VERSION 5.8 ;
BUSBITCHARS "[]" ;
DIVIDERCHAR "/" ;
UNITS
    DATABASE MICRONS 1000 ;
END UNITS

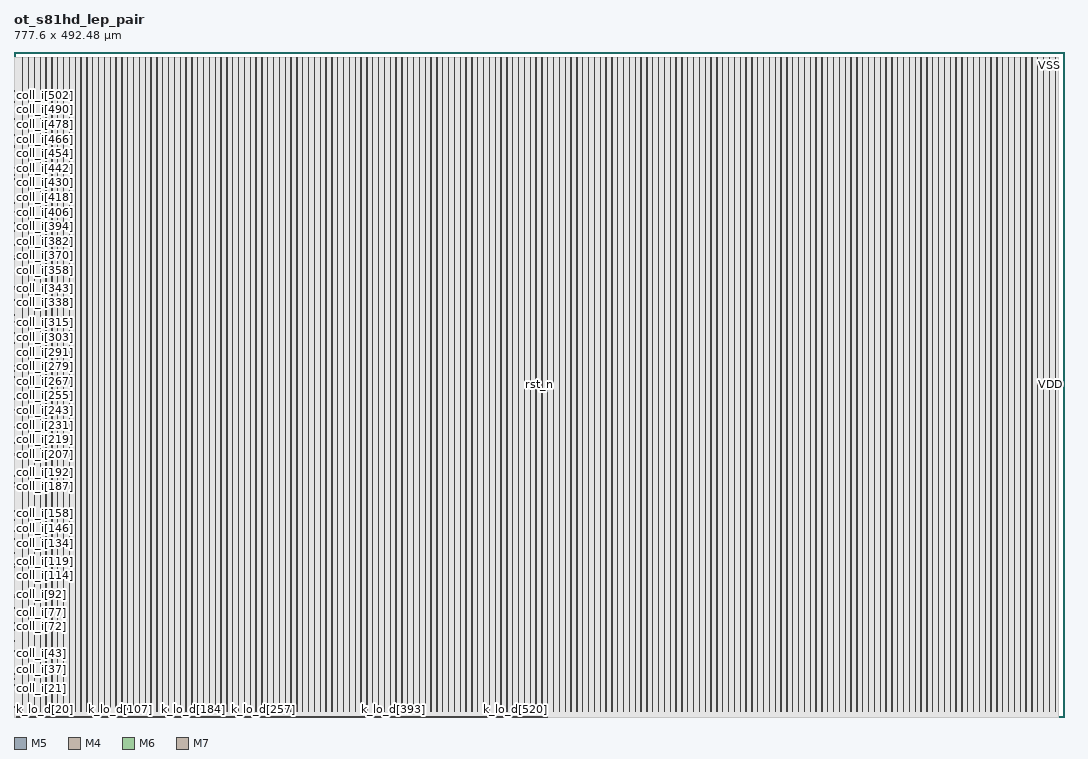
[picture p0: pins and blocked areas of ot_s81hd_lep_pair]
MACRO ot_s81hd_lep_pair
  FOREIGN ot_s81hd_lep_pair 0 0 ;
  CLASS BLOCK ;
  SIZE 777.6 BY 492.48 ;
  PIN clk
    DIRECTION INPUT ;
    USE SIGNAL ;
    PORT
      LAYER M5 ;
        RECT  388.896 246 388.944 246.48 ;
    END
  END clk
  PIN coll_i[0]
    DIRECTION INPUT ;
    USE SIGNAL ;
    PORT
      LAYER M4 ;
        RECT  0 2.028 0.192 2.052 ;
    END
  END coll_i[0]
  PIN coll_i[100]
    DIRECTION INPUT ;
    USE SIGNAL ;
    PORT
      LAYER M4 ;
        RECT  0 92.172 0.192 92.196 ;
    END
  END coll_i[100]
  PIN coll_i[101]
    DIRECTION INPUT ;
    USE SIGNAL ;
    PORT
      LAYER M4 ;
        RECT  0 93.036 0.192 93.06 ;
    END
  END coll_i[101]
  PIN coll_i[102]
    DIRECTION INPUT ;
    USE SIGNAL ;
    PORT
      LAYER M4 ;
        RECT  0 93.948 0.192 93.972 ;
    END
  END coll_i[102]
  PIN coll_i[103]
    DIRECTION INPUT ;
    USE SIGNAL ;
    PORT
      LAYER M4 ;
        RECT  0 94.86 0.192 94.884 ;
    END
  END coll_i[103]
  PIN coll_i[104]
    DIRECTION INPUT ;
    USE SIGNAL ;
    PORT
      LAYER M4 ;
        RECT  0 95.772 0.192 95.796 ;
    END
  END coll_i[104]
  PIN coll_i[105]
    DIRECTION INPUT ;
    USE SIGNAL ;
    PORT
      LAYER M4 ;
        RECT  0 96.684 0.192 96.708 ;
    END
  END coll_i[105]
  PIN coll_i[106]
    DIRECTION INPUT ;
    USE SIGNAL ;
    PORT
      LAYER M4 ;
        RECT  0 97.548 0.192 97.572 ;
    END
  END coll_i[106]
  PIN coll_i[107]
    DIRECTION INPUT ;
    USE SIGNAL ;
    PORT
      LAYER M4 ;
        RECT  0 98.46 0.192 98.484 ;
    END
  END coll_i[107]
  PIN coll_i[108]
    DIRECTION INPUT ;
    USE SIGNAL ;
    PORT
      LAYER M4 ;
        RECT  0 99.372 0.192 99.396 ;
    END
  END coll_i[108]
  PIN coll_i[109]
    DIRECTION INPUT ;
    USE SIGNAL ;
    PORT
      LAYER M4 ;
        RECT  0 100.284 0.192 100.308 ;
    END
  END coll_i[109]
  PIN coll_i[10]
    DIRECTION INPUT ;
    USE SIGNAL ;
    PORT
      LAYER M4 ;
        RECT  0 11.004 0.192 11.028 ;
    END
  END coll_i[10]
  PIN coll_i[110]
    DIRECTION INPUT ;
    USE SIGNAL ;
    PORT
      LAYER M4 ;
        RECT  0 101.148 0.192 101.172 ;
    END
  END coll_i[110]
  PIN coll_i[111]
    DIRECTION INPUT ;
    USE SIGNAL ;
    PORT
      LAYER M4 ;
        RECT  0 102.06 0.192 102.084 ;
    END
  END coll_i[111]
  PIN coll_i[112]
    DIRECTION INPUT ;
    USE SIGNAL ;
    PORT
      LAYER M4 ;
        RECT  0 102.972 0.192 102.996 ;
    END
  END coll_i[112]
  PIN coll_i[113]
    DIRECTION INPUT ;
    USE SIGNAL ;
    PORT
      LAYER M4 ;
        RECT  0 103.884 0.192 103.908 ;
    END
  END coll_i[113]
  PIN coll_i[114]
    DIRECTION INPUT ;
    USE SIGNAL ;
    PORT
      LAYER M4 ;
        RECT  0 104.796 0.192 104.82 ;
    END
  END coll_i[114]
  PIN coll_i[115]
    DIRECTION INPUT ;
    USE SIGNAL ;
    PORT
      LAYER M4 ;
        RECT  0 105.66 0.192 105.684 ;
    END
  END coll_i[115]
  PIN coll_i[116]
    DIRECTION INPUT ;
    USE SIGNAL ;
    PORT
      LAYER M4 ;
        RECT  0 106.572 0.192 106.596 ;
    END
  END coll_i[116]
  PIN coll_i[117]
    DIRECTION INPUT ;
    USE SIGNAL ;
    PORT
      LAYER M4 ;
        RECT  0 107.484 0.192 107.508 ;
    END
  END coll_i[117]
  PIN coll_i[118]
    DIRECTION INPUT ;
    USE SIGNAL ;
    PORT
      LAYER M4 ;
        RECT  0 108.396 0.192 108.42 ;
    END
  END coll_i[118]
  PIN coll_i[119]
    DIRECTION INPUT ;
    USE SIGNAL ;
    PORT
      LAYER M4 ;
        RECT  0 109.308 0.192 109.332 ;
    END
  END coll_i[119]
  PIN coll_i[11]
    DIRECTION INPUT ;
    USE SIGNAL ;
    PORT
      LAYER M4 ;
        RECT  0 11.916 0.192 11.94 ;
    END
  END coll_i[11]
  PIN coll_i[120]
    DIRECTION INPUT ;
    USE SIGNAL ;
    PORT
      LAYER M4 ;
        RECT  0 110.172 0.192 110.196 ;
    END
  END coll_i[120]
  PIN coll_i[121]
    DIRECTION INPUT ;
    USE SIGNAL ;
    PORT
      LAYER M4 ;
        RECT  0 111.084 0.192 111.108 ;
    END
  END coll_i[121]
  PIN coll_i[122]
    DIRECTION INPUT ;
    USE SIGNAL ;
    PORT
      LAYER M4 ;
        RECT  0 111.996 0.192 112.02 ;
    END
  END coll_i[122]
  PIN coll_i[123]
    DIRECTION INPUT ;
    USE SIGNAL ;
    PORT
      LAYER M4 ;
        RECT  0 112.908 0.192 112.932 ;
    END
  END coll_i[123]
  PIN coll_i[124]
    DIRECTION INPUT ;
    USE SIGNAL ;
    PORT
      LAYER M4 ;
        RECT  0 113.772 0.192 113.796 ;
    END
  END coll_i[124]
  PIN coll_i[125]
    DIRECTION INPUT ;
    USE SIGNAL ;
    PORT
      LAYER M4 ;
        RECT  0 114.684 0.192 114.708 ;
    END
  END coll_i[125]
  PIN coll_i[126]
    DIRECTION INPUT ;
    USE SIGNAL ;
    PORT
      LAYER M4 ;
        RECT  0 115.596 0.192 115.62 ;
    END
  END coll_i[126]
  PIN coll_i[127]
    DIRECTION INPUT ;
    USE SIGNAL ;
    PORT
      LAYER M4 ;
        RECT  0 116.508 0.192 116.532 ;
    END
  END coll_i[127]
  PIN coll_i[128]
    DIRECTION INPUT ;
    USE SIGNAL ;
    PORT
      LAYER M4 ;
        RECT  0 117.42 0.192 117.444 ;
    END
  END coll_i[128]
  PIN coll_i[129]
    DIRECTION INPUT ;
    USE SIGNAL ;
    PORT
      LAYER M4 ;
        RECT  0 118.284 0.192 118.308 ;
    END
  END coll_i[129]
  PIN coll_i[12]
    DIRECTION INPUT ;
    USE SIGNAL ;
    PORT
      LAYER M4 ;
        RECT  0 12.828 0.192 12.852 ;
    END
  END coll_i[12]
  PIN coll_i[130]
    DIRECTION INPUT ;
    USE SIGNAL ;
    PORT
      LAYER M4 ;
        RECT  0 119.196 0.192 119.22 ;
    END
  END coll_i[130]
  PIN coll_i[131]
    DIRECTION INPUT ;
    USE SIGNAL ;
    PORT
      LAYER M4 ;
        RECT  0 120.108 0.192 120.132 ;
    END
  END coll_i[131]
  PIN coll_i[132]
    DIRECTION INPUT ;
    USE SIGNAL ;
    PORT
      LAYER M4 ;
        RECT  0 121.02 0.192 121.044 ;
    END
  END coll_i[132]
  PIN coll_i[133]
    DIRECTION INPUT ;
    USE SIGNAL ;
    PORT
      LAYER M4 ;
        RECT  0 121.884 0.192 121.908 ;
    END
  END coll_i[133]
  PIN coll_i[134]
    DIRECTION INPUT ;
    USE SIGNAL ;
    PORT
      LAYER M4 ;
        RECT  0 122.796 0.192 122.82 ;
    END
  END coll_i[134]
  PIN coll_i[135]
    DIRECTION INPUT ;
    USE SIGNAL ;
    PORT
      LAYER M4 ;
        RECT  0 123.708 0.192 123.732 ;
    END
  END coll_i[135]
  PIN coll_i[136]
    DIRECTION INPUT ;
    USE SIGNAL ;
    PORT
      LAYER M4 ;
        RECT  0 124.62 0.192 124.644 ;
    END
  END coll_i[136]
  PIN coll_i[137]
    DIRECTION INPUT ;
    USE SIGNAL ;
    PORT
      LAYER M4 ;
        RECT  0 125.532 0.192 125.556 ;
    END
  END coll_i[137]
  PIN coll_i[138]
    DIRECTION INPUT ;
    USE SIGNAL ;
    PORT
      LAYER M4 ;
        RECT  0 126.396 0.192 126.42 ;
    END
  END coll_i[138]
  PIN coll_i[139]
    DIRECTION INPUT ;
    USE SIGNAL ;
    PORT
      LAYER M4 ;
        RECT  0 127.308 0.192 127.332 ;
    END
  END coll_i[139]
  PIN coll_i[13]
    DIRECTION INPUT ;
    USE SIGNAL ;
    PORT
      LAYER M4 ;
        RECT  0 13.74 0.192 13.764 ;
    END
  END coll_i[13]
  PIN coll_i[140]
    DIRECTION INPUT ;
    USE SIGNAL ;
    PORT
      LAYER M4 ;
        RECT  0 128.22 0.192 128.244 ;
    END
  END coll_i[140]
  PIN coll_i[141]
    DIRECTION INPUT ;
    USE SIGNAL ;
    PORT
      LAYER M4 ;
        RECT  0 129.132 0.192 129.156 ;
    END
  END coll_i[141]
  PIN coll_i[142]
    DIRECTION INPUT ;
    USE SIGNAL ;
    PORT
      LAYER M4 ;
        RECT  0 129.996 0.192 130.02 ;
    END
  END coll_i[142]
  PIN coll_i[143]
    DIRECTION INPUT ;
    USE SIGNAL ;
    PORT
      LAYER M4 ;
        RECT  0 130.908 0.192 130.932 ;
    END
  END coll_i[143]
  PIN coll_i[144]
    DIRECTION INPUT ;
    USE SIGNAL ;
    PORT
      LAYER M4 ;
        RECT  0 131.82 0.192 131.844 ;
    END
  END coll_i[144]
  PIN coll_i[145]
    DIRECTION INPUT ;
    USE SIGNAL ;
    PORT
      LAYER M4 ;
        RECT  0 132.732 0.192 132.756 ;
    END
  END coll_i[145]
  PIN coll_i[146]
    DIRECTION INPUT ;
    USE SIGNAL ;
    PORT
      LAYER M4 ;
        RECT  0 133.644 0.192 133.668 ;
    END
  END coll_i[146]
  PIN coll_i[147]
    DIRECTION INPUT ;
    USE SIGNAL ;
    PORT
      LAYER M4 ;
        RECT  0 134.508 0.192 134.532 ;
    END
  END coll_i[147]
  PIN coll_i[148]
    DIRECTION INPUT ;
    USE SIGNAL ;
    PORT
      LAYER M4 ;
        RECT  0 135.42 0.192 135.444 ;
    END
  END coll_i[148]
  PIN coll_i[149]
    DIRECTION INPUT ;
    USE SIGNAL ;
    PORT
      LAYER M4 ;
        RECT  0 136.332 0.192 136.356 ;
    END
  END coll_i[149]
  PIN coll_i[14]
    DIRECTION INPUT ;
    USE SIGNAL ;
    PORT
      LAYER M4 ;
        RECT  0 14.604 0.192 14.628 ;
    END
  END coll_i[14]
  PIN coll_i[150]
    DIRECTION INPUT ;
    USE SIGNAL ;
    PORT
      LAYER M4 ;
        RECT  0 137.244 0.192 137.268 ;
    END
  END coll_i[150]
  PIN coll_i[151]
    DIRECTION INPUT ;
    USE SIGNAL ;
    PORT
      LAYER M4 ;
        RECT  0 138.156 0.192 138.18 ;
    END
  END coll_i[151]
  PIN coll_i[152]
    DIRECTION INPUT ;
    USE SIGNAL ;
    PORT
      LAYER M4 ;
        RECT  0 139.02 0.192 139.044 ;
    END
  END coll_i[152]
  PIN coll_i[153]
    DIRECTION INPUT ;
    USE SIGNAL ;
    PORT
      LAYER M4 ;
        RECT  0 139.932 0.192 139.956 ;
    END
  END coll_i[153]
  PIN coll_i[154]
    DIRECTION INPUT ;
    USE SIGNAL ;
    PORT
      LAYER M4 ;
        RECT  0 140.844 0.192 140.868 ;
    END
  END coll_i[154]
  PIN coll_i[155]
    DIRECTION INPUT ;
    USE SIGNAL ;
    PORT
      LAYER M4 ;
        RECT  0 141.756 0.192 141.78 ;
    END
  END coll_i[155]
  PIN coll_i[156]
    DIRECTION INPUT ;
    USE SIGNAL ;
    PORT
      LAYER M4 ;
        RECT  0 142.62 0.192 142.644 ;
    END
  END coll_i[156]
  PIN coll_i[157]
    DIRECTION INPUT ;
    USE SIGNAL ;
    PORT
      LAYER M4 ;
        RECT  0 143.532 0.192 143.556 ;
    END
  END coll_i[157]
  PIN coll_i[158]
    DIRECTION INPUT ;
    USE SIGNAL ;
    PORT
      LAYER M4 ;
        RECT  0 144.444 0.192 144.468 ;
    END
  END coll_i[158]
  PIN coll_i[159]
    DIRECTION INPUT ;
    USE SIGNAL ;
    PORT
      LAYER M4 ;
        RECT  0 145.356 0.192 145.38 ;
    END
  END coll_i[159]
  PIN coll_i[15]
    DIRECTION INPUT ;
    USE SIGNAL ;
    PORT
      LAYER M4 ;
        RECT  0 15.516 0.192 15.54 ;
    END
  END coll_i[15]
  PIN coll_i[160]
    DIRECTION INPUT ;
    USE SIGNAL ;
    PORT
      LAYER M4 ;
        RECT  0 146.268 0.192 146.292 ;
    END
  END coll_i[160]
  PIN coll_i[161]
    DIRECTION INPUT ;
    USE SIGNAL ;
    PORT
      LAYER M4 ;
        RECT  0 147.132 0.192 147.156 ;
    END
  END coll_i[161]
  PIN coll_i[162]
    DIRECTION INPUT ;
    USE SIGNAL ;
    PORT
      LAYER M4 ;
        RECT  0 148.044 0.192 148.068 ;
    END
  END coll_i[162]
  PIN coll_i[163]
    DIRECTION INPUT ;
    USE SIGNAL ;
    PORT
      LAYER M4 ;
        RECT  0 148.956 0.192 148.98 ;
    END
  END coll_i[163]
  PIN coll_i[164]
    DIRECTION INPUT ;
    USE SIGNAL ;
    PORT
      LAYER M4 ;
        RECT  0 149.868 0.192 149.892 ;
    END
  END coll_i[164]
  PIN coll_i[165]
    DIRECTION INPUT ;
    USE SIGNAL ;
    PORT
      LAYER M4 ;
        RECT  0 150.732 0.192 150.756 ;
    END
  END coll_i[165]
  PIN coll_i[166]
    DIRECTION INPUT ;
    USE SIGNAL ;
    PORT
      LAYER M4 ;
        RECT  0 151.644 0.192 151.668 ;
    END
  END coll_i[166]
  PIN coll_i[167]
    DIRECTION INPUT ;
    USE SIGNAL ;
    PORT
      LAYER M4 ;
        RECT  0 152.556 0.192 152.58 ;
    END
  END coll_i[167]
  PIN coll_i[168]
    DIRECTION INPUT ;
    USE SIGNAL ;
    PORT
      LAYER M4 ;
        RECT  0 153.468 0.192 153.492 ;
    END
  END coll_i[168]
  PIN coll_i[169]
    DIRECTION INPUT ;
    USE SIGNAL ;
    PORT
      LAYER M4 ;
        RECT  0 154.38 0.192 154.404 ;
    END
  END coll_i[169]
  PIN coll_i[16]
    DIRECTION INPUT ;
    USE SIGNAL ;
    PORT
      LAYER M4 ;
        RECT  0 16.428 0.192 16.452 ;
    END
  END coll_i[16]
  PIN coll_i[170]
    DIRECTION INPUT ;
    USE SIGNAL ;
    PORT
      LAYER M4 ;
        RECT  0 155.244 0.192 155.268 ;
    END
  END coll_i[170]
  PIN coll_i[171]
    DIRECTION INPUT ;
    USE SIGNAL ;
    PORT
      LAYER M4 ;
        RECT  0 156.156 0.192 156.18 ;
    END
  END coll_i[171]
  PIN coll_i[172]
    DIRECTION INPUT ;
    USE SIGNAL ;
    PORT
      LAYER M4 ;
        RECT  0 157.068 0.192 157.092 ;
    END
  END coll_i[172]
  PIN coll_i[173]
    DIRECTION INPUT ;
    USE SIGNAL ;
    PORT
      LAYER M4 ;
        RECT  0 157.98 0.192 158.004 ;
    END
  END coll_i[173]
  PIN coll_i[174]
    DIRECTION INPUT ;
    USE SIGNAL ;
    PORT
      LAYER M4 ;
        RECT  0 158.892 0.192 158.916 ;
    END
  END coll_i[174]
  PIN coll_i[175]
    DIRECTION INPUT ;
    USE SIGNAL ;
    PORT
      LAYER M4 ;
        RECT  0 159.756 0.192 159.78 ;
    END
  END coll_i[175]
  PIN coll_i[176]
    DIRECTION INPUT ;
    USE SIGNAL ;
    PORT
      LAYER M4 ;
        RECT  0 160.668 0.192 160.692 ;
    END
  END coll_i[176]
  PIN coll_i[177]
    DIRECTION INPUT ;
    USE SIGNAL ;
    PORT
      LAYER M4 ;
        RECT  0 161.58 0.192 161.604 ;
    END
  END coll_i[177]
  PIN coll_i[178]
    DIRECTION INPUT ;
    USE SIGNAL ;
    PORT
      LAYER M4 ;
        RECT  0 162.492 0.192 162.516 ;
    END
  END coll_i[178]
  PIN coll_i[179]
    DIRECTION INPUT ;
    USE SIGNAL ;
    PORT
      LAYER M4 ;
        RECT  0 163.356 0.192 163.38 ;
    END
  END coll_i[179]
  PIN coll_i[17]
    DIRECTION INPUT ;
    USE SIGNAL ;
    PORT
      LAYER M4 ;
        RECT  0 17.34 0.192 17.364 ;
    END
  END coll_i[17]
  PIN coll_i[180]
    DIRECTION INPUT ;
    USE SIGNAL ;
    PORT
      LAYER M4 ;
        RECT  0 164.268 0.192 164.292 ;
    END
  END coll_i[180]
  PIN coll_i[181]
    DIRECTION INPUT ;
    USE SIGNAL ;
    PORT
      LAYER M4 ;
        RECT  0 165.18 0.192 165.204 ;
    END
  END coll_i[181]
  PIN coll_i[182]
    DIRECTION INPUT ;
    USE SIGNAL ;
    PORT
      LAYER M4 ;
        RECT  0 166.092 0.192 166.116 ;
    END
  END coll_i[182]
  PIN coll_i[183]
    DIRECTION INPUT ;
    USE SIGNAL ;
    PORT
      LAYER M4 ;
        RECT  0 167.004 0.192 167.028 ;
    END
  END coll_i[183]
  PIN coll_i[184]
    DIRECTION INPUT ;
    USE SIGNAL ;
    PORT
      LAYER M4 ;
        RECT  0 167.868 0.192 167.892 ;
    END
  END coll_i[184]
  PIN coll_i[185]
    DIRECTION INPUT ;
    USE SIGNAL ;
    PORT
      LAYER M4 ;
        RECT  0 168.78 0.192 168.804 ;
    END
  END coll_i[185]
  PIN coll_i[186]
    DIRECTION INPUT ;
    USE SIGNAL ;
    PORT
      LAYER M4 ;
        RECT  0 169.692 0.192 169.716 ;
    END
  END coll_i[186]
  PIN coll_i[187]
    DIRECTION INPUT ;
    USE SIGNAL ;
    PORT
      LAYER M4 ;
        RECT  0 170.604 0.192 170.628 ;
    END
  END coll_i[187]
  PIN coll_i[188]
    DIRECTION INPUT ;
    USE SIGNAL ;
    PORT
      LAYER M4 ;
        RECT  0 171.468 0.192 171.492 ;
    END
  END coll_i[188]
  PIN coll_i[189]
    DIRECTION INPUT ;
    USE SIGNAL ;
    PORT
      LAYER M4 ;
        RECT  0 172.38 0.192 172.404 ;
    END
  END coll_i[189]
  PIN coll_i[18]
    DIRECTION INPUT ;
    USE SIGNAL ;
    PORT
      LAYER M4 ;
        RECT  0 18.252 0.192 18.276 ;
    END
  END coll_i[18]
  PIN coll_i[190]
    DIRECTION INPUT ;
    USE SIGNAL ;
    PORT
      LAYER M4 ;
        RECT  0 173.292 0.192 173.316 ;
    END
  END coll_i[190]
  PIN coll_i[191]
    DIRECTION INPUT ;
    USE SIGNAL ;
    PORT
      LAYER M4 ;
        RECT  0 174.204 0.192 174.228 ;
    END
  END coll_i[191]
  PIN coll_i[192]
    DIRECTION INPUT ;
    USE SIGNAL ;
    PORT
      LAYER M4 ;
        RECT  0 175.116 0.192 175.14 ;
    END
  END coll_i[192]
  PIN coll_i[193]
    DIRECTION INPUT ;
    USE SIGNAL ;
    PORT
      LAYER M4 ;
        RECT  0 175.98 0.192 176.004 ;
    END
  END coll_i[193]
  PIN coll_i[194]
    DIRECTION INPUT ;
    USE SIGNAL ;
    PORT
      LAYER M4 ;
        RECT  0 176.892 0.192 176.916 ;
    END
  END coll_i[194]
  PIN coll_i[195]
    DIRECTION INPUT ;
    USE SIGNAL ;
    PORT
      LAYER M4 ;
        RECT  0 177.804 0.192 177.828 ;
    END
  END coll_i[195]
  PIN coll_i[196]
    DIRECTION INPUT ;
    USE SIGNAL ;
    PORT
      LAYER M4 ;
        RECT  0 178.716 0.192 178.74 ;
    END
  END coll_i[196]
  PIN coll_i[197]
    DIRECTION INPUT ;
    USE SIGNAL ;
    PORT
      LAYER M4 ;
        RECT  0 179.58 0.192 179.604 ;
    END
  END coll_i[197]
  PIN coll_i[198]
    DIRECTION INPUT ;
    USE SIGNAL ;
    PORT
      LAYER M4 ;
        RECT  0 180.492 0.192 180.516 ;
    END
  END coll_i[198]
  PIN coll_i[199]
    DIRECTION INPUT ;
    USE SIGNAL ;
    PORT
      LAYER M4 ;
        RECT  0 181.404 0.192 181.428 ;
    END
  END coll_i[199]
  PIN coll_i[19]
    DIRECTION INPUT ;
    USE SIGNAL ;
    PORT
      LAYER M4 ;
        RECT  0 19.116 0.192 19.14 ;
    END
  END coll_i[19]
  PIN coll_i[1]
    DIRECTION INPUT ;
    USE SIGNAL ;
    PORT
      LAYER M4 ;
        RECT  0 2.892 0.192 2.916 ;
    END
  END coll_i[1]
  PIN coll_i[200]
    DIRECTION INPUT ;
    USE SIGNAL ;
    PORT
      LAYER M4 ;
        RECT  0 182.316 0.192 182.34 ;
    END
  END coll_i[200]
  PIN coll_i[201]
    DIRECTION INPUT ;
    USE SIGNAL ;
    PORT
      LAYER M4 ;
        RECT  0 183.228 0.192 183.252 ;
    END
  END coll_i[201]
  PIN coll_i[202]
    DIRECTION INPUT ;
    USE SIGNAL ;
    PORT
      LAYER M4 ;
        RECT  0 184.092 0.192 184.116 ;
    END
  END coll_i[202]
  PIN coll_i[203]
    DIRECTION INPUT ;
    USE SIGNAL ;
    PORT
      LAYER M4 ;
        RECT  0 185.004 0.192 185.028 ;
    END
  END coll_i[203]
  PIN coll_i[204]
    DIRECTION INPUT ;
    USE SIGNAL ;
    PORT
      LAYER M4 ;
        RECT  0 185.916 0.192 185.94 ;
    END
  END coll_i[204]
  PIN coll_i[205]
    DIRECTION INPUT ;
    USE SIGNAL ;
    PORT
      LAYER M4 ;
        RECT  0 186.828 0.192 186.852 ;
    END
  END coll_i[205]
  PIN coll_i[206]
    DIRECTION INPUT ;
    USE SIGNAL ;
    PORT
      LAYER M4 ;
        RECT  0 187.74 0.192 187.764 ;
    END
  END coll_i[206]
  PIN coll_i[207]
    DIRECTION INPUT ;
    USE SIGNAL ;
    PORT
      LAYER M4 ;
        RECT  0 188.604 0.192 188.628 ;
    END
  END coll_i[207]
  PIN coll_i[208]
    DIRECTION INPUT ;
    USE SIGNAL ;
    PORT
      LAYER M4 ;
        RECT  0 189.516 0.192 189.54 ;
    END
  END coll_i[208]
  PIN coll_i[209]
    DIRECTION INPUT ;
    USE SIGNAL ;
    PORT
      LAYER M4 ;
        RECT  0 190.428 0.192 190.452 ;
    END
  END coll_i[209]
  PIN coll_i[20]
    DIRECTION INPUT ;
    USE SIGNAL ;
    PORT
      LAYER M4 ;
        RECT  0 20.028 0.192 20.052 ;
    END
  END coll_i[20]
  PIN coll_i[210]
    DIRECTION INPUT ;
    USE SIGNAL ;
    PORT
      LAYER M4 ;
        RECT  0 191.34 0.192 191.364 ;
    END
  END coll_i[210]
  PIN coll_i[211]
    DIRECTION INPUT ;
    USE SIGNAL ;
    PORT
      LAYER M4 ;
        RECT  0 192.204 0.192 192.228 ;
    END
  END coll_i[211]
  PIN coll_i[212]
    DIRECTION INPUT ;
    USE SIGNAL ;
    PORT
      LAYER M4 ;
        RECT  0 193.116 0.192 193.14 ;
    END
  END coll_i[212]
  PIN coll_i[213]
    DIRECTION INPUT ;
    USE SIGNAL ;
    PORT
      LAYER M4 ;
        RECT  0 194.028 0.192 194.052 ;
    END
  END coll_i[213]
  PIN coll_i[214]
    DIRECTION INPUT ;
    USE SIGNAL ;
    PORT
      LAYER M4 ;
        RECT  0 194.94 0.192 194.964 ;
    END
  END coll_i[214]
  PIN coll_i[215]
    DIRECTION INPUT ;
    USE SIGNAL ;
    PORT
      LAYER M4 ;
        RECT  0 195.852 0.192 195.876 ;
    END
  END coll_i[215]
  PIN coll_i[216]
    DIRECTION INPUT ;
    USE SIGNAL ;
    PORT
      LAYER M4 ;
        RECT  0 196.716 0.192 196.74 ;
    END
  END coll_i[216]
  PIN coll_i[217]
    DIRECTION INPUT ;
    USE SIGNAL ;
    PORT
      LAYER M4 ;
        RECT  0 197.628 0.192 197.652 ;
    END
  END coll_i[217]
  PIN coll_i[218]
    DIRECTION INPUT ;
    USE SIGNAL ;
    PORT
      LAYER M4 ;
        RECT  0 198.54 0.192 198.564 ;
    END
  END coll_i[218]
  PIN coll_i[219]
    DIRECTION INPUT ;
    USE SIGNAL ;
    PORT
      LAYER M4 ;
        RECT  0 199.452 0.192 199.476 ;
    END
  END coll_i[219]
  PIN coll_i[21]
    DIRECTION INPUT ;
    USE SIGNAL ;
    PORT
      LAYER M4 ;
        RECT  0 20.94 0.192 20.964 ;
    END
  END coll_i[21]
  PIN coll_i[220]
    DIRECTION INPUT ;
    USE SIGNAL ;
    PORT
      LAYER M4 ;
        RECT  0 200.316 0.192 200.34 ;
    END
  END coll_i[220]
  PIN coll_i[221]
    DIRECTION INPUT ;
    USE SIGNAL ;
    PORT
      LAYER M4 ;
        RECT  0 201.228 0.192 201.252 ;
    END
  END coll_i[221]
  PIN coll_i[222]
    DIRECTION INPUT ;
    USE SIGNAL ;
    PORT
      LAYER M4 ;
        RECT  0 202.14 0.192 202.164 ;
    END
  END coll_i[222]
  PIN coll_i[223]
    DIRECTION INPUT ;
    USE SIGNAL ;
    PORT
      LAYER M4 ;
        RECT  0 203.052 0.192 203.076 ;
    END
  END coll_i[223]
  PIN coll_i[224]
    DIRECTION INPUT ;
    USE SIGNAL ;
    PORT
      LAYER M4 ;
        RECT  0 203.964 0.192 203.988 ;
    END
  END coll_i[224]
  PIN coll_i[225]
    DIRECTION INPUT ;
    USE SIGNAL ;
    PORT
      LAYER M4 ;
        RECT  0 204.828 0.192 204.852 ;
    END
  END coll_i[225]
  PIN coll_i[226]
    DIRECTION INPUT ;
    USE SIGNAL ;
    PORT
      LAYER M4 ;
        RECT  0 205.74 0.192 205.764 ;
    END
  END coll_i[226]
  PIN coll_i[227]
    DIRECTION INPUT ;
    USE SIGNAL ;
    PORT
      LAYER M4 ;
        RECT  0 206.652 0.192 206.676 ;
    END
  END coll_i[227]
  PIN coll_i[228]
    DIRECTION INPUT ;
    USE SIGNAL ;
    PORT
      LAYER M4 ;
        RECT  0 207.564 0.192 207.588 ;
    END
  END coll_i[228]
  PIN coll_i[229]
    DIRECTION INPUT ;
    USE SIGNAL ;
    PORT
      LAYER M4 ;
        RECT  0 208.476 0.192 208.5 ;
    END
  END coll_i[229]
  PIN coll_i[22]
    DIRECTION INPUT ;
    USE SIGNAL ;
    PORT
      LAYER M4 ;
        RECT  0 21.852 0.192 21.876 ;
    END
  END coll_i[22]
  PIN coll_i[230]
    DIRECTION INPUT ;
    USE SIGNAL ;
    PORT
      LAYER M4 ;
        RECT  0 209.34 0.192 209.364 ;
    END
  END coll_i[230]
  PIN coll_i[231]
    DIRECTION INPUT ;
    USE SIGNAL ;
    PORT
      LAYER M4 ;
        RECT  0 210.252 0.192 210.276 ;
    END
  END coll_i[231]
  PIN coll_i[232]
    DIRECTION INPUT ;
    USE SIGNAL ;
    PORT
      LAYER M4 ;
        RECT  0 211.164 0.192 211.188 ;
    END
  END coll_i[232]
  PIN coll_i[233]
    DIRECTION INPUT ;
    USE SIGNAL ;
    PORT
      LAYER M4 ;
        RECT  0 212.076 0.192 212.1 ;
    END
  END coll_i[233]
  PIN coll_i[234]
    DIRECTION INPUT ;
    USE SIGNAL ;
    PORT
      LAYER M4 ;
        RECT  0 212.94 0.192 212.964 ;
    END
  END coll_i[234]
  PIN coll_i[235]
    DIRECTION INPUT ;
    USE SIGNAL ;
    PORT
      LAYER M4 ;
        RECT  0 213.852 0.192 213.876 ;
    END
  END coll_i[235]
  PIN coll_i[236]
    DIRECTION INPUT ;
    USE SIGNAL ;
    PORT
      LAYER M4 ;
        RECT  0 214.764 0.192 214.788 ;
    END
  END coll_i[236]
  PIN coll_i[237]
    DIRECTION INPUT ;
    USE SIGNAL ;
    PORT
      LAYER M4 ;
        RECT  0 215.676 0.192 215.7 ;
    END
  END coll_i[237]
  PIN coll_i[238]
    DIRECTION INPUT ;
    USE SIGNAL ;
    PORT
      LAYER M4 ;
        RECT  0 216.588 0.192 216.612 ;
    END
  END coll_i[238]
  PIN coll_i[239]
    DIRECTION INPUT ;
    USE SIGNAL ;
    PORT
      LAYER M4 ;
        RECT  0 217.452 0.192 217.476 ;
    END
  END coll_i[239]
  PIN coll_i[23]
    DIRECTION INPUT ;
    USE SIGNAL ;
    PORT
      LAYER M4 ;
        RECT  0 22.716 0.192 22.74 ;
    END
  END coll_i[23]
  PIN coll_i[240]
    DIRECTION INPUT ;
    USE SIGNAL ;
    PORT
      LAYER M4 ;
        RECT  0 218.364 0.192 218.388 ;
    END
  END coll_i[240]
  PIN coll_i[241]
    DIRECTION INPUT ;
    USE SIGNAL ;
    PORT
      LAYER M4 ;
        RECT  0 219.276 0.192 219.3 ;
    END
  END coll_i[241]
  PIN coll_i[242]
    DIRECTION INPUT ;
    USE SIGNAL ;
    PORT
      LAYER M4 ;
        RECT  0 220.188 0.192 220.212 ;
    END
  END coll_i[242]
  PIN coll_i[243]
    DIRECTION INPUT ;
    USE SIGNAL ;
    PORT
      LAYER M4 ;
        RECT  0 221.052 0.192 221.076 ;
    END
  END coll_i[243]
  PIN coll_i[244]
    DIRECTION INPUT ;
    USE SIGNAL ;
    PORT
      LAYER M4 ;
        RECT  0 221.964 0.192 221.988 ;
    END
  END coll_i[244]
  PIN coll_i[245]
    DIRECTION INPUT ;
    USE SIGNAL ;
    PORT
      LAYER M4 ;
        RECT  0 222.876 0.192 222.9 ;
    END
  END coll_i[245]
  PIN coll_i[246]
    DIRECTION INPUT ;
    USE SIGNAL ;
    PORT
      LAYER M4 ;
        RECT  0 223.788 0.192 223.812 ;
    END
  END coll_i[246]
  PIN coll_i[247]
    DIRECTION INPUT ;
    USE SIGNAL ;
    PORT
      LAYER M4 ;
        RECT  0 224.7 0.192 224.724 ;
    END
  END coll_i[247]
  PIN coll_i[248]
    DIRECTION INPUT ;
    USE SIGNAL ;
    PORT
      LAYER M4 ;
        RECT  0 225.564 0.192 225.588 ;
    END
  END coll_i[248]
  PIN coll_i[249]
    DIRECTION INPUT ;
    USE SIGNAL ;
    PORT
      LAYER M4 ;
        RECT  0 226.476 0.192 226.5 ;
    END
  END coll_i[249]
  PIN coll_i[24]
    DIRECTION INPUT ;
    USE SIGNAL ;
    PORT
      LAYER M4 ;
        RECT  0 23.628 0.192 23.652 ;
    END
  END coll_i[24]
  PIN coll_i[250]
    DIRECTION INPUT ;
    USE SIGNAL ;
    PORT
      LAYER M4 ;
        RECT  0 227.388 0.192 227.412 ;
    END
  END coll_i[250]
  PIN coll_i[251]
    DIRECTION INPUT ;
    USE SIGNAL ;
    PORT
      LAYER M4 ;
        RECT  0 228.3 0.192 228.324 ;
    END
  END coll_i[251]
  PIN coll_i[252]
    DIRECTION INPUT ;
    USE SIGNAL ;
    PORT
      LAYER M4 ;
        RECT  0 229.164 0.192 229.188 ;
    END
  END coll_i[252]
  PIN coll_i[253]
    DIRECTION INPUT ;
    USE SIGNAL ;
    PORT
      LAYER M4 ;
        RECT  0 230.076 0.192 230.1 ;
    END
  END coll_i[253]
  PIN coll_i[254]
    DIRECTION INPUT ;
    USE SIGNAL ;
    PORT
      LAYER M4 ;
        RECT  0 230.988 0.192 231.012 ;
    END
  END coll_i[254]
  PIN coll_i[255]
    DIRECTION INPUT ;
    USE SIGNAL ;
    PORT
      LAYER M4 ;
        RECT  0 231.9 0.192 231.924 ;
    END
  END coll_i[255]
  PIN coll_i[256]
    DIRECTION INPUT ;
    USE SIGNAL ;
    PORT
      LAYER M4 ;
        RECT  0 232.812 0.192 232.836 ;
    END
  END coll_i[256]
  PIN coll_i[257]
    DIRECTION INPUT ;
    USE SIGNAL ;
    PORT
      LAYER M4 ;
        RECT  0 233.676 0.192 233.7 ;
    END
  END coll_i[257]
  PIN coll_i[258]
    DIRECTION INPUT ;
    USE SIGNAL ;
    PORT
      LAYER M4 ;
        RECT  0 234.588 0.192 234.612 ;
    END
  END coll_i[258]
  PIN coll_i[259]
    DIRECTION INPUT ;
    USE SIGNAL ;
    PORT
      LAYER M4 ;
        RECT  0 235.5 0.192 235.524 ;
    END
  END coll_i[259]
  PIN coll_i[25]
    DIRECTION INPUT ;
    USE SIGNAL ;
    PORT
      LAYER M4 ;
        RECT  0 24.54 0.192 24.564 ;
    END
  END coll_i[25]
  PIN coll_i[260]
    DIRECTION INPUT ;
    USE SIGNAL ;
    PORT
      LAYER M4 ;
        RECT  0 236.412 0.192 236.436 ;
    END
  END coll_i[260]
  PIN coll_i[261]
    DIRECTION INPUT ;
    USE SIGNAL ;
    PORT
      LAYER M4 ;
        RECT  0 237.324 0.192 237.348 ;
    END
  END coll_i[261]
  PIN coll_i[262]
    DIRECTION INPUT ;
    USE SIGNAL ;
    PORT
      LAYER M4 ;
        RECT  0 238.188 0.192 238.212 ;
    END
  END coll_i[262]
  PIN coll_i[263]
    DIRECTION INPUT ;
    USE SIGNAL ;
    PORT
      LAYER M4 ;
        RECT  0 239.1 0.192 239.124 ;
    END
  END coll_i[263]
  PIN coll_i[264]
    DIRECTION INPUT ;
    USE SIGNAL ;
    PORT
      LAYER M4 ;
        RECT  0 240.012 0.192 240.036 ;
    END
  END coll_i[264]
  PIN coll_i[265]
    DIRECTION INPUT ;
    USE SIGNAL ;
    PORT
      LAYER M4 ;
        RECT  0 240.924 0.192 240.948 ;
    END
  END coll_i[265]
  PIN coll_i[266]
    DIRECTION INPUT ;
    USE SIGNAL ;
    PORT
      LAYER M4 ;
        RECT  0 241.788 0.192 241.812 ;
    END
  END coll_i[266]
  PIN coll_i[267]
    DIRECTION INPUT ;
    USE SIGNAL ;
    PORT
      LAYER M4 ;
        RECT  0 242.7 0.192 242.724 ;
    END
  END coll_i[267]
  PIN coll_i[268]
    DIRECTION INPUT ;
    USE SIGNAL ;
    PORT
      LAYER M4 ;
        RECT  0 243.612 0.192 243.636 ;
    END
  END coll_i[268]
  PIN coll_i[269]
    DIRECTION INPUT ;
    USE SIGNAL ;
    PORT
      LAYER M4 ;
        RECT  0 244.524 0.192 244.548 ;
    END
  END coll_i[269]
  PIN coll_i[26]
    DIRECTION INPUT ;
    USE SIGNAL ;
    PORT
      LAYER M4 ;
        RECT  0 25.452 0.192 25.476 ;
    END
  END coll_i[26]
  PIN coll_i[270]
    DIRECTION INPUT ;
    USE SIGNAL ;
    PORT
      LAYER M4 ;
        RECT  0 245.436 0.192 245.46 ;
    END
  END coll_i[270]
  PIN coll_i[271]
    DIRECTION INPUT ;
    USE SIGNAL ;
    PORT
      LAYER M4 ;
        RECT  0 246.3 0.192 246.324 ;
    END
  END coll_i[271]
  PIN coll_i[272]
    DIRECTION INPUT ;
    USE SIGNAL ;
    PORT
      LAYER M4 ;
        RECT  0 247.212 0.192 247.236 ;
    END
  END coll_i[272]
  PIN coll_i[273]
    DIRECTION INPUT ;
    USE SIGNAL ;
    PORT
      LAYER M4 ;
        RECT  0 248.124 0.192 248.148 ;
    END
  END coll_i[273]
  PIN coll_i[274]
    DIRECTION INPUT ;
    USE SIGNAL ;
    PORT
      LAYER M4 ;
        RECT  0 249.036 0.192 249.06 ;
    END
  END coll_i[274]
  PIN coll_i[275]
    DIRECTION INPUT ;
    USE SIGNAL ;
    PORT
      LAYER M4 ;
        RECT  0 249.9 0.192 249.924 ;
    END
  END coll_i[275]
  PIN coll_i[276]
    DIRECTION INPUT ;
    USE SIGNAL ;
    PORT
      LAYER M4 ;
        RECT  0 250.812 0.192 250.836 ;
    END
  END coll_i[276]
  PIN coll_i[277]
    DIRECTION INPUT ;
    USE SIGNAL ;
    PORT
      LAYER M4 ;
        RECT  0 251.724 0.192 251.748 ;
    END
  END coll_i[277]
  PIN coll_i[278]
    DIRECTION INPUT ;
    USE SIGNAL ;
    PORT
      LAYER M4 ;
        RECT  0 252.636 0.192 252.66 ;
    END
  END coll_i[278]
  PIN coll_i[279]
    DIRECTION INPUT ;
    USE SIGNAL ;
    PORT
      LAYER M4 ;
        RECT  0 253.548 0.192 253.572 ;
    END
  END coll_i[279]
  PIN coll_i[27]
    DIRECTION INPUT ;
    USE SIGNAL ;
    PORT
      LAYER M4 ;
        RECT  0 26.364 0.192 26.388 ;
    END
  END coll_i[27]
  PIN coll_i[280]
    DIRECTION INPUT ;
    USE SIGNAL ;
    PORT
      LAYER M4 ;
        RECT  0 254.412 0.192 254.436 ;
    END
  END coll_i[280]
  PIN coll_i[281]
    DIRECTION INPUT ;
    USE SIGNAL ;
    PORT
      LAYER M4 ;
        RECT  0 255.324 0.192 255.348 ;
    END
  END coll_i[281]
  PIN coll_i[282]
    DIRECTION INPUT ;
    USE SIGNAL ;
    PORT
      LAYER M4 ;
        RECT  0 256.236 0.192 256.26 ;
    END
  END coll_i[282]
  PIN coll_i[283]
    DIRECTION INPUT ;
    USE SIGNAL ;
    PORT
      LAYER M4 ;
        RECT  0 257.148 0.192 257.172 ;
    END
  END coll_i[283]
  PIN coll_i[284]
    DIRECTION INPUT ;
    USE SIGNAL ;
    PORT
      LAYER M4 ;
        RECT  0 258.012 0.192 258.036 ;
    END
  END coll_i[284]
  PIN coll_i[285]
    DIRECTION INPUT ;
    USE SIGNAL ;
    PORT
      LAYER M4 ;
        RECT  0 258.924 0.192 258.948 ;
    END
  END coll_i[285]
  PIN coll_i[286]
    DIRECTION INPUT ;
    USE SIGNAL ;
    PORT
      LAYER M4 ;
        RECT  0 259.836 0.192 259.86 ;
    END
  END coll_i[286]
  PIN coll_i[287]
    DIRECTION INPUT ;
    USE SIGNAL ;
    PORT
      LAYER M4 ;
        RECT  0 260.748 0.192 260.772 ;
    END
  END coll_i[287]
  PIN coll_i[288]
    DIRECTION INPUT ;
    USE SIGNAL ;
    PORT
      LAYER M4 ;
        RECT  0 261.66 0.192 261.684 ;
    END
  END coll_i[288]
  PIN coll_i[289]
    DIRECTION INPUT ;
    USE SIGNAL ;
    PORT
      LAYER M4 ;
        RECT  0 262.524 0.192 262.548 ;
    END
  END coll_i[289]
  PIN coll_i[28]
    DIRECTION INPUT ;
    USE SIGNAL ;
    PORT
      LAYER M4 ;
        RECT  0 27.228 0.192 27.252 ;
    END
  END coll_i[28]
  PIN coll_i[290]
    DIRECTION INPUT ;
    USE SIGNAL ;
    PORT
      LAYER M4 ;
        RECT  0 263.436 0.192 263.46 ;
    END
  END coll_i[290]
  PIN coll_i[291]
    DIRECTION INPUT ;
    USE SIGNAL ;
    PORT
      LAYER M4 ;
        RECT  0 264.348 0.192 264.372 ;
    END
  END coll_i[291]
  PIN coll_i[292]
    DIRECTION INPUT ;
    USE SIGNAL ;
    PORT
      LAYER M4 ;
        RECT  0 265.26 0.192 265.284 ;
    END
  END coll_i[292]
  PIN coll_i[293]
    DIRECTION INPUT ;
    USE SIGNAL ;
    PORT
      LAYER M4 ;
        RECT  0 266.172 0.192 266.196 ;
    END
  END coll_i[293]
  PIN coll_i[294]
    DIRECTION INPUT ;
    USE SIGNAL ;
    PORT
      LAYER M4 ;
        RECT  0 267.036 0.192 267.06 ;
    END
  END coll_i[294]
  PIN coll_i[295]
    DIRECTION INPUT ;
    USE SIGNAL ;
    PORT
      LAYER M4 ;
        RECT  0 267.948 0.192 267.972 ;
    END
  END coll_i[295]
  PIN coll_i[296]
    DIRECTION INPUT ;
    USE SIGNAL ;
    PORT
      LAYER M4 ;
        RECT  0 268.86 0.192 268.884 ;
    END
  END coll_i[296]
  PIN coll_i[297]
    DIRECTION INPUT ;
    USE SIGNAL ;
    PORT
      LAYER M4 ;
        RECT  0 269.772 0.192 269.796 ;
    END
  END coll_i[297]
  PIN coll_i[298]
    DIRECTION INPUT ;
    USE SIGNAL ;
    PORT
      LAYER M4 ;
        RECT  0 270.636 0.192 270.66 ;
    END
  END coll_i[298]
  PIN coll_i[299]
    DIRECTION INPUT ;
    USE SIGNAL ;
    PORT
      LAYER M4 ;
        RECT  0 271.548 0.192 271.572 ;
    END
  END coll_i[299]
  PIN coll_i[29]
    DIRECTION INPUT ;
    USE SIGNAL ;
    PORT
      LAYER M4 ;
        RECT  0 28.14 0.192 28.164 ;
    END
  END coll_i[29]
  PIN coll_i[2]
    DIRECTION INPUT ;
    USE SIGNAL ;
    PORT
      LAYER M4 ;
        RECT  0 3.804 0.192 3.828 ;
    END
  END coll_i[2]
  PIN coll_i[300]
    DIRECTION INPUT ;
    USE SIGNAL ;
    PORT
      LAYER M4 ;
        RECT  0 272.46 0.192 272.484 ;
    END
  END coll_i[300]
  PIN coll_i[301]
    DIRECTION INPUT ;
    USE SIGNAL ;
    PORT
      LAYER M4 ;
        RECT  0 273.372 0.192 273.396 ;
    END
  END coll_i[301]
  PIN coll_i[302]
    DIRECTION INPUT ;
    USE SIGNAL ;
    PORT
      LAYER M4 ;
        RECT  0 274.284 0.192 274.308 ;
    END
  END coll_i[302]
  PIN coll_i[303]
    DIRECTION INPUT ;
    USE SIGNAL ;
    PORT
      LAYER M4 ;
        RECT  0 275.148 0.192 275.172 ;
    END
  END coll_i[303]
  PIN coll_i[304]
    DIRECTION INPUT ;
    USE SIGNAL ;
    PORT
      LAYER M4 ;
        RECT  0 276.06 0.192 276.084 ;
    END
  END coll_i[304]
  PIN coll_i[305]
    DIRECTION INPUT ;
    USE SIGNAL ;
    PORT
      LAYER M4 ;
        RECT  0 276.972 0.192 276.996 ;
    END
  END coll_i[305]
  PIN coll_i[306]
    DIRECTION INPUT ;
    USE SIGNAL ;
    PORT
      LAYER M4 ;
        RECT  0 277.884 0.192 277.908 ;
    END
  END coll_i[306]
  PIN coll_i[307]
    DIRECTION INPUT ;
    USE SIGNAL ;
    PORT
      LAYER M4 ;
        RECT  0 278.748 0.192 278.772 ;
    END
  END coll_i[307]
  PIN coll_i[308]
    DIRECTION INPUT ;
    USE SIGNAL ;
    PORT
      LAYER M4 ;
        RECT  0 279.66 0.192 279.684 ;
    END
  END coll_i[308]
  PIN coll_i[309]
    DIRECTION INPUT ;
    USE SIGNAL ;
    PORT
      LAYER M4 ;
        RECT  0 280.572 0.192 280.596 ;
    END
  END coll_i[309]
  PIN coll_i[30]
    DIRECTION INPUT ;
    USE SIGNAL ;
    PORT
      LAYER M4 ;
        RECT  0 29.052 0.192 29.076 ;
    END
  END coll_i[30]
  PIN coll_i[310]
    DIRECTION INPUT ;
    USE SIGNAL ;
    PORT
      LAYER M4 ;
        RECT  0 281.484 0.192 281.508 ;
    END
  END coll_i[310]
  PIN coll_i[311]
    DIRECTION INPUT ;
    USE SIGNAL ;
    PORT
      LAYER M4 ;
        RECT  0 282.396 0.192 282.42 ;
    END
  END coll_i[311]
  PIN coll_i[312]
    DIRECTION INPUT ;
    USE SIGNAL ;
    PORT
      LAYER M4 ;
        RECT  0 283.26 0.192 283.284 ;
    END
  END coll_i[312]
  PIN coll_i[313]
    DIRECTION INPUT ;
    USE SIGNAL ;
    PORT
      LAYER M4 ;
        RECT  0 284.172 0.192 284.196 ;
    END
  END coll_i[313]
  PIN coll_i[314]
    DIRECTION INPUT ;
    USE SIGNAL ;
    PORT
      LAYER M4 ;
        RECT  0 285.084 0.192 285.108 ;
    END
  END coll_i[314]
  PIN coll_i[315]
    DIRECTION INPUT ;
    USE SIGNAL ;
    PORT
      LAYER M4 ;
        RECT  0 285.996 0.192 286.02 ;
    END
  END coll_i[315]
  PIN coll_i[316]
    DIRECTION INPUT ;
    USE SIGNAL ;
    PORT
      LAYER M4 ;
        RECT  0 286.908 0.192 286.932 ;
    END
  END coll_i[316]
  PIN coll_i[317]
    DIRECTION INPUT ;
    USE SIGNAL ;
    PORT
      LAYER M4 ;
        RECT  0 287.772 0.192 287.796 ;
    END
  END coll_i[317]
  PIN coll_i[318]
    DIRECTION INPUT ;
    USE SIGNAL ;
    PORT
      LAYER M4 ;
        RECT  0 288.684 0.192 288.708 ;
    END
  END coll_i[318]
  PIN coll_i[319]
    DIRECTION INPUT ;
    USE SIGNAL ;
    PORT
      LAYER M4 ;
        RECT  0 289.596 0.192 289.62 ;
    END
  END coll_i[319]
  PIN coll_i[31]
    DIRECTION INPUT ;
    USE SIGNAL ;
    PORT
      LAYER M4 ;
        RECT  0 29.964 0.192 29.988 ;
    END
  END coll_i[31]
  PIN coll_i[320]
    DIRECTION INPUT ;
    USE SIGNAL ;
    PORT
      LAYER M4 ;
        RECT  0 290.508 0.192 290.532 ;
    END
  END coll_i[320]
  PIN coll_i[321]
    DIRECTION INPUT ;
    USE SIGNAL ;
    PORT
      LAYER M4 ;
        RECT  0 291.372 0.192 291.396 ;
    END
  END coll_i[321]
  PIN coll_i[322]
    DIRECTION INPUT ;
    USE SIGNAL ;
    PORT
      LAYER M4 ;
        RECT  0 292.284 0.192 292.308 ;
    END
  END coll_i[322]
  PIN coll_i[323]
    DIRECTION INPUT ;
    USE SIGNAL ;
    PORT
      LAYER M4 ;
        RECT  0 293.196 0.192 293.22 ;
    END
  END coll_i[323]
  PIN coll_i[324]
    DIRECTION INPUT ;
    USE SIGNAL ;
    PORT
      LAYER M4 ;
        RECT  0 294.108 0.192 294.132 ;
    END
  END coll_i[324]
  PIN coll_i[325]
    DIRECTION INPUT ;
    USE SIGNAL ;
    PORT
      LAYER M4 ;
        RECT  0 295.02 0.192 295.044 ;
    END
  END coll_i[325]
  PIN coll_i[326]
    DIRECTION INPUT ;
    USE SIGNAL ;
    PORT
      LAYER M4 ;
        RECT  0 295.884 0.192 295.908 ;
    END
  END coll_i[326]
  PIN coll_i[327]
    DIRECTION INPUT ;
    USE SIGNAL ;
    PORT
      LAYER M4 ;
        RECT  0 296.796 0.192 296.82 ;
    END
  END coll_i[327]
  PIN coll_i[328]
    DIRECTION INPUT ;
    USE SIGNAL ;
    PORT
      LAYER M4 ;
        RECT  0 297.708 0.192 297.732 ;
    END
  END coll_i[328]
  PIN coll_i[329]
    DIRECTION INPUT ;
    USE SIGNAL ;
    PORT
      LAYER M4 ;
        RECT  0 298.62 0.192 298.644 ;
    END
  END coll_i[329]
  PIN coll_i[32]
    DIRECTION INPUT ;
    USE SIGNAL ;
    PORT
      LAYER M4 ;
        RECT  0 30.876 0.192 30.9 ;
    END
  END coll_i[32]
  PIN coll_i[330]
    DIRECTION INPUT ;
    USE SIGNAL ;
    PORT
      LAYER M4 ;
        RECT  0 299.484 0.192 299.508 ;
    END
  END coll_i[330]
  PIN coll_i[331]
    DIRECTION INPUT ;
    USE SIGNAL ;
    PORT
      LAYER M4 ;
        RECT  0 300.396 0.192 300.42 ;
    END
  END coll_i[331]
  PIN coll_i[332]
    DIRECTION INPUT ;
    USE SIGNAL ;
    PORT
      LAYER M4 ;
        RECT  0 301.308 0.192 301.332 ;
    END
  END coll_i[332]
  PIN coll_i[333]
    DIRECTION INPUT ;
    USE SIGNAL ;
    PORT
      LAYER M4 ;
        RECT  0 302.22 0.192 302.244 ;
    END
  END coll_i[333]
  PIN coll_i[334]
    DIRECTION INPUT ;
    USE SIGNAL ;
    PORT
      LAYER M4 ;
        RECT  0 303.132 0.192 303.156 ;
    END
  END coll_i[334]
  PIN coll_i[335]
    DIRECTION INPUT ;
    USE SIGNAL ;
    PORT
      LAYER M4 ;
        RECT  0 303.996 0.192 304.02 ;
    END
  END coll_i[335]
  PIN coll_i[336]
    DIRECTION INPUT ;
    USE SIGNAL ;
    PORT
      LAYER M4 ;
        RECT  0 304.908 0.192 304.932 ;
    END
  END coll_i[336]
  PIN coll_i[337]
    DIRECTION INPUT ;
    USE SIGNAL ;
    PORT
      LAYER M4 ;
        RECT  0 305.82 0.192 305.844 ;
    END
  END coll_i[337]
  PIN coll_i[338]
    DIRECTION INPUT ;
    USE SIGNAL ;
    PORT
      LAYER M4 ;
        RECT  0 306.732 0.192 306.756 ;
    END
  END coll_i[338]
  PIN coll_i[339]
    DIRECTION INPUT ;
    USE SIGNAL ;
    PORT
      LAYER M4 ;
        RECT  0 307.596 0.192 307.62 ;
    END
  END coll_i[339]
  PIN coll_i[33]
    DIRECTION INPUT ;
    USE SIGNAL ;
    PORT
      LAYER M4 ;
        RECT  0 31.74 0.192 31.764 ;
    END
  END coll_i[33]
  PIN coll_i[340]
    DIRECTION INPUT ;
    USE SIGNAL ;
    PORT
      LAYER M4 ;
        RECT  0 308.508 0.192 308.532 ;
    END
  END coll_i[340]
  PIN coll_i[341]
    DIRECTION INPUT ;
    USE SIGNAL ;
    PORT
      LAYER M4 ;
        RECT  0 309.42 0.192 309.444 ;
    END
  END coll_i[341]
  PIN coll_i[342]
    DIRECTION INPUT ;
    USE SIGNAL ;
    PORT
      LAYER M4 ;
        RECT  0 310.332 0.192 310.356 ;
    END
  END coll_i[342]
  PIN coll_i[343]
    DIRECTION INPUT ;
    USE SIGNAL ;
    PORT
      LAYER M4 ;
        RECT  0 311.244 0.192 311.268 ;
    END
  END coll_i[343]
  PIN coll_i[344]
    DIRECTION INPUT ;
    USE SIGNAL ;
    PORT
      LAYER M4 ;
        RECT  0 312.108 0.192 312.132 ;
    END
  END coll_i[344]
  PIN coll_i[345]
    DIRECTION INPUT ;
    USE SIGNAL ;
    PORT
      LAYER M4 ;
        RECT  0 313.02 0.192 313.044 ;
    END
  END coll_i[345]
  PIN coll_i[346]
    DIRECTION INPUT ;
    USE SIGNAL ;
    PORT
      LAYER M4 ;
        RECT  0 313.932 0.192 313.956 ;
    END
  END coll_i[346]
  PIN coll_i[347]
    DIRECTION INPUT ;
    USE SIGNAL ;
    PORT
      LAYER M4 ;
        RECT  0 314.844 0.192 314.868 ;
    END
  END coll_i[347]
  PIN coll_i[348]
    DIRECTION INPUT ;
    USE SIGNAL ;
    PORT
      LAYER M4 ;
        RECT  0 315.756 0.192 315.78 ;
    END
  END coll_i[348]
  PIN coll_i[349]
    DIRECTION INPUT ;
    USE SIGNAL ;
    PORT
      LAYER M4 ;
        RECT  0 316.62 0.192 316.644 ;
    END
  END coll_i[349]
  PIN coll_i[34]
    DIRECTION INPUT ;
    USE SIGNAL ;
    PORT
      LAYER M4 ;
        RECT  0 32.652 0.192 32.676 ;
    END
  END coll_i[34]
  PIN coll_i[350]
    DIRECTION INPUT ;
    USE SIGNAL ;
    PORT
      LAYER M4 ;
        RECT  0 317.532 0.192 317.556 ;
    END
  END coll_i[350]
  PIN coll_i[351]
    DIRECTION INPUT ;
    USE SIGNAL ;
    PORT
      LAYER M4 ;
        RECT  0 318.444 0.192 318.468 ;
    END
  END coll_i[351]
  PIN coll_i[352]
    DIRECTION INPUT ;
    USE SIGNAL ;
    PORT
      LAYER M4 ;
        RECT  0 319.356 0.192 319.38 ;
    END
  END coll_i[352]
  PIN coll_i[353]
    DIRECTION INPUT ;
    USE SIGNAL ;
    PORT
      LAYER M4 ;
        RECT  0 320.22 0.192 320.244 ;
    END
  END coll_i[353]
  PIN coll_i[354]
    DIRECTION INPUT ;
    USE SIGNAL ;
    PORT
      LAYER M4 ;
        RECT  0 321.132 0.192 321.156 ;
    END
  END coll_i[354]
  PIN coll_i[355]
    DIRECTION INPUT ;
    USE SIGNAL ;
    PORT
      LAYER M4 ;
        RECT  0 322.044 0.192 322.068 ;
    END
  END coll_i[355]
  PIN coll_i[356]
    DIRECTION INPUT ;
    USE SIGNAL ;
    PORT
      LAYER M4 ;
        RECT  0 322.956 0.192 322.98 ;
    END
  END coll_i[356]
  PIN coll_i[357]
    DIRECTION INPUT ;
    USE SIGNAL ;
    PORT
      LAYER M4 ;
        RECT  0 323.868 0.192 323.892 ;
    END
  END coll_i[357]
  PIN coll_i[358]
    DIRECTION INPUT ;
    USE SIGNAL ;
    PORT
      LAYER M4 ;
        RECT  0 324.732 0.192 324.756 ;
    END
  END coll_i[358]
  PIN coll_i[359]
    DIRECTION INPUT ;
    USE SIGNAL ;
    PORT
      LAYER M4 ;
        RECT  0 325.644 0.192 325.668 ;
    END
  END coll_i[359]
  PIN coll_i[35]
    DIRECTION INPUT ;
    USE SIGNAL ;
    PORT
      LAYER M4 ;
        RECT  0 33.564 0.192 33.588 ;
    END
  END coll_i[35]
  PIN coll_i[360]
    DIRECTION INPUT ;
    USE SIGNAL ;
    PORT
      LAYER M4 ;
        RECT  0 326.556 0.192 326.58 ;
    END
  END coll_i[360]
  PIN coll_i[361]
    DIRECTION INPUT ;
    USE SIGNAL ;
    PORT
      LAYER M4 ;
        RECT  0 327.468 0.192 327.492 ;
    END
  END coll_i[361]
  PIN coll_i[362]
    DIRECTION INPUT ;
    USE SIGNAL ;
    PORT
      LAYER M4 ;
        RECT  0 328.332 0.192 328.356 ;
    END
  END coll_i[362]
  PIN coll_i[363]
    DIRECTION INPUT ;
    USE SIGNAL ;
    PORT
      LAYER M4 ;
        RECT  0 329.244 0.192 329.268 ;
    END
  END coll_i[363]
  PIN coll_i[364]
    DIRECTION INPUT ;
    USE SIGNAL ;
    PORT
      LAYER M4 ;
        RECT  0 330.156 0.192 330.18 ;
    END
  END coll_i[364]
  PIN coll_i[365]
    DIRECTION INPUT ;
    USE SIGNAL ;
    PORT
      LAYER M4 ;
        RECT  0 331.068 0.192 331.092 ;
    END
  END coll_i[365]
  PIN coll_i[366]
    DIRECTION INPUT ;
    USE SIGNAL ;
    PORT
      LAYER M4 ;
        RECT  0 331.98 0.192 332.004 ;
    END
  END coll_i[366]
  PIN coll_i[367]
    DIRECTION INPUT ;
    USE SIGNAL ;
    PORT
      LAYER M4 ;
        RECT  0 332.844 0.192 332.868 ;
    END
  END coll_i[367]
  PIN coll_i[368]
    DIRECTION INPUT ;
    USE SIGNAL ;
    PORT
      LAYER M4 ;
        RECT  0 333.756 0.192 333.78 ;
    END
  END coll_i[368]
  PIN coll_i[369]
    DIRECTION INPUT ;
    USE SIGNAL ;
    PORT
      LAYER M4 ;
        RECT  0 334.668 0.192 334.692 ;
    END
  END coll_i[369]
  PIN coll_i[36]
    DIRECTION INPUT ;
    USE SIGNAL ;
    PORT
      LAYER M4 ;
        RECT  0 34.476 0.192 34.5 ;
    END
  END coll_i[36]
  PIN coll_i[370]
    DIRECTION INPUT ;
    USE SIGNAL ;
    PORT
      LAYER M4 ;
        RECT  0 335.58 0.192 335.604 ;
    END
  END coll_i[370]
  PIN coll_i[371]
    DIRECTION INPUT ;
    USE SIGNAL ;
    PORT
      LAYER M4 ;
        RECT  0 336.492 0.192 336.516 ;
    END
  END coll_i[371]
  PIN coll_i[372]
    DIRECTION INPUT ;
    USE SIGNAL ;
    PORT
      LAYER M4 ;
        RECT  0 337.356 0.192 337.38 ;
    END
  END coll_i[372]
  PIN coll_i[373]
    DIRECTION INPUT ;
    USE SIGNAL ;
    PORT
      LAYER M4 ;
        RECT  0 338.268 0.192 338.292 ;
    END
  END coll_i[373]
  PIN coll_i[374]
    DIRECTION INPUT ;
    USE SIGNAL ;
    PORT
      LAYER M4 ;
        RECT  0 339.18 0.192 339.204 ;
    END
  END coll_i[374]
  PIN coll_i[375]
    DIRECTION INPUT ;
    USE SIGNAL ;
    PORT
      LAYER M4 ;
        RECT  0 340.092 0.192 340.116 ;
    END
  END coll_i[375]
  PIN coll_i[376]
    DIRECTION INPUT ;
    USE SIGNAL ;
    PORT
      LAYER M4 ;
        RECT  0 340.956 0.192 340.98 ;
    END
  END coll_i[376]
  PIN coll_i[377]
    DIRECTION INPUT ;
    USE SIGNAL ;
    PORT
      LAYER M4 ;
        RECT  0 341.868 0.192 341.892 ;
    END
  END coll_i[377]
  PIN coll_i[378]
    DIRECTION INPUT ;
    USE SIGNAL ;
    PORT
      LAYER M4 ;
        RECT  0 342.78 0.192 342.804 ;
    END
  END coll_i[378]
  PIN coll_i[379]
    DIRECTION INPUT ;
    USE SIGNAL ;
    PORT
      LAYER M4 ;
        RECT  0 343.692 0.192 343.716 ;
    END
  END coll_i[379]
  PIN coll_i[37]
    DIRECTION INPUT ;
    USE SIGNAL ;
    PORT
      LAYER M4 ;
        RECT  0 35.34 0.192 35.364 ;
    END
  END coll_i[37]
  PIN coll_i[380]
    DIRECTION INPUT ;
    USE SIGNAL ;
    PORT
      LAYER M4 ;
        RECT  0 344.604 0.192 344.628 ;
    END
  END coll_i[380]
  PIN coll_i[381]
    DIRECTION INPUT ;
    USE SIGNAL ;
    PORT
      LAYER M4 ;
        RECT  0 345.468 0.192 345.492 ;
    END
  END coll_i[381]
  PIN coll_i[382]
    DIRECTION INPUT ;
    USE SIGNAL ;
    PORT
      LAYER M4 ;
        RECT  0 346.38 0.192 346.404 ;
    END
  END coll_i[382]
  PIN coll_i[383]
    DIRECTION INPUT ;
    USE SIGNAL ;
    PORT
      LAYER M4 ;
        RECT  0 347.292 0.192 347.316 ;
    END
  END coll_i[383]
  PIN coll_i[384]
    DIRECTION INPUT ;
    USE SIGNAL ;
    PORT
      LAYER M4 ;
        RECT  0 348.204 0.192 348.228 ;
    END
  END coll_i[384]
  PIN coll_i[385]
    DIRECTION INPUT ;
    USE SIGNAL ;
    PORT
      LAYER M4 ;
        RECT  0 349.068 0.192 349.092 ;
    END
  END coll_i[385]
  PIN coll_i[386]
    DIRECTION INPUT ;
    USE SIGNAL ;
    PORT
      LAYER M4 ;
        RECT  0 349.98 0.192 350.004 ;
    END
  END coll_i[386]
  PIN coll_i[387]
    DIRECTION INPUT ;
    USE SIGNAL ;
    PORT
      LAYER M4 ;
        RECT  0 350.892 0.192 350.916 ;
    END
  END coll_i[387]
  PIN coll_i[388]
    DIRECTION INPUT ;
    USE SIGNAL ;
    PORT
      LAYER M4 ;
        RECT  0 351.804 0.192 351.828 ;
    END
  END coll_i[388]
  PIN coll_i[389]
    DIRECTION INPUT ;
    USE SIGNAL ;
    PORT
      LAYER M4 ;
        RECT  0 352.716 0.192 352.74 ;
    END
  END coll_i[389]
  PIN coll_i[38]
    DIRECTION INPUT ;
    USE SIGNAL ;
    PORT
      LAYER M4 ;
        RECT  0 36.252 0.192 36.276 ;
    END
  END coll_i[38]
  PIN coll_i[390]
    DIRECTION INPUT ;
    USE SIGNAL ;
    PORT
      LAYER M4 ;
        RECT  0 353.58 0.192 353.604 ;
    END
  END coll_i[390]
  PIN coll_i[391]
    DIRECTION INPUT ;
    USE SIGNAL ;
    PORT
      LAYER M4 ;
        RECT  0 354.492 0.192 354.516 ;
    END
  END coll_i[391]
  PIN coll_i[392]
    DIRECTION INPUT ;
    USE SIGNAL ;
    PORT
      LAYER M4 ;
        RECT  0 355.404 0.192 355.428 ;
    END
  END coll_i[392]
  PIN coll_i[393]
    DIRECTION INPUT ;
    USE SIGNAL ;
    PORT
      LAYER M4 ;
        RECT  0 356.316 0.192 356.34 ;
    END
  END coll_i[393]
  PIN coll_i[394]
    DIRECTION INPUT ;
    USE SIGNAL ;
    PORT
      LAYER M4 ;
        RECT  0 357.18 0.192 357.204 ;
    END
  END coll_i[394]
  PIN coll_i[395]
    DIRECTION INPUT ;
    USE SIGNAL ;
    PORT
      LAYER M4 ;
        RECT  0 358.092 0.192 358.116 ;
    END
  END coll_i[395]
  PIN coll_i[396]
    DIRECTION INPUT ;
    USE SIGNAL ;
    PORT
      LAYER M4 ;
        RECT  0 359.004 0.192 359.028 ;
    END
  END coll_i[396]
  PIN coll_i[397]
    DIRECTION INPUT ;
    USE SIGNAL ;
    PORT
      LAYER M4 ;
        RECT  0 359.916 0.192 359.94 ;
    END
  END coll_i[397]
  PIN coll_i[398]
    DIRECTION INPUT ;
    USE SIGNAL ;
    PORT
      LAYER M4 ;
        RECT  0 360.828 0.192 360.852 ;
    END
  END coll_i[398]
  PIN coll_i[399]
    DIRECTION INPUT ;
    USE SIGNAL ;
    PORT
      LAYER M4 ;
        RECT  0 361.692 0.192 361.716 ;
    END
  END coll_i[399]
  PIN coll_i[39]
    DIRECTION INPUT ;
    USE SIGNAL ;
    PORT
      LAYER M4 ;
        RECT  0 37.164 0.192 37.188 ;
    END
  END coll_i[39]
  PIN coll_i[3]
    DIRECTION INPUT ;
    USE SIGNAL ;
    PORT
      LAYER M4 ;
        RECT  0 4.716 0.192 4.74 ;
    END
  END coll_i[3]
  PIN coll_i[400]
    DIRECTION INPUT ;
    USE SIGNAL ;
    PORT
      LAYER M4 ;
        RECT  0 362.604 0.192 362.628 ;
    END
  END coll_i[400]
  PIN coll_i[401]
    DIRECTION INPUT ;
    USE SIGNAL ;
    PORT
      LAYER M4 ;
        RECT  0 363.516 0.192 363.54 ;
    END
  END coll_i[401]
  PIN coll_i[402]
    DIRECTION INPUT ;
    USE SIGNAL ;
    PORT
      LAYER M4 ;
        RECT  0 364.428 0.192 364.452 ;
    END
  END coll_i[402]
  PIN coll_i[403]
    DIRECTION INPUT ;
    USE SIGNAL ;
    PORT
      LAYER M4 ;
        RECT  0 365.34 0.192 365.364 ;
    END
  END coll_i[403]
  PIN coll_i[404]
    DIRECTION INPUT ;
    USE SIGNAL ;
    PORT
      LAYER M4 ;
        RECT  0 366.204 0.192 366.228 ;
    END
  END coll_i[404]
  PIN coll_i[405]
    DIRECTION INPUT ;
    USE SIGNAL ;
    PORT
      LAYER M4 ;
        RECT  0 367.116 0.192 367.14 ;
    END
  END coll_i[405]
  PIN coll_i[406]
    DIRECTION INPUT ;
    USE SIGNAL ;
    PORT
      LAYER M4 ;
        RECT  0 368.028 0.192 368.052 ;
    END
  END coll_i[406]
  PIN coll_i[407]
    DIRECTION INPUT ;
    USE SIGNAL ;
    PORT
      LAYER M4 ;
        RECT  0 368.94 0.192 368.964 ;
    END
  END coll_i[407]
  PIN coll_i[408]
    DIRECTION INPUT ;
    USE SIGNAL ;
    PORT
      LAYER M4 ;
        RECT  0 369.804 0.192 369.828 ;
    END
  END coll_i[408]
  PIN coll_i[409]
    DIRECTION INPUT ;
    USE SIGNAL ;
    PORT
      LAYER M4 ;
        RECT  0 370.716 0.192 370.74 ;
    END
  END coll_i[409]
  PIN coll_i[40]
    DIRECTION INPUT ;
    USE SIGNAL ;
    PORT
      LAYER M4 ;
        RECT  0 38.076 0.192 38.1 ;
    END
  END coll_i[40]
  PIN coll_i[410]
    DIRECTION INPUT ;
    USE SIGNAL ;
    PORT
      LAYER M4 ;
        RECT  0 371.628 0.192 371.652 ;
    END
  END coll_i[410]
  PIN coll_i[411]
    DIRECTION INPUT ;
    USE SIGNAL ;
    PORT
      LAYER M4 ;
        RECT  0 372.54 0.192 372.564 ;
    END
  END coll_i[411]
  PIN coll_i[412]
    DIRECTION INPUT ;
    USE SIGNAL ;
    PORT
      LAYER M4 ;
        RECT  0 373.452 0.192 373.476 ;
    END
  END coll_i[412]
  PIN coll_i[413]
    DIRECTION INPUT ;
    USE SIGNAL ;
    PORT
      LAYER M4 ;
        RECT  0 374.316 0.192 374.34 ;
    END
  END coll_i[413]
  PIN coll_i[414]
    DIRECTION INPUT ;
    USE SIGNAL ;
    PORT
      LAYER M4 ;
        RECT  0 375.228 0.192 375.252 ;
    END
  END coll_i[414]
  PIN coll_i[415]
    DIRECTION INPUT ;
    USE SIGNAL ;
    PORT
      LAYER M4 ;
        RECT  0 376.14 0.192 376.164 ;
    END
  END coll_i[415]
  PIN coll_i[416]
    DIRECTION INPUT ;
    USE SIGNAL ;
    PORT
      LAYER M4 ;
        RECT  0 377.052 0.192 377.076 ;
    END
  END coll_i[416]
  PIN coll_i[417]
    DIRECTION INPUT ;
    USE SIGNAL ;
    PORT
      LAYER M4 ;
        RECT  0 377.916 0.192 377.94 ;
    END
  END coll_i[417]
  PIN coll_i[418]
    DIRECTION INPUT ;
    USE SIGNAL ;
    PORT
      LAYER M4 ;
        RECT  0 378.828 0.192 378.852 ;
    END
  END coll_i[418]
  PIN coll_i[419]
    DIRECTION INPUT ;
    USE SIGNAL ;
    PORT
      LAYER M4 ;
        RECT  0 379.74 0.192 379.764 ;
    END
  END coll_i[419]
  PIN coll_i[41]
    DIRECTION INPUT ;
    USE SIGNAL ;
    PORT
      LAYER M4 ;
        RECT  0 38.988 0.192 39.012 ;
    END
  END coll_i[41]
  PIN coll_i[420]
    DIRECTION INPUT ;
    USE SIGNAL ;
    PORT
      LAYER M4 ;
        RECT  0 380.652 0.192 380.676 ;
    END
  END coll_i[420]
  PIN coll_i[421]
    DIRECTION INPUT ;
    USE SIGNAL ;
    PORT
      LAYER M4 ;
        RECT  0 381.564 0.192 381.588 ;
    END
  END coll_i[421]
  PIN coll_i[422]
    DIRECTION INPUT ;
    USE SIGNAL ;
    PORT
      LAYER M4 ;
        RECT  0 382.428 0.192 382.452 ;
    END
  END coll_i[422]
  PIN coll_i[423]
    DIRECTION INPUT ;
    USE SIGNAL ;
    PORT
      LAYER M4 ;
        RECT  0 383.34 0.192 383.364 ;
    END
  END coll_i[423]
  PIN coll_i[424]
    DIRECTION INPUT ;
    USE SIGNAL ;
    PORT
      LAYER M4 ;
        RECT  0 384.252 0.192 384.276 ;
    END
  END coll_i[424]
  PIN coll_i[425]
    DIRECTION INPUT ;
    USE SIGNAL ;
    PORT
      LAYER M4 ;
        RECT  0 385.164 0.192 385.188 ;
    END
  END coll_i[425]
  PIN coll_i[426]
    DIRECTION INPUT ;
    USE SIGNAL ;
    PORT
      LAYER M4 ;
        RECT  0 386.028 0.192 386.052 ;
    END
  END coll_i[426]
  PIN coll_i[427]
    DIRECTION INPUT ;
    USE SIGNAL ;
    PORT
      LAYER M4 ;
        RECT  0 386.94 0.192 386.964 ;
    END
  END coll_i[427]
  PIN coll_i[428]
    DIRECTION INPUT ;
    USE SIGNAL ;
    PORT
      LAYER M4 ;
        RECT  0 387.852 0.192 387.876 ;
    END
  END coll_i[428]
  PIN coll_i[429]
    DIRECTION INPUT ;
    USE SIGNAL ;
    PORT
      LAYER M4 ;
        RECT  0 388.764 0.192 388.788 ;
    END
  END coll_i[429]
  PIN coll_i[42]
    DIRECTION INPUT ;
    USE SIGNAL ;
    PORT
      LAYER M4 ;
        RECT  0 39.852 0.192 39.876 ;
    END
  END coll_i[42]
  PIN coll_i[430]
    DIRECTION INPUT ;
    USE SIGNAL ;
    PORT
      LAYER M4 ;
        RECT  0 389.676 0.192 389.7 ;
    END
  END coll_i[430]
  PIN coll_i[431]
    DIRECTION INPUT ;
    USE SIGNAL ;
    PORT
      LAYER M4 ;
        RECT  0 390.54 0.192 390.564 ;
    END
  END coll_i[431]
  PIN coll_i[432]
    DIRECTION INPUT ;
    USE SIGNAL ;
    PORT
      LAYER M4 ;
        RECT  0 391.452 0.192 391.476 ;
    END
  END coll_i[432]
  PIN coll_i[433]
    DIRECTION INPUT ;
    USE SIGNAL ;
    PORT
      LAYER M4 ;
        RECT  0 392.364 0.192 392.388 ;
    END
  END coll_i[433]
  PIN coll_i[434]
    DIRECTION INPUT ;
    USE SIGNAL ;
    PORT
      LAYER M4 ;
        RECT  0 393.276 0.192 393.3 ;
    END
  END coll_i[434]
  PIN coll_i[435]
    DIRECTION INPUT ;
    USE SIGNAL ;
    PORT
      LAYER M4 ;
        RECT  0 394.188 0.192 394.212 ;
    END
  END coll_i[435]
  PIN coll_i[436]
    DIRECTION INPUT ;
    USE SIGNAL ;
    PORT
      LAYER M4 ;
        RECT  0 395.052 0.192 395.076 ;
    END
  END coll_i[436]
  PIN coll_i[437]
    DIRECTION INPUT ;
    USE SIGNAL ;
    PORT
      LAYER M4 ;
        RECT  0 395.964 0.192 395.988 ;
    END
  END coll_i[437]
  PIN coll_i[438]
    DIRECTION INPUT ;
    USE SIGNAL ;
    PORT
      LAYER M4 ;
        RECT  0 396.876 0.192 396.9 ;
    END
  END coll_i[438]
  PIN coll_i[439]
    DIRECTION INPUT ;
    USE SIGNAL ;
    PORT
      LAYER M4 ;
        RECT  0 397.788 0.192 397.812 ;
    END
  END coll_i[439]
  PIN coll_i[43]
    DIRECTION INPUT ;
    USE SIGNAL ;
    PORT
      LAYER M4 ;
        RECT  0 40.764 0.192 40.788 ;
    END
  END coll_i[43]
  PIN coll_i[440]
    DIRECTION INPUT ;
    USE SIGNAL ;
    PORT
      LAYER M4 ;
        RECT  0 398.652 0.192 398.676 ;
    END
  END coll_i[440]
  PIN coll_i[441]
    DIRECTION INPUT ;
    USE SIGNAL ;
    PORT
      LAYER M4 ;
        RECT  0 399.564 0.192 399.588 ;
    END
  END coll_i[441]
  PIN coll_i[442]
    DIRECTION INPUT ;
    USE SIGNAL ;
    PORT
      LAYER M4 ;
        RECT  0 400.476 0.192 400.5 ;
    END
  END coll_i[442]
  PIN coll_i[443]
    DIRECTION INPUT ;
    USE SIGNAL ;
    PORT
      LAYER M4 ;
        RECT  0 401.388 0.192 401.412 ;
    END
  END coll_i[443]
  PIN coll_i[444]
    DIRECTION INPUT ;
    USE SIGNAL ;
    PORT
      LAYER M4 ;
        RECT  0 402.3 0.192 402.324 ;
    END
  END coll_i[444]
  PIN coll_i[445]
    DIRECTION INPUT ;
    USE SIGNAL ;
    PORT
      LAYER M4 ;
        RECT  0 403.164 0.192 403.188 ;
    END
  END coll_i[445]
  PIN coll_i[446]
    DIRECTION INPUT ;
    USE SIGNAL ;
    PORT
      LAYER M4 ;
        RECT  0 404.076 0.192 404.1 ;
    END
  END coll_i[446]
  PIN coll_i[447]
    DIRECTION INPUT ;
    USE SIGNAL ;
    PORT
      LAYER M4 ;
        RECT  0 404.988 0.192 405.012 ;
    END
  END coll_i[447]
  PIN coll_i[448]
    DIRECTION INPUT ;
    USE SIGNAL ;
    PORT
      LAYER M4 ;
        RECT  0 405.9 0.192 405.924 ;
    END
  END coll_i[448]
  PIN coll_i[449]
    DIRECTION INPUT ;
    USE SIGNAL ;
    PORT
      LAYER M4 ;
        RECT  0 406.764 0.192 406.788 ;
    END
  END coll_i[449]
  PIN coll_i[44]
    DIRECTION INPUT ;
    USE SIGNAL ;
    PORT
      LAYER M4 ;
        RECT  0 41.676 0.192 41.7 ;
    END
  END coll_i[44]
  PIN coll_i[450]
    DIRECTION INPUT ;
    USE SIGNAL ;
    PORT
      LAYER M4 ;
        RECT  0 407.676 0.192 407.7 ;
    END
  END coll_i[450]
  PIN coll_i[451]
    DIRECTION INPUT ;
    USE SIGNAL ;
    PORT
      LAYER M4 ;
        RECT  0 408.588 0.192 408.612 ;
    END
  END coll_i[451]
  PIN coll_i[452]
    DIRECTION INPUT ;
    USE SIGNAL ;
    PORT
      LAYER M4 ;
        RECT  0 409.5 0.192 409.524 ;
    END
  END coll_i[452]
  PIN coll_i[453]
    DIRECTION INPUT ;
    USE SIGNAL ;
    PORT
      LAYER M4 ;
        RECT  0 410.412 0.192 410.436 ;
    END
  END coll_i[453]
  PIN coll_i[454]
    DIRECTION INPUT ;
    USE SIGNAL ;
    PORT
      LAYER M4 ;
        RECT  0 411.276 0.192 411.3 ;
    END
  END coll_i[454]
  PIN coll_i[455]
    DIRECTION INPUT ;
    USE SIGNAL ;
    PORT
      LAYER M4 ;
        RECT  0 412.188 0.192 412.212 ;
    END
  END coll_i[455]
  PIN coll_i[456]
    DIRECTION INPUT ;
    USE SIGNAL ;
    PORT
      LAYER M4 ;
        RECT  0 413.1 0.192 413.124 ;
    END
  END coll_i[456]
  PIN coll_i[457]
    DIRECTION INPUT ;
    USE SIGNAL ;
    PORT
      LAYER M4 ;
        RECT  0 414.012 0.192 414.036 ;
    END
  END coll_i[457]
  PIN coll_i[458]
    DIRECTION INPUT ;
    USE SIGNAL ;
    PORT
      LAYER M4 ;
        RECT  0 414.924 0.192 414.948 ;
    END
  END coll_i[458]
  PIN coll_i[459]
    DIRECTION INPUT ;
    USE SIGNAL ;
    PORT
      LAYER M4 ;
        RECT  0 415.788 0.192 415.812 ;
    END
  END coll_i[459]
  PIN coll_i[45]
    DIRECTION INPUT ;
    USE SIGNAL ;
    PORT
      LAYER M4 ;
        RECT  0 42.588 0.192 42.612 ;
    END
  END coll_i[45]
  PIN coll_i[460]
    DIRECTION INPUT ;
    USE SIGNAL ;
    PORT
      LAYER M4 ;
        RECT  0 416.7 0.192 416.724 ;
    END
  END coll_i[460]
  PIN coll_i[461]
    DIRECTION INPUT ;
    USE SIGNAL ;
    PORT
      LAYER M4 ;
        RECT  0 417.612 0.192 417.636 ;
    END
  END coll_i[461]
  PIN coll_i[462]
    DIRECTION INPUT ;
    USE SIGNAL ;
    PORT
      LAYER M4 ;
        RECT  0 418.524 0.192 418.548 ;
    END
  END coll_i[462]
  PIN coll_i[463]
    DIRECTION INPUT ;
    USE SIGNAL ;
    PORT
      LAYER M4 ;
        RECT  0 419.388 0.192 419.412 ;
    END
  END coll_i[463]
  PIN coll_i[464]
    DIRECTION INPUT ;
    USE SIGNAL ;
    PORT
      LAYER M4 ;
        RECT  0 420.3 0.192 420.324 ;
    END
  END coll_i[464]
  PIN coll_i[465]
    DIRECTION INPUT ;
    USE SIGNAL ;
    PORT
      LAYER M4 ;
        RECT  0 421.212 0.192 421.236 ;
    END
  END coll_i[465]
  PIN coll_i[466]
    DIRECTION INPUT ;
    USE SIGNAL ;
    PORT
      LAYER M4 ;
        RECT  0 422.124 0.192 422.148 ;
    END
  END coll_i[466]
  PIN coll_i[467]
    DIRECTION INPUT ;
    USE SIGNAL ;
    PORT
      LAYER M4 ;
        RECT  0 423.036 0.192 423.06 ;
    END
  END coll_i[467]
  PIN coll_i[468]
    DIRECTION INPUT ;
    USE SIGNAL ;
    PORT
      LAYER M4 ;
        RECT  0 423.9 0.192 423.924 ;
    END
  END coll_i[468]
  PIN coll_i[469]
    DIRECTION INPUT ;
    USE SIGNAL ;
    PORT
      LAYER M4 ;
        RECT  0 424.812 0.192 424.836 ;
    END
  END coll_i[469]
  PIN coll_i[46]
    DIRECTION INPUT ;
    USE SIGNAL ;
    PORT
      LAYER M4 ;
        RECT  0 43.452 0.192 43.476 ;
    END
  END coll_i[46]
  PIN coll_i[470]
    DIRECTION INPUT ;
    USE SIGNAL ;
    PORT
      LAYER M4 ;
        RECT  0 425.724 0.192 425.748 ;
    END
  END coll_i[470]
  PIN coll_i[471]
    DIRECTION INPUT ;
    USE SIGNAL ;
    PORT
      LAYER M4 ;
        RECT  0 426.636 0.192 426.66 ;
    END
  END coll_i[471]
  PIN coll_i[472]
    DIRECTION INPUT ;
    USE SIGNAL ;
    PORT
      LAYER M4 ;
        RECT  0 427.5 0.192 427.524 ;
    END
  END coll_i[472]
  PIN coll_i[473]
    DIRECTION INPUT ;
    USE SIGNAL ;
    PORT
      LAYER M4 ;
        RECT  0 428.412 0.192 428.436 ;
    END
  END coll_i[473]
  PIN coll_i[474]
    DIRECTION INPUT ;
    USE SIGNAL ;
    PORT
      LAYER M4 ;
        RECT  0 429.324 0.192 429.348 ;
    END
  END coll_i[474]
  PIN coll_i[475]
    DIRECTION INPUT ;
    USE SIGNAL ;
    PORT
      LAYER M4 ;
        RECT  0 430.236 0.192 430.26 ;
    END
  END coll_i[475]
  PIN coll_i[476]
    DIRECTION INPUT ;
    USE SIGNAL ;
    PORT
      LAYER M4 ;
        RECT  0 431.148 0.192 431.172 ;
    END
  END coll_i[476]
  PIN coll_i[477]
    DIRECTION INPUT ;
    USE SIGNAL ;
    PORT
      LAYER M4 ;
        RECT  0 432.012 0.192 432.036 ;
    END
  END coll_i[477]
  PIN coll_i[478]
    DIRECTION INPUT ;
    USE SIGNAL ;
    PORT
      LAYER M4 ;
        RECT  0 432.924 0.192 432.948 ;
    END
  END coll_i[478]
  PIN coll_i[479]
    DIRECTION INPUT ;
    USE SIGNAL ;
    PORT
      LAYER M4 ;
        RECT  0 433.836 0.192 433.86 ;
    END
  END coll_i[479]
  PIN coll_i[47]
    DIRECTION INPUT ;
    USE SIGNAL ;
    PORT
      LAYER M4 ;
        RECT  0 44.364 0.192 44.388 ;
    END
  END coll_i[47]
  PIN coll_i[480]
    DIRECTION INPUT ;
    USE SIGNAL ;
    PORT
      LAYER M4 ;
        RECT  0 434.748 0.192 434.772 ;
    END
  END coll_i[480]
  PIN coll_i[481]
    DIRECTION INPUT ;
    USE SIGNAL ;
    PORT
      LAYER M4 ;
        RECT  0 435.612 0.192 435.636 ;
    END
  END coll_i[481]
  PIN coll_i[482]
    DIRECTION INPUT ;
    USE SIGNAL ;
    PORT
      LAYER M4 ;
        RECT  0 436.524 0.192 436.548 ;
    END
  END coll_i[482]
  PIN coll_i[483]
    DIRECTION INPUT ;
    USE SIGNAL ;
    PORT
      LAYER M4 ;
        RECT  0 437.436 0.192 437.46 ;
    END
  END coll_i[483]
  PIN coll_i[484]
    DIRECTION INPUT ;
    USE SIGNAL ;
    PORT
      LAYER M4 ;
        RECT  0 438.348 0.192 438.372 ;
    END
  END coll_i[484]
  PIN coll_i[485]
    DIRECTION INPUT ;
    USE SIGNAL ;
    PORT
      LAYER M4 ;
        RECT  0 439.26 0.192 439.284 ;
    END
  END coll_i[485]
  PIN coll_i[486]
    DIRECTION INPUT ;
    USE SIGNAL ;
    PORT
      LAYER M4 ;
        RECT  0 440.124 0.192 440.148 ;
    END
  END coll_i[486]
  PIN coll_i[487]
    DIRECTION INPUT ;
    USE SIGNAL ;
    PORT
      LAYER M4 ;
        RECT  0 441.036 0.192 441.06 ;
    END
  END coll_i[487]
  PIN coll_i[488]
    DIRECTION INPUT ;
    USE SIGNAL ;
    PORT
      LAYER M4 ;
        RECT  0 441.948 0.192 441.972 ;
    END
  END coll_i[488]
  PIN coll_i[489]
    DIRECTION INPUT ;
    USE SIGNAL ;
    PORT
      LAYER M4 ;
        RECT  0 442.86 0.192 442.884 ;
    END
  END coll_i[489]
  PIN coll_i[48]
    DIRECTION INPUT ;
    USE SIGNAL ;
    PORT
      LAYER M4 ;
        RECT  0 45.276 0.192 45.3 ;
    END
  END coll_i[48]
  PIN coll_i[490]
    DIRECTION INPUT ;
    USE SIGNAL ;
    PORT
      LAYER M4 ;
        RECT  0 443.772 0.192 443.796 ;
    END
  END coll_i[490]
  PIN coll_i[491]
    DIRECTION INPUT ;
    USE SIGNAL ;
    PORT
      LAYER M4 ;
        RECT  0 444.636 0.192 444.66 ;
    END
  END coll_i[491]
  PIN coll_i[492]
    DIRECTION INPUT ;
    USE SIGNAL ;
    PORT
      LAYER M4 ;
        RECT  0 445.548 0.192 445.572 ;
    END
  END coll_i[492]
  PIN coll_i[493]
    DIRECTION INPUT ;
    USE SIGNAL ;
    PORT
      LAYER M4 ;
        RECT  0 446.46 0.192 446.484 ;
    END
  END coll_i[493]
  PIN coll_i[494]
    DIRECTION INPUT ;
    USE SIGNAL ;
    PORT
      LAYER M4 ;
        RECT  0 447.372 0.192 447.396 ;
    END
  END coll_i[494]
  PIN coll_i[495]
    DIRECTION INPUT ;
    USE SIGNAL ;
    PORT
      LAYER M4 ;
        RECT  0 448.236 0.192 448.26 ;
    END
  END coll_i[495]
  PIN coll_i[496]
    DIRECTION INPUT ;
    USE SIGNAL ;
    PORT
      LAYER M4 ;
        RECT  0 449.148 0.192 449.172 ;
    END
  END coll_i[496]
  PIN coll_i[497]
    DIRECTION INPUT ;
    USE SIGNAL ;
    PORT
      LAYER M4 ;
        RECT  0 450.06 0.192 450.084 ;
    END
  END coll_i[497]
  PIN coll_i[498]
    DIRECTION INPUT ;
    USE SIGNAL ;
    PORT
      LAYER M4 ;
        RECT  0 450.972 0.192 450.996 ;
    END
  END coll_i[498]
  PIN coll_i[499]
    DIRECTION INPUT ;
    USE SIGNAL ;
    PORT
      LAYER M4 ;
        RECT  0 451.884 0.192 451.908 ;
    END
  END coll_i[499]
  PIN coll_i[49]
    DIRECTION INPUT ;
    USE SIGNAL ;
    PORT
      LAYER M4 ;
        RECT  0 46.188 0.192 46.212 ;
    END
  END coll_i[49]
  PIN coll_i[4]
    DIRECTION INPUT ;
    USE SIGNAL ;
    PORT
      LAYER M4 ;
        RECT  0 5.628 0.192 5.652 ;
    END
  END coll_i[4]
  PIN coll_i[500]
    DIRECTION INPUT ;
    USE SIGNAL ;
    PORT
      LAYER M4 ;
        RECT  0 452.748 0.192 452.772 ;
    END
  END coll_i[500]
  PIN coll_i[501]
    DIRECTION INPUT ;
    USE SIGNAL ;
    PORT
      LAYER M4 ;
        RECT  0 453.66 0.192 453.684 ;
    END
  END coll_i[501]
  PIN coll_i[502]
    DIRECTION INPUT ;
    USE SIGNAL ;
    PORT
      LAYER M4 ;
        RECT  0 454.572 0.192 454.596 ;
    END
  END coll_i[502]
  PIN coll_i[503]
    DIRECTION INPUT ;
    USE SIGNAL ;
    PORT
      LAYER M4 ;
        RECT  0 455.484 0.192 455.508 ;
    END
  END coll_i[503]
  PIN coll_i[504]
    DIRECTION INPUT ;
    USE SIGNAL ;
    PORT
      LAYER M4 ;
        RECT  0 456.348 0.192 456.372 ;
    END
  END coll_i[504]
  PIN coll_i[505]
    DIRECTION INPUT ;
    USE SIGNAL ;
    PORT
      LAYER M4 ;
        RECT  0 457.26 0.192 457.284 ;
    END
  END coll_i[505]
  PIN coll_i[506]
    DIRECTION INPUT ;
    USE SIGNAL ;
    PORT
      LAYER M4 ;
        RECT  0 458.172 0.192 458.196 ;
    END
  END coll_i[506]
  PIN coll_i[507]
    DIRECTION INPUT ;
    USE SIGNAL ;
    PORT
      LAYER M4 ;
        RECT  0 459.084 0.192 459.108 ;
    END
  END coll_i[507]
  PIN coll_i[508]
    DIRECTION INPUT ;
    USE SIGNAL ;
    PORT
      LAYER M4 ;
        RECT  0 459.996 0.192 460.02 ;
    END
  END coll_i[508]
  PIN coll_i[509]
    DIRECTION INPUT ;
    USE SIGNAL ;
    PORT
      LAYER M4 ;
        RECT  0 460.86 0.192 460.884 ;
    END
  END coll_i[509]
  PIN coll_i[50]
    DIRECTION INPUT ;
    USE SIGNAL ;
    PORT
      LAYER M4 ;
        RECT  0 47.1 0.192 47.124 ;
    END
  END coll_i[50]
  PIN coll_i[510]
    DIRECTION INPUT ;
    USE SIGNAL ;
    PORT
      LAYER M4 ;
        RECT  0 461.772 0.192 461.796 ;
    END
  END coll_i[510]
  PIN coll_i[511]
    DIRECTION INPUT ;
    USE SIGNAL ;
    PORT
      LAYER M4 ;
        RECT  0 462.684 0.192 462.708 ;
    END
  END coll_i[511]
  PIN coll_i[512]
    DIRECTION INPUT ;
    USE SIGNAL ;
    PORT
      LAYER M4 ;
        RECT  0 463.596 0.192 463.62 ;
    END
  END coll_i[512]
  PIN coll_i[513]
    DIRECTION INPUT ;
    USE SIGNAL ;
    PORT
      LAYER M4 ;
        RECT  0 464.508 0.192 464.532 ;
    END
  END coll_i[513]
  PIN coll_i[51]
    DIRECTION INPUT ;
    USE SIGNAL ;
    PORT
      LAYER M4 ;
        RECT  0 47.964 0.192 47.988 ;
    END
  END coll_i[51]
  PIN coll_i[52]
    DIRECTION INPUT ;
    USE SIGNAL ;
    PORT
      LAYER M4 ;
        RECT  0 48.876 0.192 48.9 ;
    END
  END coll_i[52]
  PIN coll_i[53]
    DIRECTION INPUT ;
    USE SIGNAL ;
    PORT
      LAYER M4 ;
        RECT  0 49.788 0.192 49.812 ;
    END
  END coll_i[53]
  PIN coll_i[54]
    DIRECTION INPUT ;
    USE SIGNAL ;
    PORT
      LAYER M4 ;
        RECT  0 50.7 0.192 50.724 ;
    END
  END coll_i[54]
  PIN coll_i[55]
    DIRECTION INPUT ;
    USE SIGNAL ;
    PORT
      LAYER M4 ;
        RECT  0 51.564 0.192 51.588 ;
    END
  END coll_i[55]
  PIN coll_i[56]
    DIRECTION INPUT ;
    USE SIGNAL ;
    PORT
      LAYER M4 ;
        RECT  0 52.476 0.192 52.5 ;
    END
  END coll_i[56]
  PIN coll_i[57]
    DIRECTION INPUT ;
    USE SIGNAL ;
    PORT
      LAYER M4 ;
        RECT  0 53.388 0.192 53.412 ;
    END
  END coll_i[57]
  PIN coll_i[58]
    DIRECTION INPUT ;
    USE SIGNAL ;
    PORT
      LAYER M4 ;
        RECT  0 54.3 0.192 54.324 ;
    END
  END coll_i[58]
  PIN coll_i[59]
    DIRECTION INPUT ;
    USE SIGNAL ;
    PORT
      LAYER M4 ;
        RECT  0 55.212 0.192 55.236 ;
    END
  END coll_i[59]
  PIN coll_i[5]
    DIRECTION INPUT ;
    USE SIGNAL ;
    PORT
      LAYER M4 ;
        RECT  0 6.492 0.192 6.516 ;
    END
  END coll_i[5]
  PIN coll_i[60]
    DIRECTION INPUT ;
    USE SIGNAL ;
    PORT
      LAYER M4 ;
        RECT  0 56.076 0.192 56.1 ;
    END
  END coll_i[60]
  PIN coll_i[61]
    DIRECTION INPUT ;
    USE SIGNAL ;
    PORT
      LAYER M4 ;
        RECT  0 56.988 0.192 57.012 ;
    END
  END coll_i[61]
  PIN coll_i[62]
    DIRECTION INPUT ;
    USE SIGNAL ;
    PORT
      LAYER M4 ;
        RECT  0 57.9 0.192 57.924 ;
    END
  END coll_i[62]
  PIN coll_i[63]
    DIRECTION INPUT ;
    USE SIGNAL ;
    PORT
      LAYER M4 ;
        RECT  0 58.812 0.192 58.836 ;
    END
  END coll_i[63]
  PIN coll_i[64]
    DIRECTION INPUT ;
    USE SIGNAL ;
    PORT
      LAYER M4 ;
        RECT  0 59.724 0.192 59.748 ;
    END
  END coll_i[64]
  PIN coll_i[65]
    DIRECTION INPUT ;
    USE SIGNAL ;
    PORT
      LAYER M4 ;
        RECT  0 60.588 0.192 60.612 ;
    END
  END coll_i[65]
  PIN coll_i[66]
    DIRECTION INPUT ;
    USE SIGNAL ;
    PORT
      LAYER M4 ;
        RECT  0 61.5 0.192 61.524 ;
    END
  END coll_i[66]
  PIN coll_i[67]
    DIRECTION INPUT ;
    USE SIGNAL ;
    PORT
      LAYER M4 ;
        RECT  0 62.412 0.192 62.436 ;
    END
  END coll_i[67]
  PIN coll_i[68]
    DIRECTION INPUT ;
    USE SIGNAL ;
    PORT
      LAYER M4 ;
        RECT  0 63.324 0.192 63.348 ;
    END
  END coll_i[68]
  PIN coll_i[69]
    DIRECTION INPUT ;
    USE SIGNAL ;
    PORT
      LAYER M4 ;
        RECT  0 64.188 0.192 64.212 ;
    END
  END coll_i[69]
  PIN coll_i[6]
    DIRECTION INPUT ;
    USE SIGNAL ;
    PORT
      LAYER M4 ;
        RECT  0 7.404 0.192 7.428 ;
    END
  END coll_i[6]
  PIN coll_i[70]
    DIRECTION INPUT ;
    USE SIGNAL ;
    PORT
      LAYER M4 ;
        RECT  0 65.1 0.192 65.124 ;
    END
  END coll_i[70]
  PIN coll_i[71]
    DIRECTION INPUT ;
    USE SIGNAL ;
    PORT
      LAYER M4 ;
        RECT  0 66.012 0.192 66.036 ;
    END
  END coll_i[71]
  PIN coll_i[72]
    DIRECTION INPUT ;
    USE SIGNAL ;
    PORT
      LAYER M4 ;
        RECT  0 66.924 0.192 66.948 ;
    END
  END coll_i[72]
  PIN coll_i[73]
    DIRECTION INPUT ;
    USE SIGNAL ;
    PORT
      LAYER M4 ;
        RECT  0 67.836 0.192 67.86 ;
    END
  END coll_i[73]
  PIN coll_i[74]
    DIRECTION INPUT ;
    USE SIGNAL ;
    PORT
      LAYER M4 ;
        RECT  0 68.7 0.192 68.724 ;
    END
  END coll_i[74]
  PIN coll_i[75]
    DIRECTION INPUT ;
    USE SIGNAL ;
    PORT
      LAYER M4 ;
        RECT  0 69.612 0.192 69.636 ;
    END
  END coll_i[75]
  PIN coll_i[76]
    DIRECTION INPUT ;
    USE SIGNAL ;
    PORT
      LAYER M4 ;
        RECT  0 70.524 0.192 70.548 ;
    END
  END coll_i[76]
  PIN coll_i[77]
    DIRECTION INPUT ;
    USE SIGNAL ;
    PORT
      LAYER M4 ;
        RECT  0 71.436 0.192 71.46 ;
    END
  END coll_i[77]
  PIN coll_i[78]
    DIRECTION INPUT ;
    USE SIGNAL ;
    PORT
      LAYER M4 ;
        RECT  0 72.3 0.192 72.324 ;
    END
  END coll_i[78]
  PIN coll_i[79]
    DIRECTION INPUT ;
    USE SIGNAL ;
    PORT
      LAYER M4 ;
        RECT  0 73.212 0.192 73.236 ;
    END
  END coll_i[79]
  PIN coll_i[7]
    DIRECTION INPUT ;
    USE SIGNAL ;
    PORT
      LAYER M4 ;
        RECT  0 8.316 0.192 8.34 ;
    END
  END coll_i[7]
  PIN coll_i[80]
    DIRECTION INPUT ;
    USE SIGNAL ;
    PORT
      LAYER M4 ;
        RECT  0 74.124 0.192 74.148 ;
    END
  END coll_i[80]
  PIN coll_i[81]
    DIRECTION INPUT ;
    USE SIGNAL ;
    PORT
      LAYER M4 ;
        RECT  0 75.036 0.192 75.06 ;
    END
  END coll_i[81]
  PIN coll_i[82]
    DIRECTION INPUT ;
    USE SIGNAL ;
    PORT
      LAYER M4 ;
        RECT  0 75.948 0.192 75.972 ;
    END
  END coll_i[82]
  PIN coll_i[83]
    DIRECTION INPUT ;
    USE SIGNAL ;
    PORT
      LAYER M4 ;
        RECT  0 76.812 0.192 76.836 ;
    END
  END coll_i[83]
  PIN coll_i[84]
    DIRECTION INPUT ;
    USE SIGNAL ;
    PORT
      LAYER M4 ;
        RECT  0 77.724 0.192 77.748 ;
    END
  END coll_i[84]
  PIN coll_i[85]
    DIRECTION INPUT ;
    USE SIGNAL ;
    PORT
      LAYER M4 ;
        RECT  0 78.636 0.192 78.66 ;
    END
  END coll_i[85]
  PIN coll_i[86]
    DIRECTION INPUT ;
    USE SIGNAL ;
    PORT
      LAYER M4 ;
        RECT  0 79.548 0.192 79.572 ;
    END
  END coll_i[86]
  PIN coll_i[87]
    DIRECTION INPUT ;
    USE SIGNAL ;
    PORT
      LAYER M4 ;
        RECT  0 80.46 0.192 80.484 ;
    END
  END coll_i[87]
  PIN coll_i[88]
    DIRECTION INPUT ;
    USE SIGNAL ;
    PORT
      LAYER M4 ;
        RECT  0 81.324 0.192 81.348 ;
    END
  END coll_i[88]
  PIN coll_i[89]
    DIRECTION INPUT ;
    USE SIGNAL ;
    PORT
      LAYER M4 ;
        RECT  0 82.236 0.192 82.26 ;
    END
  END coll_i[89]
  PIN coll_i[8]
    DIRECTION INPUT ;
    USE SIGNAL ;
    PORT
      LAYER M4 ;
        RECT  0 9.228 0.192 9.252 ;
    END
  END coll_i[8]
  PIN coll_i[90]
    DIRECTION INPUT ;
    USE SIGNAL ;
    PORT
      LAYER M4 ;
        RECT  0 83.148 0.192 83.172 ;
    END
  END coll_i[90]
  PIN coll_i[91]
    DIRECTION INPUT ;
    USE SIGNAL ;
    PORT
      LAYER M4 ;
        RECT  0 84.06 0.192 84.084 ;
    END
  END coll_i[91]
  PIN coll_i[92]
    DIRECTION INPUT ;
    USE SIGNAL ;
    PORT
      LAYER M4 ;
        RECT  0 84.924 0.192 84.948 ;
    END
  END coll_i[92]
  PIN coll_i[93]
    DIRECTION INPUT ;
    USE SIGNAL ;
    PORT
      LAYER M4 ;
        RECT  0 85.836 0.192 85.86 ;
    END
  END coll_i[93]
  PIN coll_i[94]
    DIRECTION INPUT ;
    USE SIGNAL ;
    PORT
      LAYER M4 ;
        RECT  0 86.748 0.192 86.772 ;
    END
  END coll_i[94]
  PIN coll_i[95]
    DIRECTION INPUT ;
    USE SIGNAL ;
    PORT
      LAYER M4 ;
        RECT  0 87.66 0.192 87.684 ;
    END
  END coll_i[95]
  PIN coll_i[96]
    DIRECTION INPUT ;
    USE SIGNAL ;
    PORT
      LAYER M4 ;
        RECT  0 88.572 0.192 88.596 ;
    END
  END coll_i[96]
  PIN coll_i[97]
    DIRECTION INPUT ;
    USE SIGNAL ;
    PORT
      LAYER M4 ;
        RECT  0 89.436 0.192 89.46 ;
    END
  END coll_i[97]
  PIN coll_i[98]
    DIRECTION INPUT ;
    USE SIGNAL ;
    PORT
      LAYER M4 ;
        RECT  0 90.348 0.192 90.372 ;
    END
  END coll_i[98]
  PIN coll_i[99]
    DIRECTION INPUT ;
    USE SIGNAL ;
    PORT
      LAYER M4 ;
        RECT  0 91.26 0.192 91.284 ;
    END
  END coll_i[99]
  PIN coll_i[9]
    DIRECTION INPUT ;
    USE SIGNAL ;
    PORT
      LAYER M4 ;
        RECT  0 10.14 0.192 10.164 ;
    END
  END coll_i[9]
  PIN coll_o[0]
    DIRECTION OUTPUT ;
    USE SIGNAL ;
    PORT
      LAYER M6 ;
        RECT  0 2 0.192 2.032 ;
    END
  END coll_o[0]
  PIN coll_o[100]
    DIRECTION OUTPUT ;
    USE SIGNAL ;
    PORT
      LAYER M6 ;
        RECT  0 92.496 0.192 92.528 ;
    END
  END coll_o[100]
  PIN coll_o[101]
    DIRECTION OUTPUT ;
    USE SIGNAL ;
    PORT
      LAYER M6 ;
        RECT  0 93.392 0.192 93.424 ;
    END
  END coll_o[101]
  PIN coll_o[102]
    DIRECTION OUTPUT ;
    USE SIGNAL ;
    PORT
      LAYER M6 ;
        RECT  0 94.288 0.192 94.32 ;
    END
  END coll_o[102]
  PIN coll_o[103]
    DIRECTION OUTPUT ;
    USE SIGNAL ;
    PORT
      LAYER M6 ;
        RECT  0 95.184 0.192 95.216 ;
    END
  END coll_o[103]
  PIN coll_o[104]
    DIRECTION OUTPUT ;
    USE SIGNAL ;
    PORT
      LAYER M6 ;
        RECT  0 96.08 0.192 96.112 ;
    END
  END coll_o[104]
  PIN coll_o[105]
    DIRECTION OUTPUT ;
    USE SIGNAL ;
    PORT
      LAYER M6 ;
        RECT  0 97.04 0.192 97.072 ;
    END
  END coll_o[105]
  PIN coll_o[106]
    DIRECTION OUTPUT ;
    USE SIGNAL ;
    PORT
      LAYER M6 ;
        RECT  0 97.936 0.192 97.968 ;
    END
  END coll_o[106]
  PIN coll_o[107]
    DIRECTION OUTPUT ;
    USE SIGNAL ;
    PORT
      LAYER M6 ;
        RECT  0 98.832 0.192 98.864 ;
    END
  END coll_o[107]
  PIN coll_o[108]
    DIRECTION OUTPUT ;
    USE SIGNAL ;
    PORT
      LAYER M6 ;
        RECT  0 99.728 0.192 99.76 ;
    END
  END coll_o[108]
  PIN coll_o[109]
    DIRECTION OUTPUT ;
    USE SIGNAL ;
    PORT
      LAYER M6 ;
        RECT  0 100.624 0.192 100.656 ;
    END
  END coll_o[109]
  PIN coll_o[10]
    DIRECTION OUTPUT ;
    USE SIGNAL ;
    PORT
      LAYER M6 ;
        RECT  0 11.024 0.192 11.056 ;
    END
  END coll_o[10]
  PIN coll_o[110]
    DIRECTION OUTPUT ;
    USE SIGNAL ;
    PORT
      LAYER M6 ;
        RECT  0 101.52 0.192 101.552 ;
    END
  END coll_o[110]
  PIN coll_o[111]
    DIRECTION OUTPUT ;
    USE SIGNAL ;
    PORT
      LAYER M6 ;
        RECT  0 102.416 0.192 102.448 ;
    END
  END coll_o[111]
  PIN coll_o[112]
    DIRECTION OUTPUT ;
    USE SIGNAL ;
    PORT
      LAYER M6 ;
        RECT  0 103.376 0.192 103.408 ;
    END
  END coll_o[112]
  PIN coll_o[113]
    DIRECTION OUTPUT ;
    USE SIGNAL ;
    PORT
      LAYER M6 ;
        RECT  0 104.272 0.192 104.304 ;
    END
  END coll_o[113]
  PIN coll_o[114]
    DIRECTION OUTPUT ;
    USE SIGNAL ;
    PORT
      LAYER M6 ;
        RECT  0 105.168 0.192 105.2 ;
    END
  END coll_o[114]
  PIN coll_o[115]
    DIRECTION OUTPUT ;
    USE SIGNAL ;
    PORT
      LAYER M6 ;
        RECT  0 106.064 0.192 106.096 ;
    END
  END coll_o[115]
  PIN coll_o[116]
    DIRECTION OUTPUT ;
    USE SIGNAL ;
    PORT
      LAYER M6 ;
        RECT  0 106.96 0.192 106.992 ;
    END
  END coll_o[116]
  PIN coll_o[117]
    DIRECTION OUTPUT ;
    USE SIGNAL ;
    PORT
      LAYER M6 ;
        RECT  0 107.856 0.192 107.888 ;
    END
  END coll_o[117]
  PIN coll_o[118]
    DIRECTION OUTPUT ;
    USE SIGNAL ;
    PORT
      LAYER M6 ;
        RECT  0 108.752 0.192 108.784 ;
    END
  END coll_o[118]
  PIN coll_o[119]
    DIRECTION OUTPUT ;
    USE SIGNAL ;
    PORT
      LAYER M6 ;
        RECT  0 109.712 0.192 109.744 ;
    END
  END coll_o[119]
  PIN coll_o[11]
    DIRECTION OUTPUT ;
    USE SIGNAL ;
    PORT
      LAYER M6 ;
        RECT  0 11.92 0.192 11.952 ;
    END
  END coll_o[11]
  PIN coll_o[120]
    DIRECTION OUTPUT ;
    USE SIGNAL ;
    PORT
      LAYER M6 ;
        RECT  0 110.608 0.192 110.64 ;
    END
  END coll_o[120]
  PIN coll_o[121]
    DIRECTION OUTPUT ;
    USE SIGNAL ;
    PORT
      LAYER M6 ;
        RECT  0 111.504 0.192 111.536 ;
    END
  END coll_o[121]
  PIN coll_o[122]
    DIRECTION OUTPUT ;
    USE SIGNAL ;
    PORT
      LAYER M6 ;
        RECT  0 112.4 0.192 112.432 ;
    END
  END coll_o[122]
  PIN coll_o[123]
    DIRECTION OUTPUT ;
    USE SIGNAL ;
    PORT
      LAYER M6 ;
        RECT  0 113.296 0.192 113.328 ;
    END
  END coll_o[123]
  PIN coll_o[124]
    DIRECTION OUTPUT ;
    USE SIGNAL ;
    PORT
      LAYER M6 ;
        RECT  0 114.192 0.192 114.224 ;
    END
  END coll_o[124]
  PIN coll_o[125]
    DIRECTION OUTPUT ;
    USE SIGNAL ;
    PORT
      LAYER M6 ;
        RECT  0 115.088 0.192 115.12 ;
    END
  END coll_o[125]
  PIN coll_o[126]
    DIRECTION OUTPUT ;
    USE SIGNAL ;
    PORT
      LAYER M6 ;
        RECT  0 116.048 0.192 116.08 ;
    END
  END coll_o[126]
  PIN coll_o[127]
    DIRECTION OUTPUT ;
    USE SIGNAL ;
    PORT
      LAYER M6 ;
        RECT  0 116.944 0.192 116.976 ;
    END
  END coll_o[127]
  PIN coll_o[128]
    DIRECTION OUTPUT ;
    USE SIGNAL ;
    PORT
      LAYER M6 ;
        RECT  0 117.84 0.192 117.872 ;
    END
  END coll_o[128]
  PIN coll_o[129]
    DIRECTION OUTPUT ;
    USE SIGNAL ;
    PORT
      LAYER M6 ;
        RECT  0 118.736 0.192 118.768 ;
    END
  END coll_o[129]
  PIN coll_o[12]
    DIRECTION OUTPUT ;
    USE SIGNAL ;
    PORT
      LAYER M6 ;
        RECT  0 12.816 0.192 12.848 ;
    END
  END coll_o[12]
  PIN coll_o[130]
    DIRECTION OUTPUT ;
    USE SIGNAL ;
    PORT
      LAYER M6 ;
        RECT  0 119.632 0.192 119.664 ;
    END
  END coll_o[130]
  PIN coll_o[131]
    DIRECTION OUTPUT ;
    USE SIGNAL ;
    PORT
      LAYER M6 ;
        RECT  0 120.528 0.192 120.56 ;
    END
  END coll_o[131]
  PIN coll_o[132]
    DIRECTION OUTPUT ;
    USE SIGNAL ;
    PORT
      LAYER M6 ;
        RECT  0 121.424 0.192 121.456 ;
    END
  END coll_o[132]
  PIN coll_o[133]
    DIRECTION OUTPUT ;
    USE SIGNAL ;
    PORT
      LAYER M6 ;
        RECT  0 122.384 0.192 122.416 ;
    END
  END coll_o[133]
  PIN coll_o[134]
    DIRECTION OUTPUT ;
    USE SIGNAL ;
    PORT
      LAYER M6 ;
        RECT  0 123.28 0.192 123.312 ;
    END
  END coll_o[134]
  PIN coll_o[135]
    DIRECTION OUTPUT ;
    USE SIGNAL ;
    PORT
      LAYER M6 ;
        RECT  0 124.176 0.192 124.208 ;
    END
  END coll_o[135]
  PIN coll_o[136]
    DIRECTION OUTPUT ;
    USE SIGNAL ;
    PORT
      LAYER M6 ;
        RECT  0 125.072 0.192 125.104 ;
    END
  END coll_o[136]
  PIN coll_o[137]
    DIRECTION OUTPUT ;
    USE SIGNAL ;
    PORT
      LAYER M6 ;
        RECT  0 125.968 0.192 126 ;
    END
  END coll_o[137]
  PIN coll_o[138]
    DIRECTION OUTPUT ;
    USE SIGNAL ;
    PORT
      LAYER M6 ;
        RECT  0 126.864 0.192 126.896 ;
    END
  END coll_o[138]
  PIN coll_o[139]
    DIRECTION OUTPUT ;
    USE SIGNAL ;
    PORT
      LAYER M6 ;
        RECT  0 127.76 0.192 127.792 ;
    END
  END coll_o[139]
  PIN coll_o[13]
    DIRECTION OUTPUT ;
    USE SIGNAL ;
    PORT
      LAYER M6 ;
        RECT  0 13.712 0.192 13.744 ;
    END
  END coll_o[13]
  PIN coll_o[140]
    DIRECTION OUTPUT ;
    USE SIGNAL ;
    PORT
      LAYER M6 ;
        RECT  0 128.72 0.192 128.752 ;
    END
  END coll_o[140]
  PIN coll_o[141]
    DIRECTION OUTPUT ;
    USE SIGNAL ;
    PORT
      LAYER M6 ;
        RECT  0 129.616 0.192 129.648 ;
    END
  END coll_o[141]
  PIN coll_o[142]
    DIRECTION OUTPUT ;
    USE SIGNAL ;
    PORT
      LAYER M6 ;
        RECT  0 130.512 0.192 130.544 ;
    END
  END coll_o[142]
  PIN coll_o[143]
    DIRECTION OUTPUT ;
    USE SIGNAL ;
    PORT
      LAYER M6 ;
        RECT  0 131.408 0.192 131.44 ;
    END
  END coll_o[143]
  PIN coll_o[144]
    DIRECTION OUTPUT ;
    USE SIGNAL ;
    PORT
      LAYER M6 ;
        RECT  0 132.304 0.192 132.336 ;
    END
  END coll_o[144]
  PIN coll_o[145]
    DIRECTION OUTPUT ;
    USE SIGNAL ;
    PORT
      LAYER M6 ;
        RECT  0 133.2 0.192 133.232 ;
    END
  END coll_o[145]
  PIN coll_o[146]
    DIRECTION OUTPUT ;
    USE SIGNAL ;
    PORT
      LAYER M6 ;
        RECT  0 134.096 0.192 134.128 ;
    END
  END coll_o[146]
  PIN coll_o[147]
    DIRECTION OUTPUT ;
    USE SIGNAL ;
    PORT
      LAYER M6 ;
        RECT  0 135.056 0.192 135.088 ;
    END
  END coll_o[147]
  PIN coll_o[148]
    DIRECTION OUTPUT ;
    USE SIGNAL ;
    PORT
      LAYER M6 ;
        RECT  0 135.952 0.192 135.984 ;
    END
  END coll_o[148]
  PIN coll_o[149]
    DIRECTION OUTPUT ;
    USE SIGNAL ;
    PORT
      LAYER M6 ;
        RECT  0 136.848 0.192 136.88 ;
    END
  END coll_o[149]
  PIN coll_o[14]
    DIRECTION OUTPUT ;
    USE SIGNAL ;
    PORT
      LAYER M6 ;
        RECT  0 14.672 0.192 14.704 ;
    END
  END coll_o[14]
  PIN coll_o[150]
    DIRECTION OUTPUT ;
    USE SIGNAL ;
    PORT
      LAYER M6 ;
        RECT  0 137.744 0.192 137.776 ;
    END
  END coll_o[150]
  PIN coll_o[151]
    DIRECTION OUTPUT ;
    USE SIGNAL ;
    PORT
      LAYER M6 ;
        RECT  0 138.64 0.192 138.672 ;
    END
  END coll_o[151]
  PIN coll_o[152]
    DIRECTION OUTPUT ;
    USE SIGNAL ;
    PORT
      LAYER M6 ;
        RECT  0 139.536 0.192 139.568 ;
    END
  END coll_o[152]
  PIN coll_o[153]
    DIRECTION OUTPUT ;
    USE SIGNAL ;
    PORT
      LAYER M6 ;
        RECT  0 140.432 0.192 140.464 ;
    END
  END coll_o[153]
  PIN coll_o[154]
    DIRECTION OUTPUT ;
    USE SIGNAL ;
    PORT
      LAYER M6 ;
        RECT  0 141.392 0.192 141.424 ;
    END
  END coll_o[154]
  PIN coll_o[155]
    DIRECTION OUTPUT ;
    USE SIGNAL ;
    PORT
      LAYER M6 ;
        RECT  0 142.288 0.192 142.32 ;
    END
  END coll_o[155]
  PIN coll_o[156]
    DIRECTION OUTPUT ;
    USE SIGNAL ;
    PORT
      LAYER M6 ;
        RECT  0 143.184 0.192 143.216 ;
    END
  END coll_o[156]
  PIN coll_o[157]
    DIRECTION OUTPUT ;
    USE SIGNAL ;
    PORT
      LAYER M6 ;
        RECT  0 144.08 0.192 144.112 ;
    END
  END coll_o[157]
  PIN coll_o[158]
    DIRECTION OUTPUT ;
    USE SIGNAL ;
    PORT
      LAYER M6 ;
        RECT  0 144.976 0.192 145.008 ;
    END
  END coll_o[158]
  PIN coll_o[159]
    DIRECTION OUTPUT ;
    USE SIGNAL ;
    PORT
      LAYER M6 ;
        RECT  0 145.872 0.192 145.904 ;
    END
  END coll_o[159]
  PIN coll_o[15]
    DIRECTION OUTPUT ;
    USE SIGNAL ;
    PORT
      LAYER M6 ;
        RECT  0 15.568 0.192 15.6 ;
    END
  END coll_o[15]
  PIN coll_o[160]
    DIRECTION OUTPUT ;
    USE SIGNAL ;
    PORT
      LAYER M6 ;
        RECT  0 146.768 0.192 146.8 ;
    END
  END coll_o[160]
  PIN coll_o[161]
    DIRECTION OUTPUT ;
    USE SIGNAL ;
    PORT
      LAYER M6 ;
        RECT  0 147.728 0.192 147.76 ;
    END
  END coll_o[161]
  PIN coll_o[162]
    DIRECTION OUTPUT ;
    USE SIGNAL ;
    PORT
      LAYER M6 ;
        RECT  0 148.624 0.192 148.656 ;
    END
  END coll_o[162]
  PIN coll_o[163]
    DIRECTION OUTPUT ;
    USE SIGNAL ;
    PORT
      LAYER M6 ;
        RECT  0 149.52 0.192 149.552 ;
    END
  END coll_o[163]
  PIN coll_o[164]
    DIRECTION OUTPUT ;
    USE SIGNAL ;
    PORT
      LAYER M6 ;
        RECT  0 150.416 0.192 150.448 ;
    END
  END coll_o[164]
  PIN coll_o[165]
    DIRECTION OUTPUT ;
    USE SIGNAL ;
    PORT
      LAYER M6 ;
        RECT  0 151.312 0.192 151.344 ;
    END
  END coll_o[165]
  PIN coll_o[166]
    DIRECTION OUTPUT ;
    USE SIGNAL ;
    PORT
      LAYER M6 ;
        RECT  0 152.208 0.192 152.24 ;
    END
  END coll_o[166]
  PIN coll_o[167]
    DIRECTION OUTPUT ;
    USE SIGNAL ;
    PORT
      LAYER M6 ;
        RECT  0 153.104 0.192 153.136 ;
    END
  END coll_o[167]
  PIN coll_o[168]
    DIRECTION OUTPUT ;
    USE SIGNAL ;
    PORT
      LAYER M6 ;
        RECT  0 154.064 0.192 154.096 ;
    END
  END coll_o[168]
  PIN coll_o[169]
    DIRECTION OUTPUT ;
    USE SIGNAL ;
    PORT
      LAYER M6 ;
        RECT  0 154.96 0.192 154.992 ;
    END
  END coll_o[169]
  PIN coll_o[16]
    DIRECTION OUTPUT ;
    USE SIGNAL ;
    PORT
      LAYER M6 ;
        RECT  0 16.464 0.192 16.496 ;
    END
  END coll_o[16]
  PIN coll_o[170]
    DIRECTION OUTPUT ;
    USE SIGNAL ;
    PORT
      LAYER M6 ;
        RECT  0 155.856 0.192 155.888 ;
    END
  END coll_o[170]
  PIN coll_o[171]
    DIRECTION OUTPUT ;
    USE SIGNAL ;
    PORT
      LAYER M6 ;
        RECT  0 156.752 0.192 156.784 ;
    END
  END coll_o[171]
  PIN coll_o[172]
    DIRECTION OUTPUT ;
    USE SIGNAL ;
    PORT
      LAYER M6 ;
        RECT  0 157.648 0.192 157.68 ;
    END
  END coll_o[172]
  PIN coll_o[173]
    DIRECTION OUTPUT ;
    USE SIGNAL ;
    PORT
      LAYER M6 ;
        RECT  0 158.544 0.192 158.576 ;
    END
  END coll_o[173]
  PIN coll_o[174]
    DIRECTION OUTPUT ;
    USE SIGNAL ;
    PORT
      LAYER M6 ;
        RECT  0 159.44 0.192 159.472 ;
    END
  END coll_o[174]
  PIN coll_o[175]
    DIRECTION OUTPUT ;
    USE SIGNAL ;
    PORT
      LAYER M6 ;
        RECT  0 160.4 0.192 160.432 ;
    END
  END coll_o[175]
  PIN coll_o[176]
    DIRECTION OUTPUT ;
    USE SIGNAL ;
    PORT
      LAYER M6 ;
        RECT  0 161.296 0.192 161.328 ;
    END
  END coll_o[176]
  PIN coll_o[177]
    DIRECTION OUTPUT ;
    USE SIGNAL ;
    PORT
      LAYER M6 ;
        RECT  0 162.192 0.192 162.224 ;
    END
  END coll_o[177]
  PIN coll_o[178]
    DIRECTION OUTPUT ;
    USE SIGNAL ;
    PORT
      LAYER M6 ;
        RECT  0 163.088 0.192 163.12 ;
    END
  END coll_o[178]
  PIN coll_o[179]
    DIRECTION OUTPUT ;
    USE SIGNAL ;
    PORT
      LAYER M6 ;
        RECT  0 163.984 0.192 164.016 ;
    END
  END coll_o[179]
  PIN coll_o[17]
    DIRECTION OUTPUT ;
    USE SIGNAL ;
    PORT
      LAYER M6 ;
        RECT  0 17.36 0.192 17.392 ;
    END
  END coll_o[17]
  PIN coll_o[180]
    DIRECTION OUTPUT ;
    USE SIGNAL ;
    PORT
      LAYER M6 ;
        RECT  0 164.88 0.192 164.912 ;
    END
  END coll_o[180]
  PIN coll_o[181]
    DIRECTION OUTPUT ;
    USE SIGNAL ;
    PORT
      LAYER M6 ;
        RECT  0 165.776 0.192 165.808 ;
    END
  END coll_o[181]
  PIN coll_o[182]
    DIRECTION OUTPUT ;
    USE SIGNAL ;
    PORT
      LAYER M6 ;
        RECT  0 166.736 0.192 166.768 ;
    END
  END coll_o[182]
  PIN coll_o[183]
    DIRECTION OUTPUT ;
    USE SIGNAL ;
    PORT
      LAYER M6 ;
        RECT  0 167.632 0.192 167.664 ;
    END
  END coll_o[183]
  PIN coll_o[184]
    DIRECTION OUTPUT ;
    USE SIGNAL ;
    PORT
      LAYER M6 ;
        RECT  0 168.528 0.192 168.56 ;
    END
  END coll_o[184]
  PIN coll_o[185]
    DIRECTION OUTPUT ;
    USE SIGNAL ;
    PORT
      LAYER M6 ;
        RECT  0 169.424 0.192 169.456 ;
    END
  END coll_o[185]
  PIN coll_o[186]
    DIRECTION OUTPUT ;
    USE SIGNAL ;
    PORT
      LAYER M6 ;
        RECT  0 170.32 0.192 170.352 ;
    END
  END coll_o[186]
  PIN coll_o[187]
    DIRECTION OUTPUT ;
    USE SIGNAL ;
    PORT
      LAYER M6 ;
        RECT  0 171.216 0.192 171.248 ;
    END
  END coll_o[187]
  PIN coll_o[188]
    DIRECTION OUTPUT ;
    USE SIGNAL ;
    PORT
      LAYER M6 ;
        RECT  0 172.112 0.192 172.144 ;
    END
  END coll_o[188]
  PIN coll_o[189]
    DIRECTION OUTPUT ;
    USE SIGNAL ;
    PORT
      LAYER M6 ;
        RECT  0 173.072 0.192 173.104 ;
    END
  END coll_o[189]
  PIN coll_o[18]
    DIRECTION OUTPUT ;
    USE SIGNAL ;
    PORT
      LAYER M6 ;
        RECT  0 18.256 0.192 18.288 ;
    END
  END coll_o[18]
  PIN coll_o[190]
    DIRECTION OUTPUT ;
    USE SIGNAL ;
    PORT
      LAYER M6 ;
        RECT  0 173.968 0.192 174 ;
    END
  END coll_o[190]
  PIN coll_o[191]
    DIRECTION OUTPUT ;
    USE SIGNAL ;
    PORT
      LAYER M6 ;
        RECT  0 174.864 0.192 174.896 ;
    END
  END coll_o[191]
  PIN coll_o[192]
    DIRECTION OUTPUT ;
    USE SIGNAL ;
    PORT
      LAYER M6 ;
        RECT  0 175.76 0.192 175.792 ;
    END
  END coll_o[192]
  PIN coll_o[193]
    DIRECTION OUTPUT ;
    USE SIGNAL ;
    PORT
      LAYER M6 ;
        RECT  0 176.656 0.192 176.688 ;
    END
  END coll_o[193]
  PIN coll_o[194]
    DIRECTION OUTPUT ;
    USE SIGNAL ;
    PORT
      LAYER M6 ;
        RECT  0 177.552 0.192 177.584 ;
    END
  END coll_o[194]
  PIN coll_o[195]
    DIRECTION OUTPUT ;
    USE SIGNAL ;
    PORT
      LAYER M6 ;
        RECT  0 178.448 0.192 178.48 ;
    END
  END coll_o[195]
  PIN coll_o[196]
    DIRECTION OUTPUT ;
    USE SIGNAL ;
    PORT
      LAYER M6 ;
        RECT  0 179.408 0.192 179.44 ;
    END
  END coll_o[196]
  PIN coll_o[197]
    DIRECTION OUTPUT ;
    USE SIGNAL ;
    PORT
      LAYER M6 ;
        RECT  0 180.304 0.192 180.336 ;
    END
  END coll_o[197]
  PIN coll_o[198]
    DIRECTION OUTPUT ;
    USE SIGNAL ;
    PORT
      LAYER M6 ;
        RECT  0 181.2 0.192 181.232 ;
    END
  END coll_o[198]
  PIN coll_o[199]
    DIRECTION OUTPUT ;
    USE SIGNAL ;
    PORT
      LAYER M6 ;
        RECT  0 182.096 0.192 182.128 ;
    END
  END coll_o[199]
  PIN coll_o[19]
    DIRECTION OUTPUT ;
    USE SIGNAL ;
    PORT
      LAYER M6 ;
        RECT  0 19.152 0.192 19.184 ;
    END
  END coll_o[19]
  PIN coll_o[1]
    DIRECTION OUTPUT ;
    USE SIGNAL ;
    PORT
      LAYER M6 ;
        RECT  0 2.896 0.192 2.928 ;
    END
  END coll_o[1]
  PIN coll_o[200]
    DIRECTION OUTPUT ;
    USE SIGNAL ;
    PORT
      LAYER M6 ;
        RECT  0 182.992 0.192 183.024 ;
    END
  END coll_o[200]
  PIN coll_o[201]
    DIRECTION OUTPUT ;
    USE SIGNAL ;
    PORT
      LAYER M6 ;
        RECT  0 183.888 0.192 183.92 ;
    END
  END coll_o[201]
  PIN coll_o[202]
    DIRECTION OUTPUT ;
    USE SIGNAL ;
    PORT
      LAYER M6 ;
        RECT  0 184.784 0.192 184.816 ;
    END
  END coll_o[202]
  PIN coll_o[203]
    DIRECTION OUTPUT ;
    USE SIGNAL ;
    PORT
      LAYER M6 ;
        RECT  0 185.744 0.192 185.776 ;
    END
  END coll_o[203]
  PIN coll_o[204]
    DIRECTION OUTPUT ;
    USE SIGNAL ;
    PORT
      LAYER M6 ;
        RECT  0 186.64 0.192 186.672 ;
    END
  END coll_o[204]
  PIN coll_o[205]
    DIRECTION OUTPUT ;
    USE SIGNAL ;
    PORT
      LAYER M6 ;
        RECT  0 187.536 0.192 187.568 ;
    END
  END coll_o[205]
  PIN coll_o[206]
    DIRECTION OUTPUT ;
    USE SIGNAL ;
    PORT
      LAYER M6 ;
        RECT  0 188.432 0.192 188.464 ;
    END
  END coll_o[206]
  PIN coll_o[207]
    DIRECTION OUTPUT ;
    USE SIGNAL ;
    PORT
      LAYER M6 ;
        RECT  0 189.328 0.192 189.36 ;
    END
  END coll_o[207]
  PIN coll_o[208]
    DIRECTION OUTPUT ;
    USE SIGNAL ;
    PORT
      LAYER M6 ;
        RECT  0 190.224 0.192 190.256 ;
    END
  END coll_o[208]
  PIN coll_o[209]
    DIRECTION OUTPUT ;
    USE SIGNAL ;
    PORT
      LAYER M6 ;
        RECT  0 191.12 0.192 191.152 ;
    END
  END coll_o[209]
  PIN coll_o[20]
    DIRECTION OUTPUT ;
    USE SIGNAL ;
    PORT
      LAYER M6 ;
        RECT  0 20.048 0.192 20.08 ;
    END
  END coll_o[20]
  PIN coll_o[210]
    DIRECTION OUTPUT ;
    USE SIGNAL ;
    PORT
      LAYER M6 ;
        RECT  0 192.08 0.192 192.112 ;
    END
  END coll_o[210]
  PIN coll_o[211]
    DIRECTION OUTPUT ;
    USE SIGNAL ;
    PORT
      LAYER M6 ;
        RECT  0 192.976 0.192 193.008 ;
    END
  END coll_o[211]
  PIN coll_o[212]
    DIRECTION OUTPUT ;
    USE SIGNAL ;
    PORT
      LAYER M6 ;
        RECT  0 193.872 0.192 193.904 ;
    END
  END coll_o[212]
  PIN coll_o[213]
    DIRECTION OUTPUT ;
    USE SIGNAL ;
    PORT
      LAYER M6 ;
        RECT  0 194.768 0.192 194.8 ;
    END
  END coll_o[213]
  PIN coll_o[214]
    DIRECTION OUTPUT ;
    USE SIGNAL ;
    PORT
      LAYER M6 ;
        RECT  0 195.664 0.192 195.696 ;
    END
  END coll_o[214]
  PIN coll_o[215]
    DIRECTION OUTPUT ;
    USE SIGNAL ;
    PORT
      LAYER M6 ;
        RECT  0 196.56 0.192 196.592 ;
    END
  END coll_o[215]
  PIN coll_o[216]
    DIRECTION OUTPUT ;
    USE SIGNAL ;
    PORT
      LAYER M6 ;
        RECT  0 197.456 0.192 197.488 ;
    END
  END coll_o[216]
  PIN coll_o[217]
    DIRECTION OUTPUT ;
    USE SIGNAL ;
    PORT
      LAYER M6 ;
        RECT  0 198.416 0.192 198.448 ;
    END
  END coll_o[217]
  PIN coll_o[218]
    DIRECTION OUTPUT ;
    USE SIGNAL ;
    PORT
      LAYER M6 ;
        RECT  0 199.312 0.192 199.344 ;
    END
  END coll_o[218]
  PIN coll_o[219]
    DIRECTION OUTPUT ;
    USE SIGNAL ;
    PORT
      LAYER M6 ;
        RECT  0 200.208 0.192 200.24 ;
    END
  END coll_o[219]
  PIN coll_o[21]
    DIRECTION OUTPUT ;
    USE SIGNAL ;
    PORT
      LAYER M6 ;
        RECT  0 21.008 0.192 21.04 ;
    END
  END coll_o[21]
  PIN coll_o[220]
    DIRECTION OUTPUT ;
    USE SIGNAL ;
    PORT
      LAYER M6 ;
        RECT  0 201.104 0.192 201.136 ;
    END
  END coll_o[220]
  PIN coll_o[221]
    DIRECTION OUTPUT ;
    USE SIGNAL ;
    PORT
      LAYER M6 ;
        RECT  0 202 0.192 202.032 ;
    END
  END coll_o[221]
  PIN coll_o[222]
    DIRECTION OUTPUT ;
    USE SIGNAL ;
    PORT
      LAYER M6 ;
        RECT  0 202.896 0.192 202.928 ;
    END
  END coll_o[222]
  PIN coll_o[223]
    DIRECTION OUTPUT ;
    USE SIGNAL ;
    PORT
      LAYER M6 ;
        RECT  0 203.792 0.192 203.824 ;
    END
  END coll_o[223]
  PIN coll_o[224]
    DIRECTION OUTPUT ;
    USE SIGNAL ;
    PORT
      LAYER M6 ;
        RECT  0 204.752 0.192 204.784 ;
    END
  END coll_o[224]
  PIN coll_o[225]
    DIRECTION OUTPUT ;
    USE SIGNAL ;
    PORT
      LAYER M6 ;
        RECT  0 205.648 0.192 205.68 ;
    END
  END coll_o[225]
  PIN coll_o[226]
    DIRECTION OUTPUT ;
    USE SIGNAL ;
    PORT
      LAYER M6 ;
        RECT  0 206.544 0.192 206.576 ;
    END
  END coll_o[226]
  PIN coll_o[227]
    DIRECTION OUTPUT ;
    USE SIGNAL ;
    PORT
      LAYER M6 ;
        RECT  0 207.44 0.192 207.472 ;
    END
  END coll_o[227]
  PIN coll_o[228]
    DIRECTION OUTPUT ;
    USE SIGNAL ;
    PORT
      LAYER M6 ;
        RECT  0 208.336 0.192 208.368 ;
    END
  END coll_o[228]
  PIN coll_o[229]
    DIRECTION OUTPUT ;
    USE SIGNAL ;
    PORT
      LAYER M6 ;
        RECT  0 209.232 0.192 209.264 ;
    END
  END coll_o[229]
  PIN coll_o[22]
    DIRECTION OUTPUT ;
    USE SIGNAL ;
    PORT
      LAYER M6 ;
        RECT  0 21.904 0.192 21.936 ;
    END
  END coll_o[22]
  PIN coll_o[230]
    DIRECTION OUTPUT ;
    USE SIGNAL ;
    PORT
      LAYER M6 ;
        RECT  0 210.128 0.192 210.16 ;
    END
  END coll_o[230]
  PIN coll_o[231]
    DIRECTION OUTPUT ;
    USE SIGNAL ;
    PORT
      LAYER M6 ;
        RECT  0 211.088 0.192 211.12 ;
    END
  END coll_o[231]
  PIN coll_o[232]
    DIRECTION OUTPUT ;
    USE SIGNAL ;
    PORT
      LAYER M6 ;
        RECT  0 211.984 0.192 212.016 ;
    END
  END coll_o[232]
  PIN coll_o[233]
    DIRECTION OUTPUT ;
    USE SIGNAL ;
    PORT
      LAYER M6 ;
        RECT  0 212.88 0.192 212.912 ;
    END
  END coll_o[233]
  PIN coll_o[234]
    DIRECTION OUTPUT ;
    USE SIGNAL ;
    PORT
      LAYER M6 ;
        RECT  0 213.776 0.192 213.808 ;
    END
  END coll_o[234]
  PIN coll_o[235]
    DIRECTION OUTPUT ;
    USE SIGNAL ;
    PORT
      LAYER M6 ;
        RECT  0 214.672 0.192 214.704 ;
    END
  END coll_o[235]
  PIN coll_o[236]
    DIRECTION OUTPUT ;
    USE SIGNAL ;
    PORT
      LAYER M6 ;
        RECT  0 215.568 0.192 215.6 ;
    END
  END coll_o[236]
  PIN coll_o[237]
    DIRECTION OUTPUT ;
    USE SIGNAL ;
    PORT
      LAYER M6 ;
        RECT  0 216.464 0.192 216.496 ;
    END
  END coll_o[237]
  PIN coll_o[238]
    DIRECTION OUTPUT ;
    USE SIGNAL ;
    PORT
      LAYER M6 ;
        RECT  0 217.424 0.192 217.456 ;
    END
  END coll_o[238]
  PIN coll_o[239]
    DIRECTION OUTPUT ;
    USE SIGNAL ;
    PORT
      LAYER M6 ;
        RECT  0 218.32 0.192 218.352 ;
    END
  END coll_o[239]
  PIN coll_o[23]
    DIRECTION OUTPUT ;
    USE SIGNAL ;
    PORT
      LAYER M6 ;
        RECT  0 22.8 0.192 22.832 ;
    END
  END coll_o[23]
  PIN coll_o[240]
    DIRECTION OUTPUT ;
    USE SIGNAL ;
    PORT
      LAYER M6 ;
        RECT  0 219.216 0.192 219.248 ;
    END
  END coll_o[240]
  PIN coll_o[241]
    DIRECTION OUTPUT ;
    USE SIGNAL ;
    PORT
      LAYER M6 ;
        RECT  0 220.112 0.192 220.144 ;
    END
  END coll_o[241]
  PIN coll_o[242]
    DIRECTION OUTPUT ;
    USE SIGNAL ;
    PORT
      LAYER M6 ;
        RECT  0 221.008 0.192 221.04 ;
    END
  END coll_o[242]
  PIN coll_o[243]
    DIRECTION OUTPUT ;
    USE SIGNAL ;
    PORT
      LAYER M6 ;
        RECT  0 221.904 0.192 221.936 ;
    END
  END coll_o[243]
  PIN coll_o[244]
    DIRECTION OUTPUT ;
    USE SIGNAL ;
    PORT
      LAYER M6 ;
        RECT  0 222.8 0.192 222.832 ;
    END
  END coll_o[244]
  PIN coll_o[245]
    DIRECTION OUTPUT ;
    USE SIGNAL ;
    PORT
      LAYER M6 ;
        RECT  0 223.76 0.192 223.792 ;
    END
  END coll_o[245]
  PIN coll_o[246]
    DIRECTION OUTPUT ;
    USE SIGNAL ;
    PORT
      LAYER M6 ;
        RECT  0 224.656 0.192 224.688 ;
    END
  END coll_o[246]
  PIN coll_o[247]
    DIRECTION OUTPUT ;
    USE SIGNAL ;
    PORT
      LAYER M6 ;
        RECT  0 225.552 0.192 225.584 ;
    END
  END coll_o[247]
  PIN coll_o[248]
    DIRECTION OUTPUT ;
    USE SIGNAL ;
    PORT
      LAYER M6 ;
        RECT  0 226.448 0.192 226.48 ;
    END
  END coll_o[248]
  PIN coll_o[249]
    DIRECTION OUTPUT ;
    USE SIGNAL ;
    PORT
      LAYER M6 ;
        RECT  0 227.344 0.192 227.376 ;
    END
  END coll_o[249]
  PIN coll_o[24]
    DIRECTION OUTPUT ;
    USE SIGNAL ;
    PORT
      LAYER M6 ;
        RECT  0 23.696 0.192 23.728 ;
    END
  END coll_o[24]
  PIN coll_o[250]
    DIRECTION OUTPUT ;
    USE SIGNAL ;
    PORT
      LAYER M6 ;
        RECT  0 228.24 0.192 228.272 ;
    END
  END coll_o[250]
  PIN coll_o[251]
    DIRECTION OUTPUT ;
    USE SIGNAL ;
    PORT
      LAYER M6 ;
        RECT  0 229.136 0.192 229.168 ;
    END
  END coll_o[251]
  PIN coll_o[252]
    DIRECTION OUTPUT ;
    USE SIGNAL ;
    PORT
      LAYER M6 ;
        RECT  0 230.096 0.192 230.128 ;
    END
  END coll_o[252]
  PIN coll_o[253]
    DIRECTION OUTPUT ;
    USE SIGNAL ;
    PORT
      LAYER M6 ;
        RECT  0 230.992 0.192 231.024 ;
    END
  END coll_o[253]
  PIN coll_o[254]
    DIRECTION OUTPUT ;
    USE SIGNAL ;
    PORT
      LAYER M6 ;
        RECT  0 231.888 0.192 231.92 ;
    END
  END coll_o[254]
  PIN coll_o[255]
    DIRECTION OUTPUT ;
    USE SIGNAL ;
    PORT
      LAYER M6 ;
        RECT  0 232.784 0.192 232.816 ;
    END
  END coll_o[255]
  PIN coll_o[256]
    DIRECTION OUTPUT ;
    USE SIGNAL ;
    PORT
      LAYER M6 ;
        RECT  0 233.68 0.192 233.712 ;
    END
  END coll_o[256]
  PIN coll_o[257]
    DIRECTION OUTPUT ;
    USE SIGNAL ;
    PORT
      LAYER M6 ;
        RECT  0 234.576 0.192 234.608 ;
    END
  END coll_o[257]
  PIN coll_o[258]
    DIRECTION OUTPUT ;
    USE SIGNAL ;
    PORT
      LAYER M6 ;
        RECT  0 235.472 0.192 235.504 ;
    END
  END coll_o[258]
  PIN coll_o[259]
    DIRECTION OUTPUT ;
    USE SIGNAL ;
    PORT
      LAYER M6 ;
        RECT  0 236.432 0.192 236.464 ;
    END
  END coll_o[259]
  PIN coll_o[25]
    DIRECTION OUTPUT ;
    USE SIGNAL ;
    PORT
      LAYER M6 ;
        RECT  0 24.592 0.192 24.624 ;
    END
  END coll_o[25]
  PIN coll_o[260]
    DIRECTION OUTPUT ;
    USE SIGNAL ;
    PORT
      LAYER M6 ;
        RECT  0 237.328 0.192 237.36 ;
    END
  END coll_o[260]
  PIN coll_o[261]
    DIRECTION OUTPUT ;
    USE SIGNAL ;
    PORT
      LAYER M6 ;
        RECT  0 238.224 0.192 238.256 ;
    END
  END coll_o[261]
  PIN coll_o[262]
    DIRECTION OUTPUT ;
    USE SIGNAL ;
    PORT
      LAYER M6 ;
        RECT  0 239.12 0.192 239.152 ;
    END
  END coll_o[262]
  PIN coll_o[263]
    DIRECTION OUTPUT ;
    USE SIGNAL ;
    PORT
      LAYER M6 ;
        RECT  0 240.016 0.192 240.048 ;
    END
  END coll_o[263]
  PIN coll_o[264]
    DIRECTION OUTPUT ;
    USE SIGNAL ;
    PORT
      LAYER M6 ;
        RECT  0 240.912 0.192 240.944 ;
    END
  END coll_o[264]
  PIN coll_o[265]
    DIRECTION OUTPUT ;
    USE SIGNAL ;
    PORT
      LAYER M6 ;
        RECT  0 241.808 0.192 241.84 ;
    END
  END coll_o[265]
  PIN coll_o[266]
    DIRECTION OUTPUT ;
    USE SIGNAL ;
    PORT
      LAYER M6 ;
        RECT  0 242.768 0.192 242.8 ;
    END
  END coll_o[266]
  PIN coll_o[267]
    DIRECTION OUTPUT ;
    USE SIGNAL ;
    PORT
      LAYER M6 ;
        RECT  0 243.664 0.192 243.696 ;
    END
  END coll_o[267]
  PIN coll_o[268]
    DIRECTION OUTPUT ;
    USE SIGNAL ;
    PORT
      LAYER M6 ;
        RECT  0 244.56 0.192 244.592 ;
    END
  END coll_o[268]
  PIN coll_o[269]
    DIRECTION OUTPUT ;
    USE SIGNAL ;
    PORT
      LAYER M6 ;
        RECT  0 245.456 0.192 245.488 ;
    END
  END coll_o[269]
  PIN coll_o[26]
    DIRECTION OUTPUT ;
    USE SIGNAL ;
    PORT
      LAYER M6 ;
        RECT  0 25.488 0.192 25.52 ;
    END
  END coll_o[26]
  PIN coll_o[270]
    DIRECTION OUTPUT ;
    USE SIGNAL ;
    PORT
      LAYER M6 ;
        RECT  0 246.352 0.192 246.384 ;
    END
  END coll_o[270]
  PIN coll_o[271]
    DIRECTION OUTPUT ;
    USE SIGNAL ;
    PORT
      LAYER M6 ;
        RECT  0 247.248 0.192 247.28 ;
    END
  END coll_o[271]
  PIN coll_o[272]
    DIRECTION OUTPUT ;
    USE SIGNAL ;
    PORT
      LAYER M6 ;
        RECT  0 248.144 0.192 248.176 ;
    END
  END coll_o[272]
  PIN coll_o[273]
    DIRECTION OUTPUT ;
    USE SIGNAL ;
    PORT
      LAYER M6 ;
        RECT  0 249.104 0.192 249.136 ;
    END
  END coll_o[273]
  PIN coll_o[274]
    DIRECTION OUTPUT ;
    USE SIGNAL ;
    PORT
      LAYER M6 ;
        RECT  0 250 0.192 250.032 ;
    END
  END coll_o[274]
  PIN coll_o[275]
    DIRECTION OUTPUT ;
    USE SIGNAL ;
    PORT
      LAYER M6 ;
        RECT  0 250.896 0.192 250.928 ;
    END
  END coll_o[275]
  PIN coll_o[276]
    DIRECTION OUTPUT ;
    USE SIGNAL ;
    PORT
      LAYER M6 ;
        RECT  0 251.792 0.192 251.824 ;
    END
  END coll_o[276]
  PIN coll_o[277]
    DIRECTION OUTPUT ;
    USE SIGNAL ;
    PORT
      LAYER M6 ;
        RECT  0 252.688 0.192 252.72 ;
    END
  END coll_o[277]
  PIN coll_o[278]
    DIRECTION OUTPUT ;
    USE SIGNAL ;
    PORT
      LAYER M6 ;
        RECT  0 253.584 0.192 253.616 ;
    END
  END coll_o[278]
  PIN coll_o[279]
    DIRECTION OUTPUT ;
    USE SIGNAL ;
    PORT
      LAYER M6 ;
        RECT  0 254.48 0.192 254.512 ;
    END
  END coll_o[279]
  PIN coll_o[27]
    DIRECTION OUTPUT ;
    USE SIGNAL ;
    PORT
      LAYER M6 ;
        RECT  0 26.384 0.192 26.416 ;
    END
  END coll_o[27]
  PIN coll_o[280]
    DIRECTION OUTPUT ;
    USE SIGNAL ;
    PORT
      LAYER M6 ;
        RECT  0 255.44 0.192 255.472 ;
    END
  END coll_o[280]
  PIN coll_o[281]
    DIRECTION OUTPUT ;
    USE SIGNAL ;
    PORT
      LAYER M6 ;
        RECT  0 256.336 0.192 256.368 ;
    END
  END coll_o[281]
  PIN coll_o[282]
    DIRECTION OUTPUT ;
    USE SIGNAL ;
    PORT
      LAYER M6 ;
        RECT  0 257.232 0.192 257.264 ;
    END
  END coll_o[282]
  PIN coll_o[283]
    DIRECTION OUTPUT ;
    USE SIGNAL ;
    PORT
      LAYER M6 ;
        RECT  0 258.128 0.192 258.16 ;
    END
  END coll_o[283]
  PIN coll_o[284]
    DIRECTION OUTPUT ;
    USE SIGNAL ;
    PORT
      LAYER M6 ;
        RECT  0 259.024 0.192 259.056 ;
    END
  END coll_o[284]
  PIN coll_o[285]
    DIRECTION OUTPUT ;
    USE SIGNAL ;
    PORT
      LAYER M6 ;
        RECT  0 259.92 0.192 259.952 ;
    END
  END coll_o[285]
  PIN coll_o[286]
    DIRECTION OUTPUT ;
    USE SIGNAL ;
    PORT
      LAYER M6 ;
        RECT  0 260.816 0.192 260.848 ;
    END
  END coll_o[286]
  PIN coll_o[287]
    DIRECTION OUTPUT ;
    USE SIGNAL ;
    PORT
      LAYER M6 ;
        RECT  0 261.776 0.192 261.808 ;
    END
  END coll_o[287]
  PIN coll_o[288]
    DIRECTION OUTPUT ;
    USE SIGNAL ;
    PORT
      LAYER M6 ;
        RECT  0 262.672 0.192 262.704 ;
    END
  END coll_o[288]
  PIN coll_o[289]
    DIRECTION OUTPUT ;
    USE SIGNAL ;
    PORT
      LAYER M6 ;
        RECT  0 263.568 0.192 263.6 ;
    END
  END coll_o[289]
  PIN coll_o[28]
    DIRECTION OUTPUT ;
    USE SIGNAL ;
    PORT
      LAYER M6 ;
        RECT  0 27.344 0.192 27.376 ;
    END
  END coll_o[28]
  PIN coll_o[290]
    DIRECTION OUTPUT ;
    USE SIGNAL ;
    PORT
      LAYER M6 ;
        RECT  0 264.464 0.192 264.496 ;
    END
  END coll_o[290]
  PIN coll_o[291]
    DIRECTION OUTPUT ;
    USE SIGNAL ;
    PORT
      LAYER M6 ;
        RECT  0 265.36 0.192 265.392 ;
    END
  END coll_o[291]
  PIN coll_o[292]
    DIRECTION OUTPUT ;
    USE SIGNAL ;
    PORT
      LAYER M6 ;
        RECT  0 266.256 0.192 266.288 ;
    END
  END coll_o[292]
  PIN coll_o[293]
    DIRECTION OUTPUT ;
    USE SIGNAL ;
    PORT
      LAYER M6 ;
        RECT  0 267.152 0.192 267.184 ;
    END
  END coll_o[293]
  PIN coll_o[294]
    DIRECTION OUTPUT ;
    USE SIGNAL ;
    PORT
      LAYER M6 ;
        RECT  0 268.112 0.192 268.144 ;
    END
  END coll_o[294]
  PIN coll_o[295]
    DIRECTION OUTPUT ;
    USE SIGNAL ;
    PORT
      LAYER M6 ;
        RECT  0 269.008 0.192 269.04 ;
    END
  END coll_o[295]
  PIN coll_o[296]
    DIRECTION OUTPUT ;
    USE SIGNAL ;
    PORT
      LAYER M6 ;
        RECT  0 269.904 0.192 269.936 ;
    END
  END coll_o[296]
  PIN coll_o[297]
    DIRECTION OUTPUT ;
    USE SIGNAL ;
    PORT
      LAYER M6 ;
        RECT  0 270.8 0.192 270.832 ;
    END
  END coll_o[297]
  PIN coll_o[298]
    DIRECTION OUTPUT ;
    USE SIGNAL ;
    PORT
      LAYER M6 ;
        RECT  0 271.696 0.192 271.728 ;
    END
  END coll_o[298]
  PIN coll_o[299]
    DIRECTION OUTPUT ;
    USE SIGNAL ;
    PORT
      LAYER M6 ;
        RECT  0 272.592 0.192 272.624 ;
    END
  END coll_o[299]
  PIN coll_o[29]
    DIRECTION OUTPUT ;
    USE SIGNAL ;
    PORT
      LAYER M6 ;
        RECT  0 28.24 0.192 28.272 ;
    END
  END coll_o[29]
  PIN coll_o[2]
    DIRECTION OUTPUT ;
    USE SIGNAL ;
    PORT
      LAYER M6 ;
        RECT  0 3.792 0.192 3.824 ;
    END
  END coll_o[2]
  PIN coll_o[300]
    DIRECTION OUTPUT ;
    USE SIGNAL ;
    PORT
      LAYER M6 ;
        RECT  0 273.488 0.192 273.52 ;
    END
  END coll_o[300]
  PIN coll_o[301]
    DIRECTION OUTPUT ;
    USE SIGNAL ;
    PORT
      LAYER M6 ;
        RECT  0 274.448 0.192 274.48 ;
    END
  END coll_o[301]
  PIN coll_o[302]
    DIRECTION OUTPUT ;
    USE SIGNAL ;
    PORT
      LAYER M6 ;
        RECT  0 275.344 0.192 275.376 ;
    END
  END coll_o[302]
  PIN coll_o[303]
    DIRECTION OUTPUT ;
    USE SIGNAL ;
    PORT
      LAYER M6 ;
        RECT  0 276.24 0.192 276.272 ;
    END
  END coll_o[303]
  PIN coll_o[304]
    DIRECTION OUTPUT ;
    USE SIGNAL ;
    PORT
      LAYER M6 ;
        RECT  0 277.136 0.192 277.168 ;
    END
  END coll_o[304]
  PIN coll_o[305]
    DIRECTION OUTPUT ;
    USE SIGNAL ;
    PORT
      LAYER M6 ;
        RECT  0 278.032 0.192 278.064 ;
    END
  END coll_o[305]
  PIN coll_o[306]
    DIRECTION OUTPUT ;
    USE SIGNAL ;
    PORT
      LAYER M6 ;
        RECT  0 278.928 0.192 278.96 ;
    END
  END coll_o[306]
  PIN coll_o[307]
    DIRECTION OUTPUT ;
    USE SIGNAL ;
    PORT
      LAYER M6 ;
        RECT  0 279.824 0.192 279.856 ;
    END
  END coll_o[307]
  PIN coll_o[308]
    DIRECTION OUTPUT ;
    USE SIGNAL ;
    PORT
      LAYER M6 ;
        RECT  0 280.784 0.192 280.816 ;
    END
  END coll_o[308]
  PIN coll_o[309]
    DIRECTION OUTPUT ;
    USE SIGNAL ;
    PORT
      LAYER M6 ;
        RECT  0 281.68 0.192 281.712 ;
    END
  END coll_o[309]
  PIN coll_o[30]
    DIRECTION OUTPUT ;
    USE SIGNAL ;
    PORT
      LAYER M6 ;
        RECT  0 29.136 0.192 29.168 ;
    END
  END coll_o[30]
  PIN coll_o[310]
    DIRECTION OUTPUT ;
    USE SIGNAL ;
    PORT
      LAYER M6 ;
        RECT  0 282.576 0.192 282.608 ;
    END
  END coll_o[310]
  PIN coll_o[311]
    DIRECTION OUTPUT ;
    USE SIGNAL ;
    PORT
      LAYER M6 ;
        RECT  0 283.472 0.192 283.504 ;
    END
  END coll_o[311]
  PIN coll_o[312]
    DIRECTION OUTPUT ;
    USE SIGNAL ;
    PORT
      LAYER M6 ;
        RECT  0 284.368 0.192 284.4 ;
    END
  END coll_o[312]
  PIN coll_o[313]
    DIRECTION OUTPUT ;
    USE SIGNAL ;
    PORT
      LAYER M6 ;
        RECT  0 285.264 0.192 285.296 ;
    END
  END coll_o[313]
  PIN coll_o[314]
    DIRECTION OUTPUT ;
    USE SIGNAL ;
    PORT
      LAYER M6 ;
        RECT  0 286.16 0.192 286.192 ;
    END
  END coll_o[314]
  PIN coll_o[315]
    DIRECTION OUTPUT ;
    USE SIGNAL ;
    PORT
      LAYER M6 ;
        RECT  0 287.12 0.192 287.152 ;
    END
  END coll_o[315]
  PIN coll_o[316]
    DIRECTION OUTPUT ;
    USE SIGNAL ;
    PORT
      LAYER M6 ;
        RECT  0 288.016 0.192 288.048 ;
    END
  END coll_o[316]
  PIN coll_o[317]
    DIRECTION OUTPUT ;
    USE SIGNAL ;
    PORT
      LAYER M6 ;
        RECT  0 288.912 0.192 288.944 ;
    END
  END coll_o[317]
  PIN coll_o[318]
    DIRECTION OUTPUT ;
    USE SIGNAL ;
    PORT
      LAYER M6 ;
        RECT  0 289.808 0.192 289.84 ;
    END
  END coll_o[318]
  PIN coll_o[319]
    DIRECTION OUTPUT ;
    USE SIGNAL ;
    PORT
      LAYER M6 ;
        RECT  0 290.704 0.192 290.736 ;
    END
  END coll_o[319]
  PIN coll_o[31]
    DIRECTION OUTPUT ;
    USE SIGNAL ;
    PORT
      LAYER M6 ;
        RECT  0 30.032 0.192 30.064 ;
    END
  END coll_o[31]
  PIN coll_o[320]
    DIRECTION OUTPUT ;
    USE SIGNAL ;
    PORT
      LAYER M6 ;
        RECT  0 291.6 0.192 291.632 ;
    END
  END coll_o[320]
  PIN coll_o[321]
    DIRECTION OUTPUT ;
    USE SIGNAL ;
    PORT
      LAYER M6 ;
        RECT  0 292.496 0.192 292.528 ;
    END
  END coll_o[321]
  PIN coll_o[322]
    DIRECTION OUTPUT ;
    USE SIGNAL ;
    PORT
      LAYER M6 ;
        RECT  0 293.456 0.192 293.488 ;
    END
  END coll_o[322]
  PIN coll_o[323]
    DIRECTION OUTPUT ;
    USE SIGNAL ;
    PORT
      LAYER M6 ;
        RECT  0 294.352 0.192 294.384 ;
    END
  END coll_o[323]
  PIN coll_o[324]
    DIRECTION OUTPUT ;
    USE SIGNAL ;
    PORT
      LAYER M6 ;
        RECT  0 295.248 0.192 295.28 ;
    END
  END coll_o[324]
  PIN coll_o[325]
    DIRECTION OUTPUT ;
    USE SIGNAL ;
    PORT
      LAYER M6 ;
        RECT  0 296.144 0.192 296.176 ;
    END
  END coll_o[325]
  PIN coll_o[326]
    DIRECTION OUTPUT ;
    USE SIGNAL ;
    PORT
      LAYER M6 ;
        RECT  0 297.04 0.192 297.072 ;
    END
  END coll_o[326]
  PIN coll_o[327]
    DIRECTION OUTPUT ;
    USE SIGNAL ;
    PORT
      LAYER M6 ;
        RECT  0 297.936 0.192 297.968 ;
    END
  END coll_o[327]
  PIN coll_o[328]
    DIRECTION OUTPUT ;
    USE SIGNAL ;
    PORT
      LAYER M6 ;
        RECT  0 298.832 0.192 298.864 ;
    END
  END coll_o[328]
  PIN coll_o[329]
    DIRECTION OUTPUT ;
    USE SIGNAL ;
    PORT
      LAYER M6 ;
        RECT  0 299.792 0.192 299.824 ;
    END
  END coll_o[329]
  PIN coll_o[32]
    DIRECTION OUTPUT ;
    USE SIGNAL ;
    PORT
      LAYER M6 ;
        RECT  0 30.928 0.192 30.96 ;
    END
  END coll_o[32]
  PIN coll_o[330]
    DIRECTION OUTPUT ;
    USE SIGNAL ;
    PORT
      LAYER M6 ;
        RECT  0 300.688 0.192 300.72 ;
    END
  END coll_o[330]
  PIN coll_o[331]
    DIRECTION OUTPUT ;
    USE SIGNAL ;
    PORT
      LAYER M6 ;
        RECT  0 301.584 0.192 301.616 ;
    END
  END coll_o[331]
  PIN coll_o[332]
    DIRECTION OUTPUT ;
    USE SIGNAL ;
    PORT
      LAYER M6 ;
        RECT  0 302.48 0.192 302.512 ;
    END
  END coll_o[332]
  PIN coll_o[333]
    DIRECTION OUTPUT ;
    USE SIGNAL ;
    PORT
      LAYER M6 ;
        RECT  0 303.376 0.192 303.408 ;
    END
  END coll_o[333]
  PIN coll_o[334]
    DIRECTION OUTPUT ;
    USE SIGNAL ;
    PORT
      LAYER M6 ;
        RECT  0 304.272 0.192 304.304 ;
    END
  END coll_o[334]
  PIN coll_o[335]
    DIRECTION OUTPUT ;
    USE SIGNAL ;
    PORT
      LAYER M6 ;
        RECT  0 305.168 0.192 305.2 ;
    END
  END coll_o[335]
  PIN coll_o[336]
    DIRECTION OUTPUT ;
    USE SIGNAL ;
    PORT
      LAYER M6 ;
        RECT  0 306.128 0.192 306.16 ;
    END
  END coll_o[336]
  PIN coll_o[337]
    DIRECTION OUTPUT ;
    USE SIGNAL ;
    PORT
      LAYER M6 ;
        RECT  0 307.024 0.192 307.056 ;
    END
  END coll_o[337]
  PIN coll_o[338]
    DIRECTION OUTPUT ;
    USE SIGNAL ;
    PORT
      LAYER M6 ;
        RECT  0 307.92 0.192 307.952 ;
    END
  END coll_o[338]
  PIN coll_o[339]
    DIRECTION OUTPUT ;
    USE SIGNAL ;
    PORT
      LAYER M6 ;
        RECT  0 308.816 0.192 308.848 ;
    END
  END coll_o[339]
  PIN coll_o[33]
    DIRECTION OUTPUT ;
    USE SIGNAL ;
    PORT
      LAYER M6 ;
        RECT  0 31.824 0.192 31.856 ;
    END
  END coll_o[33]
  PIN coll_o[340]
    DIRECTION OUTPUT ;
    USE SIGNAL ;
    PORT
      LAYER M6 ;
        RECT  0 309.712 0.192 309.744 ;
    END
  END coll_o[340]
  PIN coll_o[341]
    DIRECTION OUTPUT ;
    USE SIGNAL ;
    PORT
      LAYER M6 ;
        RECT  0 310.608 0.192 310.64 ;
    END
  END coll_o[341]
  PIN coll_o[342]
    DIRECTION OUTPUT ;
    USE SIGNAL ;
    PORT
      LAYER M6 ;
        RECT  0 311.504 0.192 311.536 ;
    END
  END coll_o[342]
  PIN coll_o[343]
    DIRECTION OUTPUT ;
    USE SIGNAL ;
    PORT
      LAYER M6 ;
        RECT  0 312.464 0.192 312.496 ;
    END
  END coll_o[343]
  PIN coll_o[344]
    DIRECTION OUTPUT ;
    USE SIGNAL ;
    PORT
      LAYER M6 ;
        RECT  0 313.36 0.192 313.392 ;
    END
  END coll_o[344]
  PIN coll_o[345]
    DIRECTION OUTPUT ;
    USE SIGNAL ;
    PORT
      LAYER M6 ;
        RECT  0 314.256 0.192 314.288 ;
    END
  END coll_o[345]
  PIN coll_o[346]
    DIRECTION OUTPUT ;
    USE SIGNAL ;
    PORT
      LAYER M6 ;
        RECT  0 315.152 0.192 315.184 ;
    END
  END coll_o[346]
  PIN coll_o[347]
    DIRECTION OUTPUT ;
    USE SIGNAL ;
    PORT
      LAYER M6 ;
        RECT  0 316.048 0.192 316.08 ;
    END
  END coll_o[347]
  PIN coll_o[348]
    DIRECTION OUTPUT ;
    USE SIGNAL ;
    PORT
      LAYER M6 ;
        RECT  0 316.944 0.192 316.976 ;
    END
  END coll_o[348]
  PIN coll_o[349]
    DIRECTION OUTPUT ;
    USE SIGNAL ;
    PORT
      LAYER M6 ;
        RECT  0 317.84 0.192 317.872 ;
    END
  END coll_o[349]
  PIN coll_o[34]
    DIRECTION OUTPUT ;
    USE SIGNAL ;
    PORT
      LAYER M6 ;
        RECT  0 32.72 0.192 32.752 ;
    END
  END coll_o[34]
  PIN coll_o[350]
    DIRECTION OUTPUT ;
    USE SIGNAL ;
    PORT
      LAYER M6 ;
        RECT  0 318.8 0.192 318.832 ;
    END
  END coll_o[350]
  PIN coll_o[351]
    DIRECTION OUTPUT ;
    USE SIGNAL ;
    PORT
      LAYER M6 ;
        RECT  0 319.696 0.192 319.728 ;
    END
  END coll_o[351]
  PIN coll_o[352]
    DIRECTION OUTPUT ;
    USE SIGNAL ;
    PORT
      LAYER M6 ;
        RECT  0 320.592 0.192 320.624 ;
    END
  END coll_o[352]
  PIN coll_o[353]
    DIRECTION OUTPUT ;
    USE SIGNAL ;
    PORT
      LAYER M6 ;
        RECT  0 321.488 0.192 321.52 ;
    END
  END coll_o[353]
  PIN coll_o[354]
    DIRECTION OUTPUT ;
    USE SIGNAL ;
    PORT
      LAYER M6 ;
        RECT  0 322.384 0.192 322.416 ;
    END
  END coll_o[354]
  PIN coll_o[355]
    DIRECTION OUTPUT ;
    USE SIGNAL ;
    PORT
      LAYER M6 ;
        RECT  0 323.28 0.192 323.312 ;
    END
  END coll_o[355]
  PIN coll_o[356]
    DIRECTION OUTPUT ;
    USE SIGNAL ;
    PORT
      LAYER M6 ;
        RECT  0 324.176 0.192 324.208 ;
    END
  END coll_o[356]
  PIN coll_o[357]
    DIRECTION OUTPUT ;
    USE SIGNAL ;
    PORT
      LAYER M6 ;
        RECT  0 325.136 0.192 325.168 ;
    END
  END coll_o[357]
  PIN coll_o[358]
    DIRECTION OUTPUT ;
    USE SIGNAL ;
    PORT
      LAYER M6 ;
        RECT  0 326.032 0.192 326.064 ;
    END
  END coll_o[358]
  PIN coll_o[359]
    DIRECTION OUTPUT ;
    USE SIGNAL ;
    PORT
      LAYER M6 ;
        RECT  0 326.928 0.192 326.96 ;
    END
  END coll_o[359]
  PIN coll_o[35]
    DIRECTION OUTPUT ;
    USE SIGNAL ;
    PORT
      LAYER M6 ;
        RECT  0 33.68 0.192 33.712 ;
    END
  END coll_o[35]
  PIN coll_o[360]
    DIRECTION OUTPUT ;
    USE SIGNAL ;
    PORT
      LAYER M6 ;
        RECT  0 327.824 0.192 327.856 ;
    END
  END coll_o[360]
  PIN coll_o[361]
    DIRECTION OUTPUT ;
    USE SIGNAL ;
    PORT
      LAYER M6 ;
        RECT  0 328.72 0.192 328.752 ;
    END
  END coll_o[361]
  PIN coll_o[362]
    DIRECTION OUTPUT ;
    USE SIGNAL ;
    PORT
      LAYER M6 ;
        RECT  0 329.616 0.192 329.648 ;
    END
  END coll_o[362]
  PIN coll_o[363]
    DIRECTION OUTPUT ;
    USE SIGNAL ;
    PORT
      LAYER M6 ;
        RECT  0 330.512 0.192 330.544 ;
    END
  END coll_o[363]
  PIN coll_o[364]
    DIRECTION OUTPUT ;
    USE SIGNAL ;
    PORT
      LAYER M6 ;
        RECT  0 331.472 0.192 331.504 ;
    END
  END coll_o[364]
  PIN coll_o[365]
    DIRECTION OUTPUT ;
    USE SIGNAL ;
    PORT
      LAYER M6 ;
        RECT  0 332.368 0.192 332.4 ;
    END
  END coll_o[365]
  PIN coll_o[366]
    DIRECTION OUTPUT ;
    USE SIGNAL ;
    PORT
      LAYER M6 ;
        RECT  0 333.264 0.192 333.296 ;
    END
  END coll_o[366]
  PIN coll_o[367]
    DIRECTION OUTPUT ;
    USE SIGNAL ;
    PORT
      LAYER M6 ;
        RECT  0 334.16 0.192 334.192 ;
    END
  END coll_o[367]
  PIN coll_o[368]
    DIRECTION OUTPUT ;
    USE SIGNAL ;
    PORT
      LAYER M6 ;
        RECT  0 335.056 0.192 335.088 ;
    END
  END coll_o[368]
  PIN coll_o[369]
    DIRECTION OUTPUT ;
    USE SIGNAL ;
    PORT
      LAYER M6 ;
        RECT  0 335.952 0.192 335.984 ;
    END
  END coll_o[369]
  PIN coll_o[36]
    DIRECTION OUTPUT ;
    USE SIGNAL ;
    PORT
      LAYER M6 ;
        RECT  0 34.576 0.192 34.608 ;
    END
  END coll_o[36]
  PIN coll_o[370]
    DIRECTION OUTPUT ;
    USE SIGNAL ;
    PORT
      LAYER M6 ;
        RECT  0 336.848 0.192 336.88 ;
    END
  END coll_o[370]
  PIN coll_o[371]
    DIRECTION OUTPUT ;
    USE SIGNAL ;
    PORT
      LAYER M6 ;
        RECT  0 337.808 0.192 337.84 ;
    END
  END coll_o[371]
  PIN coll_o[372]
    DIRECTION OUTPUT ;
    USE SIGNAL ;
    PORT
      LAYER M6 ;
        RECT  0 338.704 0.192 338.736 ;
    END
  END coll_o[372]
  PIN coll_o[373]
    DIRECTION OUTPUT ;
    USE SIGNAL ;
    PORT
      LAYER M6 ;
        RECT  0 339.6 0.192 339.632 ;
    END
  END coll_o[373]
  PIN coll_o[374]
    DIRECTION OUTPUT ;
    USE SIGNAL ;
    PORT
      LAYER M6 ;
        RECT  0 340.496 0.192 340.528 ;
    END
  END coll_o[374]
  PIN coll_o[375]
    DIRECTION OUTPUT ;
    USE SIGNAL ;
    PORT
      LAYER M6 ;
        RECT  0 341.392 0.192 341.424 ;
    END
  END coll_o[375]
  PIN coll_o[376]
    DIRECTION OUTPUT ;
    USE SIGNAL ;
    PORT
      LAYER M6 ;
        RECT  0 342.288 0.192 342.32 ;
    END
  END coll_o[376]
  PIN coll_o[377]
    DIRECTION OUTPUT ;
    USE SIGNAL ;
    PORT
      LAYER M6 ;
        RECT  0 343.184 0.192 343.216 ;
    END
  END coll_o[377]
  PIN coll_o[378]
    DIRECTION OUTPUT ;
    USE SIGNAL ;
    PORT
      LAYER M6 ;
        RECT  0 344.144 0.192 344.176 ;
    END
  END coll_o[378]
  PIN coll_o[379]
    DIRECTION OUTPUT ;
    USE SIGNAL ;
    PORT
      LAYER M6 ;
        RECT  0 345.04 0.192 345.072 ;
    END
  END coll_o[379]
  PIN coll_o[37]
    DIRECTION OUTPUT ;
    USE SIGNAL ;
    PORT
      LAYER M6 ;
        RECT  0 35.472 0.192 35.504 ;
    END
  END coll_o[37]
  PIN coll_o[380]
    DIRECTION OUTPUT ;
    USE SIGNAL ;
    PORT
      LAYER M6 ;
        RECT  0 345.936 0.192 345.968 ;
    END
  END coll_o[380]
  PIN coll_o[381]
    DIRECTION OUTPUT ;
    USE SIGNAL ;
    PORT
      LAYER M6 ;
        RECT  0 346.832 0.192 346.864 ;
    END
  END coll_o[381]
  PIN coll_o[382]
    DIRECTION OUTPUT ;
    USE SIGNAL ;
    PORT
      LAYER M6 ;
        RECT  0 347.728 0.192 347.76 ;
    END
  END coll_o[382]
  PIN coll_o[383]
    DIRECTION OUTPUT ;
    USE SIGNAL ;
    PORT
      LAYER M6 ;
        RECT  0 348.624 0.192 348.656 ;
    END
  END coll_o[383]
  PIN coll_o[384]
    DIRECTION OUTPUT ;
    USE SIGNAL ;
    PORT
      LAYER M6 ;
        RECT  0 349.52 0.192 349.552 ;
    END
  END coll_o[384]
  PIN coll_o[385]
    DIRECTION OUTPUT ;
    USE SIGNAL ;
    PORT
      LAYER M6 ;
        RECT  0 350.48 0.192 350.512 ;
    END
  END coll_o[385]
  PIN coll_o[386]
    DIRECTION OUTPUT ;
    USE SIGNAL ;
    PORT
      LAYER M6 ;
        RECT  0 351.376 0.192 351.408 ;
    END
  END coll_o[386]
  PIN coll_o[387]
    DIRECTION OUTPUT ;
    USE SIGNAL ;
    PORT
      LAYER M6 ;
        RECT  0 352.272 0.192 352.304 ;
    END
  END coll_o[387]
  PIN coll_o[388]
    DIRECTION OUTPUT ;
    USE SIGNAL ;
    PORT
      LAYER M6 ;
        RECT  0 353.168 0.192 353.2 ;
    END
  END coll_o[388]
  PIN coll_o[389]
    DIRECTION OUTPUT ;
    USE SIGNAL ;
    PORT
      LAYER M6 ;
        RECT  0 354.064 0.192 354.096 ;
    END
  END coll_o[389]
  PIN coll_o[38]
    DIRECTION OUTPUT ;
    USE SIGNAL ;
    PORT
      LAYER M6 ;
        RECT  0 36.368 0.192 36.4 ;
    END
  END coll_o[38]
  PIN coll_o[390]
    DIRECTION OUTPUT ;
    USE SIGNAL ;
    PORT
      LAYER M6 ;
        RECT  0 354.96 0.192 354.992 ;
    END
  END coll_o[390]
  PIN coll_o[391]
    DIRECTION OUTPUT ;
    USE SIGNAL ;
    PORT
      LAYER M6 ;
        RECT  0 355.856 0.192 355.888 ;
    END
  END coll_o[391]
  PIN coll_o[392]
    DIRECTION OUTPUT ;
    USE SIGNAL ;
    PORT
      LAYER M6 ;
        RECT  0 356.816 0.192 356.848 ;
    END
  END coll_o[392]
  PIN coll_o[393]
    DIRECTION OUTPUT ;
    USE SIGNAL ;
    PORT
      LAYER M6 ;
        RECT  0 357.712 0.192 357.744 ;
    END
  END coll_o[393]
  PIN coll_o[394]
    DIRECTION OUTPUT ;
    USE SIGNAL ;
    PORT
      LAYER M6 ;
        RECT  0 358.608 0.192 358.64 ;
    END
  END coll_o[394]
  PIN coll_o[395]
    DIRECTION OUTPUT ;
    USE SIGNAL ;
    PORT
      LAYER M6 ;
        RECT  0 359.504 0.192 359.536 ;
    END
  END coll_o[395]
  PIN coll_o[396]
    DIRECTION OUTPUT ;
    USE SIGNAL ;
    PORT
      LAYER M6 ;
        RECT  0 360.4 0.192 360.432 ;
    END
  END coll_o[396]
  PIN coll_o[397]
    DIRECTION OUTPUT ;
    USE SIGNAL ;
    PORT
      LAYER M6 ;
        RECT  0 361.296 0.192 361.328 ;
    END
  END coll_o[397]
  PIN coll_o[398]
    DIRECTION OUTPUT ;
    USE SIGNAL ;
    PORT
      LAYER M6 ;
        RECT  0 362.192 0.192 362.224 ;
    END
  END coll_o[398]
  PIN coll_o[399]
    DIRECTION OUTPUT ;
    USE SIGNAL ;
    PORT
      LAYER M6 ;
        RECT  0 363.152 0.192 363.184 ;
    END
  END coll_o[399]
  PIN coll_o[39]
    DIRECTION OUTPUT ;
    USE SIGNAL ;
    PORT
      LAYER M6 ;
        RECT  0 37.264 0.192 37.296 ;
    END
  END coll_o[39]
  PIN coll_o[3]
    DIRECTION OUTPUT ;
    USE SIGNAL ;
    PORT
      LAYER M6 ;
        RECT  0 4.688 0.192 4.72 ;
    END
  END coll_o[3]
  PIN coll_o[400]
    DIRECTION OUTPUT ;
    USE SIGNAL ;
    PORT
      LAYER M6 ;
        RECT  0 364.048 0.192 364.08 ;
    END
  END coll_o[400]
  PIN coll_o[401]
    DIRECTION OUTPUT ;
    USE SIGNAL ;
    PORT
      LAYER M6 ;
        RECT  0 364.944 0.192 364.976 ;
    END
  END coll_o[401]
  PIN coll_o[402]
    DIRECTION OUTPUT ;
    USE SIGNAL ;
    PORT
      LAYER M6 ;
        RECT  0 365.84 0.192 365.872 ;
    END
  END coll_o[402]
  PIN coll_o[403]
    DIRECTION OUTPUT ;
    USE SIGNAL ;
    PORT
      LAYER M6 ;
        RECT  0 366.736 0.192 366.768 ;
    END
  END coll_o[403]
  PIN coll_o[404]
    DIRECTION OUTPUT ;
    USE SIGNAL ;
    PORT
      LAYER M6 ;
        RECT  0 367.632 0.192 367.664 ;
    END
  END coll_o[404]
  PIN coll_o[405]
    DIRECTION OUTPUT ;
    USE SIGNAL ;
    PORT
      LAYER M6 ;
        RECT  0 368.528 0.192 368.56 ;
    END
  END coll_o[405]
  PIN coll_o[406]
    DIRECTION OUTPUT ;
    USE SIGNAL ;
    PORT
      LAYER M6 ;
        RECT  0 369.488 0.192 369.52 ;
    END
  END coll_o[406]
  PIN coll_o[407]
    DIRECTION OUTPUT ;
    USE SIGNAL ;
    PORT
      LAYER M6 ;
        RECT  0 370.384 0.192 370.416 ;
    END
  END coll_o[407]
  PIN coll_o[408]
    DIRECTION OUTPUT ;
    USE SIGNAL ;
    PORT
      LAYER M6 ;
        RECT  0 371.28 0.192 371.312 ;
    END
  END coll_o[408]
  PIN coll_o[409]
    DIRECTION OUTPUT ;
    USE SIGNAL ;
    PORT
      LAYER M6 ;
        RECT  0 372.176 0.192 372.208 ;
    END
  END coll_o[409]
  PIN coll_o[40]
    DIRECTION OUTPUT ;
    USE SIGNAL ;
    PORT
      LAYER M6 ;
        RECT  0 38.16 0.192 38.192 ;
    END
  END coll_o[40]
  PIN coll_o[410]
    DIRECTION OUTPUT ;
    USE SIGNAL ;
    PORT
      LAYER M6 ;
        RECT  0 373.072 0.192 373.104 ;
    END
  END coll_o[410]
  PIN coll_o[411]
    DIRECTION OUTPUT ;
    USE SIGNAL ;
    PORT
      LAYER M6 ;
        RECT  0 373.968 0.192 374 ;
    END
  END coll_o[411]
  PIN coll_o[412]
    DIRECTION OUTPUT ;
    USE SIGNAL ;
    PORT
      LAYER M6 ;
        RECT  0 374.864 0.192 374.896 ;
    END
  END coll_o[412]
  PIN coll_o[413]
    DIRECTION OUTPUT ;
    USE SIGNAL ;
    PORT
      LAYER M6 ;
        RECT  0 375.824 0.192 375.856 ;
    END
  END coll_o[413]
  PIN coll_o[414]
    DIRECTION OUTPUT ;
    USE SIGNAL ;
    PORT
      LAYER M6 ;
        RECT  0 376.72 0.192 376.752 ;
    END
  END coll_o[414]
  PIN coll_o[415]
    DIRECTION OUTPUT ;
    USE SIGNAL ;
    PORT
      LAYER M6 ;
        RECT  0 377.616 0.192 377.648 ;
    END
  END coll_o[415]
  PIN coll_o[416]
    DIRECTION OUTPUT ;
    USE SIGNAL ;
    PORT
      LAYER M6 ;
        RECT  0 378.512 0.192 378.544 ;
    END
  END coll_o[416]
  PIN coll_o[417]
    DIRECTION OUTPUT ;
    USE SIGNAL ;
    PORT
      LAYER M6 ;
        RECT  0 379.408 0.192 379.44 ;
    END
  END coll_o[417]
  PIN coll_o[418]
    DIRECTION OUTPUT ;
    USE SIGNAL ;
    PORT
      LAYER M6 ;
        RECT  0 380.304 0.192 380.336 ;
    END
  END coll_o[418]
  PIN coll_o[419]
    DIRECTION OUTPUT ;
    USE SIGNAL ;
    PORT
      LAYER M6 ;
        RECT  0 381.2 0.192 381.232 ;
    END
  END coll_o[419]
  PIN coll_o[41]
    DIRECTION OUTPUT ;
    USE SIGNAL ;
    PORT
      LAYER M6 ;
        RECT  0 39.056 0.192 39.088 ;
    END
  END coll_o[41]
  PIN coll_o[420]
    DIRECTION OUTPUT ;
    USE SIGNAL ;
    PORT
      LAYER M6 ;
        RECT  0 382.16 0.192 382.192 ;
    END
  END coll_o[420]
  PIN coll_o[421]
    DIRECTION OUTPUT ;
    USE SIGNAL ;
    PORT
      LAYER M6 ;
        RECT  0 383.056 0.192 383.088 ;
    END
  END coll_o[421]
  PIN coll_o[422]
    DIRECTION OUTPUT ;
    USE SIGNAL ;
    PORT
      LAYER M6 ;
        RECT  0 383.952 0.192 383.984 ;
    END
  END coll_o[422]
  PIN coll_o[423]
    DIRECTION OUTPUT ;
    USE SIGNAL ;
    PORT
      LAYER M6 ;
        RECT  0 384.848 0.192 384.88 ;
    END
  END coll_o[423]
  PIN coll_o[424]
    DIRECTION OUTPUT ;
    USE SIGNAL ;
    PORT
      LAYER M6 ;
        RECT  0 385.744 0.192 385.776 ;
    END
  END coll_o[424]
  PIN coll_o[425]
    DIRECTION OUTPUT ;
    USE SIGNAL ;
    PORT
      LAYER M6 ;
        RECT  0 386.64 0.192 386.672 ;
    END
  END coll_o[425]
  PIN coll_o[426]
    DIRECTION OUTPUT ;
    USE SIGNAL ;
    PORT
      LAYER M6 ;
        RECT  0 387.536 0.192 387.568 ;
    END
  END coll_o[426]
  PIN coll_o[427]
    DIRECTION OUTPUT ;
    USE SIGNAL ;
    PORT
      LAYER M6 ;
        RECT  0 388.496 0.192 388.528 ;
    END
  END coll_o[427]
  PIN coll_o[428]
    DIRECTION OUTPUT ;
    USE SIGNAL ;
    PORT
      LAYER M6 ;
        RECT  0 389.392 0.192 389.424 ;
    END
  END coll_o[428]
  PIN coll_o[429]
    DIRECTION OUTPUT ;
    USE SIGNAL ;
    PORT
      LAYER M6 ;
        RECT  0 390.288 0.192 390.32 ;
    END
  END coll_o[429]
  PIN coll_o[42]
    DIRECTION OUTPUT ;
    USE SIGNAL ;
    PORT
      LAYER M6 ;
        RECT  0 40.016 0.192 40.048 ;
    END
  END coll_o[42]
  PIN coll_o[430]
    DIRECTION OUTPUT ;
    USE SIGNAL ;
    PORT
      LAYER M6 ;
        RECT  0 391.184 0.192 391.216 ;
    END
  END coll_o[430]
  PIN coll_o[431]
    DIRECTION OUTPUT ;
    USE SIGNAL ;
    PORT
      LAYER M6 ;
        RECT  0 392.08 0.192 392.112 ;
    END
  END coll_o[431]
  PIN coll_o[432]
    DIRECTION OUTPUT ;
    USE SIGNAL ;
    PORT
      LAYER M6 ;
        RECT  0 392.976 0.192 393.008 ;
    END
  END coll_o[432]
  PIN coll_o[433]
    DIRECTION OUTPUT ;
    USE SIGNAL ;
    PORT
      LAYER M6 ;
        RECT  0 393.872 0.192 393.904 ;
    END
  END coll_o[433]
  PIN coll_o[434]
    DIRECTION OUTPUT ;
    USE SIGNAL ;
    PORT
      LAYER M6 ;
        RECT  0 394.832 0.192 394.864 ;
    END
  END coll_o[434]
  PIN coll_o[435]
    DIRECTION OUTPUT ;
    USE SIGNAL ;
    PORT
      LAYER M6 ;
        RECT  0 395.728 0.192 395.76 ;
    END
  END coll_o[435]
  PIN coll_o[436]
    DIRECTION OUTPUT ;
    USE SIGNAL ;
    PORT
      LAYER M6 ;
        RECT  0 396.624 0.192 396.656 ;
    END
  END coll_o[436]
  PIN coll_o[437]
    DIRECTION OUTPUT ;
    USE SIGNAL ;
    PORT
      LAYER M6 ;
        RECT  0 397.52 0.192 397.552 ;
    END
  END coll_o[437]
  PIN coll_o[438]
    DIRECTION OUTPUT ;
    USE SIGNAL ;
    PORT
      LAYER M6 ;
        RECT  0 398.416 0.192 398.448 ;
    END
  END coll_o[438]
  PIN coll_o[439]
    DIRECTION OUTPUT ;
    USE SIGNAL ;
    PORT
      LAYER M6 ;
        RECT  0 399.312 0.192 399.344 ;
    END
  END coll_o[439]
  PIN coll_o[43]
    DIRECTION OUTPUT ;
    USE SIGNAL ;
    PORT
      LAYER M6 ;
        RECT  0 40.912 0.192 40.944 ;
    END
  END coll_o[43]
  PIN coll_o[440]
    DIRECTION OUTPUT ;
    USE SIGNAL ;
    PORT
      LAYER M6 ;
        RECT  0 400.208 0.192 400.24 ;
    END
  END coll_o[440]
  PIN coll_o[441]
    DIRECTION OUTPUT ;
    USE SIGNAL ;
    PORT
      LAYER M6 ;
        RECT  0 401.168 0.192 401.2 ;
    END
  END coll_o[441]
  PIN coll_o[442]
    DIRECTION OUTPUT ;
    USE SIGNAL ;
    PORT
      LAYER M6 ;
        RECT  0 402.064 0.192 402.096 ;
    END
  END coll_o[442]
  PIN coll_o[443]
    DIRECTION OUTPUT ;
    USE SIGNAL ;
    PORT
      LAYER M6 ;
        RECT  0 402.96 0.192 402.992 ;
    END
  END coll_o[443]
  PIN coll_o[444]
    DIRECTION OUTPUT ;
    USE SIGNAL ;
    PORT
      LAYER M6 ;
        RECT  0 403.856 0.192 403.888 ;
    END
  END coll_o[444]
  PIN coll_o[445]
    DIRECTION OUTPUT ;
    USE SIGNAL ;
    PORT
      LAYER M6 ;
        RECT  0 404.752 0.192 404.784 ;
    END
  END coll_o[445]
  PIN coll_o[446]
    DIRECTION OUTPUT ;
    USE SIGNAL ;
    PORT
      LAYER M6 ;
        RECT  0 405.648 0.192 405.68 ;
    END
  END coll_o[446]
  PIN coll_o[447]
    DIRECTION OUTPUT ;
    USE SIGNAL ;
    PORT
      LAYER M6 ;
        RECT  0 406.544 0.192 406.576 ;
    END
  END coll_o[447]
  PIN coll_o[448]
    DIRECTION OUTPUT ;
    USE SIGNAL ;
    PORT
      LAYER M6 ;
        RECT  0 407.504 0.192 407.536 ;
    END
  END coll_o[448]
  PIN coll_o[449]
    DIRECTION OUTPUT ;
    USE SIGNAL ;
    PORT
      LAYER M6 ;
        RECT  0 408.4 0.192 408.432 ;
    END
  END coll_o[449]
  PIN coll_o[44]
    DIRECTION OUTPUT ;
    USE SIGNAL ;
    PORT
      LAYER M6 ;
        RECT  0 41.808 0.192 41.84 ;
    END
  END coll_o[44]
  PIN coll_o[450]
    DIRECTION OUTPUT ;
    USE SIGNAL ;
    PORT
      LAYER M6 ;
        RECT  0 409.296 0.192 409.328 ;
    END
  END coll_o[450]
  PIN coll_o[451]
    DIRECTION OUTPUT ;
    USE SIGNAL ;
    PORT
      LAYER M6 ;
        RECT  0 410.192 0.192 410.224 ;
    END
  END coll_o[451]
  PIN coll_o[452]
    DIRECTION OUTPUT ;
    USE SIGNAL ;
    PORT
      LAYER M6 ;
        RECT  0 411.088 0.192 411.12 ;
    END
  END coll_o[452]
  PIN coll_o[453]
    DIRECTION OUTPUT ;
    USE SIGNAL ;
    PORT
      LAYER M6 ;
        RECT  0 411.984 0.192 412.016 ;
    END
  END coll_o[453]
  PIN coll_o[454]
    DIRECTION OUTPUT ;
    USE SIGNAL ;
    PORT
      LAYER M6 ;
        RECT  0 412.88 0.192 412.912 ;
    END
  END coll_o[454]
  PIN coll_o[455]
    DIRECTION OUTPUT ;
    USE SIGNAL ;
    PORT
      LAYER M6 ;
        RECT  0 413.84 0.192 413.872 ;
    END
  END coll_o[455]
  PIN coll_o[456]
    DIRECTION OUTPUT ;
    USE SIGNAL ;
    PORT
      LAYER M6 ;
        RECT  0 414.736 0.192 414.768 ;
    END
  END coll_o[456]
  PIN coll_o[457]
    DIRECTION OUTPUT ;
    USE SIGNAL ;
    PORT
      LAYER M6 ;
        RECT  0 415.632 0.192 415.664 ;
    END
  END coll_o[457]
  PIN coll_o[458]
    DIRECTION OUTPUT ;
    USE SIGNAL ;
    PORT
      LAYER M6 ;
        RECT  0 416.528 0.192 416.56 ;
    END
  END coll_o[458]
  PIN coll_o[459]
    DIRECTION OUTPUT ;
    USE SIGNAL ;
    PORT
      LAYER M6 ;
        RECT  0 417.424 0.192 417.456 ;
    END
  END coll_o[459]
  PIN coll_o[45]
    DIRECTION OUTPUT ;
    USE SIGNAL ;
    PORT
      LAYER M6 ;
        RECT  0 42.704 0.192 42.736 ;
    END
  END coll_o[45]
  PIN coll_o[460]
    DIRECTION OUTPUT ;
    USE SIGNAL ;
    PORT
      LAYER M6 ;
        RECT  0 418.32 0.192 418.352 ;
    END
  END coll_o[460]
  PIN coll_o[461]
    DIRECTION OUTPUT ;
    USE SIGNAL ;
    PORT
      LAYER M6 ;
        RECT  0 419.216 0.192 419.248 ;
    END
  END coll_o[461]
  PIN coll_o[462]
    DIRECTION OUTPUT ;
    USE SIGNAL ;
    PORT
      LAYER M6 ;
        RECT  0 420.176 0.192 420.208 ;
    END
  END coll_o[462]
  PIN coll_o[463]
    DIRECTION OUTPUT ;
    USE SIGNAL ;
    PORT
      LAYER M6 ;
        RECT  0 421.072 0.192 421.104 ;
    END
  END coll_o[463]
  PIN coll_o[464]
    DIRECTION OUTPUT ;
    USE SIGNAL ;
    PORT
      LAYER M6 ;
        RECT  0 421.968 0.192 422 ;
    END
  END coll_o[464]
  PIN coll_o[465]
    DIRECTION OUTPUT ;
    USE SIGNAL ;
    PORT
      LAYER M6 ;
        RECT  0 422.864 0.192 422.896 ;
    END
  END coll_o[465]
  PIN coll_o[466]
    DIRECTION OUTPUT ;
    USE SIGNAL ;
    PORT
      LAYER M6 ;
        RECT  0 423.76 0.192 423.792 ;
    END
  END coll_o[466]
  PIN coll_o[467]
    DIRECTION OUTPUT ;
    USE SIGNAL ;
    PORT
      LAYER M6 ;
        RECT  0 424.656 0.192 424.688 ;
    END
  END coll_o[467]
  PIN coll_o[468]
    DIRECTION OUTPUT ;
    USE SIGNAL ;
    PORT
      LAYER M6 ;
        RECT  0 425.552 0.192 425.584 ;
    END
  END coll_o[468]
  PIN coll_o[469]
    DIRECTION OUTPUT ;
    USE SIGNAL ;
    PORT
      LAYER M6 ;
        RECT  0 426.512 0.192 426.544 ;
    END
  END coll_o[469]
  PIN coll_o[46]
    DIRECTION OUTPUT ;
    USE SIGNAL ;
    PORT
      LAYER M6 ;
        RECT  0 43.6 0.192 43.632 ;
    END
  END coll_o[46]
  PIN coll_o[470]
    DIRECTION OUTPUT ;
    USE SIGNAL ;
    PORT
      LAYER M6 ;
        RECT  0 427.408 0.192 427.44 ;
    END
  END coll_o[470]
  PIN coll_o[471]
    DIRECTION OUTPUT ;
    USE SIGNAL ;
    PORT
      LAYER M6 ;
        RECT  0 428.304 0.192 428.336 ;
    END
  END coll_o[471]
  PIN coll_o[472]
    DIRECTION OUTPUT ;
    USE SIGNAL ;
    PORT
      LAYER M6 ;
        RECT  0 429.2 0.192 429.232 ;
    END
  END coll_o[472]
  PIN coll_o[473]
    DIRECTION OUTPUT ;
    USE SIGNAL ;
    PORT
      LAYER M6 ;
        RECT  0 430.096 0.192 430.128 ;
    END
  END coll_o[473]
  PIN coll_o[474]
    DIRECTION OUTPUT ;
    USE SIGNAL ;
    PORT
      LAYER M6 ;
        RECT  0 430.992 0.192 431.024 ;
    END
  END coll_o[474]
  PIN coll_o[475]
    DIRECTION OUTPUT ;
    USE SIGNAL ;
    PORT
      LAYER M6 ;
        RECT  0 431.888 0.192 431.92 ;
    END
  END coll_o[475]
  PIN coll_o[476]
    DIRECTION OUTPUT ;
    USE SIGNAL ;
    PORT
      LAYER M6 ;
        RECT  0 432.848 0.192 432.88 ;
    END
  END coll_o[476]
  PIN coll_o[477]
    DIRECTION OUTPUT ;
    USE SIGNAL ;
    PORT
      LAYER M6 ;
        RECT  0 433.744 0.192 433.776 ;
    END
  END coll_o[477]
  PIN coll_o[478]
    DIRECTION OUTPUT ;
    USE SIGNAL ;
    PORT
      LAYER M6 ;
        RECT  0 434.64 0.192 434.672 ;
    END
  END coll_o[478]
  PIN coll_o[479]
    DIRECTION OUTPUT ;
    USE SIGNAL ;
    PORT
      LAYER M6 ;
        RECT  0 435.536 0.192 435.568 ;
    END
  END coll_o[479]
  PIN coll_o[47]
    DIRECTION OUTPUT ;
    USE SIGNAL ;
    PORT
      LAYER M6 ;
        RECT  0 44.496 0.192 44.528 ;
    END
  END coll_o[47]
  PIN coll_o[480]
    DIRECTION OUTPUT ;
    USE SIGNAL ;
    PORT
      LAYER M6 ;
        RECT  0 436.432 0.192 436.464 ;
    END
  END coll_o[480]
  PIN coll_o[481]
    DIRECTION OUTPUT ;
    USE SIGNAL ;
    PORT
      LAYER M6 ;
        RECT  0 437.328 0.192 437.36 ;
    END
  END coll_o[481]
  PIN coll_o[482]
    DIRECTION OUTPUT ;
    USE SIGNAL ;
    PORT
      LAYER M6 ;
        RECT  0 438.224 0.192 438.256 ;
    END
  END coll_o[482]
  PIN coll_o[483]
    DIRECTION OUTPUT ;
    USE SIGNAL ;
    PORT
      LAYER M6 ;
        RECT  0 439.184 0.192 439.216 ;
    END
  END coll_o[483]
  PIN coll_o[484]
    DIRECTION OUTPUT ;
    USE SIGNAL ;
    PORT
      LAYER M6 ;
        RECT  0 440.08 0.192 440.112 ;
    END
  END coll_o[484]
  PIN coll_o[485]
    DIRECTION OUTPUT ;
    USE SIGNAL ;
    PORT
      LAYER M6 ;
        RECT  0 440.976 0.192 441.008 ;
    END
  END coll_o[485]
  PIN coll_o[486]
    DIRECTION OUTPUT ;
    USE SIGNAL ;
    PORT
      LAYER M6 ;
        RECT  0 441.872 0.192 441.904 ;
    END
  END coll_o[486]
  PIN coll_o[487]
    DIRECTION OUTPUT ;
    USE SIGNAL ;
    PORT
      LAYER M6 ;
        RECT  0 442.768 0.192 442.8 ;
    END
  END coll_o[487]
  PIN coll_o[488]
    DIRECTION OUTPUT ;
    USE SIGNAL ;
    PORT
      LAYER M6 ;
        RECT  0 443.664 0.192 443.696 ;
    END
  END coll_o[488]
  PIN coll_o[489]
    DIRECTION OUTPUT ;
    USE SIGNAL ;
    PORT
      LAYER M6 ;
        RECT  0 444.56 0.192 444.592 ;
    END
  END coll_o[489]
  PIN coll_o[48]
    DIRECTION OUTPUT ;
    USE SIGNAL ;
    PORT
      LAYER M6 ;
        RECT  0 45.392 0.192 45.424 ;
    END
  END coll_o[48]
  PIN coll_o[490]
    DIRECTION OUTPUT ;
    USE SIGNAL ;
    PORT
      LAYER M6 ;
        RECT  0 445.52 0.192 445.552 ;
    END
  END coll_o[490]
  PIN coll_o[491]
    DIRECTION OUTPUT ;
    USE SIGNAL ;
    PORT
      LAYER M6 ;
        RECT  0 446.416 0.192 446.448 ;
    END
  END coll_o[491]
  PIN coll_o[492]
    DIRECTION OUTPUT ;
    USE SIGNAL ;
    PORT
      LAYER M6 ;
        RECT  0 447.312 0.192 447.344 ;
    END
  END coll_o[492]
  PIN coll_o[493]
    DIRECTION OUTPUT ;
    USE SIGNAL ;
    PORT
      LAYER M6 ;
        RECT  0 448.208 0.192 448.24 ;
    END
  END coll_o[493]
  PIN coll_o[494]
    DIRECTION OUTPUT ;
    USE SIGNAL ;
    PORT
      LAYER M6 ;
        RECT  0 449.104 0.192 449.136 ;
    END
  END coll_o[494]
  PIN coll_o[495]
    DIRECTION OUTPUT ;
    USE SIGNAL ;
    PORT
      LAYER M6 ;
        RECT  0 450 0.192 450.032 ;
    END
  END coll_o[495]
  PIN coll_o[496]
    DIRECTION OUTPUT ;
    USE SIGNAL ;
    PORT
      LAYER M6 ;
        RECT  0 450.896 0.192 450.928 ;
    END
  END coll_o[496]
  PIN coll_o[497]
    DIRECTION OUTPUT ;
    USE SIGNAL ;
    PORT
      LAYER M6 ;
        RECT  0 451.856 0.192 451.888 ;
    END
  END coll_o[497]
  PIN coll_o[498]
    DIRECTION OUTPUT ;
    USE SIGNAL ;
    PORT
      LAYER M6 ;
        RECT  0 452.752 0.192 452.784 ;
    END
  END coll_o[498]
  PIN coll_o[499]
    DIRECTION OUTPUT ;
    USE SIGNAL ;
    PORT
      LAYER M6 ;
        RECT  0 453.648 0.192 453.68 ;
    END
  END coll_o[499]
  PIN coll_o[49]
    DIRECTION OUTPUT ;
    USE SIGNAL ;
    PORT
      LAYER M6 ;
        RECT  0 46.352 0.192 46.384 ;
    END
  END coll_o[49]
  PIN coll_o[4]
    DIRECTION OUTPUT ;
    USE SIGNAL ;
    PORT
      LAYER M6 ;
        RECT  0 5.584 0.192 5.616 ;
    END
  END coll_o[4]
  PIN coll_o[500]
    DIRECTION OUTPUT ;
    USE SIGNAL ;
    PORT
      LAYER M6 ;
        RECT  0 454.544 0.192 454.576 ;
    END
  END coll_o[500]
  PIN coll_o[501]
    DIRECTION OUTPUT ;
    USE SIGNAL ;
    PORT
      LAYER M6 ;
        RECT  0 455.44 0.192 455.472 ;
    END
  END coll_o[501]
  PIN coll_o[502]
    DIRECTION OUTPUT ;
    USE SIGNAL ;
    PORT
      LAYER M6 ;
        RECT  0 456.336 0.192 456.368 ;
    END
  END coll_o[502]
  PIN coll_o[503]
    DIRECTION OUTPUT ;
    USE SIGNAL ;
    PORT
      LAYER M6 ;
        RECT  0 457.232 0.192 457.264 ;
    END
  END coll_o[503]
  PIN coll_o[504]
    DIRECTION OUTPUT ;
    USE SIGNAL ;
    PORT
      LAYER M6 ;
        RECT  0 458.192 0.192 458.224 ;
    END
  END coll_o[504]
  PIN coll_o[505]
    DIRECTION OUTPUT ;
    USE SIGNAL ;
    PORT
      LAYER M6 ;
        RECT  0 459.088 0.192 459.12 ;
    END
  END coll_o[505]
  PIN coll_o[506]
    DIRECTION OUTPUT ;
    USE SIGNAL ;
    PORT
      LAYER M6 ;
        RECT  0 459.984 0.192 460.016 ;
    END
  END coll_o[506]
  PIN coll_o[507]
    DIRECTION OUTPUT ;
    USE SIGNAL ;
    PORT
      LAYER M6 ;
        RECT  0 460.88 0.192 460.912 ;
    END
  END coll_o[507]
  PIN coll_o[508]
    DIRECTION OUTPUT ;
    USE SIGNAL ;
    PORT
      LAYER M6 ;
        RECT  0 461.776 0.192 461.808 ;
    END
  END coll_o[508]
  PIN coll_o[509]
    DIRECTION OUTPUT ;
    USE SIGNAL ;
    PORT
      LAYER M6 ;
        RECT  0 462.672 0.192 462.704 ;
    END
  END coll_o[509]
  PIN coll_o[50]
    DIRECTION OUTPUT ;
    USE SIGNAL ;
    PORT
      LAYER M6 ;
        RECT  0 47.248 0.192 47.28 ;
    END
  END coll_o[50]
  PIN coll_o[510]
    DIRECTION OUTPUT ;
    USE SIGNAL ;
    PORT
      LAYER M6 ;
        RECT  0 463.568 0.192 463.6 ;
    END
  END coll_o[510]
  PIN coll_o[511]
    DIRECTION OUTPUT ;
    USE SIGNAL ;
    PORT
      LAYER M6 ;
        RECT  0 464.528 0.192 464.56 ;
    END
  END coll_o[511]
  PIN coll_o[51]
    DIRECTION OUTPUT ;
    USE SIGNAL ;
    PORT
      LAYER M6 ;
        RECT  0 48.144 0.192 48.176 ;
    END
  END coll_o[51]
  PIN coll_o[52]
    DIRECTION OUTPUT ;
    USE SIGNAL ;
    PORT
      LAYER M6 ;
        RECT  0 49.04 0.192 49.072 ;
    END
  END coll_o[52]
  PIN coll_o[53]
    DIRECTION OUTPUT ;
    USE SIGNAL ;
    PORT
      LAYER M6 ;
        RECT  0 49.936 0.192 49.968 ;
    END
  END coll_o[53]
  PIN coll_o[54]
    DIRECTION OUTPUT ;
    USE SIGNAL ;
    PORT
      LAYER M6 ;
        RECT  0 50.832 0.192 50.864 ;
    END
  END coll_o[54]
  PIN coll_o[55]
    DIRECTION OUTPUT ;
    USE SIGNAL ;
    PORT
      LAYER M6 ;
        RECT  0 51.728 0.192 51.76 ;
    END
  END coll_o[55]
  PIN coll_o[56]
    DIRECTION OUTPUT ;
    USE SIGNAL ;
    PORT
      LAYER M6 ;
        RECT  0 52.688 0.192 52.72 ;
    END
  END coll_o[56]
  PIN coll_o[57]
    DIRECTION OUTPUT ;
    USE SIGNAL ;
    PORT
      LAYER M6 ;
        RECT  0 53.584 0.192 53.616 ;
    END
  END coll_o[57]
  PIN coll_o[58]
    DIRECTION OUTPUT ;
    USE SIGNAL ;
    PORT
      LAYER M6 ;
        RECT  0 54.48 0.192 54.512 ;
    END
  END coll_o[58]
  PIN coll_o[59]
    DIRECTION OUTPUT ;
    USE SIGNAL ;
    PORT
      LAYER M6 ;
        RECT  0 55.376 0.192 55.408 ;
    END
  END coll_o[59]
  PIN coll_o[5]
    DIRECTION OUTPUT ;
    USE SIGNAL ;
    PORT
      LAYER M6 ;
        RECT  0 6.48 0.192 6.512 ;
    END
  END coll_o[5]
  PIN coll_o[60]
    DIRECTION OUTPUT ;
    USE SIGNAL ;
    PORT
      LAYER M6 ;
        RECT  0 56.272 0.192 56.304 ;
    END
  END coll_o[60]
  PIN coll_o[61]
    DIRECTION OUTPUT ;
    USE SIGNAL ;
    PORT
      LAYER M6 ;
        RECT  0 57.168 0.192 57.2 ;
    END
  END coll_o[61]
  PIN coll_o[62]
    DIRECTION OUTPUT ;
    USE SIGNAL ;
    PORT
      LAYER M6 ;
        RECT  0 58.064 0.192 58.096 ;
    END
  END coll_o[62]
  PIN coll_o[63]
    DIRECTION OUTPUT ;
    USE SIGNAL ;
    PORT
      LAYER M6 ;
        RECT  0 59.024 0.192 59.056 ;
    END
  END coll_o[63]
  PIN coll_o[64]
    DIRECTION OUTPUT ;
    USE SIGNAL ;
    PORT
      LAYER M6 ;
        RECT  0 59.92 0.192 59.952 ;
    END
  END coll_o[64]
  PIN coll_o[65]
    DIRECTION OUTPUT ;
    USE SIGNAL ;
    PORT
      LAYER M6 ;
        RECT  0 60.816 0.192 60.848 ;
    END
  END coll_o[65]
  PIN coll_o[66]
    DIRECTION OUTPUT ;
    USE SIGNAL ;
    PORT
      LAYER M6 ;
        RECT  0 61.712 0.192 61.744 ;
    END
  END coll_o[66]
  PIN coll_o[67]
    DIRECTION OUTPUT ;
    USE SIGNAL ;
    PORT
      LAYER M6 ;
        RECT  0 62.608 0.192 62.64 ;
    END
  END coll_o[67]
  PIN coll_o[68]
    DIRECTION OUTPUT ;
    USE SIGNAL ;
    PORT
      LAYER M6 ;
        RECT  0 63.504 0.192 63.536 ;
    END
  END coll_o[68]
  PIN coll_o[69]
    DIRECTION OUTPUT ;
    USE SIGNAL ;
    PORT
      LAYER M6 ;
        RECT  0 64.4 0.192 64.432 ;
    END
  END coll_o[69]
  PIN coll_o[6]
    DIRECTION OUTPUT ;
    USE SIGNAL ;
    PORT
      LAYER M6 ;
        RECT  0 7.376 0.192 7.408 ;
    END
  END coll_o[6]
  PIN coll_o[70]
    DIRECTION OUTPUT ;
    USE SIGNAL ;
    PORT
      LAYER M6 ;
        RECT  0 65.36 0.192 65.392 ;
    END
  END coll_o[70]
  PIN coll_o[71]
    DIRECTION OUTPUT ;
    USE SIGNAL ;
    PORT
      LAYER M6 ;
        RECT  0 66.256 0.192 66.288 ;
    END
  END coll_o[71]
  PIN coll_o[72]
    DIRECTION OUTPUT ;
    USE SIGNAL ;
    PORT
      LAYER M6 ;
        RECT  0 67.152 0.192 67.184 ;
    END
  END coll_o[72]
  PIN coll_o[73]
    DIRECTION OUTPUT ;
    USE SIGNAL ;
    PORT
      LAYER M6 ;
        RECT  0 68.048 0.192 68.08 ;
    END
  END coll_o[73]
  PIN coll_o[74]
    DIRECTION OUTPUT ;
    USE SIGNAL ;
    PORT
      LAYER M6 ;
        RECT  0 68.944 0.192 68.976 ;
    END
  END coll_o[74]
  PIN coll_o[75]
    DIRECTION OUTPUT ;
    USE SIGNAL ;
    PORT
      LAYER M6 ;
        RECT  0 69.84 0.192 69.872 ;
    END
  END coll_o[75]
  PIN coll_o[76]
    DIRECTION OUTPUT ;
    USE SIGNAL ;
    PORT
      LAYER M6 ;
        RECT  0 70.736 0.192 70.768 ;
    END
  END coll_o[76]
  PIN coll_o[77]
    DIRECTION OUTPUT ;
    USE SIGNAL ;
    PORT
      LAYER M6 ;
        RECT  0 71.696 0.192 71.728 ;
    END
  END coll_o[77]
  PIN coll_o[78]
    DIRECTION OUTPUT ;
    USE SIGNAL ;
    PORT
      LAYER M6 ;
        RECT  0 72.592 0.192 72.624 ;
    END
  END coll_o[78]
  PIN coll_o[79]
    DIRECTION OUTPUT ;
    USE SIGNAL ;
    PORT
      LAYER M6 ;
        RECT  0 73.488 0.192 73.52 ;
    END
  END coll_o[79]
  PIN coll_o[7]
    DIRECTION OUTPUT ;
    USE SIGNAL ;
    PORT
      LAYER M6 ;
        RECT  0 8.336 0.192 8.368 ;
    END
  END coll_o[7]
  PIN coll_o[80]
    DIRECTION OUTPUT ;
    USE SIGNAL ;
    PORT
      LAYER M6 ;
        RECT  0 74.384 0.192 74.416 ;
    END
  END coll_o[80]
  PIN coll_o[81]
    DIRECTION OUTPUT ;
    USE SIGNAL ;
    PORT
      LAYER M6 ;
        RECT  0 75.28 0.192 75.312 ;
    END
  END coll_o[81]
  PIN coll_o[82]
    DIRECTION OUTPUT ;
    USE SIGNAL ;
    PORT
      LAYER M6 ;
        RECT  0 76.176 0.192 76.208 ;
    END
  END coll_o[82]
  PIN coll_o[83]
    DIRECTION OUTPUT ;
    USE SIGNAL ;
    PORT
      LAYER M6 ;
        RECT  0 77.072 0.192 77.104 ;
    END
  END coll_o[83]
  PIN coll_o[84]
    DIRECTION OUTPUT ;
    USE SIGNAL ;
    PORT
      LAYER M6 ;
        RECT  0 78.032 0.192 78.064 ;
    END
  END coll_o[84]
  PIN coll_o[85]
    DIRECTION OUTPUT ;
    USE SIGNAL ;
    PORT
      LAYER M6 ;
        RECT  0 78.928 0.192 78.96 ;
    END
  END coll_o[85]
  PIN coll_o[86]
    DIRECTION OUTPUT ;
    USE SIGNAL ;
    PORT
      LAYER M6 ;
        RECT  0 79.824 0.192 79.856 ;
    END
  END coll_o[86]
  PIN coll_o[87]
    DIRECTION OUTPUT ;
    USE SIGNAL ;
    PORT
      LAYER M6 ;
        RECT  0 80.72 0.192 80.752 ;
    END
  END coll_o[87]
  PIN coll_o[88]
    DIRECTION OUTPUT ;
    USE SIGNAL ;
    PORT
      LAYER M6 ;
        RECT  0 81.616 0.192 81.648 ;
    END
  END coll_o[88]
  PIN coll_o[89]
    DIRECTION OUTPUT ;
    USE SIGNAL ;
    PORT
      LAYER M6 ;
        RECT  0 82.512 0.192 82.544 ;
    END
  END coll_o[89]
  PIN coll_o[8]
    DIRECTION OUTPUT ;
    USE SIGNAL ;
    PORT
      LAYER M6 ;
        RECT  0 9.232 0.192 9.264 ;
    END
  END coll_o[8]
  PIN coll_o[90]
    DIRECTION OUTPUT ;
    USE SIGNAL ;
    PORT
      LAYER M6 ;
        RECT  0 83.408 0.192 83.44 ;
    END
  END coll_o[90]
  PIN coll_o[91]
    DIRECTION OUTPUT ;
    USE SIGNAL ;
    PORT
      LAYER M6 ;
        RECT  0 84.368 0.192 84.4 ;
    END
  END coll_o[91]
  PIN coll_o[92]
    DIRECTION OUTPUT ;
    USE SIGNAL ;
    PORT
      LAYER M6 ;
        RECT  0 85.264 0.192 85.296 ;
    END
  END coll_o[92]
  PIN coll_o[93]
    DIRECTION OUTPUT ;
    USE SIGNAL ;
    PORT
      LAYER M6 ;
        RECT  0 86.16 0.192 86.192 ;
    END
  END coll_o[93]
  PIN coll_o[94]
    DIRECTION OUTPUT ;
    USE SIGNAL ;
    PORT
      LAYER M6 ;
        RECT  0 87.056 0.192 87.088 ;
    END
  END coll_o[94]
  PIN coll_o[95]
    DIRECTION OUTPUT ;
    USE SIGNAL ;
    PORT
      LAYER M6 ;
        RECT  0 87.952 0.192 87.984 ;
    END
  END coll_o[95]
  PIN coll_o[96]
    DIRECTION OUTPUT ;
    USE SIGNAL ;
    PORT
      LAYER M6 ;
        RECT  0 88.848 0.192 88.88 ;
    END
  END coll_o[96]
  PIN coll_o[97]
    DIRECTION OUTPUT ;
    USE SIGNAL ;
    PORT
      LAYER M6 ;
        RECT  0 89.744 0.192 89.776 ;
    END
  END coll_o[97]
  PIN coll_o[98]
    DIRECTION OUTPUT ;
    USE SIGNAL ;
    PORT
      LAYER M6 ;
        RECT  0 90.704 0.192 90.736 ;
    END
  END coll_o[98]
  PIN coll_o[99]
    DIRECTION OUTPUT ;
    USE SIGNAL ;
    PORT
      LAYER M6 ;
        RECT  0 91.6 0.192 91.632 ;
    END
  END coll_o[99]
  PIN coll_o[9]
    DIRECTION OUTPUT ;
    USE SIGNAL ;
    PORT
      LAYER M6 ;
        RECT  0 10.128 0.192 10.16 ;
    END
  END coll_o[9]
  PIN k_flt[0]
    DIRECTION OUTPUT ;
    USE SIGNAL ;
    PORT
      LAYER M7 ;
        RECT  393.936 0 393.968 0.192 ;
    END
  END k_flt[0]
  PIN k_flt[1]
    DIRECTION OUTPUT ;
    USE SIGNAL ;
    PORT
      LAYER M7 ;
        RECT  394.64 0 394.672 0.192 ;
    END
  END k_flt[1]
  PIN k_flt[2]
    DIRECTION OUTPUT ;
    USE SIGNAL ;
    PORT
      LAYER M7 ;
        RECT  395.408 0 395.44 0.192 ;
    END
  END k_flt[2]
  PIN k_li_d[0]
    DIRECTION OUTPUT ;
    USE SIGNAL ;
    PORT
      LAYER M7 ;
        RECT  3.408 0 3.44 0.192 ;
    END
  END k_li_d[0]
  PIN k_li_d[100]
    DIRECTION OUTPUT ;
    USE SIGNAL ;
    PORT
      LAYER M7 ;
        RECT  74 0 74.032 0.192 ;
    END
  END k_li_d[100]
  PIN k_li_d[101]
    DIRECTION OUTPUT ;
    USE SIGNAL ;
    PORT
      LAYER M7 ;
        RECT  74.704 0 74.736 0.192 ;
    END
  END k_li_d[101]
  PIN k_li_d[102]
    DIRECTION OUTPUT ;
    USE SIGNAL ;
    PORT
      LAYER M7 ;
        RECT  75.408 0 75.44 0.192 ;
    END
  END k_li_d[102]
  PIN k_li_d[103]
    DIRECTION OUTPUT ;
    USE SIGNAL ;
    PORT
      LAYER M7 ;
        RECT  76.112 0 76.144 0.192 ;
    END
  END k_li_d[103]
  PIN k_li_d[104]
    DIRECTION OUTPUT ;
    USE SIGNAL ;
    PORT
      LAYER M7 ;
        RECT  76.816 0 76.848 0.192 ;
    END
  END k_li_d[104]
  PIN k_li_d[105]
    DIRECTION OUTPUT ;
    USE SIGNAL ;
    PORT
      LAYER M7 ;
        RECT  77.52 0 77.552 0.192 ;
    END
  END k_li_d[105]
  PIN k_li_d[106]
    DIRECTION OUTPUT ;
    USE SIGNAL ;
    PORT
      LAYER M7 ;
        RECT  78.224 0 78.256 0.192 ;
    END
  END k_li_d[106]
  PIN k_li_d[107]
    DIRECTION OUTPUT ;
    USE SIGNAL ;
    PORT
      LAYER M7 ;
        RECT  78.928 0 78.96 0.192 ;
    END
  END k_li_d[107]
  PIN k_li_d[108]
    DIRECTION OUTPUT ;
    USE SIGNAL ;
    PORT
      LAYER M7 ;
        RECT  79.632 0 79.664 0.192 ;
    END
  END k_li_d[108]
  PIN k_li_d[109]
    DIRECTION OUTPUT ;
    USE SIGNAL ;
    PORT
      LAYER M7 ;
        RECT  80.336 0 80.368 0.192 ;
    END
  END k_li_d[109]
  PIN k_li_d[10]
    DIRECTION OUTPUT ;
    USE SIGNAL ;
    PORT
      LAYER M7 ;
        RECT  10.448 0 10.48 0.192 ;
    END
  END k_li_d[10]
  PIN k_li_d[110]
    DIRECTION OUTPUT ;
    USE SIGNAL ;
    PORT
      LAYER M7 ;
        RECT  81.104 0 81.136 0.192 ;
    END
  END k_li_d[110]
  PIN k_li_d[111]
    DIRECTION OUTPUT ;
    USE SIGNAL ;
    PORT
      LAYER M7 ;
        RECT  81.808 0 81.84 0.192 ;
    END
  END k_li_d[111]
  PIN k_li_d[112]
    DIRECTION OUTPUT ;
    USE SIGNAL ;
    PORT
      LAYER M7 ;
        RECT  82.512 0 82.544 0.192 ;
    END
  END k_li_d[112]
  PIN k_li_d[113]
    DIRECTION OUTPUT ;
    USE SIGNAL ;
    PORT
      LAYER M7 ;
        RECT  83.216 0 83.248 0.192 ;
    END
  END k_li_d[113]
  PIN k_li_d[114]
    DIRECTION OUTPUT ;
    USE SIGNAL ;
    PORT
      LAYER M7 ;
        RECT  83.92 0 83.952 0.192 ;
    END
  END k_li_d[114]
  PIN k_li_d[115]
    DIRECTION OUTPUT ;
    USE SIGNAL ;
    PORT
      LAYER M7 ;
        RECT  84.624 0 84.656 0.192 ;
    END
  END k_li_d[115]
  PIN k_li_d[116]
    DIRECTION OUTPUT ;
    USE SIGNAL ;
    PORT
      LAYER M7 ;
        RECT  85.328 0 85.36 0.192 ;
    END
  END k_li_d[116]
  PIN k_li_d[117]
    DIRECTION OUTPUT ;
    USE SIGNAL ;
    PORT
      LAYER M7 ;
        RECT  86.032 0 86.064 0.192 ;
    END
  END k_li_d[117]
  PIN k_li_d[118]
    DIRECTION OUTPUT ;
    USE SIGNAL ;
    PORT
      LAYER M7 ;
        RECT  86.736 0 86.768 0.192 ;
    END
  END k_li_d[118]
  PIN k_li_d[119]
    DIRECTION OUTPUT ;
    USE SIGNAL ;
    PORT
      LAYER M7 ;
        RECT  87.44 0 87.472 0.192 ;
    END
  END k_li_d[119]
  PIN k_li_d[11]
    DIRECTION OUTPUT ;
    USE SIGNAL ;
    PORT
      LAYER M7 ;
        RECT  11.152 0 11.184 0.192 ;
    END
  END k_li_d[11]
  PIN k_li_d[120]
    DIRECTION OUTPUT ;
    USE SIGNAL ;
    PORT
      LAYER M7 ;
        RECT  88.144 0 88.176 0.192 ;
    END
  END k_li_d[120]
  PIN k_li_d[121]
    DIRECTION OUTPUT ;
    USE SIGNAL ;
    PORT
      LAYER M7 ;
        RECT  88.848 0 88.88 0.192 ;
    END
  END k_li_d[121]
  PIN k_li_d[122]
    DIRECTION OUTPUT ;
    USE SIGNAL ;
    PORT
      LAYER M7 ;
        RECT  89.552 0 89.584 0.192 ;
    END
  END k_li_d[122]
  PIN k_li_d[123]
    DIRECTION OUTPUT ;
    USE SIGNAL ;
    PORT
      LAYER M7 ;
        RECT  90.256 0 90.288 0.192 ;
    END
  END k_li_d[123]
  PIN k_li_d[124]
    DIRECTION OUTPUT ;
    USE SIGNAL ;
    PORT
      LAYER M7 ;
        RECT  90.96 0 90.992 0.192 ;
    END
  END k_li_d[124]
  PIN k_li_d[125]
    DIRECTION OUTPUT ;
    USE SIGNAL ;
    PORT
      LAYER M7 ;
        RECT  91.664 0 91.696 0.192 ;
    END
  END k_li_d[125]
  PIN k_li_d[126]
    DIRECTION OUTPUT ;
    USE SIGNAL ;
    PORT
      LAYER M7 ;
        RECT  92.368 0 92.4 0.192 ;
    END
  END k_li_d[126]
  PIN k_li_d[127]
    DIRECTION OUTPUT ;
    USE SIGNAL ;
    PORT
      LAYER M7 ;
        RECT  93.072 0 93.104 0.192 ;
    END
  END k_li_d[127]
  PIN k_li_d[128]
    DIRECTION OUTPUT ;
    USE SIGNAL ;
    PORT
      LAYER M7 ;
        RECT  93.776 0 93.808 0.192 ;
    END
  END k_li_d[128]
  PIN k_li_d[129]
    DIRECTION OUTPUT ;
    USE SIGNAL ;
    PORT
      LAYER M7 ;
        RECT  94.48 0 94.512 0.192 ;
    END
  END k_li_d[129]
  PIN k_li_d[12]
    DIRECTION OUTPUT ;
    USE SIGNAL ;
    PORT
      LAYER M7 ;
        RECT  11.856 0 11.888 0.192 ;
    END
  END k_li_d[12]
  PIN k_li_d[130]
    DIRECTION OUTPUT ;
    USE SIGNAL ;
    PORT
      LAYER M7 ;
        RECT  95.184 0 95.216 0.192 ;
    END
  END k_li_d[130]
  PIN k_li_d[131]
    DIRECTION OUTPUT ;
    USE SIGNAL ;
    PORT
      LAYER M7 ;
        RECT  95.888 0 95.92 0.192 ;
    END
  END k_li_d[131]
  PIN k_li_d[132]
    DIRECTION OUTPUT ;
    USE SIGNAL ;
    PORT
      LAYER M7 ;
        RECT  96.592 0 96.624 0.192 ;
    END
  END k_li_d[132]
  PIN k_li_d[133]
    DIRECTION OUTPUT ;
    USE SIGNAL ;
    PORT
      LAYER M7 ;
        RECT  97.296 0 97.328 0.192 ;
    END
  END k_li_d[133]
  PIN k_li_d[134]
    DIRECTION OUTPUT ;
    USE SIGNAL ;
    PORT
      LAYER M7 ;
        RECT  98 0 98.032 0.192 ;
    END
  END k_li_d[134]
  PIN k_li_d[135]
    DIRECTION OUTPUT ;
    USE SIGNAL ;
    PORT
      LAYER M7 ;
        RECT  98.704 0 98.736 0.192 ;
    END
  END k_li_d[135]
  PIN k_li_d[136]
    DIRECTION OUTPUT ;
    USE SIGNAL ;
    PORT
      LAYER M7 ;
        RECT  99.408 0 99.44 0.192 ;
    END
  END k_li_d[136]
  PIN k_li_d[137]
    DIRECTION OUTPUT ;
    USE SIGNAL ;
    PORT
      LAYER M7 ;
        RECT  100.112 0 100.144 0.192 ;
    END
  END k_li_d[137]
  PIN k_li_d[138]
    DIRECTION OUTPUT ;
    USE SIGNAL ;
    PORT
      LAYER M7 ;
        RECT  100.88 0 100.912 0.192 ;
    END
  END k_li_d[138]
  PIN k_li_d[139]
    DIRECTION OUTPUT ;
    USE SIGNAL ;
    PORT
      LAYER M7 ;
        RECT  101.584 0 101.616 0.192 ;
    END
  END k_li_d[139]
  PIN k_li_d[13]
    DIRECTION OUTPUT ;
    USE SIGNAL ;
    PORT
      LAYER M7 ;
        RECT  12.56 0 12.592 0.192 ;
    END
  END k_li_d[13]
  PIN k_li_d[140]
    DIRECTION OUTPUT ;
    USE SIGNAL ;
    PORT
      LAYER M7 ;
        RECT  102.288 0 102.32 0.192 ;
    END
  END k_li_d[140]
  PIN k_li_d[141]
    DIRECTION OUTPUT ;
    USE SIGNAL ;
    PORT
      LAYER M7 ;
        RECT  102.992 0 103.024 0.192 ;
    END
  END k_li_d[141]
  PIN k_li_d[142]
    DIRECTION OUTPUT ;
    USE SIGNAL ;
    PORT
      LAYER M7 ;
        RECT  103.696 0 103.728 0.192 ;
    END
  END k_li_d[142]
  PIN k_li_d[143]
    DIRECTION OUTPUT ;
    USE SIGNAL ;
    PORT
      LAYER M7 ;
        RECT  104.4 0 104.432 0.192 ;
    END
  END k_li_d[143]
  PIN k_li_d[144]
    DIRECTION OUTPUT ;
    USE SIGNAL ;
    PORT
      LAYER M7 ;
        RECT  105.104 0 105.136 0.192 ;
    END
  END k_li_d[144]
  PIN k_li_d[145]
    DIRECTION OUTPUT ;
    USE SIGNAL ;
    PORT
      LAYER M7 ;
        RECT  105.808 0 105.84 0.192 ;
    END
  END k_li_d[145]
  PIN k_li_d[146]
    DIRECTION OUTPUT ;
    USE SIGNAL ;
    PORT
      LAYER M7 ;
        RECT  106.512 0 106.544 0.192 ;
    END
  END k_li_d[146]
  PIN k_li_d[147]
    DIRECTION OUTPUT ;
    USE SIGNAL ;
    PORT
      LAYER M7 ;
        RECT  107.216 0 107.248 0.192 ;
    END
  END k_li_d[147]
  PIN k_li_d[148]
    DIRECTION OUTPUT ;
    USE SIGNAL ;
    PORT
      LAYER M7 ;
        RECT  107.92 0 107.952 0.192 ;
    END
  END k_li_d[148]
  PIN k_li_d[149]
    DIRECTION OUTPUT ;
    USE SIGNAL ;
    PORT
      LAYER M7 ;
        RECT  108.624 0 108.656 0.192 ;
    END
  END k_li_d[149]
  PIN k_li_d[14]
    DIRECTION OUTPUT ;
    USE SIGNAL ;
    PORT
      LAYER M7 ;
        RECT  13.264 0 13.296 0.192 ;
    END
  END k_li_d[14]
  PIN k_li_d[150]
    DIRECTION OUTPUT ;
    USE SIGNAL ;
    PORT
      LAYER M7 ;
        RECT  109.328 0 109.36 0.192 ;
    END
  END k_li_d[150]
  PIN k_li_d[151]
    DIRECTION OUTPUT ;
    USE SIGNAL ;
    PORT
      LAYER M7 ;
        RECT  110.032 0 110.064 0.192 ;
    END
  END k_li_d[151]
  PIN k_li_d[152]
    DIRECTION OUTPUT ;
    USE SIGNAL ;
    PORT
      LAYER M7 ;
        RECT  110.736 0 110.768 0.192 ;
    END
  END k_li_d[152]
  PIN k_li_d[153]
    DIRECTION OUTPUT ;
    USE SIGNAL ;
    PORT
      LAYER M7 ;
        RECT  111.44 0 111.472 0.192 ;
    END
  END k_li_d[153]
  PIN k_li_d[154]
    DIRECTION OUTPUT ;
    USE SIGNAL ;
    PORT
      LAYER M7 ;
        RECT  112.144 0 112.176 0.192 ;
    END
  END k_li_d[154]
  PIN k_li_d[155]
    DIRECTION OUTPUT ;
    USE SIGNAL ;
    PORT
      LAYER M7 ;
        RECT  112.848 0 112.88 0.192 ;
    END
  END k_li_d[155]
  PIN k_li_d[156]
    DIRECTION OUTPUT ;
    USE SIGNAL ;
    PORT
      LAYER M7 ;
        RECT  113.552 0 113.584 0.192 ;
    END
  END k_li_d[156]
  PIN k_li_d[157]
    DIRECTION OUTPUT ;
    USE SIGNAL ;
    PORT
      LAYER M7 ;
        RECT  114.256 0 114.288 0.192 ;
    END
  END k_li_d[157]
  PIN k_li_d[158]
    DIRECTION OUTPUT ;
    USE SIGNAL ;
    PORT
      LAYER M7 ;
        RECT  114.96 0 114.992 0.192 ;
    END
  END k_li_d[158]
  PIN k_li_d[159]
    DIRECTION OUTPUT ;
    USE SIGNAL ;
    PORT
      LAYER M7 ;
        RECT  115.664 0 115.696 0.192 ;
    END
  END k_li_d[159]
  PIN k_li_d[15]
    DIRECTION OUTPUT ;
    USE SIGNAL ;
    PORT
      LAYER M7 ;
        RECT  13.968 0 14 0.192 ;
    END
  END k_li_d[15]
  PIN k_li_d[160]
    DIRECTION OUTPUT ;
    USE SIGNAL ;
    PORT
      LAYER M7 ;
        RECT  116.368 0 116.4 0.192 ;
    END
  END k_li_d[160]
  PIN k_li_d[161]
    DIRECTION OUTPUT ;
    USE SIGNAL ;
    PORT
      LAYER M7 ;
        RECT  117.072 0 117.104 0.192 ;
    END
  END k_li_d[161]
  PIN k_li_d[162]
    DIRECTION OUTPUT ;
    USE SIGNAL ;
    PORT
      LAYER M7 ;
        RECT  117.776 0 117.808 0.192 ;
    END
  END k_li_d[162]
  PIN k_li_d[163]
    DIRECTION OUTPUT ;
    USE SIGNAL ;
    PORT
      LAYER M7 ;
        RECT  118.48 0 118.512 0.192 ;
    END
  END k_li_d[163]
  PIN k_li_d[164]
    DIRECTION OUTPUT ;
    USE SIGNAL ;
    PORT
      LAYER M7 ;
        RECT  119.184 0 119.216 0.192 ;
    END
  END k_li_d[164]
  PIN k_li_d[165]
    DIRECTION OUTPUT ;
    USE SIGNAL ;
    PORT
      LAYER M7 ;
        RECT  119.888 0 119.92 0.192 ;
    END
  END k_li_d[165]
  PIN k_li_d[166]
    DIRECTION OUTPUT ;
    USE SIGNAL ;
    PORT
      LAYER M7 ;
        RECT  120.656 0 120.688 0.192 ;
    END
  END k_li_d[166]
  PIN k_li_d[167]
    DIRECTION OUTPUT ;
    USE SIGNAL ;
    PORT
      LAYER M7 ;
        RECT  121.36 0 121.392 0.192 ;
    END
  END k_li_d[167]
  PIN k_li_d[168]
    DIRECTION OUTPUT ;
    USE SIGNAL ;
    PORT
      LAYER M7 ;
        RECT  122.064 0 122.096 0.192 ;
    END
  END k_li_d[168]
  PIN k_li_d[169]
    DIRECTION OUTPUT ;
    USE SIGNAL ;
    PORT
      LAYER M7 ;
        RECT  122.768 0 122.8 0.192 ;
    END
  END k_li_d[169]
  PIN k_li_d[16]
    DIRECTION OUTPUT ;
    USE SIGNAL ;
    PORT
      LAYER M7 ;
        RECT  14.672 0 14.704 0.192 ;
    END
  END k_li_d[16]
  PIN k_li_d[170]
    DIRECTION OUTPUT ;
    USE SIGNAL ;
    PORT
      LAYER M7 ;
        RECT  123.472 0 123.504 0.192 ;
    END
  END k_li_d[170]
  PIN k_li_d[171]
    DIRECTION OUTPUT ;
    USE SIGNAL ;
    PORT
      LAYER M7 ;
        RECT  124.176 0 124.208 0.192 ;
    END
  END k_li_d[171]
  PIN k_li_d[172]
    DIRECTION OUTPUT ;
    USE SIGNAL ;
    PORT
      LAYER M7 ;
        RECT  124.88 0 124.912 0.192 ;
    END
  END k_li_d[172]
  PIN k_li_d[173]
    DIRECTION OUTPUT ;
    USE SIGNAL ;
    PORT
      LAYER M7 ;
        RECT  125.584 0 125.616 0.192 ;
    END
  END k_li_d[173]
  PIN k_li_d[174]
    DIRECTION OUTPUT ;
    USE SIGNAL ;
    PORT
      LAYER M7 ;
        RECT  126.288 0 126.32 0.192 ;
    END
  END k_li_d[174]
  PIN k_li_d[175]
    DIRECTION OUTPUT ;
    USE SIGNAL ;
    PORT
      LAYER M7 ;
        RECT  126.992 0 127.024 0.192 ;
    END
  END k_li_d[175]
  PIN k_li_d[176]
    DIRECTION OUTPUT ;
    USE SIGNAL ;
    PORT
      LAYER M7 ;
        RECT  127.696 0 127.728 0.192 ;
    END
  END k_li_d[176]
  PIN k_li_d[177]
    DIRECTION OUTPUT ;
    USE SIGNAL ;
    PORT
      LAYER M7 ;
        RECT  128.4 0 128.432 0.192 ;
    END
  END k_li_d[177]
  PIN k_li_d[178]
    DIRECTION OUTPUT ;
    USE SIGNAL ;
    PORT
      LAYER M7 ;
        RECT  129.104 0 129.136 0.192 ;
    END
  END k_li_d[178]
  PIN k_li_d[179]
    DIRECTION OUTPUT ;
    USE SIGNAL ;
    PORT
      LAYER M7 ;
        RECT  129.808 0 129.84 0.192 ;
    END
  END k_li_d[179]
  PIN k_li_d[17]
    DIRECTION OUTPUT ;
    USE SIGNAL ;
    PORT
      LAYER M7 ;
        RECT  15.376 0 15.408 0.192 ;
    END
  END k_li_d[17]
  PIN k_li_d[180]
    DIRECTION OUTPUT ;
    USE SIGNAL ;
    PORT
      LAYER M7 ;
        RECT  130.512 0 130.544 0.192 ;
    END
  END k_li_d[180]
  PIN k_li_d[181]
    DIRECTION OUTPUT ;
    USE SIGNAL ;
    PORT
      LAYER M7 ;
        RECT  131.216 0 131.248 0.192 ;
    END
  END k_li_d[181]
  PIN k_li_d[182]
    DIRECTION OUTPUT ;
    USE SIGNAL ;
    PORT
      LAYER M7 ;
        RECT  131.92 0 131.952 0.192 ;
    END
  END k_li_d[182]
  PIN k_li_d[183]
    DIRECTION OUTPUT ;
    USE SIGNAL ;
    PORT
      LAYER M7 ;
        RECT  132.624 0 132.656 0.192 ;
    END
  END k_li_d[183]
  PIN k_li_d[184]
    DIRECTION OUTPUT ;
    USE SIGNAL ;
    PORT
      LAYER M7 ;
        RECT  133.328 0 133.36 0.192 ;
    END
  END k_li_d[184]
  PIN k_li_d[185]
    DIRECTION OUTPUT ;
    USE SIGNAL ;
    PORT
      LAYER M7 ;
        RECT  134.032 0 134.064 0.192 ;
    END
  END k_li_d[185]
  PIN k_li_d[186]
    DIRECTION OUTPUT ;
    USE SIGNAL ;
    PORT
      LAYER M7 ;
        RECT  134.736 0 134.768 0.192 ;
    END
  END k_li_d[186]
  PIN k_li_d[187]
    DIRECTION OUTPUT ;
    USE SIGNAL ;
    PORT
      LAYER M7 ;
        RECT  135.44 0 135.472 0.192 ;
    END
  END k_li_d[187]
  PIN k_li_d[188]
    DIRECTION OUTPUT ;
    USE SIGNAL ;
    PORT
      LAYER M7 ;
        RECT  136.144 0 136.176 0.192 ;
    END
  END k_li_d[188]
  PIN k_li_d[189]
    DIRECTION OUTPUT ;
    USE SIGNAL ;
    PORT
      LAYER M7 ;
        RECT  136.848 0 136.88 0.192 ;
    END
  END k_li_d[189]
  PIN k_li_d[18]
    DIRECTION OUTPUT ;
    USE SIGNAL ;
    PORT
      LAYER M7 ;
        RECT  16.08 0 16.112 0.192 ;
    END
  END k_li_d[18]
  PIN k_li_d[190]
    DIRECTION OUTPUT ;
    USE SIGNAL ;
    PORT
      LAYER M7 ;
        RECT  137.552 0 137.584 0.192 ;
    END
  END k_li_d[190]
  PIN k_li_d[191]
    DIRECTION OUTPUT ;
    USE SIGNAL ;
    PORT
      LAYER M7 ;
        RECT  138.256 0 138.288 0.192 ;
    END
  END k_li_d[191]
  PIN k_li_d[192]
    DIRECTION OUTPUT ;
    USE SIGNAL ;
    PORT
      LAYER M7 ;
        RECT  138.96 0 138.992 0.192 ;
    END
  END k_li_d[192]
  PIN k_li_d[193]
    DIRECTION OUTPUT ;
    USE SIGNAL ;
    PORT
      LAYER M7 ;
        RECT  139.728 0 139.76 0.192 ;
    END
  END k_li_d[193]
  PIN k_li_d[194]
    DIRECTION OUTPUT ;
    USE SIGNAL ;
    PORT
      LAYER M7 ;
        RECT  140.432 0 140.464 0.192 ;
    END
  END k_li_d[194]
  PIN k_li_d[195]
    DIRECTION OUTPUT ;
    USE SIGNAL ;
    PORT
      LAYER M7 ;
        RECT  141.136 0 141.168 0.192 ;
    END
  END k_li_d[195]
  PIN k_li_d[196]
    DIRECTION OUTPUT ;
    USE SIGNAL ;
    PORT
      LAYER M7 ;
        RECT  141.84 0 141.872 0.192 ;
    END
  END k_li_d[196]
  PIN k_li_d[197]
    DIRECTION OUTPUT ;
    USE SIGNAL ;
    PORT
      LAYER M7 ;
        RECT  142.544 0 142.576 0.192 ;
    END
  END k_li_d[197]
  PIN k_li_d[198]
    DIRECTION OUTPUT ;
    USE SIGNAL ;
    PORT
      LAYER M7 ;
        RECT  143.248 0 143.28 0.192 ;
    END
  END k_li_d[198]
  PIN k_li_d[199]
    DIRECTION OUTPUT ;
    USE SIGNAL ;
    PORT
      LAYER M7 ;
        RECT  143.952 0 143.984 0.192 ;
    END
  END k_li_d[199]
  PIN k_li_d[19]
    DIRECTION OUTPUT ;
    USE SIGNAL ;
    PORT
      LAYER M7 ;
        RECT  16.784 0 16.816 0.192 ;
    END
  END k_li_d[19]
  PIN k_li_d[1]
    DIRECTION OUTPUT ;
    USE SIGNAL ;
    PORT
      LAYER M7 ;
        RECT  4.112 0 4.144 0.192 ;
    END
  END k_li_d[1]
  PIN k_li_d[200]
    DIRECTION OUTPUT ;
    USE SIGNAL ;
    PORT
      LAYER M7 ;
        RECT  144.656 0 144.688 0.192 ;
    END
  END k_li_d[200]
  PIN k_li_d[201]
    DIRECTION OUTPUT ;
    USE SIGNAL ;
    PORT
      LAYER M7 ;
        RECT  145.36 0 145.392 0.192 ;
    END
  END k_li_d[201]
  PIN k_li_d[202]
    DIRECTION OUTPUT ;
    USE SIGNAL ;
    PORT
      LAYER M7 ;
        RECT  146.064 0 146.096 0.192 ;
    END
  END k_li_d[202]
  PIN k_li_d[203]
    DIRECTION OUTPUT ;
    USE SIGNAL ;
    PORT
      LAYER M7 ;
        RECT  146.768 0 146.8 0.192 ;
    END
  END k_li_d[203]
  PIN k_li_d[204]
    DIRECTION OUTPUT ;
    USE SIGNAL ;
    PORT
      LAYER M7 ;
        RECT  147.472 0 147.504 0.192 ;
    END
  END k_li_d[204]
  PIN k_li_d[205]
    DIRECTION OUTPUT ;
    USE SIGNAL ;
    PORT
      LAYER M7 ;
        RECT  148.176 0 148.208 0.192 ;
    END
  END k_li_d[205]
  PIN k_li_d[206]
    DIRECTION OUTPUT ;
    USE SIGNAL ;
    PORT
      LAYER M7 ;
        RECT  148.88 0 148.912 0.192 ;
    END
  END k_li_d[206]
  PIN k_li_d[207]
    DIRECTION OUTPUT ;
    USE SIGNAL ;
    PORT
      LAYER M7 ;
        RECT  149.584 0 149.616 0.192 ;
    END
  END k_li_d[207]
  PIN k_li_d[208]
    DIRECTION OUTPUT ;
    USE SIGNAL ;
    PORT
      LAYER M7 ;
        RECT  150.288 0 150.32 0.192 ;
    END
  END k_li_d[208]
  PIN k_li_d[209]
    DIRECTION OUTPUT ;
    USE SIGNAL ;
    PORT
      LAYER M7 ;
        RECT  150.992 0 151.024 0.192 ;
    END
  END k_li_d[209]
  PIN k_li_d[20]
    DIRECTION OUTPUT ;
    USE SIGNAL ;
    PORT
      LAYER M7 ;
        RECT  17.488 0 17.52 0.192 ;
    END
  END k_li_d[20]
  PIN k_li_d[210]
    DIRECTION OUTPUT ;
    USE SIGNAL ;
    PORT
      LAYER M7 ;
        RECT  151.696 0 151.728 0.192 ;
    END
  END k_li_d[210]
  PIN k_li_d[211]
    DIRECTION OUTPUT ;
    USE SIGNAL ;
    PORT
      LAYER M7 ;
        RECT  152.4 0 152.432 0.192 ;
    END
  END k_li_d[211]
  PIN k_li_d[212]
    DIRECTION OUTPUT ;
    USE SIGNAL ;
    PORT
      LAYER M7 ;
        RECT  153.104 0 153.136 0.192 ;
    END
  END k_li_d[212]
  PIN k_li_d[213]
    DIRECTION OUTPUT ;
    USE SIGNAL ;
    PORT
      LAYER M7 ;
        RECT  153.808 0 153.84 0.192 ;
    END
  END k_li_d[213]
  PIN k_li_d[214]
    DIRECTION OUTPUT ;
    USE SIGNAL ;
    PORT
      LAYER M7 ;
        RECT  154.512 0 154.544 0.192 ;
    END
  END k_li_d[214]
  PIN k_li_d[215]
    DIRECTION OUTPUT ;
    USE SIGNAL ;
    PORT
      LAYER M7 ;
        RECT  155.216 0 155.248 0.192 ;
    END
  END k_li_d[215]
  PIN k_li_d[216]
    DIRECTION OUTPUT ;
    USE SIGNAL ;
    PORT
      LAYER M7 ;
        RECT  155.92 0 155.952 0.192 ;
    END
  END k_li_d[216]
  PIN k_li_d[217]
    DIRECTION OUTPUT ;
    USE SIGNAL ;
    PORT
      LAYER M7 ;
        RECT  156.624 0 156.656 0.192 ;
    END
  END k_li_d[217]
  PIN k_li_d[218]
    DIRECTION OUTPUT ;
    USE SIGNAL ;
    PORT
      LAYER M7 ;
        RECT  157.328 0 157.36 0.192 ;
    END
  END k_li_d[218]
  PIN k_li_d[219]
    DIRECTION OUTPUT ;
    USE SIGNAL ;
    PORT
      LAYER M7 ;
        RECT  158.032 0 158.064 0.192 ;
    END
  END k_li_d[219]
  PIN k_li_d[21]
    DIRECTION OUTPUT ;
    USE SIGNAL ;
    PORT
      LAYER M7 ;
        RECT  18.192 0 18.224 0.192 ;
    END
  END k_li_d[21]
  PIN k_li_d[220]
    DIRECTION OUTPUT ;
    USE SIGNAL ;
    PORT
      LAYER M7 ;
        RECT  158.736 0 158.768 0.192 ;
    END
  END k_li_d[220]
  PIN k_li_d[221]
    DIRECTION OUTPUT ;
    USE SIGNAL ;
    PORT
      LAYER M7 ;
        RECT  159.504 0 159.536 0.192 ;
    END
  END k_li_d[221]
  PIN k_li_d[222]
    DIRECTION OUTPUT ;
    USE SIGNAL ;
    PORT
      LAYER M7 ;
        RECT  160.208 0 160.24 0.192 ;
    END
  END k_li_d[222]
  PIN k_li_d[223]
    DIRECTION OUTPUT ;
    USE SIGNAL ;
    PORT
      LAYER M7 ;
        RECT  160.912 0 160.944 0.192 ;
    END
  END k_li_d[223]
  PIN k_li_d[224]
    DIRECTION OUTPUT ;
    USE SIGNAL ;
    PORT
      LAYER M7 ;
        RECT  161.616 0 161.648 0.192 ;
    END
  END k_li_d[224]
  PIN k_li_d[225]
    DIRECTION OUTPUT ;
    USE SIGNAL ;
    PORT
      LAYER M7 ;
        RECT  162.32 0 162.352 0.192 ;
    END
  END k_li_d[225]
  PIN k_li_d[226]
    DIRECTION OUTPUT ;
    USE SIGNAL ;
    PORT
      LAYER M7 ;
        RECT  163.024 0 163.056 0.192 ;
    END
  END k_li_d[226]
  PIN k_li_d[227]
    DIRECTION OUTPUT ;
    USE SIGNAL ;
    PORT
      LAYER M7 ;
        RECT  163.728 0 163.76 0.192 ;
    END
  END k_li_d[227]
  PIN k_li_d[228]
    DIRECTION OUTPUT ;
    USE SIGNAL ;
    PORT
      LAYER M7 ;
        RECT  164.432 0 164.464 0.192 ;
    END
  END k_li_d[228]
  PIN k_li_d[229]
    DIRECTION OUTPUT ;
    USE SIGNAL ;
    PORT
      LAYER M7 ;
        RECT  165.136 0 165.168 0.192 ;
    END
  END k_li_d[229]
  PIN k_li_d[22]
    DIRECTION OUTPUT ;
    USE SIGNAL ;
    PORT
      LAYER M7 ;
        RECT  18.896 0 18.928 0.192 ;
    END
  END k_li_d[22]
  PIN k_li_d[230]
    DIRECTION OUTPUT ;
    USE SIGNAL ;
    PORT
      LAYER M7 ;
        RECT  165.84 0 165.872 0.192 ;
    END
  END k_li_d[230]
  PIN k_li_d[231]
    DIRECTION OUTPUT ;
    USE SIGNAL ;
    PORT
      LAYER M7 ;
        RECT  166.544 0 166.576 0.192 ;
    END
  END k_li_d[231]
  PIN k_li_d[232]
    DIRECTION OUTPUT ;
    USE SIGNAL ;
    PORT
      LAYER M7 ;
        RECT  167.248 0 167.28 0.192 ;
    END
  END k_li_d[232]
  PIN k_li_d[233]
    DIRECTION OUTPUT ;
    USE SIGNAL ;
    PORT
      LAYER M7 ;
        RECT  167.952 0 167.984 0.192 ;
    END
  END k_li_d[233]
  PIN k_li_d[234]
    DIRECTION OUTPUT ;
    USE SIGNAL ;
    PORT
      LAYER M7 ;
        RECT  168.656 0 168.688 0.192 ;
    END
  END k_li_d[234]
  PIN k_li_d[235]
    DIRECTION OUTPUT ;
    USE SIGNAL ;
    PORT
      LAYER M7 ;
        RECT  169.36 0 169.392 0.192 ;
    END
  END k_li_d[235]
  PIN k_li_d[236]
    DIRECTION OUTPUT ;
    USE SIGNAL ;
    PORT
      LAYER M7 ;
        RECT  170.064 0 170.096 0.192 ;
    END
  END k_li_d[236]
  PIN k_li_d[237]
    DIRECTION OUTPUT ;
    USE SIGNAL ;
    PORT
      LAYER M7 ;
        RECT  170.768 0 170.8 0.192 ;
    END
  END k_li_d[237]
  PIN k_li_d[238]
    DIRECTION OUTPUT ;
    USE SIGNAL ;
    PORT
      LAYER M7 ;
        RECT  171.472 0 171.504 0.192 ;
    END
  END k_li_d[238]
  PIN k_li_d[239]
    DIRECTION OUTPUT ;
    USE SIGNAL ;
    PORT
      LAYER M7 ;
        RECT  172.176 0 172.208 0.192 ;
    END
  END k_li_d[239]
  PIN k_li_d[23]
    DIRECTION OUTPUT ;
    USE SIGNAL ;
    PORT
      LAYER M7 ;
        RECT  19.6 0 19.632 0.192 ;
    END
  END k_li_d[23]
  PIN k_li_d[240]
    DIRECTION OUTPUT ;
    USE SIGNAL ;
    PORT
      LAYER M7 ;
        RECT  172.88 0 172.912 0.192 ;
    END
  END k_li_d[240]
  PIN k_li_d[241]
    DIRECTION OUTPUT ;
    USE SIGNAL ;
    PORT
      LAYER M7 ;
        RECT  173.584 0 173.616 0.192 ;
    END
  END k_li_d[241]
  PIN k_li_d[242]
    DIRECTION OUTPUT ;
    USE SIGNAL ;
    PORT
      LAYER M7 ;
        RECT  174.288 0 174.32 0.192 ;
    END
  END k_li_d[242]
  PIN k_li_d[243]
    DIRECTION OUTPUT ;
    USE SIGNAL ;
    PORT
      LAYER M7 ;
        RECT  174.992 0 175.024 0.192 ;
    END
  END k_li_d[243]
  PIN k_li_d[244]
    DIRECTION OUTPUT ;
    USE SIGNAL ;
    PORT
      LAYER M7 ;
        RECT  175.696 0 175.728 0.192 ;
    END
  END k_li_d[244]
  PIN k_li_d[245]
    DIRECTION OUTPUT ;
    USE SIGNAL ;
    PORT
      LAYER M7 ;
        RECT  176.4 0 176.432 0.192 ;
    END
  END k_li_d[245]
  PIN k_li_d[246]
    DIRECTION OUTPUT ;
    USE SIGNAL ;
    PORT
      LAYER M7 ;
        RECT  177.104 0 177.136 0.192 ;
    END
  END k_li_d[246]
  PIN k_li_d[247]
    DIRECTION OUTPUT ;
    USE SIGNAL ;
    PORT
      LAYER M7 ;
        RECT  177.808 0 177.84 0.192 ;
    END
  END k_li_d[247]
  PIN k_li_d[248]
    DIRECTION OUTPUT ;
    USE SIGNAL ;
    PORT
      LAYER M7 ;
        RECT  178.512 0 178.544 0.192 ;
    END
  END k_li_d[248]
  PIN k_li_d[249]
    DIRECTION OUTPUT ;
    USE SIGNAL ;
    PORT
      LAYER M7 ;
        RECT  179.28 0 179.312 0.192 ;
    END
  END k_li_d[249]
  PIN k_li_d[24]
    DIRECTION OUTPUT ;
    USE SIGNAL ;
    PORT
      LAYER M7 ;
        RECT  20.304 0 20.336 0.192 ;
    END
  END k_li_d[24]
  PIN k_li_d[250]
    DIRECTION OUTPUT ;
    USE SIGNAL ;
    PORT
      LAYER M7 ;
        RECT  179.984 0 180.016 0.192 ;
    END
  END k_li_d[250]
  PIN k_li_d[251]
    DIRECTION OUTPUT ;
    USE SIGNAL ;
    PORT
      LAYER M7 ;
        RECT  180.688 0 180.72 0.192 ;
    END
  END k_li_d[251]
  PIN k_li_d[252]
    DIRECTION OUTPUT ;
    USE SIGNAL ;
    PORT
      LAYER M7 ;
        RECT  181.392 0 181.424 0.192 ;
    END
  END k_li_d[252]
  PIN k_li_d[253]
    DIRECTION OUTPUT ;
    USE SIGNAL ;
    PORT
      LAYER M7 ;
        RECT  182.096 0 182.128 0.192 ;
    END
  END k_li_d[253]
  PIN k_li_d[254]
    DIRECTION OUTPUT ;
    USE SIGNAL ;
    PORT
      LAYER M7 ;
        RECT  182.8 0 182.832 0.192 ;
    END
  END k_li_d[254]
  PIN k_li_d[255]
    DIRECTION OUTPUT ;
    USE SIGNAL ;
    PORT
      LAYER M7 ;
        RECT  183.504 0 183.536 0.192 ;
    END
  END k_li_d[255]
  PIN k_li_d[256]
    DIRECTION OUTPUT ;
    USE SIGNAL ;
    PORT
      LAYER M7 ;
        RECT  184.208 0 184.24 0.192 ;
    END
  END k_li_d[256]
  PIN k_li_d[257]
    DIRECTION OUTPUT ;
    USE SIGNAL ;
    PORT
      LAYER M7 ;
        RECT  184.912 0 184.944 0.192 ;
    END
  END k_li_d[257]
  PIN k_li_d[258]
    DIRECTION OUTPUT ;
    USE SIGNAL ;
    PORT
      LAYER M7 ;
        RECT  185.616 0 185.648 0.192 ;
    END
  END k_li_d[258]
  PIN k_li_d[259]
    DIRECTION OUTPUT ;
    USE SIGNAL ;
    PORT
      LAYER M7 ;
        RECT  186.32 0 186.352 0.192 ;
    END
  END k_li_d[259]
  PIN k_li_d[25]
    DIRECTION OUTPUT ;
    USE SIGNAL ;
    PORT
      LAYER M7 ;
        RECT  21.008 0 21.04 0.192 ;
    END
  END k_li_d[25]
  PIN k_li_d[260]
    DIRECTION OUTPUT ;
    USE SIGNAL ;
    PORT
      LAYER M7 ;
        RECT  187.024 0 187.056 0.192 ;
    END
  END k_li_d[260]
  PIN k_li_d[261]
    DIRECTION OUTPUT ;
    USE SIGNAL ;
    PORT
      LAYER M7 ;
        RECT  187.728 0 187.76 0.192 ;
    END
  END k_li_d[261]
  PIN k_li_d[262]
    DIRECTION OUTPUT ;
    USE SIGNAL ;
    PORT
      LAYER M7 ;
        RECT  188.432 0 188.464 0.192 ;
    END
  END k_li_d[262]
  PIN k_li_d[263]
    DIRECTION OUTPUT ;
    USE SIGNAL ;
    PORT
      LAYER M7 ;
        RECT  189.136 0 189.168 0.192 ;
    END
  END k_li_d[263]
  PIN k_li_d[264]
    DIRECTION OUTPUT ;
    USE SIGNAL ;
    PORT
      LAYER M7 ;
        RECT  189.84 0 189.872 0.192 ;
    END
  END k_li_d[264]
  PIN k_li_d[265]
    DIRECTION OUTPUT ;
    USE SIGNAL ;
    PORT
      LAYER M7 ;
        RECT  190.544 0 190.576 0.192 ;
    END
  END k_li_d[265]
  PIN k_li_d[266]
    DIRECTION OUTPUT ;
    USE SIGNAL ;
    PORT
      LAYER M7 ;
        RECT  191.248 0 191.28 0.192 ;
    END
  END k_li_d[266]
  PIN k_li_d[267]
    DIRECTION OUTPUT ;
    USE SIGNAL ;
    PORT
      LAYER M7 ;
        RECT  191.952 0 191.984 0.192 ;
    END
  END k_li_d[267]
  PIN k_li_d[268]
    DIRECTION OUTPUT ;
    USE SIGNAL ;
    PORT
      LAYER M7 ;
        RECT  192.656 0 192.688 0.192 ;
    END
  END k_li_d[268]
  PIN k_li_d[269]
    DIRECTION OUTPUT ;
    USE SIGNAL ;
    PORT
      LAYER M7 ;
        RECT  193.36 0 193.392 0.192 ;
    END
  END k_li_d[269]
  PIN k_li_d[26]
    DIRECTION OUTPUT ;
    USE SIGNAL ;
    PORT
      LAYER M7 ;
        RECT  21.776 0 21.808 0.192 ;
    END
  END k_li_d[26]
  PIN k_li_d[270]
    DIRECTION OUTPUT ;
    USE SIGNAL ;
    PORT
      LAYER M7 ;
        RECT  194.064 0 194.096 0.192 ;
    END
  END k_li_d[270]
  PIN k_li_d[271]
    DIRECTION OUTPUT ;
    USE SIGNAL ;
    PORT
      LAYER M7 ;
        RECT  194.768 0 194.8 0.192 ;
    END
  END k_li_d[271]
  PIN k_li_d[272]
    DIRECTION OUTPUT ;
    USE SIGNAL ;
    PORT
      LAYER M7 ;
        RECT  195.472 0 195.504 0.192 ;
    END
  END k_li_d[272]
  PIN k_li_d[273]
    DIRECTION OUTPUT ;
    USE SIGNAL ;
    PORT
      LAYER M7 ;
        RECT  196.176 0 196.208 0.192 ;
    END
  END k_li_d[273]
  PIN k_li_d[274]
    DIRECTION OUTPUT ;
    USE SIGNAL ;
    PORT
      LAYER M7 ;
        RECT  196.88 0 196.912 0.192 ;
    END
  END k_li_d[274]
  PIN k_li_d[275]
    DIRECTION OUTPUT ;
    USE SIGNAL ;
    PORT
      LAYER M7 ;
        RECT  197.584 0 197.616 0.192 ;
    END
  END k_li_d[275]
  PIN k_li_d[276]
    DIRECTION OUTPUT ;
    USE SIGNAL ;
    PORT
      LAYER M7 ;
        RECT  198.288 0 198.32 0.192 ;
    END
  END k_li_d[276]
  PIN k_li_d[277]
    DIRECTION OUTPUT ;
    USE SIGNAL ;
    PORT
      LAYER M7 ;
        RECT  199.056 0 199.088 0.192 ;
    END
  END k_li_d[277]
  PIN k_li_d[278]
    DIRECTION OUTPUT ;
    USE SIGNAL ;
    PORT
      LAYER M7 ;
        RECT  199.76 0 199.792 0.192 ;
    END
  END k_li_d[278]
  PIN k_li_d[279]
    DIRECTION OUTPUT ;
    USE SIGNAL ;
    PORT
      LAYER M7 ;
        RECT  200.464 0 200.496 0.192 ;
    END
  END k_li_d[279]
  PIN k_li_d[27]
    DIRECTION OUTPUT ;
    USE SIGNAL ;
    PORT
      LAYER M7 ;
        RECT  22.48 0 22.512 0.192 ;
    END
  END k_li_d[27]
  PIN k_li_d[280]
    DIRECTION OUTPUT ;
    USE SIGNAL ;
    PORT
      LAYER M7 ;
        RECT  201.168 0 201.2 0.192 ;
    END
  END k_li_d[280]
  PIN k_li_d[281]
    DIRECTION OUTPUT ;
    USE SIGNAL ;
    PORT
      LAYER M7 ;
        RECT  201.872 0 201.904 0.192 ;
    END
  END k_li_d[281]
  PIN k_li_d[282]
    DIRECTION OUTPUT ;
    USE SIGNAL ;
    PORT
      LAYER M7 ;
        RECT  202.576 0 202.608 0.192 ;
    END
  END k_li_d[282]
  PIN k_li_d[283]
    DIRECTION OUTPUT ;
    USE SIGNAL ;
    PORT
      LAYER M7 ;
        RECT  203.28 0 203.312 0.192 ;
    END
  END k_li_d[283]
  PIN k_li_d[284]
    DIRECTION OUTPUT ;
    USE SIGNAL ;
    PORT
      LAYER M7 ;
        RECT  203.984 0 204.016 0.192 ;
    END
  END k_li_d[284]
  PIN k_li_d[285]
    DIRECTION OUTPUT ;
    USE SIGNAL ;
    PORT
      LAYER M7 ;
        RECT  204.688 0 204.72 0.192 ;
    END
  END k_li_d[285]
  PIN k_li_d[286]
    DIRECTION OUTPUT ;
    USE SIGNAL ;
    PORT
      LAYER M7 ;
        RECT  205.392 0 205.424 0.192 ;
    END
  END k_li_d[286]
  PIN k_li_d[287]
    DIRECTION OUTPUT ;
    USE SIGNAL ;
    PORT
      LAYER M7 ;
        RECT  206.096 0 206.128 0.192 ;
    END
  END k_li_d[287]
  PIN k_li_d[288]
    DIRECTION OUTPUT ;
    USE SIGNAL ;
    PORT
      LAYER M7 ;
        RECT  206.8 0 206.832 0.192 ;
    END
  END k_li_d[288]
  PIN k_li_d[289]
    DIRECTION OUTPUT ;
    USE SIGNAL ;
    PORT
      LAYER M7 ;
        RECT  207.504 0 207.536 0.192 ;
    END
  END k_li_d[289]
  PIN k_li_d[28]
    DIRECTION OUTPUT ;
    USE SIGNAL ;
    PORT
      LAYER M7 ;
        RECT  23.184 0 23.216 0.192 ;
    END
  END k_li_d[28]
  PIN k_li_d[290]
    DIRECTION OUTPUT ;
    USE SIGNAL ;
    PORT
      LAYER M7 ;
        RECT  208.208 0 208.24 0.192 ;
    END
  END k_li_d[290]
  PIN k_li_d[291]
    DIRECTION OUTPUT ;
    USE SIGNAL ;
    PORT
      LAYER M7 ;
        RECT  208.912 0 208.944 0.192 ;
    END
  END k_li_d[291]
  PIN k_li_d[292]
    DIRECTION OUTPUT ;
    USE SIGNAL ;
    PORT
      LAYER M7 ;
        RECT  209.616 0 209.648 0.192 ;
    END
  END k_li_d[292]
  PIN k_li_d[293]
    DIRECTION OUTPUT ;
    USE SIGNAL ;
    PORT
      LAYER M7 ;
        RECT  210.32 0 210.352 0.192 ;
    END
  END k_li_d[293]
  PIN k_li_d[294]
    DIRECTION OUTPUT ;
    USE SIGNAL ;
    PORT
      LAYER M7 ;
        RECT  211.024 0 211.056 0.192 ;
    END
  END k_li_d[294]
  PIN k_li_d[295]
    DIRECTION OUTPUT ;
    USE SIGNAL ;
    PORT
      LAYER M7 ;
        RECT  211.728 0 211.76 0.192 ;
    END
  END k_li_d[295]
  PIN k_li_d[296]
    DIRECTION OUTPUT ;
    USE SIGNAL ;
    PORT
      LAYER M7 ;
        RECT  212.432 0 212.464 0.192 ;
    END
  END k_li_d[296]
  PIN k_li_d[297]
    DIRECTION OUTPUT ;
    USE SIGNAL ;
    PORT
      LAYER M7 ;
        RECT  213.136 0 213.168 0.192 ;
    END
  END k_li_d[297]
  PIN k_li_d[298]
    DIRECTION OUTPUT ;
    USE SIGNAL ;
    PORT
      LAYER M7 ;
        RECT  213.84 0 213.872 0.192 ;
    END
  END k_li_d[298]
  PIN k_li_d[299]
    DIRECTION OUTPUT ;
    USE SIGNAL ;
    PORT
      LAYER M7 ;
        RECT  214.544 0 214.576 0.192 ;
    END
  END k_li_d[299]
  PIN k_li_d[29]
    DIRECTION OUTPUT ;
    USE SIGNAL ;
    PORT
      LAYER M7 ;
        RECT  23.888 0 23.92 0.192 ;
    END
  END k_li_d[29]
  PIN k_li_d[2]
    DIRECTION OUTPUT ;
    USE SIGNAL ;
    PORT
      LAYER M7 ;
        RECT  4.816 0 4.848 0.192 ;
    END
  END k_li_d[2]
  PIN k_li_d[300]
    DIRECTION OUTPUT ;
    USE SIGNAL ;
    PORT
      LAYER M7 ;
        RECT  215.248 0 215.28 0.192 ;
    END
  END k_li_d[300]
  PIN k_li_d[301]
    DIRECTION OUTPUT ;
    USE SIGNAL ;
    PORT
      LAYER M7 ;
        RECT  215.952 0 215.984 0.192 ;
    END
  END k_li_d[301]
  PIN k_li_d[302]
    DIRECTION OUTPUT ;
    USE SIGNAL ;
    PORT
      LAYER M7 ;
        RECT  216.656 0 216.688 0.192 ;
    END
  END k_li_d[302]
  PIN k_li_d[303]
    DIRECTION OUTPUT ;
    USE SIGNAL ;
    PORT
      LAYER M7 ;
        RECT  217.36 0 217.392 0.192 ;
    END
  END k_li_d[303]
  PIN k_li_d[304]
    DIRECTION OUTPUT ;
    USE SIGNAL ;
    PORT
      LAYER M7 ;
        RECT  218.064 0 218.096 0.192 ;
    END
  END k_li_d[304]
  PIN k_li_d[305]
    DIRECTION OUTPUT ;
    USE SIGNAL ;
    PORT
      LAYER M7 ;
        RECT  218.832 0 218.864 0.192 ;
    END
  END k_li_d[305]
  PIN k_li_d[306]
    DIRECTION OUTPUT ;
    USE SIGNAL ;
    PORT
      LAYER M7 ;
        RECT  219.536 0 219.568 0.192 ;
    END
  END k_li_d[306]
  PIN k_li_d[307]
    DIRECTION OUTPUT ;
    USE SIGNAL ;
    PORT
      LAYER M7 ;
        RECT  220.24 0 220.272 0.192 ;
    END
  END k_li_d[307]
  PIN k_li_d[308]
    DIRECTION OUTPUT ;
    USE SIGNAL ;
    PORT
      LAYER M7 ;
        RECT  220.944 0 220.976 0.192 ;
    END
  END k_li_d[308]
  PIN k_li_d[309]
    DIRECTION OUTPUT ;
    USE SIGNAL ;
    PORT
      LAYER M7 ;
        RECT  221.648 0 221.68 0.192 ;
    END
  END k_li_d[309]
  PIN k_li_d[30]
    DIRECTION OUTPUT ;
    USE SIGNAL ;
    PORT
      LAYER M7 ;
        RECT  24.592 0 24.624 0.192 ;
    END
  END k_li_d[30]
  PIN k_li_d[310]
    DIRECTION OUTPUT ;
    USE SIGNAL ;
    PORT
      LAYER M7 ;
        RECT  222.352 0 222.384 0.192 ;
    END
  END k_li_d[310]
  PIN k_li_d[311]
    DIRECTION OUTPUT ;
    USE SIGNAL ;
    PORT
      LAYER M7 ;
        RECT  223.056 0 223.088 0.192 ;
    END
  END k_li_d[311]
  PIN k_li_d[312]
    DIRECTION OUTPUT ;
    USE SIGNAL ;
    PORT
      LAYER M7 ;
        RECT  223.76 0 223.792 0.192 ;
    END
  END k_li_d[312]
  PIN k_li_d[313]
    DIRECTION OUTPUT ;
    USE SIGNAL ;
    PORT
      LAYER M7 ;
        RECT  224.464 0 224.496 0.192 ;
    END
  END k_li_d[313]
  PIN k_li_d[314]
    DIRECTION OUTPUT ;
    USE SIGNAL ;
    PORT
      LAYER M7 ;
        RECT  225.168 0 225.2 0.192 ;
    END
  END k_li_d[314]
  PIN k_li_d[315]
    DIRECTION OUTPUT ;
    USE SIGNAL ;
    PORT
      LAYER M7 ;
        RECT  225.872 0 225.904 0.192 ;
    END
  END k_li_d[315]
  PIN k_li_d[316]
    DIRECTION OUTPUT ;
    USE SIGNAL ;
    PORT
      LAYER M7 ;
        RECT  226.576 0 226.608 0.192 ;
    END
  END k_li_d[316]
  PIN k_li_d[317]
    DIRECTION OUTPUT ;
    USE SIGNAL ;
    PORT
      LAYER M7 ;
        RECT  227.28 0 227.312 0.192 ;
    END
  END k_li_d[317]
  PIN k_li_d[318]
    DIRECTION OUTPUT ;
    USE SIGNAL ;
    PORT
      LAYER M7 ;
        RECT  227.984 0 228.016 0.192 ;
    END
  END k_li_d[318]
  PIN k_li_d[319]
    DIRECTION OUTPUT ;
    USE SIGNAL ;
    PORT
      LAYER M7 ;
        RECT  228.688 0 228.72 0.192 ;
    END
  END k_li_d[319]
  PIN k_li_d[31]
    DIRECTION OUTPUT ;
    USE SIGNAL ;
    PORT
      LAYER M7 ;
        RECT  25.296 0 25.328 0.192 ;
    END
  END k_li_d[31]
  PIN k_li_d[320]
    DIRECTION OUTPUT ;
    USE SIGNAL ;
    PORT
      LAYER M7 ;
        RECT  229.392 0 229.424 0.192 ;
    END
  END k_li_d[320]
  PIN k_li_d[321]
    DIRECTION OUTPUT ;
    USE SIGNAL ;
    PORT
      LAYER M7 ;
        RECT  230.096 0 230.128 0.192 ;
    END
  END k_li_d[321]
  PIN k_li_d[322]
    DIRECTION OUTPUT ;
    USE SIGNAL ;
    PORT
      LAYER M7 ;
        RECT  230.8 0 230.832 0.192 ;
    END
  END k_li_d[322]
  PIN k_li_d[323]
    DIRECTION OUTPUT ;
    USE SIGNAL ;
    PORT
      LAYER M7 ;
        RECT  231.504 0 231.536 0.192 ;
    END
  END k_li_d[323]
  PIN k_li_d[324]
    DIRECTION OUTPUT ;
    USE SIGNAL ;
    PORT
      LAYER M7 ;
        RECT  232.208 0 232.24 0.192 ;
    END
  END k_li_d[324]
  PIN k_li_d[325]
    DIRECTION OUTPUT ;
    USE SIGNAL ;
    PORT
      LAYER M7 ;
        RECT  232.912 0 232.944 0.192 ;
    END
  END k_li_d[325]
  PIN k_li_d[326]
    DIRECTION OUTPUT ;
    USE SIGNAL ;
    PORT
      LAYER M7 ;
        RECT  233.616 0 233.648 0.192 ;
    END
  END k_li_d[326]
  PIN k_li_d[327]
    DIRECTION OUTPUT ;
    USE SIGNAL ;
    PORT
      LAYER M7 ;
        RECT  234.32 0 234.352 0.192 ;
    END
  END k_li_d[327]
  PIN k_li_d[328]
    DIRECTION OUTPUT ;
    USE SIGNAL ;
    PORT
      LAYER M7 ;
        RECT  235.024 0 235.056 0.192 ;
    END
  END k_li_d[328]
  PIN k_li_d[329]
    DIRECTION OUTPUT ;
    USE SIGNAL ;
    PORT
      LAYER M7 ;
        RECT  235.728 0 235.76 0.192 ;
    END
  END k_li_d[329]
  PIN k_li_d[32]
    DIRECTION OUTPUT ;
    USE SIGNAL ;
    PORT
      LAYER M7 ;
        RECT  26 0 26.032 0.192 ;
    END
  END k_li_d[32]
  PIN k_li_d[330]
    DIRECTION OUTPUT ;
    USE SIGNAL ;
    PORT
      LAYER M7 ;
        RECT  236.432 0 236.464 0.192 ;
    END
  END k_li_d[330]
  PIN k_li_d[331]
    DIRECTION OUTPUT ;
    USE SIGNAL ;
    PORT
      LAYER M7 ;
        RECT  237.136 0 237.168 0.192 ;
    END
  END k_li_d[331]
  PIN k_li_d[332]
    DIRECTION OUTPUT ;
    USE SIGNAL ;
    PORT
      LAYER M7 ;
        RECT  237.84 0 237.872 0.192 ;
    END
  END k_li_d[332]
  PIN k_li_d[333]
    DIRECTION OUTPUT ;
    USE SIGNAL ;
    PORT
      LAYER M7 ;
        RECT  238.608 0 238.64 0.192 ;
    END
  END k_li_d[333]
  PIN k_li_d[334]
    DIRECTION OUTPUT ;
    USE SIGNAL ;
    PORT
      LAYER M7 ;
        RECT  239.312 0 239.344 0.192 ;
    END
  END k_li_d[334]
  PIN k_li_d[335]
    DIRECTION OUTPUT ;
    USE SIGNAL ;
    PORT
      LAYER M7 ;
        RECT  240.016 0 240.048 0.192 ;
    END
  END k_li_d[335]
  PIN k_li_d[336]
    DIRECTION OUTPUT ;
    USE SIGNAL ;
    PORT
      LAYER M7 ;
        RECT  240.72 0 240.752 0.192 ;
    END
  END k_li_d[336]
  PIN k_li_d[337]
    DIRECTION OUTPUT ;
    USE SIGNAL ;
    PORT
      LAYER M7 ;
        RECT  241.424 0 241.456 0.192 ;
    END
  END k_li_d[337]
  PIN k_li_d[338]
    DIRECTION OUTPUT ;
    USE SIGNAL ;
    PORT
      LAYER M7 ;
        RECT  242.128 0 242.16 0.192 ;
    END
  END k_li_d[338]
  PIN k_li_d[339]
    DIRECTION OUTPUT ;
    USE SIGNAL ;
    PORT
      LAYER M7 ;
        RECT  242.832 0 242.864 0.192 ;
    END
  END k_li_d[339]
  PIN k_li_d[33]
    DIRECTION OUTPUT ;
    USE SIGNAL ;
    PORT
      LAYER M7 ;
        RECT  26.704 0 26.736 0.192 ;
    END
  END k_li_d[33]
  PIN k_li_d[340]
    DIRECTION OUTPUT ;
    USE SIGNAL ;
    PORT
      LAYER M7 ;
        RECT  243.536 0 243.568 0.192 ;
    END
  END k_li_d[340]
  PIN k_li_d[341]
    DIRECTION OUTPUT ;
    USE SIGNAL ;
    PORT
      LAYER M7 ;
        RECT  244.24 0 244.272 0.192 ;
    END
  END k_li_d[341]
  PIN k_li_d[342]
    DIRECTION OUTPUT ;
    USE SIGNAL ;
    PORT
      LAYER M7 ;
        RECT  244.944 0 244.976 0.192 ;
    END
  END k_li_d[342]
  PIN k_li_d[343]
    DIRECTION OUTPUT ;
    USE SIGNAL ;
    PORT
      LAYER M7 ;
        RECT  245.648 0 245.68 0.192 ;
    END
  END k_li_d[343]
  PIN k_li_d[344]
    DIRECTION OUTPUT ;
    USE SIGNAL ;
    PORT
      LAYER M7 ;
        RECT  246.352 0 246.384 0.192 ;
    END
  END k_li_d[344]
  PIN k_li_d[345]
    DIRECTION OUTPUT ;
    USE SIGNAL ;
    PORT
      LAYER M7 ;
        RECT  247.056 0 247.088 0.192 ;
    END
  END k_li_d[345]
  PIN k_li_d[346]
    DIRECTION OUTPUT ;
    USE SIGNAL ;
    PORT
      LAYER M7 ;
        RECT  247.76 0 247.792 0.192 ;
    END
  END k_li_d[346]
  PIN k_li_d[347]
    DIRECTION OUTPUT ;
    USE SIGNAL ;
    PORT
      LAYER M7 ;
        RECT  248.464 0 248.496 0.192 ;
    END
  END k_li_d[347]
  PIN k_li_d[348]
    DIRECTION OUTPUT ;
    USE SIGNAL ;
    PORT
      LAYER M7 ;
        RECT  249.168 0 249.2 0.192 ;
    END
  END k_li_d[348]
  PIN k_li_d[349]
    DIRECTION OUTPUT ;
    USE SIGNAL ;
    PORT
      LAYER M7 ;
        RECT  249.872 0 249.904 0.192 ;
    END
  END k_li_d[349]
  PIN k_li_d[34]
    DIRECTION OUTPUT ;
    USE SIGNAL ;
    PORT
      LAYER M7 ;
        RECT  27.408 0 27.44 0.192 ;
    END
  END k_li_d[34]
  PIN k_li_d[350]
    DIRECTION OUTPUT ;
    USE SIGNAL ;
    PORT
      LAYER M7 ;
        RECT  250.576 0 250.608 0.192 ;
    END
  END k_li_d[350]
  PIN k_li_d[351]
    DIRECTION OUTPUT ;
    USE SIGNAL ;
    PORT
      LAYER M7 ;
        RECT  251.28 0 251.312 0.192 ;
    END
  END k_li_d[351]
  PIN k_li_d[352]
    DIRECTION OUTPUT ;
    USE SIGNAL ;
    PORT
      LAYER M7 ;
        RECT  251.984 0 252.016 0.192 ;
    END
  END k_li_d[352]
  PIN k_li_d[353]
    DIRECTION OUTPUT ;
    USE SIGNAL ;
    PORT
      LAYER M7 ;
        RECT  252.688 0 252.72 0.192 ;
    END
  END k_li_d[353]
  PIN k_li_d[354]
    DIRECTION OUTPUT ;
    USE SIGNAL ;
    PORT
      LAYER M7 ;
        RECT  253.392 0 253.424 0.192 ;
    END
  END k_li_d[354]
  PIN k_li_d[355]
    DIRECTION OUTPUT ;
    USE SIGNAL ;
    PORT
      LAYER M7 ;
        RECT  254.096 0 254.128 0.192 ;
    END
  END k_li_d[355]
  PIN k_li_d[356]
    DIRECTION OUTPUT ;
    USE SIGNAL ;
    PORT
      LAYER M7 ;
        RECT  254.8 0 254.832 0.192 ;
    END
  END k_li_d[356]
  PIN k_li_d[357]
    DIRECTION OUTPUT ;
    USE SIGNAL ;
    PORT
      LAYER M7 ;
        RECT  255.504 0 255.536 0.192 ;
    END
  END k_li_d[357]
  PIN k_li_d[358]
    DIRECTION OUTPUT ;
    USE SIGNAL ;
    PORT
      LAYER M7 ;
        RECT  256.208 0 256.24 0.192 ;
    END
  END k_li_d[358]
  PIN k_li_d[359]
    DIRECTION OUTPUT ;
    USE SIGNAL ;
    PORT
      LAYER M7 ;
        RECT  256.912 0 256.944 0.192 ;
    END
  END k_li_d[359]
  PIN k_li_d[35]
    DIRECTION OUTPUT ;
    USE SIGNAL ;
    PORT
      LAYER M7 ;
        RECT  28.112 0 28.144 0.192 ;
    END
  END k_li_d[35]
  PIN k_li_d[360]
    DIRECTION OUTPUT ;
    USE SIGNAL ;
    PORT
      LAYER M7 ;
        RECT  257.616 0 257.648 0.192 ;
    END
  END k_li_d[360]
  PIN k_li_d[361]
    DIRECTION OUTPUT ;
    USE SIGNAL ;
    PORT
      LAYER M7 ;
        RECT  258.384 0 258.416 0.192 ;
    END
  END k_li_d[361]
  PIN k_li_d[362]
    DIRECTION OUTPUT ;
    USE SIGNAL ;
    PORT
      LAYER M7 ;
        RECT  259.088 0 259.12 0.192 ;
    END
  END k_li_d[362]
  PIN k_li_d[363]
    DIRECTION OUTPUT ;
    USE SIGNAL ;
    PORT
      LAYER M7 ;
        RECT  259.792 0 259.824 0.192 ;
    END
  END k_li_d[363]
  PIN k_li_d[364]
    DIRECTION OUTPUT ;
    USE SIGNAL ;
    PORT
      LAYER M7 ;
        RECT  260.496 0 260.528 0.192 ;
    END
  END k_li_d[364]
  PIN k_li_d[365]
    DIRECTION OUTPUT ;
    USE SIGNAL ;
    PORT
      LAYER M7 ;
        RECT  261.2 0 261.232 0.192 ;
    END
  END k_li_d[365]
  PIN k_li_d[366]
    DIRECTION OUTPUT ;
    USE SIGNAL ;
    PORT
      LAYER M7 ;
        RECT  261.904 0 261.936 0.192 ;
    END
  END k_li_d[366]
  PIN k_li_d[367]
    DIRECTION OUTPUT ;
    USE SIGNAL ;
    PORT
      LAYER M7 ;
        RECT  262.608 0 262.64 0.192 ;
    END
  END k_li_d[367]
  PIN k_li_d[368]
    DIRECTION OUTPUT ;
    USE SIGNAL ;
    PORT
      LAYER M7 ;
        RECT  263.312 0 263.344 0.192 ;
    END
  END k_li_d[368]
  PIN k_li_d[369]
    DIRECTION OUTPUT ;
    USE SIGNAL ;
    PORT
      LAYER M7 ;
        RECT  264.016 0 264.048 0.192 ;
    END
  END k_li_d[369]
  PIN k_li_d[36]
    DIRECTION OUTPUT ;
    USE SIGNAL ;
    PORT
      LAYER M7 ;
        RECT  28.816 0 28.848 0.192 ;
    END
  END k_li_d[36]
  PIN k_li_d[370]
    DIRECTION OUTPUT ;
    USE SIGNAL ;
    PORT
      LAYER M7 ;
        RECT  264.72 0 264.752 0.192 ;
    END
  END k_li_d[370]
  PIN k_li_d[371]
    DIRECTION OUTPUT ;
    USE SIGNAL ;
    PORT
      LAYER M7 ;
        RECT  265.424 0 265.456 0.192 ;
    END
  END k_li_d[371]
  PIN k_li_d[372]
    DIRECTION OUTPUT ;
    USE SIGNAL ;
    PORT
      LAYER M7 ;
        RECT  266.128 0 266.16 0.192 ;
    END
  END k_li_d[372]
  PIN k_li_d[373]
    DIRECTION OUTPUT ;
    USE SIGNAL ;
    PORT
      LAYER M7 ;
        RECT  266.832 0 266.864 0.192 ;
    END
  END k_li_d[373]
  PIN k_li_d[374]
    DIRECTION OUTPUT ;
    USE SIGNAL ;
    PORT
      LAYER M7 ;
        RECT  267.536 0 267.568 0.192 ;
    END
  END k_li_d[374]
  PIN k_li_d[375]
    DIRECTION OUTPUT ;
    USE SIGNAL ;
    PORT
      LAYER M7 ;
        RECT  268.24 0 268.272 0.192 ;
    END
  END k_li_d[375]
  PIN k_li_d[376]
    DIRECTION OUTPUT ;
    USE SIGNAL ;
    PORT
      LAYER M7 ;
        RECT  268.944 0 268.976 0.192 ;
    END
  END k_li_d[376]
  PIN k_li_d[377]
    DIRECTION OUTPUT ;
    USE SIGNAL ;
    PORT
      LAYER M7 ;
        RECT  269.648 0 269.68 0.192 ;
    END
  END k_li_d[377]
  PIN k_li_d[378]
    DIRECTION OUTPUT ;
    USE SIGNAL ;
    PORT
      LAYER M7 ;
        RECT  270.352 0 270.384 0.192 ;
    END
  END k_li_d[378]
  PIN k_li_d[379]
    DIRECTION OUTPUT ;
    USE SIGNAL ;
    PORT
      LAYER M7 ;
        RECT  271.056 0 271.088 0.192 ;
    END
  END k_li_d[379]
  PIN k_li_d[37]
    DIRECTION OUTPUT ;
    USE SIGNAL ;
    PORT
      LAYER M7 ;
        RECT  29.52 0 29.552 0.192 ;
    END
  END k_li_d[37]
  PIN k_li_d[380]
    DIRECTION OUTPUT ;
    USE SIGNAL ;
    PORT
      LAYER M7 ;
        RECT  271.76 0 271.792 0.192 ;
    END
  END k_li_d[380]
  PIN k_li_d[381]
    DIRECTION OUTPUT ;
    USE SIGNAL ;
    PORT
      LAYER M7 ;
        RECT  272.464 0 272.496 0.192 ;
    END
  END k_li_d[381]
  PIN k_li_d[382]
    DIRECTION OUTPUT ;
    USE SIGNAL ;
    PORT
      LAYER M7 ;
        RECT  273.168 0 273.2 0.192 ;
    END
  END k_li_d[382]
  PIN k_li_d[383]
    DIRECTION OUTPUT ;
    USE SIGNAL ;
    PORT
      LAYER M7 ;
        RECT  273.872 0 273.904 0.192 ;
    END
  END k_li_d[383]
  PIN k_li_d[384]
    DIRECTION OUTPUT ;
    USE SIGNAL ;
    PORT
      LAYER M7 ;
        RECT  274.576 0 274.608 0.192 ;
    END
  END k_li_d[384]
  PIN k_li_d[385]
    DIRECTION OUTPUT ;
    USE SIGNAL ;
    PORT
      LAYER M7 ;
        RECT  275.28 0 275.312 0.192 ;
    END
  END k_li_d[385]
  PIN k_li_d[386]
    DIRECTION OUTPUT ;
    USE SIGNAL ;
    PORT
      LAYER M7 ;
        RECT  275.984 0 276.016 0.192 ;
    END
  END k_li_d[386]
  PIN k_li_d[387]
    DIRECTION OUTPUT ;
    USE SIGNAL ;
    PORT
      LAYER M7 ;
        RECT  276.688 0 276.72 0.192 ;
    END
  END k_li_d[387]
  PIN k_li_d[388]
    DIRECTION OUTPUT ;
    USE SIGNAL ;
    PORT
      LAYER M7 ;
        RECT  277.456 0 277.488 0.192 ;
    END
  END k_li_d[388]
  PIN k_li_d[389]
    DIRECTION OUTPUT ;
    USE SIGNAL ;
    PORT
      LAYER M7 ;
        RECT  278.16 0 278.192 0.192 ;
    END
  END k_li_d[389]
  PIN k_li_d[38]
    DIRECTION OUTPUT ;
    USE SIGNAL ;
    PORT
      LAYER M7 ;
        RECT  30.224 0 30.256 0.192 ;
    END
  END k_li_d[38]
  PIN k_li_d[390]
    DIRECTION OUTPUT ;
    USE SIGNAL ;
    PORT
      LAYER M7 ;
        RECT  278.864 0 278.896 0.192 ;
    END
  END k_li_d[390]
  PIN k_li_d[391]
    DIRECTION OUTPUT ;
    USE SIGNAL ;
    PORT
      LAYER M7 ;
        RECT  279.568 0 279.6 0.192 ;
    END
  END k_li_d[391]
  PIN k_li_d[392]
    DIRECTION OUTPUT ;
    USE SIGNAL ;
    PORT
      LAYER M7 ;
        RECT  280.272 0 280.304 0.192 ;
    END
  END k_li_d[392]
  PIN k_li_d[393]
    DIRECTION OUTPUT ;
    USE SIGNAL ;
    PORT
      LAYER M7 ;
        RECT  280.976 0 281.008 0.192 ;
    END
  END k_li_d[393]
  PIN k_li_d[394]
    DIRECTION OUTPUT ;
    USE SIGNAL ;
    PORT
      LAYER M7 ;
        RECT  281.68 0 281.712 0.192 ;
    END
  END k_li_d[394]
  PIN k_li_d[395]
    DIRECTION OUTPUT ;
    USE SIGNAL ;
    PORT
      LAYER M7 ;
        RECT  282.384 0 282.416 0.192 ;
    END
  END k_li_d[395]
  PIN k_li_d[396]
    DIRECTION OUTPUT ;
    USE SIGNAL ;
    PORT
      LAYER M7 ;
        RECT  283.088 0 283.12 0.192 ;
    END
  END k_li_d[396]
  PIN k_li_d[397]
    DIRECTION OUTPUT ;
    USE SIGNAL ;
    PORT
      LAYER M7 ;
        RECT  283.792 0 283.824 0.192 ;
    END
  END k_li_d[397]
  PIN k_li_d[398]
    DIRECTION OUTPUT ;
    USE SIGNAL ;
    PORT
      LAYER M7 ;
        RECT  284.496 0 284.528 0.192 ;
    END
  END k_li_d[398]
  PIN k_li_d[399]
    DIRECTION OUTPUT ;
    USE SIGNAL ;
    PORT
      LAYER M7 ;
        RECT  285.2 0 285.232 0.192 ;
    END
  END k_li_d[399]
  PIN k_li_d[39]
    DIRECTION OUTPUT ;
    USE SIGNAL ;
    PORT
      LAYER M7 ;
        RECT  30.928 0 30.96 0.192 ;
    END
  END k_li_d[39]
  PIN k_li_d[3]
    DIRECTION OUTPUT ;
    USE SIGNAL ;
    PORT
      LAYER M7 ;
        RECT  5.52 0 5.552 0.192 ;
    END
  END k_li_d[3]
  PIN k_li_d[400]
    DIRECTION OUTPUT ;
    USE SIGNAL ;
    PORT
      LAYER M7 ;
        RECT  285.904 0 285.936 0.192 ;
    END
  END k_li_d[400]
  PIN k_li_d[401]
    DIRECTION OUTPUT ;
    USE SIGNAL ;
    PORT
      LAYER M7 ;
        RECT  286.608 0 286.64 0.192 ;
    END
  END k_li_d[401]
  PIN k_li_d[402]
    DIRECTION OUTPUT ;
    USE SIGNAL ;
    PORT
      LAYER M7 ;
        RECT  287.312 0 287.344 0.192 ;
    END
  END k_li_d[402]
  PIN k_li_d[403]
    DIRECTION OUTPUT ;
    USE SIGNAL ;
    PORT
      LAYER M7 ;
        RECT  288.016 0 288.048 0.192 ;
    END
  END k_li_d[403]
  PIN k_li_d[404]
    DIRECTION OUTPUT ;
    USE SIGNAL ;
    PORT
      LAYER M7 ;
        RECT  288.72 0 288.752 0.192 ;
    END
  END k_li_d[404]
  PIN k_li_d[405]
    DIRECTION OUTPUT ;
    USE SIGNAL ;
    PORT
      LAYER M7 ;
        RECT  289.424 0 289.456 0.192 ;
    END
  END k_li_d[405]
  PIN k_li_d[406]
    DIRECTION OUTPUT ;
    USE SIGNAL ;
    PORT
      LAYER M7 ;
        RECT  290.128 0 290.16 0.192 ;
    END
  END k_li_d[406]
  PIN k_li_d[407]
    DIRECTION OUTPUT ;
    USE SIGNAL ;
    PORT
      LAYER M7 ;
        RECT  290.832 0 290.864 0.192 ;
    END
  END k_li_d[407]
  PIN k_li_d[408]
    DIRECTION OUTPUT ;
    USE SIGNAL ;
    PORT
      LAYER M7 ;
        RECT  291.536 0 291.568 0.192 ;
    END
  END k_li_d[408]
  PIN k_li_d[409]
    DIRECTION OUTPUT ;
    USE SIGNAL ;
    PORT
      LAYER M7 ;
        RECT  292.24 0 292.272 0.192 ;
    END
  END k_li_d[409]
  PIN k_li_d[40]
    DIRECTION OUTPUT ;
    USE SIGNAL ;
    PORT
      LAYER M7 ;
        RECT  31.632 0 31.664 0.192 ;
    END
  END k_li_d[40]
  PIN k_li_d[410]
    DIRECTION OUTPUT ;
    USE SIGNAL ;
    PORT
      LAYER M7 ;
        RECT  292.944 0 292.976 0.192 ;
    END
  END k_li_d[410]
  PIN k_li_d[411]
    DIRECTION OUTPUT ;
    USE SIGNAL ;
    PORT
      LAYER M7 ;
        RECT  293.648 0 293.68 0.192 ;
    END
  END k_li_d[411]
  PIN k_li_d[412]
    DIRECTION OUTPUT ;
    USE SIGNAL ;
    PORT
      LAYER M7 ;
        RECT  294.352 0 294.384 0.192 ;
    END
  END k_li_d[412]
  PIN k_li_d[413]
    DIRECTION OUTPUT ;
    USE SIGNAL ;
    PORT
      LAYER M7 ;
        RECT  295.056 0 295.088 0.192 ;
    END
  END k_li_d[413]
  PIN k_li_d[414]
    DIRECTION OUTPUT ;
    USE SIGNAL ;
    PORT
      LAYER M7 ;
        RECT  295.76 0 295.792 0.192 ;
    END
  END k_li_d[414]
  PIN k_li_d[415]
    DIRECTION OUTPUT ;
    USE SIGNAL ;
    PORT
      LAYER M7 ;
        RECT  296.464 0 296.496 0.192 ;
    END
  END k_li_d[415]
  PIN k_li_d[416]
    DIRECTION OUTPUT ;
    USE SIGNAL ;
    PORT
      LAYER M7 ;
        RECT  297.232 0 297.264 0.192 ;
    END
  END k_li_d[416]
  PIN k_li_d[417]
    DIRECTION OUTPUT ;
    USE SIGNAL ;
    PORT
      LAYER M7 ;
        RECT  297.936 0 297.968 0.192 ;
    END
  END k_li_d[417]
  PIN k_li_d[418]
    DIRECTION OUTPUT ;
    USE SIGNAL ;
    PORT
      LAYER M7 ;
        RECT  298.64 0 298.672 0.192 ;
    END
  END k_li_d[418]
  PIN k_li_d[419]
    DIRECTION OUTPUT ;
    USE SIGNAL ;
    PORT
      LAYER M7 ;
        RECT  299.344 0 299.376 0.192 ;
    END
  END k_li_d[419]
  PIN k_li_d[41]
    DIRECTION OUTPUT ;
    USE SIGNAL ;
    PORT
      LAYER M7 ;
        RECT  32.336 0 32.368 0.192 ;
    END
  END k_li_d[41]
  PIN k_li_d[420]
    DIRECTION OUTPUT ;
    USE SIGNAL ;
    PORT
      LAYER M7 ;
        RECT  300.048 0 300.08 0.192 ;
    END
  END k_li_d[420]
  PIN k_li_d[421]
    DIRECTION OUTPUT ;
    USE SIGNAL ;
    PORT
      LAYER M7 ;
        RECT  300.752 0 300.784 0.192 ;
    END
  END k_li_d[421]
  PIN k_li_d[422]
    DIRECTION OUTPUT ;
    USE SIGNAL ;
    PORT
      LAYER M7 ;
        RECT  301.456 0 301.488 0.192 ;
    END
  END k_li_d[422]
  PIN k_li_d[423]
    DIRECTION OUTPUT ;
    USE SIGNAL ;
    PORT
      LAYER M7 ;
        RECT  302.16 0 302.192 0.192 ;
    END
  END k_li_d[423]
  PIN k_li_d[424]
    DIRECTION OUTPUT ;
    USE SIGNAL ;
    PORT
      LAYER M7 ;
        RECT  302.864 0 302.896 0.192 ;
    END
  END k_li_d[424]
  PIN k_li_d[425]
    DIRECTION OUTPUT ;
    USE SIGNAL ;
    PORT
      LAYER M7 ;
        RECT  303.568 0 303.6 0.192 ;
    END
  END k_li_d[425]
  PIN k_li_d[426]
    DIRECTION OUTPUT ;
    USE SIGNAL ;
    PORT
      LAYER M7 ;
        RECT  304.272 0 304.304 0.192 ;
    END
  END k_li_d[426]
  PIN k_li_d[427]
    DIRECTION OUTPUT ;
    USE SIGNAL ;
    PORT
      LAYER M7 ;
        RECT  304.976 0 305.008 0.192 ;
    END
  END k_li_d[427]
  PIN k_li_d[428]
    DIRECTION OUTPUT ;
    USE SIGNAL ;
    PORT
      LAYER M7 ;
        RECT  305.68 0 305.712 0.192 ;
    END
  END k_li_d[428]
  PIN k_li_d[429]
    DIRECTION OUTPUT ;
    USE SIGNAL ;
    PORT
      LAYER M7 ;
        RECT  306.384 0 306.416 0.192 ;
    END
  END k_li_d[429]
  PIN k_li_d[42]
    DIRECTION OUTPUT ;
    USE SIGNAL ;
    PORT
      LAYER M7 ;
        RECT  33.04 0 33.072 0.192 ;
    END
  END k_li_d[42]
  PIN k_li_d[430]
    DIRECTION OUTPUT ;
    USE SIGNAL ;
    PORT
      LAYER M7 ;
        RECT  307.088 0 307.12 0.192 ;
    END
  END k_li_d[430]
  PIN k_li_d[431]
    DIRECTION OUTPUT ;
    USE SIGNAL ;
    PORT
      LAYER M7 ;
        RECT  307.792 0 307.824 0.192 ;
    END
  END k_li_d[431]
  PIN k_li_d[432]
    DIRECTION OUTPUT ;
    USE SIGNAL ;
    PORT
      LAYER M7 ;
        RECT  308.496 0 308.528 0.192 ;
    END
  END k_li_d[432]
  PIN k_li_d[433]
    DIRECTION OUTPUT ;
    USE SIGNAL ;
    PORT
      LAYER M7 ;
        RECT  309.2 0 309.232 0.192 ;
    END
  END k_li_d[433]
  PIN k_li_d[434]
    DIRECTION OUTPUT ;
    USE SIGNAL ;
    PORT
      LAYER M7 ;
        RECT  309.904 0 309.936 0.192 ;
    END
  END k_li_d[434]
  PIN k_li_d[435]
    DIRECTION OUTPUT ;
    USE SIGNAL ;
    PORT
      LAYER M7 ;
        RECT  310.608 0 310.64 0.192 ;
    END
  END k_li_d[435]
  PIN k_li_d[436]
    DIRECTION OUTPUT ;
    USE SIGNAL ;
    PORT
      LAYER M7 ;
        RECT  311.312 0 311.344 0.192 ;
    END
  END k_li_d[436]
  PIN k_li_d[437]
    DIRECTION OUTPUT ;
    USE SIGNAL ;
    PORT
      LAYER M7 ;
        RECT  312.016 0 312.048 0.192 ;
    END
  END k_li_d[437]
  PIN k_li_d[438]
    DIRECTION OUTPUT ;
    USE SIGNAL ;
    PORT
      LAYER M7 ;
        RECT  312.72 0 312.752 0.192 ;
    END
  END k_li_d[438]
  PIN k_li_d[439]
    DIRECTION OUTPUT ;
    USE SIGNAL ;
    PORT
      LAYER M7 ;
        RECT  313.424 0 313.456 0.192 ;
    END
  END k_li_d[439]
  PIN k_li_d[43]
    DIRECTION OUTPUT ;
    USE SIGNAL ;
    PORT
      LAYER M7 ;
        RECT  33.744 0 33.776 0.192 ;
    END
  END k_li_d[43]
  PIN k_li_d[440]
    DIRECTION OUTPUT ;
    USE SIGNAL ;
    PORT
      LAYER M7 ;
        RECT  314.128 0 314.16 0.192 ;
    END
  END k_li_d[440]
  PIN k_li_d[441]
    DIRECTION OUTPUT ;
    USE SIGNAL ;
    PORT
      LAYER M7 ;
        RECT  314.832 0 314.864 0.192 ;
    END
  END k_li_d[441]
  PIN k_li_d[442]
    DIRECTION OUTPUT ;
    USE SIGNAL ;
    PORT
      LAYER M7 ;
        RECT  315.536 0 315.568 0.192 ;
    END
  END k_li_d[442]
  PIN k_li_d[443]
    DIRECTION OUTPUT ;
    USE SIGNAL ;
    PORT
      LAYER M7 ;
        RECT  316.24 0 316.272 0.192 ;
    END
  END k_li_d[443]
  PIN k_li_d[444]
    DIRECTION OUTPUT ;
    USE SIGNAL ;
    PORT
      LAYER M7 ;
        RECT  317.008 0 317.04 0.192 ;
    END
  END k_li_d[444]
  PIN k_li_d[445]
    DIRECTION OUTPUT ;
    USE SIGNAL ;
    PORT
      LAYER M7 ;
        RECT  317.712 0 317.744 0.192 ;
    END
  END k_li_d[445]
  PIN k_li_d[446]
    DIRECTION OUTPUT ;
    USE SIGNAL ;
    PORT
      LAYER M7 ;
        RECT  318.416 0 318.448 0.192 ;
    END
  END k_li_d[446]
  PIN k_li_d[447]
    DIRECTION OUTPUT ;
    USE SIGNAL ;
    PORT
      LAYER M7 ;
        RECT  319.12 0 319.152 0.192 ;
    END
  END k_li_d[447]
  PIN k_li_d[448]
    DIRECTION OUTPUT ;
    USE SIGNAL ;
    PORT
      LAYER M7 ;
        RECT  319.824 0 319.856 0.192 ;
    END
  END k_li_d[448]
  PIN k_li_d[449]
    DIRECTION OUTPUT ;
    USE SIGNAL ;
    PORT
      LAYER M7 ;
        RECT  320.528 0 320.56 0.192 ;
    END
  END k_li_d[449]
  PIN k_li_d[44]
    DIRECTION OUTPUT ;
    USE SIGNAL ;
    PORT
      LAYER M7 ;
        RECT  34.448 0 34.48 0.192 ;
    END
  END k_li_d[44]
  PIN k_li_d[450]
    DIRECTION OUTPUT ;
    USE SIGNAL ;
    PORT
      LAYER M7 ;
        RECT  321.232 0 321.264 0.192 ;
    END
  END k_li_d[450]
  PIN k_li_d[451]
    DIRECTION OUTPUT ;
    USE SIGNAL ;
    PORT
      LAYER M7 ;
        RECT  321.936 0 321.968 0.192 ;
    END
  END k_li_d[451]
  PIN k_li_d[452]
    DIRECTION OUTPUT ;
    USE SIGNAL ;
    PORT
      LAYER M7 ;
        RECT  322.64 0 322.672 0.192 ;
    END
  END k_li_d[452]
  PIN k_li_d[453]
    DIRECTION OUTPUT ;
    USE SIGNAL ;
    PORT
      LAYER M7 ;
        RECT  323.344 0 323.376 0.192 ;
    END
  END k_li_d[453]
  PIN k_li_d[454]
    DIRECTION OUTPUT ;
    USE SIGNAL ;
    PORT
      LAYER M7 ;
        RECT  324.048 0 324.08 0.192 ;
    END
  END k_li_d[454]
  PIN k_li_d[455]
    DIRECTION OUTPUT ;
    USE SIGNAL ;
    PORT
      LAYER M7 ;
        RECT  324.752 0 324.784 0.192 ;
    END
  END k_li_d[455]
  PIN k_li_d[456]
    DIRECTION OUTPUT ;
    USE SIGNAL ;
    PORT
      LAYER M7 ;
        RECT  325.456 0 325.488 0.192 ;
    END
  END k_li_d[456]
  PIN k_li_d[457]
    DIRECTION OUTPUT ;
    USE SIGNAL ;
    PORT
      LAYER M7 ;
        RECT  326.16 0 326.192 0.192 ;
    END
  END k_li_d[457]
  PIN k_li_d[458]
    DIRECTION OUTPUT ;
    USE SIGNAL ;
    PORT
      LAYER M7 ;
        RECT  326.864 0 326.896 0.192 ;
    END
  END k_li_d[458]
  PIN k_li_d[459]
    DIRECTION OUTPUT ;
    USE SIGNAL ;
    PORT
      LAYER M7 ;
        RECT  327.568 0 327.6 0.192 ;
    END
  END k_li_d[459]
  PIN k_li_d[45]
    DIRECTION OUTPUT ;
    USE SIGNAL ;
    PORT
      LAYER M7 ;
        RECT  35.152 0 35.184 0.192 ;
    END
  END k_li_d[45]
  PIN k_li_d[460]
    DIRECTION OUTPUT ;
    USE SIGNAL ;
    PORT
      LAYER M7 ;
        RECT  328.272 0 328.304 0.192 ;
    END
  END k_li_d[460]
  PIN k_li_d[461]
    DIRECTION OUTPUT ;
    USE SIGNAL ;
    PORT
      LAYER M7 ;
        RECT  328.976 0 329.008 0.192 ;
    END
  END k_li_d[461]
  PIN k_li_d[462]
    DIRECTION OUTPUT ;
    USE SIGNAL ;
    PORT
      LAYER M7 ;
        RECT  329.68 0 329.712 0.192 ;
    END
  END k_li_d[462]
  PIN k_li_d[463]
    DIRECTION OUTPUT ;
    USE SIGNAL ;
    PORT
      LAYER M7 ;
        RECT  330.384 0 330.416 0.192 ;
    END
  END k_li_d[463]
  PIN k_li_d[464]
    DIRECTION OUTPUT ;
    USE SIGNAL ;
    PORT
      LAYER M7 ;
        RECT  331.088 0 331.12 0.192 ;
    END
  END k_li_d[464]
  PIN k_li_d[465]
    DIRECTION OUTPUT ;
    USE SIGNAL ;
    PORT
      LAYER M7 ;
        RECT  331.792 0 331.824 0.192 ;
    END
  END k_li_d[465]
  PIN k_li_d[466]
    DIRECTION OUTPUT ;
    USE SIGNAL ;
    PORT
      LAYER M7 ;
        RECT  332.496 0 332.528 0.192 ;
    END
  END k_li_d[466]
  PIN k_li_d[467]
    DIRECTION OUTPUT ;
    USE SIGNAL ;
    PORT
      LAYER M7 ;
        RECT  333.2 0 333.232 0.192 ;
    END
  END k_li_d[467]
  PIN k_li_d[468]
    DIRECTION OUTPUT ;
    USE SIGNAL ;
    PORT
      LAYER M7 ;
        RECT  333.904 0 333.936 0.192 ;
    END
  END k_li_d[468]
  PIN k_li_d[469]
    DIRECTION OUTPUT ;
    USE SIGNAL ;
    PORT
      LAYER M7 ;
        RECT  334.608 0 334.64 0.192 ;
    END
  END k_li_d[469]
  PIN k_li_d[46]
    DIRECTION OUTPUT ;
    USE SIGNAL ;
    PORT
      LAYER M7 ;
        RECT  35.856 0 35.888 0.192 ;
    END
  END k_li_d[46]
  PIN k_li_d[470]
    DIRECTION OUTPUT ;
    USE SIGNAL ;
    PORT
      LAYER M7 ;
        RECT  335.312 0 335.344 0.192 ;
    END
  END k_li_d[470]
  PIN k_li_d[471]
    DIRECTION OUTPUT ;
    USE SIGNAL ;
    PORT
      LAYER M7 ;
        RECT  336.016 0 336.048 0.192 ;
    END
  END k_li_d[471]
  PIN k_li_d[472]
    DIRECTION OUTPUT ;
    USE SIGNAL ;
    PORT
      LAYER M7 ;
        RECT  336.784 0 336.816 0.192 ;
    END
  END k_li_d[472]
  PIN k_li_d[473]
    DIRECTION OUTPUT ;
    USE SIGNAL ;
    PORT
      LAYER M7 ;
        RECT  337.488 0 337.52 0.192 ;
    END
  END k_li_d[473]
  PIN k_li_d[474]
    DIRECTION OUTPUT ;
    USE SIGNAL ;
    PORT
      LAYER M7 ;
        RECT  338.192 0 338.224 0.192 ;
    END
  END k_li_d[474]
  PIN k_li_d[475]
    DIRECTION OUTPUT ;
    USE SIGNAL ;
    PORT
      LAYER M7 ;
        RECT  338.896 0 338.928 0.192 ;
    END
  END k_li_d[475]
  PIN k_li_d[476]
    DIRECTION OUTPUT ;
    USE SIGNAL ;
    PORT
      LAYER M7 ;
        RECT  339.6 0 339.632 0.192 ;
    END
  END k_li_d[476]
  PIN k_li_d[477]
    DIRECTION OUTPUT ;
    USE SIGNAL ;
    PORT
      LAYER M7 ;
        RECT  340.304 0 340.336 0.192 ;
    END
  END k_li_d[477]
  PIN k_li_d[478]
    DIRECTION OUTPUT ;
    USE SIGNAL ;
    PORT
      LAYER M7 ;
        RECT  341.008 0 341.04 0.192 ;
    END
  END k_li_d[478]
  PIN k_li_d[479]
    DIRECTION OUTPUT ;
    USE SIGNAL ;
    PORT
      LAYER M7 ;
        RECT  341.712 0 341.744 0.192 ;
    END
  END k_li_d[479]
  PIN k_li_d[47]
    DIRECTION OUTPUT ;
    USE SIGNAL ;
    PORT
      LAYER M7 ;
        RECT  36.56 0 36.592 0.192 ;
    END
  END k_li_d[47]
  PIN k_li_d[480]
    DIRECTION OUTPUT ;
    USE SIGNAL ;
    PORT
      LAYER M7 ;
        RECT  342.416 0 342.448 0.192 ;
    END
  END k_li_d[480]
  PIN k_li_d[481]
    DIRECTION OUTPUT ;
    USE SIGNAL ;
    PORT
      LAYER M7 ;
        RECT  343.12 0 343.152 0.192 ;
    END
  END k_li_d[481]
  PIN k_li_d[482]
    DIRECTION OUTPUT ;
    USE SIGNAL ;
    PORT
      LAYER M7 ;
        RECT  343.824 0 343.856 0.192 ;
    END
  END k_li_d[482]
  PIN k_li_d[483]
    DIRECTION OUTPUT ;
    USE SIGNAL ;
    PORT
      LAYER M7 ;
        RECT  344.528 0 344.56 0.192 ;
    END
  END k_li_d[483]
  PIN k_li_d[484]
    DIRECTION OUTPUT ;
    USE SIGNAL ;
    PORT
      LAYER M7 ;
        RECT  345.232 0 345.264 0.192 ;
    END
  END k_li_d[484]
  PIN k_li_d[485]
    DIRECTION OUTPUT ;
    USE SIGNAL ;
    PORT
      LAYER M7 ;
        RECT  345.936 0 345.968 0.192 ;
    END
  END k_li_d[485]
  PIN k_li_d[486]
    DIRECTION OUTPUT ;
    USE SIGNAL ;
    PORT
      LAYER M7 ;
        RECT  346.64 0 346.672 0.192 ;
    END
  END k_li_d[486]
  PIN k_li_d[487]
    DIRECTION OUTPUT ;
    USE SIGNAL ;
    PORT
      LAYER M7 ;
        RECT  347.344 0 347.376 0.192 ;
    END
  END k_li_d[487]
  PIN k_li_d[488]
    DIRECTION OUTPUT ;
    USE SIGNAL ;
    PORT
      LAYER M7 ;
        RECT  348.048 0 348.08 0.192 ;
    END
  END k_li_d[488]
  PIN k_li_d[489]
    DIRECTION OUTPUT ;
    USE SIGNAL ;
    PORT
      LAYER M7 ;
        RECT  348.752 0 348.784 0.192 ;
    END
  END k_li_d[489]
  PIN k_li_d[48]
    DIRECTION OUTPUT ;
    USE SIGNAL ;
    PORT
      LAYER M7 ;
        RECT  37.264 0 37.296 0.192 ;
    END
  END k_li_d[48]
  PIN k_li_d[490]
    DIRECTION OUTPUT ;
    USE SIGNAL ;
    PORT
      LAYER M7 ;
        RECT  349.456 0 349.488 0.192 ;
    END
  END k_li_d[490]
  PIN k_li_d[491]
    DIRECTION OUTPUT ;
    USE SIGNAL ;
    PORT
      LAYER M7 ;
        RECT  350.16 0 350.192 0.192 ;
    END
  END k_li_d[491]
  PIN k_li_d[492]
    DIRECTION OUTPUT ;
    USE SIGNAL ;
    PORT
      LAYER M7 ;
        RECT  350.864 0 350.896 0.192 ;
    END
  END k_li_d[492]
  PIN k_li_d[493]
    DIRECTION OUTPUT ;
    USE SIGNAL ;
    PORT
      LAYER M7 ;
        RECT  351.568 0 351.6 0.192 ;
    END
  END k_li_d[493]
  PIN k_li_d[494]
    DIRECTION OUTPUT ;
    USE SIGNAL ;
    PORT
      LAYER M7 ;
        RECT  352.272 0 352.304 0.192 ;
    END
  END k_li_d[494]
  PIN k_li_d[495]
    DIRECTION OUTPUT ;
    USE SIGNAL ;
    PORT
      LAYER M7 ;
        RECT  352.976 0 353.008 0.192 ;
    END
  END k_li_d[495]
  PIN k_li_d[496]
    DIRECTION OUTPUT ;
    USE SIGNAL ;
    PORT
      LAYER M7 ;
        RECT  353.68 0 353.712 0.192 ;
    END
  END k_li_d[496]
  PIN k_li_d[497]
    DIRECTION OUTPUT ;
    USE SIGNAL ;
    PORT
      LAYER M7 ;
        RECT  354.384 0 354.416 0.192 ;
    END
  END k_li_d[497]
  PIN k_li_d[498]
    DIRECTION OUTPUT ;
    USE SIGNAL ;
    PORT
      LAYER M7 ;
        RECT  355.088 0 355.12 0.192 ;
    END
  END k_li_d[498]
  PIN k_li_d[499]
    DIRECTION OUTPUT ;
    USE SIGNAL ;
    PORT
      LAYER M7 ;
        RECT  355.792 0 355.824 0.192 ;
    END
  END k_li_d[499]
  PIN k_li_d[49]
    DIRECTION OUTPUT ;
    USE SIGNAL ;
    PORT
      LAYER M7 ;
        RECT  37.968 0 38 0.192 ;
    END
  END k_li_d[49]
  PIN k_li_d[4]
    DIRECTION OUTPUT ;
    USE SIGNAL ;
    PORT
      LAYER M7 ;
        RECT  6.224 0 6.256 0.192 ;
    END
  END k_li_d[4]
  PIN k_li_d[500]
    DIRECTION OUTPUT ;
    USE SIGNAL ;
    PORT
      LAYER M7 ;
        RECT  356.56 0 356.592 0.192 ;
    END
  END k_li_d[500]
  PIN k_li_d[501]
    DIRECTION OUTPUT ;
    USE SIGNAL ;
    PORT
      LAYER M7 ;
        RECT  357.264 0 357.296 0.192 ;
    END
  END k_li_d[501]
  PIN k_li_d[502]
    DIRECTION OUTPUT ;
    USE SIGNAL ;
    PORT
      LAYER M7 ;
        RECT  357.968 0 358 0.192 ;
    END
  END k_li_d[502]
  PIN k_li_d[503]
    DIRECTION OUTPUT ;
    USE SIGNAL ;
    PORT
      LAYER M7 ;
        RECT  358.672 0 358.704 0.192 ;
    END
  END k_li_d[503]
  PIN k_li_d[504]
    DIRECTION OUTPUT ;
    USE SIGNAL ;
    PORT
      LAYER M7 ;
        RECT  359.376 0 359.408 0.192 ;
    END
  END k_li_d[504]
  PIN k_li_d[505]
    DIRECTION OUTPUT ;
    USE SIGNAL ;
    PORT
      LAYER M7 ;
        RECT  360.08 0 360.112 0.192 ;
    END
  END k_li_d[505]
  PIN k_li_d[506]
    DIRECTION OUTPUT ;
    USE SIGNAL ;
    PORT
      LAYER M7 ;
        RECT  360.784 0 360.816 0.192 ;
    END
  END k_li_d[506]
  PIN k_li_d[507]
    DIRECTION OUTPUT ;
    USE SIGNAL ;
    PORT
      LAYER M7 ;
        RECT  361.488 0 361.52 0.192 ;
    END
  END k_li_d[507]
  PIN k_li_d[508]
    DIRECTION OUTPUT ;
    USE SIGNAL ;
    PORT
      LAYER M7 ;
        RECT  362.192 0 362.224 0.192 ;
    END
  END k_li_d[508]
  PIN k_li_d[509]
    DIRECTION OUTPUT ;
    USE SIGNAL ;
    PORT
      LAYER M7 ;
        RECT  362.896 0 362.928 0.192 ;
    END
  END k_li_d[509]
  PIN k_li_d[50]
    DIRECTION OUTPUT ;
    USE SIGNAL ;
    PORT
      LAYER M7 ;
        RECT  38.672 0 38.704 0.192 ;
    END
  END k_li_d[50]
  PIN k_li_d[510]
    DIRECTION OUTPUT ;
    USE SIGNAL ;
    PORT
      LAYER M7 ;
        RECT  363.6 0 363.632 0.192 ;
    END
  END k_li_d[510]
  PIN k_li_d[511]
    DIRECTION OUTPUT ;
    USE SIGNAL ;
    PORT
      LAYER M7 ;
        RECT  364.304 0 364.336 0.192 ;
    END
  END k_li_d[511]
  PIN k_li_d[512]
    DIRECTION OUTPUT ;
    USE SIGNAL ;
    PORT
      LAYER M7 ;
        RECT  365.008 0 365.04 0.192 ;
    END
  END k_li_d[512]
  PIN k_li_d[513]
    DIRECTION OUTPUT ;
    USE SIGNAL ;
    PORT
      LAYER M7 ;
        RECT  365.712 0 365.744 0.192 ;
    END
  END k_li_d[513]
  PIN k_li_d[514]
    DIRECTION OUTPUT ;
    USE SIGNAL ;
    PORT
      LAYER M7 ;
        RECT  366.416 0 366.448 0.192 ;
    END
  END k_li_d[514]
  PIN k_li_d[515]
    DIRECTION OUTPUT ;
    USE SIGNAL ;
    PORT
      LAYER M7 ;
        RECT  367.12 0 367.152 0.192 ;
    END
  END k_li_d[515]
  PIN k_li_d[516]
    DIRECTION OUTPUT ;
    USE SIGNAL ;
    PORT
      LAYER M7 ;
        RECT  367.824 0 367.856 0.192 ;
    END
  END k_li_d[516]
  PIN k_li_d[517]
    DIRECTION OUTPUT ;
    USE SIGNAL ;
    PORT
      LAYER M7 ;
        RECT  368.528 0 368.56 0.192 ;
    END
  END k_li_d[517]
  PIN k_li_d[518]
    DIRECTION OUTPUT ;
    USE SIGNAL ;
    PORT
      LAYER M7 ;
        RECT  369.232 0 369.264 0.192 ;
    END
  END k_li_d[518]
  PIN k_li_d[519]
    DIRECTION OUTPUT ;
    USE SIGNAL ;
    PORT
      LAYER M7 ;
        RECT  369.936 0 369.968 0.192 ;
    END
  END k_li_d[519]
  PIN k_li_d[51]
    DIRECTION OUTPUT ;
    USE SIGNAL ;
    PORT
      LAYER M7 ;
        RECT  39.376 0 39.408 0.192 ;
    END
  END k_li_d[51]
  PIN k_li_d[520]
    DIRECTION OUTPUT ;
    USE SIGNAL ;
    PORT
      LAYER M7 ;
        RECT  370.64 0 370.672 0.192 ;
    END
  END k_li_d[520]
  PIN k_li_d[521]
    DIRECTION OUTPUT ;
    USE SIGNAL ;
    PORT
      LAYER M7 ;
        RECT  371.344 0 371.376 0.192 ;
    END
  END k_li_d[521]
  PIN k_li_d[522]
    DIRECTION OUTPUT ;
    USE SIGNAL ;
    PORT
      LAYER M7 ;
        RECT  372.048 0 372.08 0.192 ;
    END
  END k_li_d[522]
  PIN k_li_d[523]
    DIRECTION OUTPUT ;
    USE SIGNAL ;
    PORT
      LAYER M7 ;
        RECT  372.752 0 372.784 0.192 ;
    END
  END k_li_d[523]
  PIN k_li_d[524]
    DIRECTION OUTPUT ;
    USE SIGNAL ;
    PORT
      LAYER M7 ;
        RECT  373.456 0 373.488 0.192 ;
    END
  END k_li_d[524]
  PIN k_li_d[525]
    DIRECTION OUTPUT ;
    USE SIGNAL ;
    PORT
      LAYER M7 ;
        RECT  374.16 0 374.192 0.192 ;
    END
  END k_li_d[525]
  PIN k_li_d[526]
    DIRECTION OUTPUT ;
    USE SIGNAL ;
    PORT
      LAYER M7 ;
        RECT  374.864 0 374.896 0.192 ;
    END
  END k_li_d[526]
  PIN k_li_d[527]
    DIRECTION OUTPUT ;
    USE SIGNAL ;
    PORT
      LAYER M7 ;
        RECT  375.568 0 375.6 0.192 ;
    END
  END k_li_d[527]
  PIN k_li_d[528]
    DIRECTION OUTPUT ;
    USE SIGNAL ;
    PORT
      LAYER M7 ;
        RECT  376.336 0 376.368 0.192 ;
    END
  END k_li_d[528]
  PIN k_li_d[529]
    DIRECTION OUTPUT ;
    USE SIGNAL ;
    PORT
      LAYER M7 ;
        RECT  377.04 0 377.072 0.192 ;
    END
  END k_li_d[529]
  PIN k_li_d[52]
    DIRECTION OUTPUT ;
    USE SIGNAL ;
    PORT
      LAYER M7 ;
        RECT  40.08 0 40.112 0.192 ;
    END
  END k_li_d[52]
  PIN k_li_d[530]
    DIRECTION OUTPUT ;
    USE SIGNAL ;
    PORT
      LAYER M7 ;
        RECT  377.744 0 377.776 0.192 ;
    END
  END k_li_d[530]
  PIN k_li_d[531]
    DIRECTION OUTPUT ;
    USE SIGNAL ;
    PORT
      LAYER M7 ;
        RECT  378.448 0 378.48 0.192 ;
    END
  END k_li_d[531]
  PIN k_li_d[532]
    DIRECTION OUTPUT ;
    USE SIGNAL ;
    PORT
      LAYER M7 ;
        RECT  379.152 0 379.184 0.192 ;
    END
  END k_li_d[532]
  PIN k_li_d[533]
    DIRECTION OUTPUT ;
    USE SIGNAL ;
    PORT
      LAYER M7 ;
        RECT  379.856 0 379.888 0.192 ;
    END
  END k_li_d[533]
  PIN k_li_d[534]
    DIRECTION OUTPUT ;
    USE SIGNAL ;
    PORT
      LAYER M7 ;
        RECT  380.56 0 380.592 0.192 ;
    END
  END k_li_d[534]
  PIN k_li_d[535]
    DIRECTION OUTPUT ;
    USE SIGNAL ;
    PORT
      LAYER M7 ;
        RECT  381.264 0 381.296 0.192 ;
    END
  END k_li_d[535]
  PIN k_li_d[536]
    DIRECTION OUTPUT ;
    USE SIGNAL ;
    PORT
      LAYER M7 ;
        RECT  381.968 0 382 0.192 ;
    END
  END k_li_d[536]
  PIN k_li_d[537]
    DIRECTION OUTPUT ;
    USE SIGNAL ;
    PORT
      LAYER M7 ;
        RECT  382.672 0 382.704 0.192 ;
    END
  END k_li_d[537]
  PIN k_li_d[538]
    DIRECTION OUTPUT ;
    USE SIGNAL ;
    PORT
      LAYER M7 ;
        RECT  383.376 0 383.408 0.192 ;
    END
  END k_li_d[538]
  PIN k_li_d[539]
    DIRECTION OUTPUT ;
    USE SIGNAL ;
    PORT
      LAYER M7 ;
        RECT  384.08 0 384.112 0.192 ;
    END
  END k_li_d[539]
  PIN k_li_d[53]
    DIRECTION OUTPUT ;
    USE SIGNAL ;
    PORT
      LAYER M7 ;
        RECT  40.784 0 40.816 0.192 ;
    END
  END k_li_d[53]
  PIN k_li_d[540]
    DIRECTION OUTPUT ;
    USE SIGNAL ;
    PORT
      LAYER M7 ;
        RECT  384.784 0 384.816 0.192 ;
    END
  END k_li_d[540]
  PIN k_li_d[541]
    DIRECTION OUTPUT ;
    USE SIGNAL ;
    PORT
      LAYER M7 ;
        RECT  385.488 0 385.52 0.192 ;
    END
  END k_li_d[541]
  PIN k_li_d[542]
    DIRECTION OUTPUT ;
    USE SIGNAL ;
    PORT
      LAYER M7 ;
        RECT  386.192 0 386.224 0.192 ;
    END
  END k_li_d[542]
  PIN k_li_d[543]
    DIRECTION OUTPUT ;
    USE SIGNAL ;
    PORT
      LAYER M7 ;
        RECT  386.896 0 386.928 0.192 ;
    END
  END k_li_d[543]
  PIN k_li_d[544]
    DIRECTION OUTPUT ;
    USE SIGNAL ;
    PORT
      LAYER M7 ;
        RECT  387.6 0 387.632 0.192 ;
    END
  END k_li_d[544]
  PIN k_li_d[545]
    DIRECTION OUTPUT ;
    USE SIGNAL ;
    PORT
      LAYER M7 ;
        RECT  388.304 0 388.336 0.192 ;
    END
  END k_li_d[545]
  PIN k_li_d[546]
    DIRECTION OUTPUT ;
    USE SIGNAL ;
    PORT
      LAYER M7 ;
        RECT  389.008 0 389.04 0.192 ;
    END
  END k_li_d[546]
  PIN k_li_d[547]
    DIRECTION OUTPUT ;
    USE SIGNAL ;
    PORT
      LAYER M7 ;
        RECT  389.712 0 389.744 0.192 ;
    END
  END k_li_d[547]
  PIN k_li_d[548]
    DIRECTION OUTPUT ;
    USE SIGNAL ;
    PORT
      LAYER M7 ;
        RECT  390.416 0 390.448 0.192 ;
    END
  END k_li_d[548]
  PIN k_li_d[549]
    DIRECTION OUTPUT ;
    USE SIGNAL ;
    PORT
      LAYER M7 ;
        RECT  391.12 0 391.152 0.192 ;
    END
  END k_li_d[549]
  PIN k_li_d[54]
    DIRECTION OUTPUT ;
    USE SIGNAL ;
    PORT
      LAYER M7 ;
        RECT  41.552 0 41.584 0.192 ;
    END
  END k_li_d[54]
  PIN k_li_d[550]
    DIRECTION OUTPUT ;
    USE SIGNAL ;
    PORT
      LAYER M7 ;
        RECT  391.824 0 391.856 0.192 ;
    END
  END k_li_d[550]
  PIN k_li_d[551]
    DIRECTION OUTPUT ;
    USE SIGNAL ;
    PORT
      LAYER M7 ;
        RECT  392.528 0 392.56 0.192 ;
    END
  END k_li_d[551]
  PIN k_li_d[552]
    DIRECTION OUTPUT ;
    USE SIGNAL ;
    PORT
      LAYER M7 ;
        RECT  393.232 0 393.264 0.192 ;
    END
  END k_li_d[552]
  PIN k_li_d[55]
    DIRECTION OUTPUT ;
    USE SIGNAL ;
    PORT
      LAYER M7 ;
        RECT  42.256 0 42.288 0.192 ;
    END
  END k_li_d[55]
  PIN k_li_d[56]
    DIRECTION OUTPUT ;
    USE SIGNAL ;
    PORT
      LAYER M7 ;
        RECT  42.96 0 42.992 0.192 ;
    END
  END k_li_d[56]
  PIN k_li_d[57]
    DIRECTION OUTPUT ;
    USE SIGNAL ;
    PORT
      LAYER M7 ;
        RECT  43.664 0 43.696 0.192 ;
    END
  END k_li_d[57]
  PIN k_li_d[58]
    DIRECTION OUTPUT ;
    USE SIGNAL ;
    PORT
      LAYER M7 ;
        RECT  44.368 0 44.4 0.192 ;
    END
  END k_li_d[58]
  PIN k_li_d[59]
    DIRECTION OUTPUT ;
    USE SIGNAL ;
    PORT
      LAYER M7 ;
        RECT  45.072 0 45.104 0.192 ;
    END
  END k_li_d[59]
  PIN k_li_d[5]
    DIRECTION OUTPUT ;
    USE SIGNAL ;
    PORT
      LAYER M7 ;
        RECT  6.928 0 6.96 0.192 ;
    END
  END k_li_d[5]
  PIN k_li_d[60]
    DIRECTION OUTPUT ;
    USE SIGNAL ;
    PORT
      LAYER M7 ;
        RECT  45.776 0 45.808 0.192 ;
    END
  END k_li_d[60]
  PIN k_li_d[61]
    DIRECTION OUTPUT ;
    USE SIGNAL ;
    PORT
      LAYER M7 ;
        RECT  46.48 0 46.512 0.192 ;
    END
  END k_li_d[61]
  PIN k_li_d[62]
    DIRECTION OUTPUT ;
    USE SIGNAL ;
    PORT
      LAYER M7 ;
        RECT  47.184 0 47.216 0.192 ;
    END
  END k_li_d[62]
  PIN k_li_d[63]
    DIRECTION OUTPUT ;
    USE SIGNAL ;
    PORT
      LAYER M7 ;
        RECT  47.888 0 47.92 0.192 ;
    END
  END k_li_d[63]
  PIN k_li_d[64]
    DIRECTION OUTPUT ;
    USE SIGNAL ;
    PORT
      LAYER M7 ;
        RECT  48.592 0 48.624 0.192 ;
    END
  END k_li_d[64]
  PIN k_li_d[65]
    DIRECTION OUTPUT ;
    USE SIGNAL ;
    PORT
      LAYER M7 ;
        RECT  49.296 0 49.328 0.192 ;
    END
  END k_li_d[65]
  PIN k_li_d[66]
    DIRECTION OUTPUT ;
    USE SIGNAL ;
    PORT
      LAYER M7 ;
        RECT  50 0 50.032 0.192 ;
    END
  END k_li_d[66]
  PIN k_li_d[67]
    DIRECTION OUTPUT ;
    USE SIGNAL ;
    PORT
      LAYER M7 ;
        RECT  50.704 0 50.736 0.192 ;
    END
  END k_li_d[67]
  PIN k_li_d[68]
    DIRECTION OUTPUT ;
    USE SIGNAL ;
    PORT
      LAYER M7 ;
        RECT  51.408 0 51.44 0.192 ;
    END
  END k_li_d[68]
  PIN k_li_d[69]
    DIRECTION OUTPUT ;
    USE SIGNAL ;
    PORT
      LAYER M7 ;
        RECT  52.112 0 52.144 0.192 ;
    END
  END k_li_d[69]
  PIN k_li_d[6]
    DIRECTION OUTPUT ;
    USE SIGNAL ;
    PORT
      LAYER M7 ;
        RECT  7.632 0 7.664 0.192 ;
    END
  END k_li_d[6]
  PIN k_li_d[70]
    DIRECTION OUTPUT ;
    USE SIGNAL ;
    PORT
      LAYER M7 ;
        RECT  52.816 0 52.848 0.192 ;
    END
  END k_li_d[70]
  PIN k_li_d[71]
    DIRECTION OUTPUT ;
    USE SIGNAL ;
    PORT
      LAYER M7 ;
        RECT  53.52 0 53.552 0.192 ;
    END
  END k_li_d[71]
  PIN k_li_d[72]
    DIRECTION OUTPUT ;
    USE SIGNAL ;
    PORT
      LAYER M7 ;
        RECT  54.224 0 54.256 0.192 ;
    END
  END k_li_d[72]
  PIN k_li_d[73]
    DIRECTION OUTPUT ;
    USE SIGNAL ;
    PORT
      LAYER M7 ;
        RECT  54.928 0 54.96 0.192 ;
    END
  END k_li_d[73]
  PIN k_li_d[74]
    DIRECTION OUTPUT ;
    USE SIGNAL ;
    PORT
      LAYER M7 ;
        RECT  55.632 0 55.664 0.192 ;
    END
  END k_li_d[74]
  PIN k_li_d[75]
    DIRECTION OUTPUT ;
    USE SIGNAL ;
    PORT
      LAYER M7 ;
        RECT  56.336 0 56.368 0.192 ;
    END
  END k_li_d[75]
  PIN k_li_d[76]
    DIRECTION OUTPUT ;
    USE SIGNAL ;
    PORT
      LAYER M7 ;
        RECT  57.04 0 57.072 0.192 ;
    END
  END k_li_d[76]
  PIN k_li_d[77]
    DIRECTION OUTPUT ;
    USE SIGNAL ;
    PORT
      LAYER M7 ;
        RECT  57.744 0 57.776 0.192 ;
    END
  END k_li_d[77]
  PIN k_li_d[78]
    DIRECTION OUTPUT ;
    USE SIGNAL ;
    PORT
      LAYER M7 ;
        RECT  58.448 0 58.48 0.192 ;
    END
  END k_li_d[78]
  PIN k_li_d[79]
    DIRECTION OUTPUT ;
    USE SIGNAL ;
    PORT
      LAYER M7 ;
        RECT  59.152 0 59.184 0.192 ;
    END
  END k_li_d[79]
  PIN k_li_d[7]
    DIRECTION OUTPUT ;
    USE SIGNAL ;
    PORT
      LAYER M7 ;
        RECT  8.336 0 8.368 0.192 ;
    END
  END k_li_d[7]
  PIN k_li_d[80]
    DIRECTION OUTPUT ;
    USE SIGNAL ;
    PORT
      LAYER M7 ;
        RECT  59.856 0 59.888 0.192 ;
    END
  END k_li_d[80]
  PIN k_li_d[81]
    DIRECTION OUTPUT ;
    USE SIGNAL ;
    PORT
      LAYER M7 ;
        RECT  60.56 0 60.592 0.192 ;
    END
  END k_li_d[81]
  PIN k_li_d[82]
    DIRECTION OUTPUT ;
    USE SIGNAL ;
    PORT
      LAYER M7 ;
        RECT  61.328 0 61.36 0.192 ;
    END
  END k_li_d[82]
  PIN k_li_d[83]
    DIRECTION OUTPUT ;
    USE SIGNAL ;
    PORT
      LAYER M7 ;
        RECT  62.032 0 62.064 0.192 ;
    END
  END k_li_d[83]
  PIN k_li_d[84]
    DIRECTION OUTPUT ;
    USE SIGNAL ;
    PORT
      LAYER M7 ;
        RECT  62.736 0 62.768 0.192 ;
    END
  END k_li_d[84]
  PIN k_li_d[85]
    DIRECTION OUTPUT ;
    USE SIGNAL ;
    PORT
      LAYER M7 ;
        RECT  63.44 0 63.472 0.192 ;
    END
  END k_li_d[85]
  PIN k_li_d[86]
    DIRECTION OUTPUT ;
    USE SIGNAL ;
    PORT
      LAYER M7 ;
        RECT  64.144 0 64.176 0.192 ;
    END
  END k_li_d[86]
  PIN k_li_d[87]
    DIRECTION OUTPUT ;
    USE SIGNAL ;
    PORT
      LAYER M7 ;
        RECT  64.848 0 64.88 0.192 ;
    END
  END k_li_d[87]
  PIN k_li_d[88]
    DIRECTION OUTPUT ;
    USE SIGNAL ;
    PORT
      LAYER M7 ;
        RECT  65.552 0 65.584 0.192 ;
    END
  END k_li_d[88]
  PIN k_li_d[89]
    DIRECTION OUTPUT ;
    USE SIGNAL ;
    PORT
      LAYER M7 ;
        RECT  66.256 0 66.288 0.192 ;
    END
  END k_li_d[89]
  PIN k_li_d[8]
    DIRECTION OUTPUT ;
    USE SIGNAL ;
    PORT
      LAYER M7 ;
        RECT  9.04 0 9.072 0.192 ;
    END
  END k_li_d[8]
  PIN k_li_d[90]
    DIRECTION OUTPUT ;
    USE SIGNAL ;
    PORT
      LAYER M7 ;
        RECT  66.96 0 66.992 0.192 ;
    END
  END k_li_d[90]
  PIN k_li_d[91]
    DIRECTION OUTPUT ;
    USE SIGNAL ;
    PORT
      LAYER M7 ;
        RECT  67.664 0 67.696 0.192 ;
    END
  END k_li_d[91]
  PIN k_li_d[92]
    DIRECTION OUTPUT ;
    USE SIGNAL ;
    PORT
      LAYER M7 ;
        RECT  68.368 0 68.4 0.192 ;
    END
  END k_li_d[92]
  PIN k_li_d[93]
    DIRECTION OUTPUT ;
    USE SIGNAL ;
    PORT
      LAYER M7 ;
        RECT  69.072 0 69.104 0.192 ;
    END
  END k_li_d[93]
  PIN k_li_d[94]
    DIRECTION OUTPUT ;
    USE SIGNAL ;
    PORT
      LAYER M7 ;
        RECT  69.776 0 69.808 0.192 ;
    END
  END k_li_d[94]
  PIN k_li_d[95]
    DIRECTION OUTPUT ;
    USE SIGNAL ;
    PORT
      LAYER M7 ;
        RECT  70.48 0 70.512 0.192 ;
    END
  END k_li_d[95]
  PIN k_li_d[96]
    DIRECTION OUTPUT ;
    USE SIGNAL ;
    PORT
      LAYER M7 ;
        RECT  71.184 0 71.216 0.192 ;
    END
  END k_li_d[96]
  PIN k_li_d[97]
    DIRECTION OUTPUT ;
    USE SIGNAL ;
    PORT
      LAYER M7 ;
        RECT  71.888 0 71.92 0.192 ;
    END
  END k_li_d[97]
  PIN k_li_d[98]
    DIRECTION OUTPUT ;
    USE SIGNAL ;
    PORT
      LAYER M7 ;
        RECT  72.592 0 72.624 0.192 ;
    END
  END k_li_d[98]
  PIN k_li_d[99]
    DIRECTION OUTPUT ;
    USE SIGNAL ;
    PORT
      LAYER M7 ;
        RECT  73.296 0 73.328 0.192 ;
    END
  END k_li_d[99]
  PIN k_li_d[9]
    DIRECTION OUTPUT ;
    USE SIGNAL ;
    PORT
      LAYER M7 ;
        RECT  9.744 0 9.776 0.192 ;
    END
  END k_li_d[9]
  PIN k_li_r
    DIRECTION INPUT ;
    USE SIGNAL ;
    PORT
      LAYER M5 ;
        RECT  394.668 0 394.692 0.192 ;
    END
  END k_li_r
  PIN k_li_v
    DIRECTION OUTPUT ;
    USE SIGNAL ;
    PORT
      LAYER M7 ;
        RECT  2.704 0 2.736 0.192 ;
    END
  END k_li_v
  PIN k_lo_d[0]
    DIRECTION INPUT ;
    USE SIGNAL ;
    PORT
      LAYER M5 ;
        RECT  2.7 0 2.724 0.192 ;
    END
  END k_lo_d[0]
  PIN k_lo_d[100]
    DIRECTION INPUT ;
    USE SIGNAL ;
    PORT
      LAYER M5 ;
        RECT  73.596 0 73.62 0.192 ;
    END
  END k_lo_d[100]
  PIN k_lo_d[101]
    DIRECTION INPUT ;
    USE SIGNAL ;
    PORT
      LAYER M5 ;
        RECT  74.316 0 74.34 0.192 ;
    END
  END k_lo_d[101]
  PIN k_lo_d[102]
    DIRECTION INPUT ;
    USE SIGNAL ;
    PORT
      LAYER M5 ;
        RECT  74.988 0 75.012 0.192 ;
    END
  END k_lo_d[102]
  PIN k_lo_d[103]
    DIRECTION INPUT ;
    USE SIGNAL ;
    PORT
      LAYER M5 ;
        RECT  75.708 0 75.732 0.192 ;
    END
  END k_lo_d[103]
  PIN k_lo_d[104]
    DIRECTION INPUT ;
    USE SIGNAL ;
    PORT
      LAYER M5 ;
        RECT  76.428 0 76.452 0.192 ;
    END
  END k_lo_d[104]
  PIN k_lo_d[105]
    DIRECTION INPUT ;
    USE SIGNAL ;
    PORT
      LAYER M5 ;
        RECT  77.148 0 77.172 0.192 ;
    END
  END k_lo_d[105]
  PIN k_lo_d[106]
    DIRECTION INPUT ;
    USE SIGNAL ;
    PORT
      LAYER M5 ;
        RECT  77.82 0 77.844 0.192 ;
    END
  END k_lo_d[106]
  PIN k_lo_d[107]
    DIRECTION INPUT ;
    USE SIGNAL ;
    PORT
      LAYER M5 ;
        RECT  78.54 0 78.564 0.192 ;
    END
  END k_lo_d[107]
  PIN k_lo_d[108]
    DIRECTION INPUT ;
    USE SIGNAL ;
    PORT
      LAYER M5 ;
        RECT  79.26 0 79.284 0.192 ;
    END
  END k_lo_d[108]
  PIN k_lo_d[109]
    DIRECTION INPUT ;
    USE SIGNAL ;
    PORT
      LAYER M5 ;
        RECT  79.98 0 80.004 0.192 ;
    END
  END k_lo_d[109]
  PIN k_lo_d[10]
    DIRECTION INPUT ;
    USE SIGNAL ;
    PORT
      LAYER M5 ;
        RECT  9.804 0 9.828 0.192 ;
    END
  END k_lo_d[10]
  PIN k_lo_d[110]
    DIRECTION INPUT ;
    USE SIGNAL ;
    PORT
      LAYER M5 ;
        RECT  80.7 0 80.724 0.192 ;
    END
  END k_lo_d[110]
  PIN k_lo_d[111]
    DIRECTION INPUT ;
    USE SIGNAL ;
    PORT
      LAYER M5 ;
        RECT  81.372 0 81.396 0.192 ;
    END
  END k_lo_d[111]
  PIN k_lo_d[112]
    DIRECTION INPUT ;
    USE SIGNAL ;
    PORT
      LAYER M5 ;
        RECT  82.092 0 82.116 0.192 ;
    END
  END k_lo_d[112]
  PIN k_lo_d[113]
    DIRECTION INPUT ;
    USE SIGNAL ;
    PORT
      LAYER M5 ;
        RECT  82.812 0 82.836 0.192 ;
    END
  END k_lo_d[113]
  PIN k_lo_d[114]
    DIRECTION INPUT ;
    USE SIGNAL ;
    PORT
      LAYER M5 ;
        RECT  83.532 0 83.556 0.192 ;
    END
  END k_lo_d[114]
  PIN k_lo_d[115]
    DIRECTION INPUT ;
    USE SIGNAL ;
    PORT
      LAYER M5 ;
        RECT  84.204 0 84.228 0.192 ;
    END
  END k_lo_d[115]
  PIN k_lo_d[116]
    DIRECTION INPUT ;
    USE SIGNAL ;
    PORT
      LAYER M5 ;
        RECT  84.924 0 84.948 0.192 ;
    END
  END k_lo_d[116]
  PIN k_lo_d[117]
    DIRECTION INPUT ;
    USE SIGNAL ;
    PORT
      LAYER M5 ;
        RECT  85.644 0 85.668 0.192 ;
    END
  END k_lo_d[117]
  PIN k_lo_d[118]
    DIRECTION INPUT ;
    USE SIGNAL ;
    PORT
      LAYER M5 ;
        RECT  86.364 0 86.388 0.192 ;
    END
  END k_lo_d[118]
  PIN k_lo_d[119]
    DIRECTION INPUT ;
    USE SIGNAL ;
    PORT
      LAYER M5 ;
        RECT  87.036 0 87.06 0.192 ;
    END
  END k_lo_d[119]
  PIN k_lo_d[11]
    DIRECTION INPUT ;
    USE SIGNAL ;
    PORT
      LAYER M5 ;
        RECT  10.524 0 10.548 0.192 ;
    END
  END k_lo_d[11]
  PIN k_lo_d[120]
    DIRECTION INPUT ;
    USE SIGNAL ;
    PORT
      LAYER M5 ;
        RECT  87.756 0 87.78 0.192 ;
    END
  END k_lo_d[120]
  PIN k_lo_d[121]
    DIRECTION INPUT ;
    USE SIGNAL ;
    PORT
      LAYER M5 ;
        RECT  88.476 0 88.5 0.192 ;
    END
  END k_lo_d[121]
  PIN k_lo_d[122]
    DIRECTION INPUT ;
    USE SIGNAL ;
    PORT
      LAYER M5 ;
        RECT  89.196 0 89.22 0.192 ;
    END
  END k_lo_d[122]
  PIN k_lo_d[123]
    DIRECTION INPUT ;
    USE SIGNAL ;
    PORT
      LAYER M5 ;
        RECT  89.868 0 89.892 0.192 ;
    END
  END k_lo_d[123]
  PIN k_lo_d[124]
    DIRECTION INPUT ;
    USE SIGNAL ;
    PORT
      LAYER M5 ;
        RECT  90.588 0 90.612 0.192 ;
    END
  END k_lo_d[124]
  PIN k_lo_d[125]
    DIRECTION INPUT ;
    USE SIGNAL ;
    PORT
      LAYER M5 ;
        RECT  91.308 0 91.332 0.192 ;
    END
  END k_lo_d[125]
  PIN k_lo_d[126]
    DIRECTION INPUT ;
    USE SIGNAL ;
    PORT
      LAYER M5 ;
        RECT  92.028 0 92.052 0.192 ;
    END
  END k_lo_d[126]
  PIN k_lo_d[127]
    DIRECTION INPUT ;
    USE SIGNAL ;
    PORT
      LAYER M5 ;
        RECT  92.748 0 92.772 0.192 ;
    END
  END k_lo_d[127]
  PIN k_lo_d[128]
    DIRECTION INPUT ;
    USE SIGNAL ;
    PORT
      LAYER M5 ;
        RECT  93.42 0 93.444 0.192 ;
    END
  END k_lo_d[128]
  PIN k_lo_d[129]
    DIRECTION INPUT ;
    USE SIGNAL ;
    PORT
      LAYER M5 ;
        RECT  94.14 0 94.164 0.192 ;
    END
  END k_lo_d[129]
  PIN k_lo_d[12]
    DIRECTION INPUT ;
    USE SIGNAL ;
    PORT
      LAYER M5 ;
        RECT  11.196 0 11.22 0.192 ;
    END
  END k_lo_d[12]
  PIN k_lo_d[130]
    DIRECTION INPUT ;
    USE SIGNAL ;
    PORT
      LAYER M5 ;
        RECT  94.86 0 94.884 0.192 ;
    END
  END k_lo_d[130]
  PIN k_lo_d[131]
    DIRECTION INPUT ;
    USE SIGNAL ;
    PORT
      LAYER M5 ;
        RECT  95.58 0 95.604 0.192 ;
    END
  END k_lo_d[131]
  PIN k_lo_d[132]
    DIRECTION INPUT ;
    USE SIGNAL ;
    PORT
      LAYER M5 ;
        RECT  96.252 0 96.276 0.192 ;
    END
  END k_lo_d[132]
  PIN k_lo_d[133]
    DIRECTION INPUT ;
    USE SIGNAL ;
    PORT
      LAYER M5 ;
        RECT  96.972 0 96.996 0.192 ;
    END
  END k_lo_d[133]
  PIN k_lo_d[134]
    DIRECTION INPUT ;
    USE SIGNAL ;
    PORT
      LAYER M5 ;
        RECT  97.692 0 97.716 0.192 ;
    END
  END k_lo_d[134]
  PIN k_lo_d[135]
    DIRECTION INPUT ;
    USE SIGNAL ;
    PORT
      LAYER M5 ;
        RECT  98.412 0 98.436 0.192 ;
    END
  END k_lo_d[135]
  PIN k_lo_d[136]
    DIRECTION INPUT ;
    USE SIGNAL ;
    PORT
      LAYER M5 ;
        RECT  99.084 0 99.108 0.192 ;
    END
  END k_lo_d[136]
  PIN k_lo_d[137]
    DIRECTION INPUT ;
    USE SIGNAL ;
    PORT
      LAYER M5 ;
        RECT  99.804 0 99.828 0.192 ;
    END
  END k_lo_d[137]
  PIN k_lo_d[138]
    DIRECTION INPUT ;
    USE SIGNAL ;
    PORT
      LAYER M5 ;
        RECT  100.524 0 100.548 0.192 ;
    END
  END k_lo_d[138]
  PIN k_lo_d[139]
    DIRECTION INPUT ;
    USE SIGNAL ;
    PORT
      LAYER M5 ;
        RECT  101.244 0 101.268 0.192 ;
    END
  END k_lo_d[139]
  PIN k_lo_d[13]
    DIRECTION INPUT ;
    USE SIGNAL ;
    PORT
      LAYER M5 ;
        RECT  11.916 0 11.94 0.192 ;
    END
  END k_lo_d[13]
  PIN k_lo_d[140]
    DIRECTION INPUT ;
    USE SIGNAL ;
    PORT
      LAYER M5 ;
        RECT  101.916 0 101.94 0.192 ;
    END
  END k_lo_d[140]
  PIN k_lo_d[141]
    DIRECTION INPUT ;
    USE SIGNAL ;
    PORT
      LAYER M5 ;
        RECT  102.636 0 102.66 0.192 ;
    END
  END k_lo_d[141]
  PIN k_lo_d[142]
    DIRECTION INPUT ;
    USE SIGNAL ;
    PORT
      LAYER M5 ;
        RECT  103.356 0 103.38 0.192 ;
    END
  END k_lo_d[142]
  PIN k_lo_d[143]
    DIRECTION INPUT ;
    USE SIGNAL ;
    PORT
      LAYER M5 ;
        RECT  104.076 0 104.1 0.192 ;
    END
  END k_lo_d[143]
  PIN k_lo_d[144]
    DIRECTION INPUT ;
    USE SIGNAL ;
    PORT
      LAYER M5 ;
        RECT  104.796 0 104.82 0.192 ;
    END
  END k_lo_d[144]
  PIN k_lo_d[145]
    DIRECTION INPUT ;
    USE SIGNAL ;
    PORT
      LAYER M5 ;
        RECT  105.468 0 105.492 0.192 ;
    END
  END k_lo_d[145]
  PIN k_lo_d[146]
    DIRECTION INPUT ;
    USE SIGNAL ;
    PORT
      LAYER M5 ;
        RECT  106.188 0 106.212 0.192 ;
    END
  END k_lo_d[146]
  PIN k_lo_d[147]
    DIRECTION INPUT ;
    USE SIGNAL ;
    PORT
      LAYER M5 ;
        RECT  106.908 0 106.932 0.192 ;
    END
  END k_lo_d[147]
  PIN k_lo_d[148]
    DIRECTION INPUT ;
    USE SIGNAL ;
    PORT
      LAYER M5 ;
        RECT  107.628 0 107.652 0.192 ;
    END
  END k_lo_d[148]
  PIN k_lo_d[149]
    DIRECTION INPUT ;
    USE SIGNAL ;
    PORT
      LAYER M5 ;
        RECT  108.3 0 108.324 0.192 ;
    END
  END k_lo_d[149]
  PIN k_lo_d[14]
    DIRECTION INPUT ;
    USE SIGNAL ;
    PORT
      LAYER M5 ;
        RECT  12.636 0 12.66 0.192 ;
    END
  END k_lo_d[14]
  PIN k_lo_d[150]
    DIRECTION INPUT ;
    USE SIGNAL ;
    PORT
      LAYER M5 ;
        RECT  109.02 0 109.044 0.192 ;
    END
  END k_lo_d[150]
  PIN k_lo_d[151]
    DIRECTION INPUT ;
    USE SIGNAL ;
    PORT
      LAYER M5 ;
        RECT  109.74 0 109.764 0.192 ;
    END
  END k_lo_d[151]
  PIN k_lo_d[152]
    DIRECTION INPUT ;
    USE SIGNAL ;
    PORT
      LAYER M5 ;
        RECT  110.46 0 110.484 0.192 ;
    END
  END k_lo_d[152]
  PIN k_lo_d[153]
    DIRECTION INPUT ;
    USE SIGNAL ;
    PORT
      LAYER M5 ;
        RECT  111.132 0 111.156 0.192 ;
    END
  END k_lo_d[153]
  PIN k_lo_d[154]
    DIRECTION INPUT ;
    USE SIGNAL ;
    PORT
      LAYER M5 ;
        RECT  111.852 0 111.876 0.192 ;
    END
  END k_lo_d[154]
  PIN k_lo_d[155]
    DIRECTION INPUT ;
    USE SIGNAL ;
    PORT
      LAYER M5 ;
        RECT  112.572 0 112.596 0.192 ;
    END
  END k_lo_d[155]
  PIN k_lo_d[156]
    DIRECTION INPUT ;
    USE SIGNAL ;
    PORT
      LAYER M5 ;
        RECT  113.292 0 113.316 0.192 ;
    END
  END k_lo_d[156]
  PIN k_lo_d[157]
    DIRECTION INPUT ;
    USE SIGNAL ;
    PORT
      LAYER M5 ;
        RECT  113.964 0 113.988 0.192 ;
    END
  END k_lo_d[157]
  PIN k_lo_d[158]
    DIRECTION INPUT ;
    USE SIGNAL ;
    PORT
      LAYER M5 ;
        RECT  114.684 0 114.708 0.192 ;
    END
  END k_lo_d[158]
  PIN k_lo_d[159]
    DIRECTION INPUT ;
    USE SIGNAL ;
    PORT
      LAYER M5 ;
        RECT  115.404 0 115.428 0.192 ;
    END
  END k_lo_d[159]
  PIN k_lo_d[15]
    DIRECTION INPUT ;
    USE SIGNAL ;
    PORT
      LAYER M5 ;
        RECT  13.356 0 13.38 0.192 ;
    END
  END k_lo_d[15]
  PIN k_lo_d[160]
    DIRECTION INPUT ;
    USE SIGNAL ;
    PORT
      LAYER M5 ;
        RECT  116.124 0 116.148 0.192 ;
    END
  END k_lo_d[160]
  PIN k_lo_d[161]
    DIRECTION INPUT ;
    USE SIGNAL ;
    PORT
      LAYER M5 ;
        RECT  116.844 0 116.868 0.192 ;
    END
  END k_lo_d[161]
  PIN k_lo_d[162]
    DIRECTION INPUT ;
    USE SIGNAL ;
    PORT
      LAYER M5 ;
        RECT  117.516 0 117.54 0.192 ;
    END
  END k_lo_d[162]
  PIN k_lo_d[163]
    DIRECTION INPUT ;
    USE SIGNAL ;
    PORT
      LAYER M5 ;
        RECT  118.236 0 118.26 0.192 ;
    END
  END k_lo_d[163]
  PIN k_lo_d[164]
    DIRECTION INPUT ;
    USE SIGNAL ;
    PORT
      LAYER M5 ;
        RECT  118.956 0 118.98 0.192 ;
    END
  END k_lo_d[164]
  PIN k_lo_d[165]
    DIRECTION INPUT ;
    USE SIGNAL ;
    PORT
      LAYER M5 ;
        RECT  119.676 0 119.7 0.192 ;
    END
  END k_lo_d[165]
  PIN k_lo_d[166]
    DIRECTION INPUT ;
    USE SIGNAL ;
    PORT
      LAYER M5 ;
        RECT  120.348 0 120.372 0.192 ;
    END
  END k_lo_d[166]
  PIN k_lo_d[167]
    DIRECTION INPUT ;
    USE SIGNAL ;
    PORT
      LAYER M5 ;
        RECT  121.068 0 121.092 0.192 ;
    END
  END k_lo_d[167]
  PIN k_lo_d[168]
    DIRECTION INPUT ;
    USE SIGNAL ;
    PORT
      LAYER M5 ;
        RECT  121.788 0 121.812 0.192 ;
    END
  END k_lo_d[168]
  PIN k_lo_d[169]
    DIRECTION INPUT ;
    USE SIGNAL ;
    PORT
      LAYER M5 ;
        RECT  122.508 0 122.532 0.192 ;
    END
  END k_lo_d[169]
  PIN k_lo_d[16]
    DIRECTION INPUT ;
    USE SIGNAL ;
    PORT
      LAYER M5 ;
        RECT  14.076 0 14.1 0.192 ;
    END
  END k_lo_d[16]
  PIN k_lo_d[170]
    DIRECTION INPUT ;
    USE SIGNAL ;
    PORT
      LAYER M5 ;
        RECT  123.18 0 123.204 0.192 ;
    END
  END k_lo_d[170]
  PIN k_lo_d[171]
    DIRECTION INPUT ;
    USE SIGNAL ;
    PORT
      LAYER M5 ;
        RECT  123.9 0 123.924 0.192 ;
    END
  END k_lo_d[171]
  PIN k_lo_d[172]
    DIRECTION INPUT ;
    USE SIGNAL ;
    PORT
      LAYER M5 ;
        RECT  124.62 0 124.644 0.192 ;
    END
  END k_lo_d[172]
  PIN k_lo_d[173]
    DIRECTION INPUT ;
    USE SIGNAL ;
    PORT
      LAYER M5 ;
        RECT  125.34 0 125.364 0.192 ;
    END
  END k_lo_d[173]
  PIN k_lo_d[174]
    DIRECTION INPUT ;
    USE SIGNAL ;
    PORT
      LAYER M5 ;
        RECT  126.06 0 126.084 0.192 ;
    END
  END k_lo_d[174]
  PIN k_lo_d[175]
    DIRECTION INPUT ;
    USE SIGNAL ;
    PORT
      LAYER M5 ;
        RECT  126.732 0 126.756 0.192 ;
    END
  END k_lo_d[175]
  PIN k_lo_d[176]
    DIRECTION INPUT ;
    USE SIGNAL ;
    PORT
      LAYER M5 ;
        RECT  127.452 0 127.476 0.192 ;
    END
  END k_lo_d[176]
  PIN k_lo_d[177]
    DIRECTION INPUT ;
    USE SIGNAL ;
    PORT
      LAYER M5 ;
        RECT  128.172 0 128.196 0.192 ;
    END
  END k_lo_d[177]
  PIN k_lo_d[178]
    DIRECTION INPUT ;
    USE SIGNAL ;
    PORT
      LAYER M5 ;
        RECT  128.892 0 128.916 0.192 ;
    END
  END k_lo_d[178]
  PIN k_lo_d[179]
    DIRECTION INPUT ;
    USE SIGNAL ;
    PORT
      LAYER M5 ;
        RECT  129.564 0 129.588 0.192 ;
    END
  END k_lo_d[179]
  PIN k_lo_d[17]
    DIRECTION INPUT ;
    USE SIGNAL ;
    PORT
      LAYER M5 ;
        RECT  14.748 0 14.772 0.192 ;
    END
  END k_lo_d[17]
  PIN k_lo_d[180]
    DIRECTION INPUT ;
    USE SIGNAL ;
    PORT
      LAYER M5 ;
        RECT  130.284 0 130.308 0.192 ;
    END
  END k_lo_d[180]
  PIN k_lo_d[181]
    DIRECTION INPUT ;
    USE SIGNAL ;
    PORT
      LAYER M5 ;
        RECT  131.004 0 131.028 0.192 ;
    END
  END k_lo_d[181]
  PIN k_lo_d[182]
    DIRECTION INPUT ;
    USE SIGNAL ;
    PORT
      LAYER M5 ;
        RECT  131.724 0 131.748 0.192 ;
    END
  END k_lo_d[182]
  PIN k_lo_d[183]
    DIRECTION INPUT ;
    USE SIGNAL ;
    PORT
      LAYER M5 ;
        RECT  132.396 0 132.42 0.192 ;
    END
  END k_lo_d[183]
  PIN k_lo_d[184]
    DIRECTION INPUT ;
    USE SIGNAL ;
    PORT
      LAYER M5 ;
        RECT  133.116 0 133.14 0.192 ;
    END
  END k_lo_d[184]
  PIN k_lo_d[185]
    DIRECTION INPUT ;
    USE SIGNAL ;
    PORT
      LAYER M5 ;
        RECT  133.836 0 133.86 0.192 ;
    END
  END k_lo_d[185]
  PIN k_lo_d[186]
    DIRECTION INPUT ;
    USE SIGNAL ;
    PORT
      LAYER M5 ;
        RECT  134.556 0 134.58 0.192 ;
    END
  END k_lo_d[186]
  PIN k_lo_d[187]
    DIRECTION INPUT ;
    USE SIGNAL ;
    PORT
      LAYER M5 ;
        RECT  135.228 0 135.252 0.192 ;
    END
  END k_lo_d[187]
  PIN k_lo_d[188]
    DIRECTION INPUT ;
    USE SIGNAL ;
    PORT
      LAYER M5 ;
        RECT  135.948 0 135.972 0.192 ;
    END
  END k_lo_d[188]
  PIN k_lo_d[189]
    DIRECTION INPUT ;
    USE SIGNAL ;
    PORT
      LAYER M5 ;
        RECT  136.668 0 136.692 0.192 ;
    END
  END k_lo_d[189]
  PIN k_lo_d[18]
    DIRECTION INPUT ;
    USE SIGNAL ;
    PORT
      LAYER M5 ;
        RECT  15.468 0 15.492 0.192 ;
    END
  END k_lo_d[18]
  PIN k_lo_d[190]
    DIRECTION INPUT ;
    USE SIGNAL ;
    PORT
      LAYER M5 ;
        RECT  137.388 0 137.412 0.192 ;
    END
  END k_lo_d[190]
  PIN k_lo_d[191]
    DIRECTION INPUT ;
    USE SIGNAL ;
    PORT
      LAYER M5 ;
        RECT  138.108 0 138.132 0.192 ;
    END
  END k_lo_d[191]
  PIN k_lo_d[192]
    DIRECTION INPUT ;
    USE SIGNAL ;
    PORT
      LAYER M5 ;
        RECT  138.78 0 138.804 0.192 ;
    END
  END k_lo_d[192]
  PIN k_lo_d[193]
    DIRECTION INPUT ;
    USE SIGNAL ;
    PORT
      LAYER M5 ;
        RECT  139.5 0 139.524 0.192 ;
    END
  END k_lo_d[193]
  PIN k_lo_d[194]
    DIRECTION INPUT ;
    USE SIGNAL ;
    PORT
      LAYER M5 ;
        RECT  140.22 0 140.244 0.192 ;
    END
  END k_lo_d[194]
  PIN k_lo_d[195]
    DIRECTION INPUT ;
    USE SIGNAL ;
    PORT
      LAYER M5 ;
        RECT  140.94 0 140.964 0.192 ;
    END
  END k_lo_d[195]
  PIN k_lo_d[196]
    DIRECTION INPUT ;
    USE SIGNAL ;
    PORT
      LAYER M5 ;
        RECT  141.612 0 141.636 0.192 ;
    END
  END k_lo_d[196]
  PIN k_lo_d[197]
    DIRECTION INPUT ;
    USE SIGNAL ;
    PORT
      LAYER M5 ;
        RECT  142.332 0 142.356 0.192 ;
    END
  END k_lo_d[197]
  PIN k_lo_d[198]
    DIRECTION INPUT ;
    USE SIGNAL ;
    PORT
      LAYER M5 ;
        RECT  143.052 0 143.076 0.192 ;
    END
  END k_lo_d[198]
  PIN k_lo_d[199]
    DIRECTION INPUT ;
    USE SIGNAL ;
    PORT
      LAYER M5 ;
        RECT  143.772 0 143.796 0.192 ;
    END
  END k_lo_d[199]
  PIN k_lo_d[19]
    DIRECTION INPUT ;
    USE SIGNAL ;
    PORT
      LAYER M5 ;
        RECT  16.188 0 16.212 0.192 ;
    END
  END k_lo_d[19]
  PIN k_lo_d[1]
    DIRECTION INPUT ;
    USE SIGNAL ;
    PORT
      LAYER M5 ;
        RECT  3.42 0 3.444 0.192 ;
    END
  END k_lo_d[1]
  PIN k_lo_d[200]
    DIRECTION INPUT ;
    USE SIGNAL ;
    PORT
      LAYER M5 ;
        RECT  144.444 0 144.468 0.192 ;
    END
  END k_lo_d[200]
  PIN k_lo_d[201]
    DIRECTION INPUT ;
    USE SIGNAL ;
    PORT
      LAYER M5 ;
        RECT  145.164 0 145.188 0.192 ;
    END
  END k_lo_d[201]
  PIN k_lo_d[202]
    DIRECTION INPUT ;
    USE SIGNAL ;
    PORT
      LAYER M5 ;
        RECT  145.884 0 145.908 0.192 ;
    END
  END k_lo_d[202]
  PIN k_lo_d[203]
    DIRECTION INPUT ;
    USE SIGNAL ;
    PORT
      LAYER M5 ;
        RECT  146.604 0 146.628 0.192 ;
    END
  END k_lo_d[203]
  PIN k_lo_d[204]
    DIRECTION INPUT ;
    USE SIGNAL ;
    PORT
      LAYER M5 ;
        RECT  147.276 0 147.3 0.192 ;
    END
  END k_lo_d[204]
  PIN k_lo_d[205]
    DIRECTION INPUT ;
    USE SIGNAL ;
    PORT
      LAYER M5 ;
        RECT  147.996 0 148.02 0.192 ;
    END
  END k_lo_d[205]
  PIN k_lo_d[206]
    DIRECTION INPUT ;
    USE SIGNAL ;
    PORT
      LAYER M5 ;
        RECT  148.716 0 148.74 0.192 ;
    END
  END k_lo_d[206]
  PIN k_lo_d[207]
    DIRECTION INPUT ;
    USE SIGNAL ;
    PORT
      LAYER M5 ;
        RECT  149.436 0 149.46 0.192 ;
    END
  END k_lo_d[207]
  PIN k_lo_d[208]
    DIRECTION INPUT ;
    USE SIGNAL ;
    PORT
      LAYER M5 ;
        RECT  150.156 0 150.18 0.192 ;
    END
  END k_lo_d[208]
  PIN k_lo_d[209]
    DIRECTION INPUT ;
    USE SIGNAL ;
    PORT
      LAYER M5 ;
        RECT  150.828 0 150.852 0.192 ;
    END
  END k_lo_d[209]
  PIN k_lo_d[20]
    DIRECTION INPUT ;
    USE SIGNAL ;
    PORT
      LAYER M5 ;
        RECT  16.908 0 16.932 0.192 ;
    END
  END k_lo_d[20]
  PIN k_lo_d[210]
    DIRECTION INPUT ;
    USE SIGNAL ;
    PORT
      LAYER M5 ;
        RECT  151.548 0 151.572 0.192 ;
    END
  END k_lo_d[210]
  PIN k_lo_d[211]
    DIRECTION INPUT ;
    USE SIGNAL ;
    PORT
      LAYER M5 ;
        RECT  152.268 0 152.292 0.192 ;
    END
  END k_lo_d[211]
  PIN k_lo_d[212]
    DIRECTION INPUT ;
    USE SIGNAL ;
    PORT
      LAYER M5 ;
        RECT  152.988 0 153.012 0.192 ;
    END
  END k_lo_d[212]
  PIN k_lo_d[213]
    DIRECTION INPUT ;
    USE SIGNAL ;
    PORT
      LAYER M5 ;
        RECT  153.66 0 153.684 0.192 ;
    END
  END k_lo_d[213]
  PIN k_lo_d[214]
    DIRECTION INPUT ;
    USE SIGNAL ;
    PORT
      LAYER M5 ;
        RECT  154.38 0 154.404 0.192 ;
    END
  END k_lo_d[214]
  PIN k_lo_d[215]
    DIRECTION INPUT ;
    USE SIGNAL ;
    PORT
      LAYER M5 ;
        RECT  155.1 0 155.124 0.192 ;
    END
  END k_lo_d[215]
  PIN k_lo_d[216]
    DIRECTION INPUT ;
    USE SIGNAL ;
    PORT
      LAYER M5 ;
        RECT  155.82 0 155.844 0.192 ;
    END
  END k_lo_d[216]
  PIN k_lo_d[217]
    DIRECTION INPUT ;
    USE SIGNAL ;
    PORT
      LAYER M5 ;
        RECT  156.492 0 156.516 0.192 ;
    END
  END k_lo_d[217]
  PIN k_lo_d[218]
    DIRECTION INPUT ;
    USE SIGNAL ;
    PORT
      LAYER M5 ;
        RECT  157.212 0 157.236 0.192 ;
    END
  END k_lo_d[218]
  PIN k_lo_d[219]
    DIRECTION INPUT ;
    USE SIGNAL ;
    PORT
      LAYER M5 ;
        RECT  157.932 0 157.956 0.192 ;
    END
  END k_lo_d[219]
  PIN k_lo_d[21]
    DIRECTION INPUT ;
    USE SIGNAL ;
    PORT
      LAYER M5 ;
        RECT  17.58 0 17.604 0.192 ;
    END
  END k_lo_d[21]
  PIN k_lo_d[220]
    DIRECTION INPUT ;
    USE SIGNAL ;
    PORT
      LAYER M5 ;
        RECT  158.652 0 158.676 0.192 ;
    END
  END k_lo_d[220]
  PIN k_lo_d[221]
    DIRECTION INPUT ;
    USE SIGNAL ;
    PORT
      LAYER M5 ;
        RECT  159.372 0 159.396 0.192 ;
    END
  END k_lo_d[221]
  PIN k_lo_d[222]
    DIRECTION INPUT ;
    USE SIGNAL ;
    PORT
      LAYER M5 ;
        RECT  160.044 0 160.068 0.192 ;
    END
  END k_lo_d[222]
  PIN k_lo_d[223]
    DIRECTION INPUT ;
    USE SIGNAL ;
    PORT
      LAYER M5 ;
        RECT  160.764 0 160.788 0.192 ;
    END
  END k_lo_d[223]
  PIN k_lo_d[224]
    DIRECTION INPUT ;
    USE SIGNAL ;
    PORT
      LAYER M5 ;
        RECT  161.484 0 161.508 0.192 ;
    END
  END k_lo_d[224]
  PIN k_lo_d[225]
    DIRECTION INPUT ;
    USE SIGNAL ;
    PORT
      LAYER M5 ;
        RECT  162.204 0 162.228 0.192 ;
    END
  END k_lo_d[225]
  PIN k_lo_d[226]
    DIRECTION INPUT ;
    USE SIGNAL ;
    PORT
      LAYER M5 ;
        RECT  162.876 0 162.9 0.192 ;
    END
  END k_lo_d[226]
  PIN k_lo_d[227]
    DIRECTION INPUT ;
    USE SIGNAL ;
    PORT
      LAYER M5 ;
        RECT  163.596 0 163.62 0.192 ;
    END
  END k_lo_d[227]
  PIN k_lo_d[228]
    DIRECTION INPUT ;
    USE SIGNAL ;
    PORT
      LAYER M5 ;
        RECT  164.316 0 164.34 0.192 ;
    END
  END k_lo_d[228]
  PIN k_lo_d[229]
    DIRECTION INPUT ;
    USE SIGNAL ;
    PORT
      LAYER M5 ;
        RECT  165.036 0 165.06 0.192 ;
    END
  END k_lo_d[229]
  PIN k_lo_d[22]
    DIRECTION INPUT ;
    USE SIGNAL ;
    PORT
      LAYER M5 ;
        RECT  18.3 0 18.324 0.192 ;
    END
  END k_lo_d[22]
  PIN k_lo_d[230]
    DIRECTION INPUT ;
    USE SIGNAL ;
    PORT
      LAYER M5 ;
        RECT  165.708 0 165.732 0.192 ;
    END
  END k_lo_d[230]
  PIN k_lo_d[231]
    DIRECTION INPUT ;
    USE SIGNAL ;
    PORT
      LAYER M5 ;
        RECT  166.428 0 166.452 0.192 ;
    END
  END k_lo_d[231]
  PIN k_lo_d[232]
    DIRECTION INPUT ;
    USE SIGNAL ;
    PORT
      LAYER M5 ;
        RECT  167.148 0 167.172 0.192 ;
    END
  END k_lo_d[232]
  PIN k_lo_d[233]
    DIRECTION INPUT ;
    USE SIGNAL ;
    PORT
      LAYER M5 ;
        RECT  167.868 0 167.892 0.192 ;
    END
  END k_lo_d[233]
  PIN k_lo_d[234]
    DIRECTION INPUT ;
    USE SIGNAL ;
    PORT
      LAYER M5 ;
        RECT  168.54 0 168.564 0.192 ;
    END
  END k_lo_d[234]
  PIN k_lo_d[235]
    DIRECTION INPUT ;
    USE SIGNAL ;
    PORT
      LAYER M5 ;
        RECT  169.26 0 169.284 0.192 ;
    END
  END k_lo_d[235]
  PIN k_lo_d[236]
    DIRECTION INPUT ;
    USE SIGNAL ;
    PORT
      LAYER M5 ;
        RECT  169.98 0 170.004 0.192 ;
    END
  END k_lo_d[236]
  PIN k_lo_d[237]
    DIRECTION INPUT ;
    USE SIGNAL ;
    PORT
      LAYER M5 ;
        RECT  170.7 0 170.724 0.192 ;
    END
  END k_lo_d[237]
  PIN k_lo_d[238]
    DIRECTION INPUT ;
    USE SIGNAL ;
    PORT
      LAYER M5 ;
        RECT  171.42 0 171.444 0.192 ;
    END
  END k_lo_d[238]
  PIN k_lo_d[239]
    DIRECTION INPUT ;
    USE SIGNAL ;
    PORT
      LAYER M5 ;
        RECT  172.092 0 172.116 0.192 ;
    END
  END k_lo_d[239]
  PIN k_lo_d[23]
    DIRECTION INPUT ;
    USE SIGNAL ;
    PORT
      LAYER M5 ;
        RECT  19.02 0 19.044 0.192 ;
    END
  END k_lo_d[23]
  PIN k_lo_d[240]
    DIRECTION INPUT ;
    USE SIGNAL ;
    PORT
      LAYER M5 ;
        RECT  172.812 0 172.836 0.192 ;
    END
  END k_lo_d[240]
  PIN k_lo_d[241]
    DIRECTION INPUT ;
    USE SIGNAL ;
    PORT
      LAYER M5 ;
        RECT  173.532 0 173.556 0.192 ;
    END
  END k_lo_d[241]
  PIN k_lo_d[242]
    DIRECTION INPUT ;
    USE SIGNAL ;
    PORT
      LAYER M5 ;
        RECT  174.252 0 174.276 0.192 ;
    END
  END k_lo_d[242]
  PIN k_lo_d[243]
    DIRECTION INPUT ;
    USE SIGNAL ;
    PORT
      LAYER M5 ;
        RECT  174.924 0 174.948 0.192 ;
    END
  END k_lo_d[243]
  PIN k_lo_d[244]
    DIRECTION INPUT ;
    USE SIGNAL ;
    PORT
      LAYER M5 ;
        RECT  175.644 0 175.668 0.192 ;
    END
  END k_lo_d[244]
  PIN k_lo_d[245]
    DIRECTION INPUT ;
    USE SIGNAL ;
    PORT
      LAYER M5 ;
        RECT  176.364 0 176.388 0.192 ;
    END
  END k_lo_d[245]
  PIN k_lo_d[246]
    DIRECTION INPUT ;
    USE SIGNAL ;
    PORT
      LAYER M5 ;
        RECT  177.084 0 177.108 0.192 ;
    END
  END k_lo_d[246]
  PIN k_lo_d[247]
    DIRECTION INPUT ;
    USE SIGNAL ;
    PORT
      LAYER M5 ;
        RECT  177.756 0 177.78 0.192 ;
    END
  END k_lo_d[247]
  PIN k_lo_d[248]
    DIRECTION INPUT ;
    USE SIGNAL ;
    PORT
      LAYER M5 ;
        RECT  178.476 0 178.5 0.192 ;
    END
  END k_lo_d[248]
  PIN k_lo_d[249]
    DIRECTION INPUT ;
    USE SIGNAL ;
    PORT
      LAYER M5 ;
        RECT  179.196 0 179.22 0.192 ;
    END
  END k_lo_d[249]
  PIN k_lo_d[24]
    DIRECTION INPUT ;
    USE SIGNAL ;
    PORT
      LAYER M5 ;
        RECT  19.74 0 19.764 0.192 ;
    END
  END k_lo_d[24]
  PIN k_lo_d[250]
    DIRECTION INPUT ;
    USE SIGNAL ;
    PORT
      LAYER M5 ;
        RECT  179.916 0 179.94 0.192 ;
    END
  END k_lo_d[250]
  PIN k_lo_d[251]
    DIRECTION INPUT ;
    USE SIGNAL ;
    PORT
      LAYER M5 ;
        RECT  180.588 0 180.612 0.192 ;
    END
  END k_lo_d[251]
  PIN k_lo_d[252]
    DIRECTION INPUT ;
    USE SIGNAL ;
    PORT
      LAYER M5 ;
        RECT  181.308 0 181.332 0.192 ;
    END
  END k_lo_d[252]
  PIN k_lo_d[253]
    DIRECTION INPUT ;
    USE SIGNAL ;
    PORT
      LAYER M5 ;
        RECT  182.028 0 182.052 0.192 ;
    END
  END k_lo_d[253]
  PIN k_lo_d[254]
    DIRECTION INPUT ;
    USE SIGNAL ;
    PORT
      LAYER M5 ;
        RECT  182.748 0 182.772 0.192 ;
    END
  END k_lo_d[254]
  PIN k_lo_d[255]
    DIRECTION INPUT ;
    USE SIGNAL ;
    PORT
      LAYER M5 ;
        RECT  183.468 0 183.492 0.192 ;
    END
  END k_lo_d[255]
  PIN k_lo_d[256]
    DIRECTION INPUT ;
    USE SIGNAL ;
    PORT
      LAYER M5 ;
        RECT  184.14 0 184.164 0.192 ;
    END
  END k_lo_d[256]
  PIN k_lo_d[257]
    DIRECTION INPUT ;
    USE SIGNAL ;
    PORT
      LAYER M5 ;
        RECT  184.86 0 184.884 0.192 ;
    END
  END k_lo_d[257]
  PIN k_lo_d[258]
    DIRECTION INPUT ;
    USE SIGNAL ;
    PORT
      LAYER M5 ;
        RECT  185.58 0 185.604 0.192 ;
    END
  END k_lo_d[258]
  PIN k_lo_d[259]
    DIRECTION INPUT ;
    USE SIGNAL ;
    PORT
      LAYER M5 ;
        RECT  186.3 0 186.324 0.192 ;
    END
  END k_lo_d[259]
  PIN k_lo_d[25]
    DIRECTION INPUT ;
    USE SIGNAL ;
    PORT
      LAYER M5 ;
        RECT  20.412 0 20.436 0.192 ;
    END
  END k_lo_d[25]
  PIN k_lo_d[260]
    DIRECTION INPUT ;
    USE SIGNAL ;
    PORT
      LAYER M5 ;
        RECT  186.972 0 186.996 0.192 ;
    END
  END k_lo_d[260]
  PIN k_lo_d[261]
    DIRECTION INPUT ;
    USE SIGNAL ;
    PORT
      LAYER M5 ;
        RECT  187.692 0 187.716 0.192 ;
    END
  END k_lo_d[261]
  PIN k_lo_d[262]
    DIRECTION INPUT ;
    USE SIGNAL ;
    PORT
      LAYER M5 ;
        RECT  188.412 0 188.436 0.192 ;
    END
  END k_lo_d[262]
  PIN k_lo_d[263]
    DIRECTION INPUT ;
    USE SIGNAL ;
    PORT
      LAYER M5 ;
        RECT  189.132 0 189.156 0.192 ;
    END
  END k_lo_d[263]
  PIN k_lo_d[264]
    DIRECTION INPUT ;
    USE SIGNAL ;
    PORT
      LAYER M5 ;
        RECT  189.804 0 189.828 0.192 ;
    END
  END k_lo_d[264]
  PIN k_lo_d[265]
    DIRECTION INPUT ;
    USE SIGNAL ;
    PORT
      LAYER M5 ;
        RECT  190.524 0 190.548 0.192 ;
    END
  END k_lo_d[265]
  PIN k_lo_d[266]
    DIRECTION INPUT ;
    USE SIGNAL ;
    PORT
      LAYER M5 ;
        RECT  191.244 0 191.268 0.192 ;
    END
  END k_lo_d[266]
  PIN k_lo_d[267]
    DIRECTION INPUT ;
    USE SIGNAL ;
    PORT
      LAYER M5 ;
        RECT  191.964 0 191.988 0.192 ;
    END
  END k_lo_d[267]
  PIN k_lo_d[268]
    DIRECTION INPUT ;
    USE SIGNAL ;
    PORT
      LAYER M5 ;
        RECT  192.636 0 192.66 0.192 ;
    END
  END k_lo_d[268]
  PIN k_lo_d[269]
    DIRECTION INPUT ;
    USE SIGNAL ;
    PORT
      LAYER M5 ;
        RECT  193.356 0 193.38 0.192 ;
    END
  END k_lo_d[269]
  PIN k_lo_d[26]
    DIRECTION INPUT ;
    USE SIGNAL ;
    PORT
      LAYER M5 ;
        RECT  21.132 0 21.156 0.192 ;
    END
  END k_lo_d[26]
  PIN k_lo_d[270]
    DIRECTION INPUT ;
    USE SIGNAL ;
    PORT
      LAYER M5 ;
        RECT  194.076 0 194.1 0.192 ;
    END
  END k_lo_d[270]
  PIN k_lo_d[271]
    DIRECTION INPUT ;
    USE SIGNAL ;
    PORT
      LAYER M5 ;
        RECT  194.796 0 194.82 0.192 ;
    END
  END k_lo_d[271]
  PIN k_lo_d[272]
    DIRECTION INPUT ;
    USE SIGNAL ;
    PORT
      LAYER M5 ;
        RECT  195.516 0 195.54 0.192 ;
    END
  END k_lo_d[272]
  PIN k_lo_d[273]
    DIRECTION INPUT ;
    USE SIGNAL ;
    PORT
      LAYER M5 ;
        RECT  196.188 0 196.212 0.192 ;
    END
  END k_lo_d[273]
  PIN k_lo_d[274]
    DIRECTION INPUT ;
    USE SIGNAL ;
    PORT
      LAYER M5 ;
        RECT  196.908 0 196.932 0.192 ;
    END
  END k_lo_d[274]
  PIN k_lo_d[275]
    DIRECTION INPUT ;
    USE SIGNAL ;
    PORT
      LAYER M5 ;
        RECT  197.628 0 197.652 0.192 ;
    END
  END k_lo_d[275]
  PIN k_lo_d[276]
    DIRECTION INPUT ;
    USE SIGNAL ;
    PORT
      LAYER M5 ;
        RECT  198.348 0 198.372 0.192 ;
    END
  END k_lo_d[276]
  PIN k_lo_d[277]
    DIRECTION INPUT ;
    USE SIGNAL ;
    PORT
      LAYER M5 ;
        RECT  199.02 0 199.044 0.192 ;
    END
  END k_lo_d[277]
  PIN k_lo_d[278]
    DIRECTION INPUT ;
    USE SIGNAL ;
    PORT
      LAYER M5 ;
        RECT  199.74 0 199.764 0.192 ;
    END
  END k_lo_d[278]
  PIN k_lo_d[279]
    DIRECTION INPUT ;
    USE SIGNAL ;
    PORT
      LAYER M5 ;
        RECT  200.46 0 200.484 0.192 ;
    END
  END k_lo_d[279]
  PIN k_lo_d[27]
    DIRECTION INPUT ;
    USE SIGNAL ;
    PORT
      LAYER M5 ;
        RECT  21.852 0 21.876 0.192 ;
    END
  END k_lo_d[27]
  PIN k_lo_d[280]
    DIRECTION INPUT ;
    USE SIGNAL ;
    PORT
      LAYER M5 ;
        RECT  201.18 0 201.204 0.192 ;
    END
  END k_lo_d[280]
  PIN k_lo_d[281]
    DIRECTION INPUT ;
    USE SIGNAL ;
    PORT
      LAYER M5 ;
        RECT  201.852 0 201.876 0.192 ;
    END
  END k_lo_d[281]
  PIN k_lo_d[282]
    DIRECTION INPUT ;
    USE SIGNAL ;
    PORT
      LAYER M5 ;
        RECT  202.572 0 202.596 0.192 ;
    END
  END k_lo_d[282]
  PIN k_lo_d[283]
    DIRECTION INPUT ;
    USE SIGNAL ;
    PORT
      LAYER M5 ;
        RECT  203.292 0 203.316 0.192 ;
    END
  END k_lo_d[283]
  PIN k_lo_d[284]
    DIRECTION INPUT ;
    USE SIGNAL ;
    PORT
      LAYER M5 ;
        RECT  204.012 0 204.036 0.192 ;
    END
  END k_lo_d[284]
  PIN k_lo_d[285]
    DIRECTION INPUT ;
    USE SIGNAL ;
    PORT
      LAYER M5 ;
        RECT  204.732 0 204.756 0.192 ;
    END
  END k_lo_d[285]
  PIN k_lo_d[286]
    DIRECTION INPUT ;
    USE SIGNAL ;
    PORT
      LAYER M5 ;
        RECT  205.404 0 205.428 0.192 ;
    END
  END k_lo_d[286]
  PIN k_lo_d[287]
    DIRECTION INPUT ;
    USE SIGNAL ;
    PORT
      LAYER M5 ;
        RECT  206.124 0 206.148 0.192 ;
    END
  END k_lo_d[287]
  PIN k_lo_d[288]
    DIRECTION INPUT ;
    USE SIGNAL ;
    PORT
      LAYER M5 ;
        RECT  206.844 0 206.868 0.192 ;
    END
  END k_lo_d[288]
  PIN k_lo_d[289]
    DIRECTION INPUT ;
    USE SIGNAL ;
    PORT
      LAYER M5 ;
        RECT  207.564 0 207.588 0.192 ;
    END
  END k_lo_d[289]
  PIN k_lo_d[28]
    DIRECTION INPUT ;
    USE SIGNAL ;
    PORT
      LAYER M5 ;
        RECT  22.572 0 22.596 0.192 ;
    END
  END k_lo_d[28]
  PIN k_lo_d[290]
    DIRECTION INPUT ;
    USE SIGNAL ;
    PORT
      LAYER M5 ;
        RECT  208.236 0 208.26 0.192 ;
    END
  END k_lo_d[290]
  PIN k_lo_d[291]
    DIRECTION INPUT ;
    USE SIGNAL ;
    PORT
      LAYER M5 ;
        RECT  208.956 0 208.98 0.192 ;
    END
  END k_lo_d[291]
  PIN k_lo_d[292]
    DIRECTION INPUT ;
    USE SIGNAL ;
    PORT
      LAYER M5 ;
        RECT  209.676 0 209.7 0.192 ;
    END
  END k_lo_d[292]
  PIN k_lo_d[293]
    DIRECTION INPUT ;
    USE SIGNAL ;
    PORT
      LAYER M5 ;
        RECT  210.396 0 210.42 0.192 ;
    END
  END k_lo_d[293]
  PIN k_lo_d[294]
    DIRECTION INPUT ;
    USE SIGNAL ;
    PORT
      LAYER M5 ;
        RECT  211.068 0 211.092 0.192 ;
    END
  END k_lo_d[294]
  PIN k_lo_d[295]
    DIRECTION INPUT ;
    USE SIGNAL ;
    PORT
      LAYER M5 ;
        RECT  211.788 0 211.812 0.192 ;
    END
  END k_lo_d[295]
  PIN k_lo_d[296]
    DIRECTION INPUT ;
    USE SIGNAL ;
    PORT
      LAYER M5 ;
        RECT  212.508 0 212.532 0.192 ;
    END
  END k_lo_d[296]
  PIN k_lo_d[297]
    DIRECTION INPUT ;
    USE SIGNAL ;
    PORT
      LAYER M5 ;
        RECT  213.228 0 213.252 0.192 ;
    END
  END k_lo_d[297]
  PIN k_lo_d[298]
    DIRECTION INPUT ;
    USE SIGNAL ;
    PORT
      LAYER M5 ;
        RECT  213.9 0 213.924 0.192 ;
    END
  END k_lo_d[298]
  PIN k_lo_d[299]
    DIRECTION INPUT ;
    USE SIGNAL ;
    PORT
      LAYER M5 ;
        RECT  214.62 0 214.644 0.192 ;
    END
  END k_lo_d[299]
  PIN k_lo_d[29]
    DIRECTION INPUT ;
    USE SIGNAL ;
    PORT
      LAYER M5 ;
        RECT  23.244 0 23.268 0.192 ;
    END
  END k_lo_d[29]
  PIN k_lo_d[2]
    DIRECTION INPUT ;
    USE SIGNAL ;
    PORT
      LAYER M5 ;
        RECT  4.14 0 4.164 0.192 ;
    END
  END k_lo_d[2]
  PIN k_lo_d[300]
    DIRECTION INPUT ;
    USE SIGNAL ;
    PORT
      LAYER M5 ;
        RECT  215.34 0 215.364 0.192 ;
    END
  END k_lo_d[300]
  PIN k_lo_d[301]
    DIRECTION INPUT ;
    USE SIGNAL ;
    PORT
      LAYER M5 ;
        RECT  216.06 0 216.084 0.192 ;
    END
  END k_lo_d[301]
  PIN k_lo_d[302]
    DIRECTION INPUT ;
    USE SIGNAL ;
    PORT
      LAYER M5 ;
        RECT  216.78 0 216.804 0.192 ;
    END
  END k_lo_d[302]
  PIN k_lo_d[303]
    DIRECTION INPUT ;
    USE SIGNAL ;
    PORT
      LAYER M5 ;
        RECT  217.452 0 217.476 0.192 ;
    END
  END k_lo_d[303]
  PIN k_lo_d[304]
    DIRECTION INPUT ;
    USE SIGNAL ;
    PORT
      LAYER M5 ;
        RECT  218.172 0 218.196 0.192 ;
    END
  END k_lo_d[304]
  PIN k_lo_d[305]
    DIRECTION INPUT ;
    USE SIGNAL ;
    PORT
      LAYER M5 ;
        RECT  218.892 0 218.916 0.192 ;
    END
  END k_lo_d[305]
  PIN k_lo_d[306]
    DIRECTION INPUT ;
    USE SIGNAL ;
    PORT
      LAYER M5 ;
        RECT  219.612 0 219.636 0.192 ;
    END
  END k_lo_d[306]
  PIN k_lo_d[307]
    DIRECTION INPUT ;
    USE SIGNAL ;
    PORT
      LAYER M5 ;
        RECT  220.284 0 220.308 0.192 ;
    END
  END k_lo_d[307]
  PIN k_lo_d[308]
    DIRECTION INPUT ;
    USE SIGNAL ;
    PORT
      LAYER M5 ;
        RECT  221.004 0 221.028 0.192 ;
    END
  END k_lo_d[308]
  PIN k_lo_d[309]
    DIRECTION INPUT ;
    USE SIGNAL ;
    PORT
      LAYER M5 ;
        RECT  221.724 0 221.748 0.192 ;
    END
  END k_lo_d[309]
  PIN k_lo_d[30]
    DIRECTION INPUT ;
    USE SIGNAL ;
    PORT
      LAYER M5 ;
        RECT  23.964 0 23.988 0.192 ;
    END
  END k_lo_d[30]
  PIN k_lo_d[310]
    DIRECTION INPUT ;
    USE SIGNAL ;
    PORT
      LAYER M5 ;
        RECT  222.444 0 222.468 0.192 ;
    END
  END k_lo_d[310]
  PIN k_lo_d[311]
    DIRECTION INPUT ;
    USE SIGNAL ;
    PORT
      LAYER M5 ;
        RECT  223.116 0 223.14 0.192 ;
    END
  END k_lo_d[311]
  PIN k_lo_d[312]
    DIRECTION INPUT ;
    USE SIGNAL ;
    PORT
      LAYER M5 ;
        RECT  223.836 0 223.86 0.192 ;
    END
  END k_lo_d[312]
  PIN k_lo_d[313]
    DIRECTION INPUT ;
    USE SIGNAL ;
    PORT
      LAYER M5 ;
        RECT  224.556 0 224.58 0.192 ;
    END
  END k_lo_d[313]
  PIN k_lo_d[314]
    DIRECTION INPUT ;
    USE SIGNAL ;
    PORT
      LAYER M5 ;
        RECT  225.276 0 225.3 0.192 ;
    END
  END k_lo_d[314]
  PIN k_lo_d[315]
    DIRECTION INPUT ;
    USE SIGNAL ;
    PORT
      LAYER M5 ;
        RECT  225.948 0 225.972 0.192 ;
    END
  END k_lo_d[315]
  PIN k_lo_d[316]
    DIRECTION INPUT ;
    USE SIGNAL ;
    PORT
      LAYER M5 ;
        RECT  226.668 0 226.692 0.192 ;
    END
  END k_lo_d[316]
  PIN k_lo_d[317]
    DIRECTION INPUT ;
    USE SIGNAL ;
    PORT
      LAYER M5 ;
        RECT  227.388 0 227.412 0.192 ;
    END
  END k_lo_d[317]
  PIN k_lo_d[318]
    DIRECTION INPUT ;
    USE SIGNAL ;
    PORT
      LAYER M5 ;
        RECT  228.108 0 228.132 0.192 ;
    END
  END k_lo_d[318]
  PIN k_lo_d[319]
    DIRECTION INPUT ;
    USE SIGNAL ;
    PORT
      LAYER M5 ;
        RECT  228.828 0 228.852 0.192 ;
    END
  END k_lo_d[319]
  PIN k_lo_d[31]
    DIRECTION INPUT ;
    USE SIGNAL ;
    PORT
      LAYER M5 ;
        RECT  24.684 0 24.708 0.192 ;
    END
  END k_lo_d[31]
  PIN k_lo_d[320]
    DIRECTION INPUT ;
    USE SIGNAL ;
    PORT
      LAYER M5 ;
        RECT  229.5 0 229.524 0.192 ;
    END
  END k_lo_d[320]
  PIN k_lo_d[321]
    DIRECTION INPUT ;
    USE SIGNAL ;
    PORT
      LAYER M5 ;
        RECT  230.22 0 230.244 0.192 ;
    END
  END k_lo_d[321]
  PIN k_lo_d[322]
    DIRECTION INPUT ;
    USE SIGNAL ;
    PORT
      LAYER M5 ;
        RECT  230.94 0 230.964 0.192 ;
    END
  END k_lo_d[322]
  PIN k_lo_d[323]
    DIRECTION INPUT ;
    USE SIGNAL ;
    PORT
      LAYER M5 ;
        RECT  231.66 0 231.684 0.192 ;
    END
  END k_lo_d[323]
  PIN k_lo_d[324]
    DIRECTION INPUT ;
    USE SIGNAL ;
    PORT
      LAYER M5 ;
        RECT  232.332 0 232.356 0.192 ;
    END
  END k_lo_d[324]
  PIN k_lo_d[325]
    DIRECTION INPUT ;
    USE SIGNAL ;
    PORT
      LAYER M5 ;
        RECT  233.052 0 233.076 0.192 ;
    END
  END k_lo_d[325]
  PIN k_lo_d[326]
    DIRECTION INPUT ;
    USE SIGNAL ;
    PORT
      LAYER M5 ;
        RECT  233.772 0 233.796 0.192 ;
    END
  END k_lo_d[326]
  PIN k_lo_d[327]
    DIRECTION INPUT ;
    USE SIGNAL ;
    PORT
      LAYER M5 ;
        RECT  234.492 0 234.516 0.192 ;
    END
  END k_lo_d[327]
  PIN k_lo_d[328]
    DIRECTION INPUT ;
    USE SIGNAL ;
    PORT
      LAYER M5 ;
        RECT  235.164 0 235.188 0.192 ;
    END
  END k_lo_d[328]
  PIN k_lo_d[329]
    DIRECTION INPUT ;
    USE SIGNAL ;
    PORT
      LAYER M5 ;
        RECT  235.884 0 235.908 0.192 ;
    END
  END k_lo_d[329]
  PIN k_lo_d[32]
    DIRECTION INPUT ;
    USE SIGNAL ;
    PORT
      LAYER M5 ;
        RECT  25.404 0 25.428 0.192 ;
    END
  END k_lo_d[32]
  PIN k_lo_d[330]
    DIRECTION INPUT ;
    USE SIGNAL ;
    PORT
      LAYER M5 ;
        RECT  236.604 0 236.628 0.192 ;
    END
  END k_lo_d[330]
  PIN k_lo_d[331]
    DIRECTION INPUT ;
    USE SIGNAL ;
    PORT
      LAYER M5 ;
        RECT  237.324 0 237.348 0.192 ;
    END
  END k_lo_d[331]
  PIN k_lo_d[332]
    DIRECTION INPUT ;
    USE SIGNAL ;
    PORT
      LAYER M5 ;
        RECT  238.044 0 238.068 0.192 ;
    END
  END k_lo_d[332]
  PIN k_lo_d[333]
    DIRECTION INPUT ;
    USE SIGNAL ;
    PORT
      LAYER M5 ;
        RECT  238.716 0 238.74 0.192 ;
    END
  END k_lo_d[333]
  PIN k_lo_d[334]
    DIRECTION INPUT ;
    USE SIGNAL ;
    PORT
      LAYER M5 ;
        RECT  239.436 0 239.46 0.192 ;
    END
  END k_lo_d[334]
  PIN k_lo_d[335]
    DIRECTION INPUT ;
    USE SIGNAL ;
    PORT
      LAYER M5 ;
        RECT  240.156 0 240.18 0.192 ;
    END
  END k_lo_d[335]
  PIN k_lo_d[336]
    DIRECTION INPUT ;
    USE SIGNAL ;
    PORT
      LAYER M5 ;
        RECT  240.876 0 240.9 0.192 ;
    END
  END k_lo_d[336]
  PIN k_lo_d[337]
    DIRECTION INPUT ;
    USE SIGNAL ;
    PORT
      LAYER M5 ;
        RECT  241.548 0 241.572 0.192 ;
    END
  END k_lo_d[337]
  PIN k_lo_d[338]
    DIRECTION INPUT ;
    USE SIGNAL ;
    PORT
      LAYER M5 ;
        RECT  242.268 0 242.292 0.192 ;
    END
  END k_lo_d[338]
  PIN k_lo_d[339]
    DIRECTION INPUT ;
    USE SIGNAL ;
    PORT
      LAYER M5 ;
        RECT  242.988 0 243.012 0.192 ;
    END
  END k_lo_d[339]
  PIN k_lo_d[33]
    DIRECTION INPUT ;
    USE SIGNAL ;
    PORT
      LAYER M5 ;
        RECT  26.124 0 26.148 0.192 ;
    END
  END k_lo_d[33]
  PIN k_lo_d[340]
    DIRECTION INPUT ;
    USE SIGNAL ;
    PORT
      LAYER M5 ;
        RECT  243.708 0 243.732 0.192 ;
    END
  END k_lo_d[340]
  PIN k_lo_d[341]
    DIRECTION INPUT ;
    USE SIGNAL ;
    PORT
      LAYER M5 ;
        RECT  244.38 0 244.404 0.192 ;
    END
  END k_lo_d[341]
  PIN k_lo_d[342]
    DIRECTION INPUT ;
    USE SIGNAL ;
    PORT
      LAYER M5 ;
        RECT  245.1 0 245.124 0.192 ;
    END
  END k_lo_d[342]
  PIN k_lo_d[343]
    DIRECTION INPUT ;
    USE SIGNAL ;
    PORT
      LAYER M5 ;
        RECT  245.82 0 245.844 0.192 ;
    END
  END k_lo_d[343]
  PIN k_lo_d[344]
    DIRECTION INPUT ;
    USE SIGNAL ;
    PORT
      LAYER M5 ;
        RECT  246.54 0 246.564 0.192 ;
    END
  END k_lo_d[344]
  PIN k_lo_d[345]
    DIRECTION INPUT ;
    USE SIGNAL ;
    PORT
      LAYER M5 ;
        RECT  247.212 0 247.236 0.192 ;
    END
  END k_lo_d[345]
  PIN k_lo_d[346]
    DIRECTION INPUT ;
    USE SIGNAL ;
    PORT
      LAYER M5 ;
        RECT  247.932 0 247.956 0.192 ;
    END
  END k_lo_d[346]
  PIN k_lo_d[347]
    DIRECTION INPUT ;
    USE SIGNAL ;
    PORT
      LAYER M5 ;
        RECT  248.652 0 248.676 0.192 ;
    END
  END k_lo_d[347]
  PIN k_lo_d[348]
    DIRECTION INPUT ;
    USE SIGNAL ;
    PORT
      LAYER M5 ;
        RECT  249.372 0 249.396 0.192 ;
    END
  END k_lo_d[348]
  PIN k_lo_d[349]
    DIRECTION INPUT ;
    USE SIGNAL ;
    PORT
      LAYER M5 ;
        RECT  250.092 0 250.116 0.192 ;
    END
  END k_lo_d[349]
  PIN k_lo_d[34]
    DIRECTION INPUT ;
    USE SIGNAL ;
    PORT
      LAYER M5 ;
        RECT  26.796 0 26.82 0.192 ;
    END
  END k_lo_d[34]
  PIN k_lo_d[350]
    DIRECTION INPUT ;
    USE SIGNAL ;
    PORT
      LAYER M5 ;
        RECT  250.764 0 250.788 0.192 ;
    END
  END k_lo_d[350]
  PIN k_lo_d[351]
    DIRECTION INPUT ;
    USE SIGNAL ;
    PORT
      LAYER M5 ;
        RECT  251.484 0 251.508 0.192 ;
    END
  END k_lo_d[351]
  PIN k_lo_d[352]
    DIRECTION INPUT ;
    USE SIGNAL ;
    PORT
      LAYER M5 ;
        RECT  252.204 0 252.228 0.192 ;
    END
  END k_lo_d[352]
  PIN k_lo_d[353]
    DIRECTION INPUT ;
    USE SIGNAL ;
    PORT
      LAYER M5 ;
        RECT  252.924 0 252.948 0.192 ;
    END
  END k_lo_d[353]
  PIN k_lo_d[354]
    DIRECTION INPUT ;
    USE SIGNAL ;
    PORT
      LAYER M5 ;
        RECT  253.596 0 253.62 0.192 ;
    END
  END k_lo_d[354]
  PIN k_lo_d[355]
    DIRECTION INPUT ;
    USE SIGNAL ;
    PORT
      LAYER M5 ;
        RECT  254.316 0 254.34 0.192 ;
    END
  END k_lo_d[355]
  PIN k_lo_d[356]
    DIRECTION INPUT ;
    USE SIGNAL ;
    PORT
      LAYER M5 ;
        RECT  255.036 0 255.06 0.192 ;
    END
  END k_lo_d[356]
  PIN k_lo_d[357]
    DIRECTION INPUT ;
    USE SIGNAL ;
    PORT
      LAYER M5 ;
        RECT  255.756 0 255.78 0.192 ;
    END
  END k_lo_d[357]
  PIN k_lo_d[358]
    DIRECTION INPUT ;
    USE SIGNAL ;
    PORT
      LAYER M5 ;
        RECT  256.428 0 256.452 0.192 ;
    END
  END k_lo_d[358]
  PIN k_lo_d[359]
    DIRECTION INPUT ;
    USE SIGNAL ;
    PORT
      LAYER M5 ;
        RECT  257.148 0 257.172 0.192 ;
    END
  END k_lo_d[359]
  PIN k_lo_d[35]
    DIRECTION INPUT ;
    USE SIGNAL ;
    PORT
      LAYER M5 ;
        RECT  27.516 0 27.54 0.192 ;
    END
  END k_lo_d[35]
  PIN k_lo_d[360]
    DIRECTION INPUT ;
    USE SIGNAL ;
    PORT
      LAYER M5 ;
        RECT  257.868 0 257.892 0.192 ;
    END
  END k_lo_d[360]
  PIN k_lo_d[361]
    DIRECTION INPUT ;
    USE SIGNAL ;
    PORT
      LAYER M5 ;
        RECT  258.588 0 258.612 0.192 ;
    END
  END k_lo_d[361]
  PIN k_lo_d[362]
    DIRECTION INPUT ;
    USE SIGNAL ;
    PORT
      LAYER M5 ;
        RECT  259.26 0 259.284 0.192 ;
    END
  END k_lo_d[362]
  PIN k_lo_d[363]
    DIRECTION INPUT ;
    USE SIGNAL ;
    PORT
      LAYER M5 ;
        RECT  259.98 0 260.004 0.192 ;
    END
  END k_lo_d[363]
  PIN k_lo_d[364]
    DIRECTION INPUT ;
    USE SIGNAL ;
    PORT
      LAYER M5 ;
        RECT  260.7 0 260.724 0.192 ;
    END
  END k_lo_d[364]
  PIN k_lo_d[365]
    DIRECTION INPUT ;
    USE SIGNAL ;
    PORT
      LAYER M5 ;
        RECT  261.42 0 261.444 0.192 ;
    END
  END k_lo_d[365]
  PIN k_lo_d[366]
    DIRECTION INPUT ;
    USE SIGNAL ;
    PORT
      LAYER M5 ;
        RECT  262.14 0 262.164 0.192 ;
    END
  END k_lo_d[366]
  PIN k_lo_d[367]
    DIRECTION INPUT ;
    USE SIGNAL ;
    PORT
      LAYER M5 ;
        RECT  262.812 0 262.836 0.192 ;
    END
  END k_lo_d[367]
  PIN k_lo_d[368]
    DIRECTION INPUT ;
    USE SIGNAL ;
    PORT
      LAYER M5 ;
        RECT  263.532 0 263.556 0.192 ;
    END
  END k_lo_d[368]
  PIN k_lo_d[369]
    DIRECTION INPUT ;
    USE SIGNAL ;
    PORT
      LAYER M5 ;
        RECT  264.252 0 264.276 0.192 ;
    END
  END k_lo_d[369]
  PIN k_lo_d[36]
    DIRECTION INPUT ;
    USE SIGNAL ;
    PORT
      LAYER M5 ;
        RECT  28.236 0 28.26 0.192 ;
    END
  END k_lo_d[36]
  PIN k_lo_d[370]
    DIRECTION INPUT ;
    USE SIGNAL ;
    PORT
      LAYER M5 ;
        RECT  264.972 0 264.996 0.192 ;
    END
  END k_lo_d[370]
  PIN k_lo_d[371]
    DIRECTION INPUT ;
    USE SIGNAL ;
    PORT
      LAYER M5 ;
        RECT  265.644 0 265.668 0.192 ;
    END
  END k_lo_d[371]
  PIN k_lo_d[372]
    DIRECTION INPUT ;
    USE SIGNAL ;
    PORT
      LAYER M5 ;
        RECT  266.364 0 266.388 0.192 ;
    END
  END k_lo_d[372]
  PIN k_lo_d[373]
    DIRECTION INPUT ;
    USE SIGNAL ;
    PORT
      LAYER M5 ;
        RECT  267.084 0 267.108 0.192 ;
    END
  END k_lo_d[373]
  PIN k_lo_d[374]
    DIRECTION INPUT ;
    USE SIGNAL ;
    PORT
      LAYER M5 ;
        RECT  267.804 0 267.828 0.192 ;
    END
  END k_lo_d[374]
  PIN k_lo_d[375]
    DIRECTION INPUT ;
    USE SIGNAL ;
    PORT
      LAYER M5 ;
        RECT  268.476 0 268.5 0.192 ;
    END
  END k_lo_d[375]
  PIN k_lo_d[376]
    DIRECTION INPUT ;
    USE SIGNAL ;
    PORT
      LAYER M5 ;
        RECT  269.196 0 269.22 0.192 ;
    END
  END k_lo_d[376]
  PIN k_lo_d[377]
    DIRECTION INPUT ;
    USE SIGNAL ;
    PORT
      LAYER M5 ;
        RECT  269.916 0 269.94 0.192 ;
    END
  END k_lo_d[377]
  PIN k_lo_d[378]
    DIRECTION INPUT ;
    USE SIGNAL ;
    PORT
      LAYER M5 ;
        RECT  270.636 0 270.66 0.192 ;
    END
  END k_lo_d[378]
  PIN k_lo_d[379]
    DIRECTION INPUT ;
    USE SIGNAL ;
    PORT
      LAYER M5 ;
        RECT  271.308 0 271.332 0.192 ;
    END
  END k_lo_d[379]
  PIN k_lo_d[37]
    DIRECTION INPUT ;
    USE SIGNAL ;
    PORT
      LAYER M5 ;
        RECT  28.956 0 28.98 0.192 ;
    END
  END k_lo_d[37]
  PIN k_lo_d[380]
    DIRECTION INPUT ;
    USE SIGNAL ;
    PORT
      LAYER M5 ;
        RECT  272.028 0 272.052 0.192 ;
    END
  END k_lo_d[380]
  PIN k_lo_d[381]
    DIRECTION INPUT ;
    USE SIGNAL ;
    PORT
      LAYER M5 ;
        RECT  272.748 0 272.772 0.192 ;
    END
  END k_lo_d[381]
  PIN k_lo_d[382]
    DIRECTION INPUT ;
    USE SIGNAL ;
    PORT
      LAYER M5 ;
        RECT  273.468 0 273.492 0.192 ;
    END
  END k_lo_d[382]
  PIN k_lo_d[383]
    DIRECTION INPUT ;
    USE SIGNAL ;
    PORT
      LAYER M5 ;
        RECT  274.188 0 274.212 0.192 ;
    END
  END k_lo_d[383]
  PIN k_lo_d[384]
    DIRECTION INPUT ;
    USE SIGNAL ;
    PORT
      LAYER M5 ;
        RECT  274.86 0 274.884 0.192 ;
    END
  END k_lo_d[384]
  PIN k_lo_d[385]
    DIRECTION INPUT ;
    USE SIGNAL ;
    PORT
      LAYER M5 ;
        RECT  275.58 0 275.604 0.192 ;
    END
  END k_lo_d[385]
  PIN k_lo_d[386]
    DIRECTION INPUT ;
    USE SIGNAL ;
    PORT
      LAYER M5 ;
        RECT  276.3 0 276.324 0.192 ;
    END
  END k_lo_d[386]
  PIN k_lo_d[387]
    DIRECTION INPUT ;
    USE SIGNAL ;
    PORT
      LAYER M5 ;
        RECT  277.02 0 277.044 0.192 ;
    END
  END k_lo_d[387]
  PIN k_lo_d[388]
    DIRECTION INPUT ;
    USE SIGNAL ;
    PORT
      LAYER M5 ;
        RECT  277.692 0 277.716 0.192 ;
    END
  END k_lo_d[388]
  PIN k_lo_d[389]
    DIRECTION INPUT ;
    USE SIGNAL ;
    PORT
      LAYER M5 ;
        RECT  278.412 0 278.436 0.192 ;
    END
  END k_lo_d[389]
  PIN k_lo_d[38]
    DIRECTION INPUT ;
    USE SIGNAL ;
    PORT
      LAYER M5 ;
        RECT  29.628 0 29.652 0.192 ;
    END
  END k_lo_d[38]
  PIN k_lo_d[390]
    DIRECTION INPUT ;
    USE SIGNAL ;
    PORT
      LAYER M5 ;
        RECT  279.132 0 279.156 0.192 ;
    END
  END k_lo_d[390]
  PIN k_lo_d[391]
    DIRECTION INPUT ;
    USE SIGNAL ;
    PORT
      LAYER M5 ;
        RECT  279.852 0 279.876 0.192 ;
    END
  END k_lo_d[391]
  PIN k_lo_d[392]
    DIRECTION INPUT ;
    USE SIGNAL ;
    PORT
      LAYER M5 ;
        RECT  280.524 0 280.548 0.192 ;
    END
  END k_lo_d[392]
  PIN k_lo_d[393]
    DIRECTION INPUT ;
    USE SIGNAL ;
    PORT
      LAYER M5 ;
        RECT  281.244 0 281.268 0.192 ;
    END
  END k_lo_d[393]
  PIN k_lo_d[394]
    DIRECTION INPUT ;
    USE SIGNAL ;
    PORT
      LAYER M5 ;
        RECT  281.964 0 281.988 0.192 ;
    END
  END k_lo_d[394]
  PIN k_lo_d[395]
    DIRECTION INPUT ;
    USE SIGNAL ;
    PORT
      LAYER M5 ;
        RECT  282.684 0 282.708 0.192 ;
    END
  END k_lo_d[395]
  PIN k_lo_d[396]
    DIRECTION INPUT ;
    USE SIGNAL ;
    PORT
      LAYER M5 ;
        RECT  283.404 0 283.428 0.192 ;
    END
  END k_lo_d[396]
  PIN k_lo_d[397]
    DIRECTION INPUT ;
    USE SIGNAL ;
    PORT
      LAYER M5 ;
        RECT  284.076 0 284.1 0.192 ;
    END
  END k_lo_d[397]
  PIN k_lo_d[398]
    DIRECTION INPUT ;
    USE SIGNAL ;
    PORT
      LAYER M5 ;
        RECT  284.796 0 284.82 0.192 ;
    END
  END k_lo_d[398]
  PIN k_lo_d[399]
    DIRECTION INPUT ;
    USE SIGNAL ;
    PORT
      LAYER M5 ;
        RECT  285.516 0 285.54 0.192 ;
    END
  END k_lo_d[399]
  PIN k_lo_d[39]
    DIRECTION INPUT ;
    USE SIGNAL ;
    PORT
      LAYER M5 ;
        RECT  30.348 0 30.372 0.192 ;
    END
  END k_lo_d[39]
  PIN k_lo_d[3]
    DIRECTION INPUT ;
    USE SIGNAL ;
    PORT
      LAYER M5 ;
        RECT  4.86 0 4.884 0.192 ;
    END
  END k_lo_d[3]
  PIN k_lo_d[400]
    DIRECTION INPUT ;
    USE SIGNAL ;
    PORT
      LAYER M5 ;
        RECT  286.236 0 286.26 0.192 ;
    END
  END k_lo_d[400]
  PIN k_lo_d[401]
    DIRECTION INPUT ;
    USE SIGNAL ;
    PORT
      LAYER M5 ;
        RECT  286.908 0 286.932 0.192 ;
    END
  END k_lo_d[401]
  PIN k_lo_d[402]
    DIRECTION INPUT ;
    USE SIGNAL ;
    PORT
      LAYER M5 ;
        RECT  287.628 0 287.652 0.192 ;
    END
  END k_lo_d[402]
  PIN k_lo_d[403]
    DIRECTION INPUT ;
    USE SIGNAL ;
    PORT
      LAYER M5 ;
        RECT  288.348 0 288.372 0.192 ;
    END
  END k_lo_d[403]
  PIN k_lo_d[404]
    DIRECTION INPUT ;
    USE SIGNAL ;
    PORT
      LAYER M5 ;
        RECT  289.068 0 289.092 0.192 ;
    END
  END k_lo_d[404]
  PIN k_lo_d[405]
    DIRECTION INPUT ;
    USE SIGNAL ;
    PORT
      LAYER M5 ;
        RECT  289.74 0 289.764 0.192 ;
    END
  END k_lo_d[405]
  PIN k_lo_d[406]
    DIRECTION INPUT ;
    USE SIGNAL ;
    PORT
      LAYER M5 ;
        RECT  290.46 0 290.484 0.192 ;
    END
  END k_lo_d[406]
  PIN k_lo_d[407]
    DIRECTION INPUT ;
    USE SIGNAL ;
    PORT
      LAYER M5 ;
        RECT  291.18 0 291.204 0.192 ;
    END
  END k_lo_d[407]
  PIN k_lo_d[408]
    DIRECTION INPUT ;
    USE SIGNAL ;
    PORT
      LAYER M5 ;
        RECT  291.9 0 291.924 0.192 ;
    END
  END k_lo_d[408]
  PIN k_lo_d[409]
    DIRECTION INPUT ;
    USE SIGNAL ;
    PORT
      LAYER M5 ;
        RECT  292.572 0 292.596 0.192 ;
    END
  END k_lo_d[409]
  PIN k_lo_d[40]
    DIRECTION INPUT ;
    USE SIGNAL ;
    PORT
      LAYER M5 ;
        RECT  31.068 0 31.092 0.192 ;
    END
  END k_lo_d[40]
  PIN k_lo_d[410]
    DIRECTION INPUT ;
    USE SIGNAL ;
    PORT
      LAYER M5 ;
        RECT  293.292 0 293.316 0.192 ;
    END
  END k_lo_d[410]
  PIN k_lo_d[411]
    DIRECTION INPUT ;
    USE SIGNAL ;
    PORT
      LAYER M5 ;
        RECT  294.012 0 294.036 0.192 ;
    END
  END k_lo_d[411]
  PIN k_lo_d[412]
    DIRECTION INPUT ;
    USE SIGNAL ;
    PORT
      LAYER M5 ;
        RECT  294.732 0 294.756 0.192 ;
    END
  END k_lo_d[412]
  PIN k_lo_d[413]
    DIRECTION INPUT ;
    USE SIGNAL ;
    PORT
      LAYER M5 ;
        RECT  295.452 0 295.476 0.192 ;
    END
  END k_lo_d[413]
  PIN k_lo_d[414]
    DIRECTION INPUT ;
    USE SIGNAL ;
    PORT
      LAYER M5 ;
        RECT  296.124 0 296.148 0.192 ;
    END
  END k_lo_d[414]
  PIN k_lo_d[415]
    DIRECTION INPUT ;
    USE SIGNAL ;
    PORT
      LAYER M5 ;
        RECT  296.844 0 296.868 0.192 ;
    END
  END k_lo_d[415]
  PIN k_lo_d[416]
    DIRECTION INPUT ;
    USE SIGNAL ;
    PORT
      LAYER M5 ;
        RECT  297.564 0 297.588 0.192 ;
    END
  END k_lo_d[416]
  PIN k_lo_d[417]
    DIRECTION INPUT ;
    USE SIGNAL ;
    PORT
      LAYER M5 ;
        RECT  298.284 0 298.308 0.192 ;
    END
  END k_lo_d[417]
  PIN k_lo_d[418]
    DIRECTION INPUT ;
    USE SIGNAL ;
    PORT
      LAYER M5 ;
        RECT  298.956 0 298.98 0.192 ;
    END
  END k_lo_d[418]
  PIN k_lo_d[419]
    DIRECTION INPUT ;
    USE SIGNAL ;
    PORT
      LAYER M5 ;
        RECT  299.676 0 299.7 0.192 ;
    END
  END k_lo_d[419]
  PIN k_lo_d[41]
    DIRECTION INPUT ;
    USE SIGNAL ;
    PORT
      LAYER M5 ;
        RECT  31.788 0 31.812 0.192 ;
    END
  END k_lo_d[41]
  PIN k_lo_d[420]
    DIRECTION INPUT ;
    USE SIGNAL ;
    PORT
      LAYER M5 ;
        RECT  300.396 0 300.42 0.192 ;
    END
  END k_lo_d[420]
  PIN k_lo_d[421]
    DIRECTION INPUT ;
    USE SIGNAL ;
    PORT
      LAYER M5 ;
        RECT  301.116 0 301.14 0.192 ;
    END
  END k_lo_d[421]
  PIN k_lo_d[422]
    DIRECTION INPUT ;
    USE SIGNAL ;
    PORT
      LAYER M5 ;
        RECT  301.788 0 301.812 0.192 ;
    END
  END k_lo_d[422]
  PIN k_lo_d[423]
    DIRECTION INPUT ;
    USE SIGNAL ;
    PORT
      LAYER M5 ;
        RECT  302.508 0 302.532 0.192 ;
    END
  END k_lo_d[423]
  PIN k_lo_d[424]
    DIRECTION INPUT ;
    USE SIGNAL ;
    PORT
      LAYER M5 ;
        RECT  303.228 0 303.252 0.192 ;
    END
  END k_lo_d[424]
  PIN k_lo_d[425]
    DIRECTION INPUT ;
    USE SIGNAL ;
    PORT
      LAYER M5 ;
        RECT  303.948 0 303.972 0.192 ;
    END
  END k_lo_d[425]
  PIN k_lo_d[426]
    DIRECTION INPUT ;
    USE SIGNAL ;
    PORT
      LAYER M5 ;
        RECT  304.62 0 304.644 0.192 ;
    END
  END k_lo_d[426]
  PIN k_lo_d[427]
    DIRECTION INPUT ;
    USE SIGNAL ;
    PORT
      LAYER M5 ;
        RECT  305.34 0 305.364 0.192 ;
    END
  END k_lo_d[427]
  PIN k_lo_d[428]
    DIRECTION INPUT ;
    USE SIGNAL ;
    PORT
      LAYER M5 ;
        RECT  306.06 0 306.084 0.192 ;
    END
  END k_lo_d[428]
  PIN k_lo_d[429]
    DIRECTION INPUT ;
    USE SIGNAL ;
    PORT
      LAYER M5 ;
        RECT  306.78 0 306.804 0.192 ;
    END
  END k_lo_d[429]
  PIN k_lo_d[42]
    DIRECTION INPUT ;
    USE SIGNAL ;
    PORT
      LAYER M5 ;
        RECT  32.46 0 32.484 0.192 ;
    END
  END k_lo_d[42]
  PIN k_lo_d[430]
    DIRECTION INPUT ;
    USE SIGNAL ;
    PORT
      LAYER M5 ;
        RECT  307.5 0 307.524 0.192 ;
    END
  END k_lo_d[430]
  PIN k_lo_d[431]
    DIRECTION INPUT ;
    USE SIGNAL ;
    PORT
      LAYER M5 ;
        RECT  308.172 0 308.196 0.192 ;
    END
  END k_lo_d[431]
  PIN k_lo_d[432]
    DIRECTION INPUT ;
    USE SIGNAL ;
    PORT
      LAYER M5 ;
        RECT  308.892 0 308.916 0.192 ;
    END
  END k_lo_d[432]
  PIN k_lo_d[433]
    DIRECTION INPUT ;
    USE SIGNAL ;
    PORT
      LAYER M5 ;
        RECT  309.612 0 309.636 0.192 ;
    END
  END k_lo_d[433]
  PIN k_lo_d[434]
    DIRECTION INPUT ;
    USE SIGNAL ;
    PORT
      LAYER M5 ;
        RECT  310.332 0 310.356 0.192 ;
    END
  END k_lo_d[434]
  PIN k_lo_d[435]
    DIRECTION INPUT ;
    USE SIGNAL ;
    PORT
      LAYER M5 ;
        RECT  311.004 0 311.028 0.192 ;
    END
  END k_lo_d[435]
  PIN k_lo_d[436]
    DIRECTION INPUT ;
    USE SIGNAL ;
    PORT
      LAYER M5 ;
        RECT  311.724 0 311.748 0.192 ;
    END
  END k_lo_d[436]
  PIN k_lo_d[437]
    DIRECTION INPUT ;
    USE SIGNAL ;
    PORT
      LAYER M5 ;
        RECT  312.444 0 312.468 0.192 ;
    END
  END k_lo_d[437]
  PIN k_lo_d[438]
    DIRECTION INPUT ;
    USE SIGNAL ;
    PORT
      LAYER M5 ;
        RECT  313.164 0 313.188 0.192 ;
    END
  END k_lo_d[438]
  PIN k_lo_d[439]
    DIRECTION INPUT ;
    USE SIGNAL ;
    PORT
      LAYER M5 ;
        RECT  313.836 0 313.86 0.192 ;
    END
  END k_lo_d[439]
  PIN k_lo_d[43]
    DIRECTION INPUT ;
    USE SIGNAL ;
    PORT
      LAYER M5 ;
        RECT  33.18 0 33.204 0.192 ;
    END
  END k_lo_d[43]
  PIN k_lo_d[440]
    DIRECTION INPUT ;
    USE SIGNAL ;
    PORT
      LAYER M5 ;
        RECT  314.556 0 314.58 0.192 ;
    END
  END k_lo_d[440]
  PIN k_lo_d[441]
    DIRECTION INPUT ;
    USE SIGNAL ;
    PORT
      LAYER M5 ;
        RECT  315.276 0 315.3 0.192 ;
    END
  END k_lo_d[441]
  PIN k_lo_d[442]
    DIRECTION INPUT ;
    USE SIGNAL ;
    PORT
      LAYER M5 ;
        RECT  315.996 0 316.02 0.192 ;
    END
  END k_lo_d[442]
  PIN k_lo_d[443]
    DIRECTION INPUT ;
    USE SIGNAL ;
    PORT
      LAYER M5 ;
        RECT  316.716 0 316.74 0.192 ;
    END
  END k_lo_d[443]
  PIN k_lo_d[444]
    DIRECTION INPUT ;
    USE SIGNAL ;
    PORT
      LAYER M5 ;
        RECT  317.388 0 317.412 0.192 ;
    END
  END k_lo_d[444]
  PIN k_lo_d[445]
    DIRECTION INPUT ;
    USE SIGNAL ;
    PORT
      LAYER M5 ;
        RECT  318.108 0 318.132 0.192 ;
    END
  END k_lo_d[445]
  PIN k_lo_d[446]
    DIRECTION INPUT ;
    USE SIGNAL ;
    PORT
      LAYER M5 ;
        RECT  318.828 0 318.852 0.192 ;
    END
  END k_lo_d[446]
  PIN k_lo_d[447]
    DIRECTION INPUT ;
    USE SIGNAL ;
    PORT
      LAYER M5 ;
        RECT  319.548 0 319.572 0.192 ;
    END
  END k_lo_d[447]
  PIN k_lo_d[448]
    DIRECTION INPUT ;
    USE SIGNAL ;
    PORT
      LAYER M5 ;
        RECT  320.22 0 320.244 0.192 ;
    END
  END k_lo_d[448]
  PIN k_lo_d[449]
    DIRECTION INPUT ;
    USE SIGNAL ;
    PORT
      LAYER M5 ;
        RECT  320.94 0 320.964 0.192 ;
    END
  END k_lo_d[449]
  PIN k_lo_d[44]
    DIRECTION INPUT ;
    USE SIGNAL ;
    PORT
      LAYER M5 ;
        RECT  33.9 0 33.924 0.192 ;
    END
  END k_lo_d[44]
  PIN k_lo_d[450]
    DIRECTION INPUT ;
    USE SIGNAL ;
    PORT
      LAYER M5 ;
        RECT  321.66 0 321.684 0.192 ;
    END
  END k_lo_d[450]
  PIN k_lo_d[451]
    DIRECTION INPUT ;
    USE SIGNAL ;
    PORT
      LAYER M5 ;
        RECT  322.38 0 322.404 0.192 ;
    END
  END k_lo_d[451]
  PIN k_lo_d[452]
    DIRECTION INPUT ;
    USE SIGNAL ;
    PORT
      LAYER M5 ;
        RECT  323.052 0 323.076 0.192 ;
    END
  END k_lo_d[452]
  PIN k_lo_d[453]
    DIRECTION INPUT ;
    USE SIGNAL ;
    PORT
      LAYER M5 ;
        RECT  323.772 0 323.796 0.192 ;
    END
  END k_lo_d[453]
  PIN k_lo_d[454]
    DIRECTION INPUT ;
    USE SIGNAL ;
    PORT
      LAYER M5 ;
        RECT  324.492 0 324.516 0.192 ;
    END
  END k_lo_d[454]
  PIN k_lo_d[455]
    DIRECTION INPUT ;
    USE SIGNAL ;
    PORT
      LAYER M5 ;
        RECT  325.212 0 325.236 0.192 ;
    END
  END k_lo_d[455]
  PIN k_lo_d[456]
    DIRECTION INPUT ;
    USE SIGNAL ;
    PORT
      LAYER M5 ;
        RECT  325.884 0 325.908 0.192 ;
    END
  END k_lo_d[456]
  PIN k_lo_d[457]
    DIRECTION INPUT ;
    USE SIGNAL ;
    PORT
      LAYER M5 ;
        RECT  326.604 0 326.628 0.192 ;
    END
  END k_lo_d[457]
  PIN k_lo_d[458]
    DIRECTION INPUT ;
    USE SIGNAL ;
    PORT
      LAYER M5 ;
        RECT  327.324 0 327.348 0.192 ;
    END
  END k_lo_d[458]
  PIN k_lo_d[459]
    DIRECTION INPUT ;
    USE SIGNAL ;
    PORT
      LAYER M5 ;
        RECT  328.044 0 328.068 0.192 ;
    END
  END k_lo_d[459]
  PIN k_lo_d[45]
    DIRECTION INPUT ;
    USE SIGNAL ;
    PORT
      LAYER M5 ;
        RECT  34.62 0 34.644 0.192 ;
    END
  END k_lo_d[45]
  PIN k_lo_d[460]
    DIRECTION INPUT ;
    USE SIGNAL ;
    PORT
      LAYER M5 ;
        RECT  328.764 0 328.788 0.192 ;
    END
  END k_lo_d[460]
  PIN k_lo_d[461]
    DIRECTION INPUT ;
    USE SIGNAL ;
    PORT
      LAYER M5 ;
        RECT  329.436 0 329.46 0.192 ;
    END
  END k_lo_d[461]
  PIN k_lo_d[462]
    DIRECTION INPUT ;
    USE SIGNAL ;
    PORT
      LAYER M5 ;
        RECT  330.156 0 330.18 0.192 ;
    END
  END k_lo_d[462]
  PIN k_lo_d[463]
    DIRECTION INPUT ;
    USE SIGNAL ;
    PORT
      LAYER M5 ;
        RECT  330.876 0 330.9 0.192 ;
    END
  END k_lo_d[463]
  PIN k_lo_d[464]
    DIRECTION INPUT ;
    USE SIGNAL ;
    PORT
      LAYER M5 ;
        RECT  331.596 0 331.62 0.192 ;
    END
  END k_lo_d[464]
  PIN k_lo_d[465]
    DIRECTION INPUT ;
    USE SIGNAL ;
    PORT
      LAYER M5 ;
        RECT  332.268 0 332.292 0.192 ;
    END
  END k_lo_d[465]
  PIN k_lo_d[466]
    DIRECTION INPUT ;
    USE SIGNAL ;
    PORT
      LAYER M5 ;
        RECT  332.988 0 333.012 0.192 ;
    END
  END k_lo_d[466]
  PIN k_lo_d[467]
    DIRECTION INPUT ;
    USE SIGNAL ;
    PORT
      LAYER M5 ;
        RECT  333.708 0 333.732 0.192 ;
    END
  END k_lo_d[467]
  PIN k_lo_d[468]
    DIRECTION INPUT ;
    USE SIGNAL ;
    PORT
      LAYER M5 ;
        RECT  334.428 0 334.452 0.192 ;
    END
  END k_lo_d[468]
  PIN k_lo_d[469]
    DIRECTION INPUT ;
    USE SIGNAL ;
    PORT
      LAYER M5 ;
        RECT  335.1 0 335.124 0.192 ;
    END
  END k_lo_d[469]
  PIN k_lo_d[46]
    DIRECTION INPUT ;
    USE SIGNAL ;
    PORT
      LAYER M5 ;
        RECT  35.292 0 35.316 0.192 ;
    END
  END k_lo_d[46]
  PIN k_lo_d[470]
    DIRECTION INPUT ;
    USE SIGNAL ;
    PORT
      LAYER M5 ;
        RECT  335.82 0 335.844 0.192 ;
    END
  END k_lo_d[470]
  PIN k_lo_d[471]
    DIRECTION INPUT ;
    USE SIGNAL ;
    PORT
      LAYER M5 ;
        RECT  336.54 0 336.564 0.192 ;
    END
  END k_lo_d[471]
  PIN k_lo_d[472]
    DIRECTION INPUT ;
    USE SIGNAL ;
    PORT
      LAYER M5 ;
        RECT  337.26 0 337.284 0.192 ;
    END
  END k_lo_d[472]
  PIN k_lo_d[473]
    DIRECTION INPUT ;
    USE SIGNAL ;
    PORT
      LAYER M5 ;
        RECT  337.932 0 337.956 0.192 ;
    END
  END k_lo_d[473]
  PIN k_lo_d[474]
    DIRECTION INPUT ;
    USE SIGNAL ;
    PORT
      LAYER M5 ;
        RECT  338.652 0 338.676 0.192 ;
    END
  END k_lo_d[474]
  PIN k_lo_d[475]
    DIRECTION INPUT ;
    USE SIGNAL ;
    PORT
      LAYER M5 ;
        RECT  339.372 0 339.396 0.192 ;
    END
  END k_lo_d[475]
  PIN k_lo_d[476]
    DIRECTION INPUT ;
    USE SIGNAL ;
    PORT
      LAYER M5 ;
        RECT  340.092 0 340.116 0.192 ;
    END
  END k_lo_d[476]
  PIN k_lo_d[477]
    DIRECTION INPUT ;
    USE SIGNAL ;
    PORT
      LAYER M5 ;
        RECT  340.812 0 340.836 0.192 ;
    END
  END k_lo_d[477]
  PIN k_lo_d[478]
    DIRECTION INPUT ;
    USE SIGNAL ;
    PORT
      LAYER M5 ;
        RECT  341.484 0 341.508 0.192 ;
    END
  END k_lo_d[478]
  PIN k_lo_d[479]
    DIRECTION INPUT ;
    USE SIGNAL ;
    PORT
      LAYER M5 ;
        RECT  342.204 0 342.228 0.192 ;
    END
  END k_lo_d[479]
  PIN k_lo_d[47]
    DIRECTION INPUT ;
    USE SIGNAL ;
    PORT
      LAYER M5 ;
        RECT  36.012 0 36.036 0.192 ;
    END
  END k_lo_d[47]
  PIN k_lo_d[480]
    DIRECTION INPUT ;
    USE SIGNAL ;
    PORT
      LAYER M5 ;
        RECT  342.924 0 342.948 0.192 ;
    END
  END k_lo_d[480]
  PIN k_lo_d[481]
    DIRECTION INPUT ;
    USE SIGNAL ;
    PORT
      LAYER M5 ;
        RECT  343.644 0 343.668 0.192 ;
    END
  END k_lo_d[481]
  PIN k_lo_d[482]
    DIRECTION INPUT ;
    USE SIGNAL ;
    PORT
      LAYER M5 ;
        RECT  344.316 0 344.34 0.192 ;
    END
  END k_lo_d[482]
  PIN k_lo_d[483]
    DIRECTION INPUT ;
    USE SIGNAL ;
    PORT
      LAYER M5 ;
        RECT  345.036 0 345.06 0.192 ;
    END
  END k_lo_d[483]
  PIN k_lo_d[484]
    DIRECTION INPUT ;
    USE SIGNAL ;
    PORT
      LAYER M5 ;
        RECT  345.756 0 345.78 0.192 ;
    END
  END k_lo_d[484]
  PIN k_lo_d[485]
    DIRECTION INPUT ;
    USE SIGNAL ;
    PORT
      LAYER M5 ;
        RECT  346.476 0 346.5 0.192 ;
    END
  END k_lo_d[485]
  PIN k_lo_d[486]
    DIRECTION INPUT ;
    USE SIGNAL ;
    PORT
      LAYER M5 ;
        RECT  347.148 0 347.172 0.192 ;
    END
  END k_lo_d[486]
  PIN k_lo_d[487]
    DIRECTION INPUT ;
    USE SIGNAL ;
    PORT
      LAYER M5 ;
        RECT  347.868 0 347.892 0.192 ;
    END
  END k_lo_d[487]
  PIN k_lo_d[488]
    DIRECTION INPUT ;
    USE SIGNAL ;
    PORT
      LAYER M5 ;
        RECT  348.588 0 348.612 0.192 ;
    END
  END k_lo_d[488]
  PIN k_lo_d[489]
    DIRECTION INPUT ;
    USE SIGNAL ;
    PORT
      LAYER M5 ;
        RECT  349.308 0 349.332 0.192 ;
    END
  END k_lo_d[489]
  PIN k_lo_d[48]
    DIRECTION INPUT ;
    USE SIGNAL ;
    PORT
      LAYER M5 ;
        RECT  36.732 0 36.756 0.192 ;
    END
  END k_lo_d[48]
  PIN k_lo_d[490]
    DIRECTION INPUT ;
    USE SIGNAL ;
    PORT
      LAYER M5 ;
        RECT  349.98 0 350.004 0.192 ;
    END
  END k_lo_d[490]
  PIN k_lo_d[491]
    DIRECTION INPUT ;
    USE SIGNAL ;
    PORT
      LAYER M5 ;
        RECT  350.7 0 350.724 0.192 ;
    END
  END k_lo_d[491]
  PIN k_lo_d[492]
    DIRECTION INPUT ;
    USE SIGNAL ;
    PORT
      LAYER M5 ;
        RECT  351.42 0 351.444 0.192 ;
    END
  END k_lo_d[492]
  PIN k_lo_d[493]
    DIRECTION INPUT ;
    USE SIGNAL ;
    PORT
      LAYER M5 ;
        RECT  352.14 0 352.164 0.192 ;
    END
  END k_lo_d[493]
  PIN k_lo_d[494]
    DIRECTION INPUT ;
    USE SIGNAL ;
    PORT
      LAYER M5 ;
        RECT  352.86 0 352.884 0.192 ;
    END
  END k_lo_d[494]
  PIN k_lo_d[495]
    DIRECTION INPUT ;
    USE SIGNAL ;
    PORT
      LAYER M5 ;
        RECT  353.532 0 353.556 0.192 ;
    END
  END k_lo_d[495]
  PIN k_lo_d[496]
    DIRECTION INPUT ;
    USE SIGNAL ;
    PORT
      LAYER M5 ;
        RECT  354.252 0 354.276 0.192 ;
    END
  END k_lo_d[496]
  PIN k_lo_d[497]
    DIRECTION INPUT ;
    USE SIGNAL ;
    PORT
      LAYER M5 ;
        RECT  354.972 0 354.996 0.192 ;
    END
  END k_lo_d[497]
  PIN k_lo_d[498]
    DIRECTION INPUT ;
    USE SIGNAL ;
    PORT
      LAYER M5 ;
        RECT  355.692 0 355.716 0.192 ;
    END
  END k_lo_d[498]
  PIN k_lo_d[499]
    DIRECTION INPUT ;
    USE SIGNAL ;
    PORT
      LAYER M5 ;
        RECT  356.364 0 356.388 0.192 ;
    END
  END k_lo_d[499]
  PIN k_lo_d[49]
    DIRECTION INPUT ;
    USE SIGNAL ;
    PORT
      LAYER M5 ;
        RECT  37.452 0 37.476 0.192 ;
    END
  END k_lo_d[49]
  PIN k_lo_d[4]
    DIRECTION INPUT ;
    USE SIGNAL ;
    PORT
      LAYER M5 ;
        RECT  5.532 0 5.556 0.192 ;
    END
  END k_lo_d[4]
  PIN k_lo_d[500]
    DIRECTION INPUT ;
    USE SIGNAL ;
    PORT
      LAYER M5 ;
        RECT  357.084 0 357.108 0.192 ;
    END
  END k_lo_d[500]
  PIN k_lo_d[501]
    DIRECTION INPUT ;
    USE SIGNAL ;
    PORT
      LAYER M5 ;
        RECT  357.804 0 357.828 0.192 ;
    END
  END k_lo_d[501]
  PIN k_lo_d[502]
    DIRECTION INPUT ;
    USE SIGNAL ;
    PORT
      LAYER M5 ;
        RECT  358.524 0 358.548 0.192 ;
    END
  END k_lo_d[502]
  PIN k_lo_d[503]
    DIRECTION INPUT ;
    USE SIGNAL ;
    PORT
      LAYER M5 ;
        RECT  359.196 0 359.22 0.192 ;
    END
  END k_lo_d[503]
  PIN k_lo_d[504]
    DIRECTION INPUT ;
    USE SIGNAL ;
    PORT
      LAYER M5 ;
        RECT  359.916 0 359.94 0.192 ;
    END
  END k_lo_d[504]
  PIN k_lo_d[505]
    DIRECTION INPUT ;
    USE SIGNAL ;
    PORT
      LAYER M5 ;
        RECT  360.636 0 360.66 0.192 ;
    END
  END k_lo_d[505]
  PIN k_lo_d[506]
    DIRECTION INPUT ;
    USE SIGNAL ;
    PORT
      LAYER M5 ;
        RECT  361.356 0 361.38 0.192 ;
    END
  END k_lo_d[506]
  PIN k_lo_d[507]
    DIRECTION INPUT ;
    USE SIGNAL ;
    PORT
      LAYER M5 ;
        RECT  362.076 0 362.1 0.192 ;
    END
  END k_lo_d[507]
  PIN k_lo_d[508]
    DIRECTION INPUT ;
    USE SIGNAL ;
    PORT
      LAYER M5 ;
        RECT  362.748 0 362.772 0.192 ;
    END
  END k_lo_d[508]
  PIN k_lo_d[509]
    DIRECTION INPUT ;
    USE SIGNAL ;
    PORT
      LAYER M5 ;
        RECT  363.468 0 363.492 0.192 ;
    END
  END k_lo_d[509]
  PIN k_lo_d[50]
    DIRECTION INPUT ;
    USE SIGNAL ;
    PORT
      LAYER M5 ;
        RECT  38.172 0 38.196 0.192 ;
    END
  END k_lo_d[50]
  PIN k_lo_d[510]
    DIRECTION INPUT ;
    USE SIGNAL ;
    PORT
      LAYER M5 ;
        RECT  364.188 0 364.212 0.192 ;
    END
  END k_lo_d[510]
  PIN k_lo_d[511]
    DIRECTION INPUT ;
    USE SIGNAL ;
    PORT
      LAYER M5 ;
        RECT  364.908 0 364.932 0.192 ;
    END
  END k_lo_d[511]
  PIN k_lo_d[512]
    DIRECTION INPUT ;
    USE SIGNAL ;
    PORT
      LAYER M5 ;
        RECT  365.58 0 365.604 0.192 ;
    END
  END k_lo_d[512]
  PIN k_lo_d[513]
    DIRECTION INPUT ;
    USE SIGNAL ;
    PORT
      LAYER M5 ;
        RECT  366.3 0 366.324 0.192 ;
    END
  END k_lo_d[513]
  PIN k_lo_d[514]
    DIRECTION INPUT ;
    USE SIGNAL ;
    PORT
      LAYER M5 ;
        RECT  367.02 0 367.044 0.192 ;
    END
  END k_lo_d[514]
  PIN k_lo_d[515]
    DIRECTION INPUT ;
    USE SIGNAL ;
    PORT
      LAYER M5 ;
        RECT  367.74 0 367.764 0.192 ;
    END
  END k_lo_d[515]
  PIN k_lo_d[516]
    DIRECTION INPUT ;
    USE SIGNAL ;
    PORT
      LAYER M5 ;
        RECT  368.412 0 368.436 0.192 ;
    END
  END k_lo_d[516]
  PIN k_lo_d[517]
    DIRECTION INPUT ;
    USE SIGNAL ;
    PORT
      LAYER M5 ;
        RECT  369.132 0 369.156 0.192 ;
    END
  END k_lo_d[517]
  PIN k_lo_d[518]
    DIRECTION INPUT ;
    USE SIGNAL ;
    PORT
      LAYER M5 ;
        RECT  369.852 0 369.876 0.192 ;
    END
  END k_lo_d[518]
  PIN k_lo_d[519]
    DIRECTION INPUT ;
    USE SIGNAL ;
    PORT
      LAYER M5 ;
        RECT  370.572 0 370.596 0.192 ;
    END
  END k_lo_d[519]
  PIN k_lo_d[51]
    DIRECTION INPUT ;
    USE SIGNAL ;
    PORT
      LAYER M5 ;
        RECT  38.844 0 38.868 0.192 ;
    END
  END k_lo_d[51]
  PIN k_lo_d[520]
    DIRECTION INPUT ;
    USE SIGNAL ;
    PORT
      LAYER M5 ;
        RECT  371.244 0 371.268 0.192 ;
    END
  END k_lo_d[520]
  PIN k_lo_d[521]
    DIRECTION INPUT ;
    USE SIGNAL ;
    PORT
      LAYER M5 ;
        RECT  371.964 0 371.988 0.192 ;
    END
  END k_lo_d[521]
  PIN k_lo_d[522]
    DIRECTION INPUT ;
    USE SIGNAL ;
    PORT
      LAYER M5 ;
        RECT  372.684 0 372.708 0.192 ;
    END
  END k_lo_d[522]
  PIN k_lo_d[523]
    DIRECTION INPUT ;
    USE SIGNAL ;
    PORT
      LAYER M5 ;
        RECT  373.404 0 373.428 0.192 ;
    END
  END k_lo_d[523]
  PIN k_lo_d[524]
    DIRECTION INPUT ;
    USE SIGNAL ;
    PORT
      LAYER M5 ;
        RECT  374.124 0 374.148 0.192 ;
    END
  END k_lo_d[524]
  PIN k_lo_d[525]
    DIRECTION INPUT ;
    USE SIGNAL ;
    PORT
      LAYER M5 ;
        RECT  374.796 0 374.82 0.192 ;
    END
  END k_lo_d[525]
  PIN k_lo_d[526]
    DIRECTION INPUT ;
    USE SIGNAL ;
    PORT
      LAYER M5 ;
        RECT  375.516 0 375.54 0.192 ;
    END
  END k_lo_d[526]
  PIN k_lo_d[527]
    DIRECTION INPUT ;
    USE SIGNAL ;
    PORT
      LAYER M5 ;
        RECT  376.236 0 376.26 0.192 ;
    END
  END k_lo_d[527]
  PIN k_lo_d[528]
    DIRECTION INPUT ;
    USE SIGNAL ;
    PORT
      LAYER M5 ;
        RECT  376.956 0 376.98 0.192 ;
    END
  END k_lo_d[528]
  PIN k_lo_d[529]
    DIRECTION INPUT ;
    USE SIGNAL ;
    PORT
      LAYER M5 ;
        RECT  377.628 0 377.652 0.192 ;
    END
  END k_lo_d[529]
  PIN k_lo_d[52]
    DIRECTION INPUT ;
    USE SIGNAL ;
    PORT
      LAYER M5 ;
        RECT  39.564 0 39.588 0.192 ;
    END
  END k_lo_d[52]
  PIN k_lo_d[530]
    DIRECTION INPUT ;
    USE SIGNAL ;
    PORT
      LAYER M5 ;
        RECT  378.348 0 378.372 0.192 ;
    END
  END k_lo_d[530]
  PIN k_lo_d[531]
    DIRECTION INPUT ;
    USE SIGNAL ;
    PORT
      LAYER M5 ;
        RECT  379.068 0 379.092 0.192 ;
    END
  END k_lo_d[531]
  PIN k_lo_d[532]
    DIRECTION INPUT ;
    USE SIGNAL ;
    PORT
      LAYER M5 ;
        RECT  379.788 0 379.812 0.192 ;
    END
  END k_lo_d[532]
  PIN k_lo_d[533]
    DIRECTION INPUT ;
    USE SIGNAL ;
    PORT
      LAYER M5 ;
        RECT  380.46 0 380.484 0.192 ;
    END
  END k_lo_d[533]
  PIN k_lo_d[534]
    DIRECTION INPUT ;
    USE SIGNAL ;
    PORT
      LAYER M5 ;
        RECT  381.18 0 381.204 0.192 ;
    END
  END k_lo_d[534]
  PIN k_lo_d[535]
    DIRECTION INPUT ;
    USE SIGNAL ;
    PORT
      LAYER M5 ;
        RECT  381.9 0 381.924 0.192 ;
    END
  END k_lo_d[535]
  PIN k_lo_d[536]
    DIRECTION INPUT ;
    USE SIGNAL ;
    PORT
      LAYER M5 ;
        RECT  382.62 0 382.644 0.192 ;
    END
  END k_lo_d[536]
  PIN k_lo_d[537]
    DIRECTION INPUT ;
    USE SIGNAL ;
    PORT
      LAYER M5 ;
        RECT  383.292 0 383.316 0.192 ;
    END
  END k_lo_d[537]
  PIN k_lo_d[538]
    DIRECTION INPUT ;
    USE SIGNAL ;
    PORT
      LAYER M5 ;
        RECT  384.012 0 384.036 0.192 ;
    END
  END k_lo_d[538]
  PIN k_lo_d[539]
    DIRECTION INPUT ;
    USE SIGNAL ;
    PORT
      LAYER M5 ;
        RECT  384.732 0 384.756 0.192 ;
    END
  END k_lo_d[539]
  PIN k_lo_d[53]
    DIRECTION INPUT ;
    USE SIGNAL ;
    PORT
      LAYER M5 ;
        RECT  40.284 0 40.308 0.192 ;
    END
  END k_lo_d[53]
  PIN k_lo_d[540]
    DIRECTION INPUT ;
    USE SIGNAL ;
    PORT
      LAYER M5 ;
        RECT  385.452 0 385.476 0.192 ;
    END
  END k_lo_d[540]
  PIN k_lo_d[541]
    DIRECTION INPUT ;
    USE SIGNAL ;
    PORT
      LAYER M5 ;
        RECT  386.172 0 386.196 0.192 ;
    END
  END k_lo_d[541]
  PIN k_lo_d[542]
    DIRECTION INPUT ;
    USE SIGNAL ;
    PORT
      LAYER M5 ;
        RECT  386.844 0 386.868 0.192 ;
    END
  END k_lo_d[542]
  PIN k_lo_d[543]
    DIRECTION INPUT ;
    USE SIGNAL ;
    PORT
      LAYER M5 ;
        RECT  387.564 0 387.588 0.192 ;
    END
  END k_lo_d[543]
  PIN k_lo_d[544]
    DIRECTION INPUT ;
    USE SIGNAL ;
    PORT
      LAYER M5 ;
        RECT  388.284 0 388.308 0.192 ;
    END
  END k_lo_d[544]
  PIN k_lo_d[545]
    DIRECTION INPUT ;
    USE SIGNAL ;
    PORT
      LAYER M5 ;
        RECT  389.004 0 389.028 0.192 ;
    END
  END k_lo_d[545]
  PIN k_lo_d[546]
    DIRECTION INPUT ;
    USE SIGNAL ;
    PORT
      LAYER M5 ;
        RECT  389.676 0 389.7 0.192 ;
    END
  END k_lo_d[546]
  PIN k_lo_d[547]
    DIRECTION INPUT ;
    USE SIGNAL ;
    PORT
      LAYER M5 ;
        RECT  390.396 0 390.42 0.192 ;
    END
  END k_lo_d[547]
  PIN k_lo_d[548]
    DIRECTION INPUT ;
    USE SIGNAL ;
    PORT
      LAYER M5 ;
        RECT  391.116 0 391.14 0.192 ;
    END
  END k_lo_d[548]
  PIN k_lo_d[549]
    DIRECTION INPUT ;
    USE SIGNAL ;
    PORT
      LAYER M5 ;
        RECT  391.836 0 391.86 0.192 ;
    END
  END k_lo_d[549]
  PIN k_lo_d[54]
    DIRECTION INPUT ;
    USE SIGNAL ;
    PORT
      LAYER M5 ;
        RECT  41.004 0 41.028 0.192 ;
    END
  END k_lo_d[54]
  PIN k_lo_d[550]
    DIRECTION INPUT ;
    USE SIGNAL ;
    PORT
      LAYER M5 ;
        RECT  392.508 0 392.532 0.192 ;
    END
  END k_lo_d[550]
  PIN k_lo_d[551]
    DIRECTION INPUT ;
    USE SIGNAL ;
    PORT
      LAYER M5 ;
        RECT  393.228 0 393.252 0.192 ;
    END
  END k_lo_d[551]
  PIN k_lo_d[552]
    DIRECTION INPUT ;
    USE SIGNAL ;
    PORT
      LAYER M5 ;
        RECT  393.948 0 393.972 0.192 ;
    END
  END k_lo_d[552]
  PIN k_lo_d[55]
    DIRECTION INPUT ;
    USE SIGNAL ;
    PORT
      LAYER M5 ;
        RECT  41.676 0 41.7 0.192 ;
    END
  END k_lo_d[55]
  PIN k_lo_d[56]
    DIRECTION INPUT ;
    USE SIGNAL ;
    PORT
      LAYER M5 ;
        RECT  42.396 0 42.42 0.192 ;
    END
  END k_lo_d[56]
  PIN k_lo_d[57]
    DIRECTION INPUT ;
    USE SIGNAL ;
    PORT
      LAYER M5 ;
        RECT  43.116 0 43.14 0.192 ;
    END
  END k_lo_d[57]
  PIN k_lo_d[58]
    DIRECTION INPUT ;
    USE SIGNAL ;
    PORT
      LAYER M5 ;
        RECT  43.836 0 43.86 0.192 ;
    END
  END k_lo_d[58]
  PIN k_lo_d[59]
    DIRECTION INPUT ;
    USE SIGNAL ;
    PORT
      LAYER M5 ;
        RECT  44.508 0 44.532 0.192 ;
    END
  END k_lo_d[59]
  PIN k_lo_d[5]
    DIRECTION INPUT ;
    USE SIGNAL ;
    PORT
      LAYER M5 ;
        RECT  6.252 0 6.276 0.192 ;
    END
  END k_lo_d[5]
  PIN k_lo_d[60]
    DIRECTION INPUT ;
    USE SIGNAL ;
    PORT
      LAYER M5 ;
        RECT  45.228 0 45.252 0.192 ;
    END
  END k_lo_d[60]
  PIN k_lo_d[61]
    DIRECTION INPUT ;
    USE SIGNAL ;
    PORT
      LAYER M5 ;
        RECT  45.948 0 45.972 0.192 ;
    END
  END k_lo_d[61]
  PIN k_lo_d[62]
    DIRECTION INPUT ;
    USE SIGNAL ;
    PORT
      LAYER M5 ;
        RECT  46.668 0 46.692 0.192 ;
    END
  END k_lo_d[62]
  PIN k_lo_d[63]
    DIRECTION INPUT ;
    USE SIGNAL ;
    PORT
      LAYER M5 ;
        RECT  47.388 0 47.412 0.192 ;
    END
  END k_lo_d[63]
  PIN k_lo_d[64]
    DIRECTION INPUT ;
    USE SIGNAL ;
    PORT
      LAYER M5 ;
        RECT  48.06 0 48.084 0.192 ;
    END
  END k_lo_d[64]
  PIN k_lo_d[65]
    DIRECTION INPUT ;
    USE SIGNAL ;
    PORT
      LAYER M5 ;
        RECT  48.78 0 48.804 0.192 ;
    END
  END k_lo_d[65]
  PIN k_lo_d[66]
    DIRECTION INPUT ;
    USE SIGNAL ;
    PORT
      LAYER M5 ;
        RECT  49.5 0 49.524 0.192 ;
    END
  END k_lo_d[66]
  PIN k_lo_d[67]
    DIRECTION INPUT ;
    USE SIGNAL ;
    PORT
      LAYER M5 ;
        RECT  50.22 0 50.244 0.192 ;
    END
  END k_lo_d[67]
  PIN k_lo_d[68]
    DIRECTION INPUT ;
    USE SIGNAL ;
    PORT
      LAYER M5 ;
        RECT  50.892 0 50.916 0.192 ;
    END
  END k_lo_d[68]
  PIN k_lo_d[69]
    DIRECTION INPUT ;
    USE SIGNAL ;
    PORT
      LAYER M5 ;
        RECT  51.612 0 51.636 0.192 ;
    END
  END k_lo_d[69]
  PIN k_lo_d[6]
    DIRECTION INPUT ;
    USE SIGNAL ;
    PORT
      LAYER M5 ;
        RECT  6.972 0 6.996 0.192 ;
    END
  END k_lo_d[6]
  PIN k_lo_d[70]
    DIRECTION INPUT ;
    USE SIGNAL ;
    PORT
      LAYER M5 ;
        RECT  52.332 0 52.356 0.192 ;
    END
  END k_lo_d[70]
  PIN k_lo_d[71]
    DIRECTION INPUT ;
    USE SIGNAL ;
    PORT
      LAYER M5 ;
        RECT  53.052 0 53.076 0.192 ;
    END
  END k_lo_d[71]
  PIN k_lo_d[72]
    DIRECTION INPUT ;
    USE SIGNAL ;
    PORT
      LAYER M5 ;
        RECT  53.724 0 53.748 0.192 ;
    END
  END k_lo_d[72]
  PIN k_lo_d[73]
    DIRECTION INPUT ;
    USE SIGNAL ;
    PORT
      LAYER M5 ;
        RECT  54.444 0 54.468 0.192 ;
    END
  END k_lo_d[73]
  PIN k_lo_d[74]
    DIRECTION INPUT ;
    USE SIGNAL ;
    PORT
      LAYER M5 ;
        RECT  55.164 0 55.188 0.192 ;
    END
  END k_lo_d[74]
  PIN k_lo_d[75]
    DIRECTION INPUT ;
    USE SIGNAL ;
    PORT
      LAYER M5 ;
        RECT  55.884 0 55.908 0.192 ;
    END
  END k_lo_d[75]
  PIN k_lo_d[76]
    DIRECTION INPUT ;
    USE SIGNAL ;
    PORT
      LAYER M5 ;
        RECT  56.556 0 56.58 0.192 ;
    END
  END k_lo_d[76]
  PIN k_lo_d[77]
    DIRECTION INPUT ;
    USE SIGNAL ;
    PORT
      LAYER M5 ;
        RECT  57.276 0 57.3 0.192 ;
    END
  END k_lo_d[77]
  PIN k_lo_d[78]
    DIRECTION INPUT ;
    USE SIGNAL ;
    PORT
      LAYER M5 ;
        RECT  57.996 0 58.02 0.192 ;
    END
  END k_lo_d[78]
  PIN k_lo_d[79]
    DIRECTION INPUT ;
    USE SIGNAL ;
    PORT
      LAYER M5 ;
        RECT  58.716 0 58.74 0.192 ;
    END
  END k_lo_d[79]
  PIN k_lo_d[7]
    DIRECTION INPUT ;
    USE SIGNAL ;
    PORT
      LAYER M5 ;
        RECT  7.692 0 7.716 0.192 ;
    END
  END k_lo_d[7]
  PIN k_lo_d[80]
    DIRECTION INPUT ;
    USE SIGNAL ;
    PORT
      LAYER M5 ;
        RECT  59.436 0 59.46 0.192 ;
    END
  END k_lo_d[80]
  PIN k_lo_d[81]
    DIRECTION INPUT ;
    USE SIGNAL ;
    PORT
      LAYER M5 ;
        RECT  60.108 0 60.132 0.192 ;
    END
  END k_lo_d[81]
  PIN k_lo_d[82]
    DIRECTION INPUT ;
    USE SIGNAL ;
    PORT
      LAYER M5 ;
        RECT  60.828 0 60.852 0.192 ;
    END
  END k_lo_d[82]
  PIN k_lo_d[83]
    DIRECTION INPUT ;
    USE SIGNAL ;
    PORT
      LAYER M5 ;
        RECT  61.548 0 61.572 0.192 ;
    END
  END k_lo_d[83]
  PIN k_lo_d[84]
    DIRECTION INPUT ;
    USE SIGNAL ;
    PORT
      LAYER M5 ;
        RECT  62.268 0 62.292 0.192 ;
    END
  END k_lo_d[84]
  PIN k_lo_d[85]
    DIRECTION INPUT ;
    USE SIGNAL ;
    PORT
      LAYER M5 ;
        RECT  62.94 0 62.964 0.192 ;
    END
  END k_lo_d[85]
  PIN k_lo_d[86]
    DIRECTION INPUT ;
    USE SIGNAL ;
    PORT
      LAYER M5 ;
        RECT  63.66 0 63.684 0.192 ;
    END
  END k_lo_d[86]
  PIN k_lo_d[87]
    DIRECTION INPUT ;
    USE SIGNAL ;
    PORT
      LAYER M5 ;
        RECT  64.38 0 64.404 0.192 ;
    END
  END k_lo_d[87]
  PIN k_lo_d[88]
    DIRECTION INPUT ;
    USE SIGNAL ;
    PORT
      LAYER M5 ;
        RECT  65.1 0 65.124 0.192 ;
    END
  END k_lo_d[88]
  PIN k_lo_d[89]
    DIRECTION INPUT ;
    USE SIGNAL ;
    PORT
      LAYER M5 ;
        RECT  65.772 0 65.796 0.192 ;
    END
  END k_lo_d[89]
  PIN k_lo_d[8]
    DIRECTION INPUT ;
    USE SIGNAL ;
    PORT
      LAYER M5 ;
        RECT  8.364 0 8.388 0.192 ;
    END
  END k_lo_d[8]
  PIN k_lo_d[90]
    DIRECTION INPUT ;
    USE SIGNAL ;
    PORT
      LAYER M5 ;
        RECT  66.492 0 66.516 0.192 ;
    END
  END k_lo_d[90]
  PIN k_lo_d[91]
    DIRECTION INPUT ;
    USE SIGNAL ;
    PORT
      LAYER M5 ;
        RECT  67.212 0 67.236 0.192 ;
    END
  END k_lo_d[91]
  PIN k_lo_d[92]
    DIRECTION INPUT ;
    USE SIGNAL ;
    PORT
      LAYER M5 ;
        RECT  67.932 0 67.956 0.192 ;
    END
  END k_lo_d[92]
  PIN k_lo_d[93]
    DIRECTION INPUT ;
    USE SIGNAL ;
    PORT
      LAYER M5 ;
        RECT  68.604 0 68.628 0.192 ;
    END
  END k_lo_d[93]
  PIN k_lo_d[94]
    DIRECTION INPUT ;
    USE SIGNAL ;
    PORT
      LAYER M5 ;
        RECT  69.324 0 69.348 0.192 ;
    END
  END k_lo_d[94]
  PIN k_lo_d[95]
    DIRECTION INPUT ;
    USE SIGNAL ;
    PORT
      LAYER M5 ;
        RECT  70.044 0 70.068 0.192 ;
    END
  END k_lo_d[95]
  PIN k_lo_d[96]
    DIRECTION INPUT ;
    USE SIGNAL ;
    PORT
      LAYER M5 ;
        RECT  70.764 0 70.788 0.192 ;
    END
  END k_lo_d[96]
  PIN k_lo_d[97]
    DIRECTION INPUT ;
    USE SIGNAL ;
    PORT
      LAYER M5 ;
        RECT  71.484 0 71.508 0.192 ;
    END
  END k_lo_d[97]
  PIN k_lo_d[98]
    DIRECTION INPUT ;
    USE SIGNAL ;
    PORT
      LAYER M5 ;
        RECT  72.156 0 72.18 0.192 ;
    END
  END k_lo_d[98]
  PIN k_lo_d[99]
    DIRECTION INPUT ;
    USE SIGNAL ;
    PORT
      LAYER M5 ;
        RECT  72.876 0 72.9 0.192 ;
    END
  END k_lo_d[99]
  PIN k_lo_d[9]
    DIRECTION INPUT ;
    USE SIGNAL ;
    PORT
      LAYER M5 ;
        RECT  9.084 0 9.108 0.192 ;
    END
  END k_lo_d[9]
  PIN k_lo_r
    DIRECTION OUTPUT ;
    USE SIGNAL ;
    PORT
      LAYER M7 ;
        RECT  2 0 2.032 0.192 ;
    END
  END k_lo_r
  PIN k_lo_v
    DIRECTION INPUT ;
    USE SIGNAL ;
    PORT
      LAYER M5 ;
        RECT  2.028 0 2.052 0.192 ;
    END
  END k_lo_v
  PIN k_rxv
    DIRECTION INPUT ;
    USE SIGNAL ;
    PORT
      LAYER M5 ;
        RECT  395.388 0 395.412 0.192 ;
    END
  END k_rxv
  PIN rst_n
    DIRECTION INPUT ;
    USE SIGNAL ;
    PORT
      LAYER M5 ;
        RECT  388.812 246.144 388.836 246.336 ;
    END
  END rst_n
  PIN VSS
    DIRECTION INOUT ;
    USE GROUND ;
    PORT
      LAYER M5 ;
        RECT  770.964 4.297 771.084 488.183 ;
        RECT  766.644 4.297 766.764 488.183 ;
        RECT  762.324 4.297 762.444 488.183 ;
        RECT  758.004 4.297 758.124 488.183 ;
        RECT  753.684 4.297 753.804 488.183 ;
        RECT  749.364 4.297 749.484 488.183 ;
        RECT  745.044 4.297 745.164 488.183 ;
        RECT  740.724 4.297 740.844 488.183 ;
        RECT  736.404 4.297 736.524 488.183 ;
        RECT  732.084 4.297 732.204 488.183 ;
        RECT  727.764 4.297 727.884 488.183 ;
        RECT  723.444 4.297 723.564 488.183 ;
        RECT  719.124 4.297 719.244 488.183 ;
        RECT  714.804 4.297 714.924 488.183 ;
        RECT  710.484 4.297 710.604 488.183 ;
        RECT  706.164 4.297 706.284 488.183 ;
        RECT  701.844 4.297 701.964 488.183 ;
        RECT  697.524 4.297 697.644 488.183 ;
        RECT  693.204 4.297 693.324 488.183 ;
        RECT  688.884 4.297 689.004 488.183 ;
        RECT  684.564 4.297 684.684 488.183 ;
        RECT  680.244 4.297 680.364 488.183 ;
        RECT  675.924 4.297 676.044 488.183 ;
        RECT  671.604 4.297 671.724 488.183 ;
        RECT  667.284 4.297 667.404 488.183 ;
        RECT  662.964 4.297 663.084 488.183 ;
        RECT  658.644 4.297 658.764 488.183 ;
        RECT  654.324 4.297 654.444 488.183 ;
        RECT  650.004 4.297 650.124 488.183 ;
        RECT  645.684 4.297 645.804 488.183 ;
        RECT  641.364 4.297 641.484 488.183 ;
        RECT  637.044 4.297 637.164 488.183 ;
        RECT  632.724 4.297 632.844 488.183 ;
        RECT  628.404 4.297 628.524 488.183 ;
        RECT  624.084 4.297 624.204 488.183 ;
        RECT  619.764 4.297 619.884 488.183 ;
        RECT  615.444 4.297 615.564 488.183 ;
        RECT  611.124 4.297 611.244 488.183 ;
        RECT  606.804 4.297 606.924 488.183 ;
        RECT  602.484 4.297 602.604 488.183 ;
        RECT  598.164 4.297 598.284 488.183 ;
        RECT  593.844 4.297 593.964 488.183 ;
        RECT  589.524 4.297 589.644 488.183 ;
        RECT  585.204 4.297 585.324 488.183 ;
        RECT  580.884 4.297 581.004 488.183 ;
        RECT  576.564 4.297 576.684 488.183 ;
        RECT  572.244 4.297 572.364 488.183 ;
        RECT  567.924 4.297 568.044 488.183 ;
        RECT  563.604 4.297 563.724 488.183 ;
        RECT  559.284 4.297 559.404 488.183 ;
        RECT  554.964 4.297 555.084 488.183 ;
        RECT  550.644 4.297 550.764 488.183 ;
        RECT  546.324 4.297 546.444 488.183 ;
        RECT  542.004 4.297 542.124 488.183 ;
        RECT  537.684 4.297 537.804 488.183 ;
        RECT  533.364 4.297 533.484 488.183 ;
        RECT  529.044 4.297 529.164 488.183 ;
        RECT  524.724 4.297 524.844 488.183 ;
        RECT  520.404 4.297 520.524 488.183 ;
        RECT  516.084 4.297 516.204 488.183 ;
        RECT  511.764 4.297 511.884 488.183 ;
        RECT  507.444 4.297 507.564 488.183 ;
        RECT  503.124 4.297 503.244 488.183 ;
        RECT  498.804 4.297 498.924 488.183 ;
        RECT  494.484 4.297 494.604 488.183 ;
        RECT  490.164 4.297 490.284 488.183 ;
        RECT  485.844 4.297 485.964 488.183 ;
        RECT  481.524 4.297 481.644 488.183 ;
        RECT  477.204 4.297 477.324 488.183 ;
        RECT  472.884 4.297 473.004 488.183 ;
        RECT  468.564 4.297 468.684 488.183 ;
        RECT  464.244 4.297 464.364 488.183 ;
        RECT  459.924 4.297 460.044 488.183 ;
        RECT  455.604 4.297 455.724 488.183 ;
        RECT  451.284 4.297 451.404 488.183 ;
        RECT  446.964 4.297 447.084 488.183 ;
        RECT  442.644 4.297 442.764 488.183 ;
        RECT  438.324 4.297 438.444 488.183 ;
        RECT  434.004 4.297 434.124 488.183 ;
        RECT  429.684 4.297 429.804 488.183 ;
        RECT  425.364 4.297 425.484 488.183 ;
        RECT  421.044 4.297 421.164 488.183 ;
        RECT  416.724 4.297 416.844 488.183 ;
        RECT  412.404 4.297 412.524 488.183 ;
        RECT  408.084 4.297 408.204 488.183 ;
        RECT  403.764 4.297 403.884 488.183 ;
        RECT  399.444 4.297 399.564 488.183 ;
        RECT  395.124 4.297 395.244 488.183 ;
        RECT  390.804 4.297 390.924 488.183 ;
        RECT  386.484 4.297 386.604 488.183 ;
        RECT  382.164 4.297 382.284 488.183 ;
        RECT  377.844 4.297 377.964 488.183 ;
        RECT  373.524 4.297 373.644 488.183 ;
        RECT  369.204 4.297 369.324 488.183 ;
        RECT  364.884 4.297 365.004 488.183 ;
        RECT  360.564 4.297 360.684 488.183 ;
        RECT  356.244 4.297 356.364 488.183 ;
        RECT  351.924 4.297 352.044 488.183 ;
        RECT  347.604 4.297 347.724 488.183 ;
        RECT  343.284 4.297 343.404 488.183 ;
        RECT  338.964 4.297 339.084 488.183 ;
        RECT  334.644 4.297 334.764 488.183 ;
        RECT  330.324 4.297 330.444 488.183 ;
        RECT  326.004 4.297 326.124 488.183 ;
        RECT  321.684 4.297 321.804 488.183 ;
        RECT  317.364 4.297 317.484 488.183 ;
        RECT  313.044 4.297 313.164 488.183 ;
        RECT  308.724 4.297 308.844 488.183 ;
        RECT  304.404 4.297 304.524 488.183 ;
        RECT  300.084 4.297 300.204 488.183 ;
        RECT  295.764 4.297 295.884 488.183 ;
        RECT  291.444 4.297 291.564 488.183 ;
        RECT  287.124 4.297 287.244 488.183 ;
        RECT  282.804 4.297 282.924 488.183 ;
        RECT  278.484 4.297 278.604 488.183 ;
        RECT  274.164 4.297 274.284 488.183 ;
        RECT  269.844 4.297 269.964 488.183 ;
        RECT  265.524 4.297 265.644 488.183 ;
        RECT  261.204 4.297 261.324 488.183 ;
        RECT  256.884 4.297 257.004 488.183 ;
        RECT  252.564 4.297 252.684 488.183 ;
        RECT  248.244 4.297 248.364 488.183 ;
        RECT  243.924 4.297 244.044 488.183 ;
        RECT  239.604 4.297 239.724 488.183 ;
        RECT  235.284 4.297 235.404 488.183 ;
        RECT  230.964 4.297 231.084 488.183 ;
        RECT  226.644 4.297 226.764 488.183 ;
        RECT  222.324 4.297 222.444 488.183 ;
        RECT  218.004 4.297 218.124 488.183 ;
        RECT  213.684 4.297 213.804 488.183 ;
        RECT  209.364 4.297 209.484 488.183 ;
        RECT  205.044 4.297 205.164 488.183 ;
        RECT  200.724 4.297 200.844 488.183 ;
        RECT  196.404 4.297 196.524 488.183 ;
        RECT  192.084 4.297 192.204 488.183 ;
        RECT  187.764 4.297 187.884 488.183 ;
        RECT  183.444 4.297 183.564 488.183 ;
        RECT  179.124 4.297 179.244 488.183 ;
        RECT  174.804 4.297 174.924 488.183 ;
        RECT  170.484 4.297 170.604 488.183 ;
        RECT  166.164 4.297 166.284 488.183 ;
        RECT  161.844 4.297 161.964 488.183 ;
        RECT  157.524 4.297 157.644 488.183 ;
        RECT  153.204 4.297 153.324 488.183 ;
        RECT  148.884 4.297 149.004 488.183 ;
        RECT  144.564 4.297 144.684 488.183 ;
        RECT  140.244 4.297 140.364 488.183 ;
        RECT  135.924 4.297 136.044 488.183 ;
        RECT  131.604 4.297 131.724 488.183 ;
        RECT  127.284 4.297 127.404 488.183 ;
        RECT  122.964 4.297 123.084 488.183 ;
        RECT  118.644 4.297 118.764 488.183 ;
        RECT  114.324 4.297 114.444 488.183 ;
        RECT  110.004 4.297 110.124 488.183 ;
        RECT  105.684 4.297 105.804 488.183 ;
        RECT  101.364 4.297 101.484 488.183 ;
        RECT  97.044 4.297 97.164 488.183 ;
        RECT  92.724 4.297 92.844 488.183 ;
        RECT  88.404 4.297 88.524 488.183 ;
        RECT  84.084 4.297 84.204 488.183 ;
        RECT  79.764 4.297 79.884 488.183 ;
        RECT  75.444 4.297 75.564 488.183 ;
        RECT  71.124 4.297 71.244 488.183 ;
        RECT  66.804 4.297 66.924 488.183 ;
        RECT  62.484 4.297 62.604 488.183 ;
        RECT  58.164 4.297 58.284 488.183 ;
        RECT  53.844 4.297 53.964 488.183 ;
        RECT  49.524 4.297 49.644 488.183 ;
        RECT  45.204 4.297 45.324 488.183 ;
        RECT  40.884 4.297 41.004 488.183 ;
        RECT  36.564 4.297 36.684 488.183 ;
        RECT  32.244 4.297 32.364 488.183 ;
        RECT  27.924 4.297 28.044 488.183 ;
        RECT  23.604 4.297 23.724 488.183 ;
        RECT  19.284 4.297 19.404 488.183 ;
        RECT  14.964 4.297 15.084 488.183 ;
        RECT  10.644 4.297 10.764 488.183 ;
        RECT  6.324 4.297 6.444 488.183 ;
    END
  END VSS
  PIN VDD
    DIRECTION INOUT ;
    USE POWER ;
    PORT
      LAYER M5 ;
        RECT  771.156 4.311 771.276 488.169 ;
        RECT  766.836 4.311 766.956 488.169 ;
        RECT  762.516 4.311 762.636 488.169 ;
        RECT  758.196 4.311 758.316 488.169 ;
        RECT  753.876 4.311 753.996 488.169 ;
        RECT  749.556 4.311 749.676 488.169 ;
        RECT  745.236 4.311 745.356 488.169 ;
        RECT  740.916 4.311 741.036 488.169 ;
        RECT  736.596 4.311 736.716 488.169 ;
        RECT  732.276 4.311 732.396 488.169 ;
        RECT  727.956 4.311 728.076 488.169 ;
        RECT  723.636 4.311 723.756 488.169 ;
        RECT  719.316 4.311 719.436 488.169 ;
        RECT  714.996 4.311 715.116 488.169 ;
        RECT  710.676 4.311 710.796 488.169 ;
        RECT  706.356 4.311 706.476 488.169 ;
        RECT  702.036 4.311 702.156 488.169 ;
        RECT  697.716 4.311 697.836 488.169 ;
        RECT  693.396 4.311 693.516 488.169 ;
        RECT  689.076 4.311 689.196 488.169 ;
        RECT  684.756 4.311 684.876 488.169 ;
        RECT  680.436 4.311 680.556 488.169 ;
        RECT  676.116 4.311 676.236 488.169 ;
        RECT  671.796 4.311 671.916 488.169 ;
        RECT  667.476 4.311 667.596 488.169 ;
        RECT  663.156 4.311 663.276 488.169 ;
        RECT  658.836 4.311 658.956 488.169 ;
        RECT  654.516 4.311 654.636 488.169 ;
        RECT  650.196 4.311 650.316 488.169 ;
        RECT  645.876 4.311 645.996 488.169 ;
        RECT  641.556 4.311 641.676 488.169 ;
        RECT  637.236 4.311 637.356 488.169 ;
        RECT  632.916 4.311 633.036 488.169 ;
        RECT  628.596 4.311 628.716 488.169 ;
        RECT  624.276 4.311 624.396 488.169 ;
        RECT  619.956 4.311 620.076 488.169 ;
        RECT  615.636 4.311 615.756 488.169 ;
        RECT  611.316 4.311 611.436 488.169 ;
        RECT  606.996 4.311 607.116 488.169 ;
        RECT  602.676 4.311 602.796 488.169 ;
        RECT  598.356 4.311 598.476 488.169 ;
        RECT  594.036 4.311 594.156 488.169 ;
        RECT  589.716 4.311 589.836 488.169 ;
        RECT  585.396 4.311 585.516 488.169 ;
        RECT  581.076 4.311 581.196 488.169 ;
        RECT  576.756 4.311 576.876 488.169 ;
        RECT  572.436 4.311 572.556 488.169 ;
        RECT  568.116 4.311 568.236 488.169 ;
        RECT  563.796 4.311 563.916 488.169 ;
        RECT  559.476 4.311 559.596 488.169 ;
        RECT  555.156 4.311 555.276 488.169 ;
        RECT  550.836 4.311 550.956 488.169 ;
        RECT  546.516 4.311 546.636 488.169 ;
        RECT  542.196 4.311 542.316 488.169 ;
        RECT  537.876 4.311 537.996 488.169 ;
        RECT  533.556 4.311 533.676 488.169 ;
        RECT  529.236 4.311 529.356 488.169 ;
        RECT  524.916 4.311 525.036 488.169 ;
        RECT  520.596 4.311 520.716 488.169 ;
        RECT  516.276 4.311 516.396 488.169 ;
        RECT  511.956 4.311 512.076 488.169 ;
        RECT  507.636 4.311 507.756 488.169 ;
        RECT  503.316 4.311 503.436 488.169 ;
        RECT  498.996 4.311 499.116 488.169 ;
        RECT  494.676 4.311 494.796 488.169 ;
        RECT  490.356 4.311 490.476 488.169 ;
        RECT  486.036 4.311 486.156 488.169 ;
        RECT  481.716 4.311 481.836 488.169 ;
        RECT  477.396 4.311 477.516 488.169 ;
        RECT  473.076 4.311 473.196 488.169 ;
        RECT  468.756 4.311 468.876 488.169 ;
        RECT  464.436 4.311 464.556 488.169 ;
        RECT  460.116 4.311 460.236 488.169 ;
        RECT  455.796 4.311 455.916 488.169 ;
        RECT  451.476 4.311 451.596 488.169 ;
        RECT  447.156 4.311 447.276 488.169 ;
        RECT  442.836 4.311 442.956 488.169 ;
        RECT  438.516 4.311 438.636 488.169 ;
        RECT  434.196 4.311 434.316 488.169 ;
        RECT  429.876 4.311 429.996 488.169 ;
        RECT  425.556 4.311 425.676 488.169 ;
        RECT  421.236 4.311 421.356 488.169 ;
        RECT  416.916 4.311 417.036 488.169 ;
        RECT  412.596 4.311 412.716 488.169 ;
        RECT  408.276 4.311 408.396 488.169 ;
        RECT  403.956 4.311 404.076 488.169 ;
        RECT  399.636 4.311 399.756 488.169 ;
        RECT  395.316 4.311 395.436 488.169 ;
        RECT  390.996 4.311 391.116 488.169 ;
        RECT  386.676 4.311 386.796 488.169 ;
        RECT  382.356 4.311 382.476 488.169 ;
        RECT  378.036 4.311 378.156 488.169 ;
        RECT  373.716 4.311 373.836 488.169 ;
        RECT  369.396 4.311 369.516 488.169 ;
        RECT  365.076 4.311 365.196 488.169 ;
        RECT  360.756 4.311 360.876 488.169 ;
        RECT  356.436 4.311 356.556 488.169 ;
        RECT  352.116 4.311 352.236 488.169 ;
        RECT  347.796 4.311 347.916 488.169 ;
        RECT  343.476 4.311 343.596 488.169 ;
        RECT  339.156 4.311 339.276 488.169 ;
        RECT  334.836 4.311 334.956 488.169 ;
        RECT  330.516 4.311 330.636 488.169 ;
        RECT  326.196 4.311 326.316 488.169 ;
        RECT  321.876 4.311 321.996 488.169 ;
        RECT  317.556 4.311 317.676 488.169 ;
        RECT  313.236 4.311 313.356 488.169 ;
        RECT  308.916 4.311 309.036 488.169 ;
        RECT  304.596 4.311 304.716 488.169 ;
        RECT  300.276 4.311 300.396 488.169 ;
        RECT  295.956 4.311 296.076 488.169 ;
        RECT  291.636 4.311 291.756 488.169 ;
        RECT  287.316 4.311 287.436 488.169 ;
        RECT  282.996 4.311 283.116 488.169 ;
        RECT  278.676 4.311 278.796 488.169 ;
        RECT  274.356 4.311 274.476 488.169 ;
        RECT  270.036 4.311 270.156 488.169 ;
        RECT  265.716 4.311 265.836 488.169 ;
        RECT  261.396 4.311 261.516 488.169 ;
        RECT  257.076 4.311 257.196 488.169 ;
        RECT  252.756 4.311 252.876 488.169 ;
        RECT  248.436 4.311 248.556 488.169 ;
        RECT  244.116 4.311 244.236 488.169 ;
        RECT  239.796 4.311 239.916 488.169 ;
        RECT  235.476 4.311 235.596 488.169 ;
        RECT  231.156 4.311 231.276 488.169 ;
        RECT  226.836 4.311 226.956 488.169 ;
        RECT  222.516 4.311 222.636 488.169 ;
        RECT  218.196 4.311 218.316 488.169 ;
        RECT  213.876 4.311 213.996 488.169 ;
        RECT  209.556 4.311 209.676 488.169 ;
        RECT  205.236 4.311 205.356 488.169 ;
        RECT  200.916 4.311 201.036 488.169 ;
        RECT  196.596 4.311 196.716 488.169 ;
        RECT  192.276 4.311 192.396 488.169 ;
        RECT  187.956 4.311 188.076 488.169 ;
        RECT  183.636 4.311 183.756 488.169 ;
        RECT  179.316 4.311 179.436 488.169 ;
        RECT  174.996 4.311 175.116 488.169 ;
        RECT  170.676 4.311 170.796 488.169 ;
        RECT  166.356 4.311 166.476 488.169 ;
        RECT  162.036 4.311 162.156 488.169 ;
        RECT  157.716 4.311 157.836 488.169 ;
        RECT  153.396 4.311 153.516 488.169 ;
        RECT  149.076 4.311 149.196 488.169 ;
        RECT  144.756 4.311 144.876 488.169 ;
        RECT  140.436 4.311 140.556 488.169 ;
        RECT  136.116 4.311 136.236 488.169 ;
        RECT  131.796 4.311 131.916 488.169 ;
        RECT  127.476 4.311 127.596 488.169 ;
        RECT  123.156 4.311 123.276 488.169 ;
        RECT  118.836 4.311 118.956 488.169 ;
        RECT  114.516 4.311 114.636 488.169 ;
        RECT  110.196 4.311 110.316 488.169 ;
        RECT  105.876 4.311 105.996 488.169 ;
        RECT  101.556 4.311 101.676 488.169 ;
        RECT  97.236 4.311 97.356 488.169 ;
        RECT  92.916 4.311 93.036 488.169 ;
        RECT  88.596 4.311 88.716 488.169 ;
        RECT  84.276 4.311 84.396 488.169 ;
        RECT  79.956 4.311 80.076 488.169 ;
        RECT  75.636 4.311 75.756 488.169 ;
        RECT  71.316 4.311 71.436 488.169 ;
        RECT  66.996 4.311 67.116 488.169 ;
        RECT  62.676 4.311 62.796 488.169 ;
        RECT  58.356 4.311 58.476 488.169 ;
        RECT  54.036 4.311 54.156 488.169 ;
        RECT  49.716 4.311 49.836 488.169 ;
        RECT  45.396 4.311 45.516 488.169 ;
        RECT  41.076 4.311 41.196 488.169 ;
        RECT  36.756 4.311 36.876 488.169 ;
        RECT  32.436 4.311 32.556 488.169 ;
        RECT  28.116 4.311 28.236 488.169 ;
        RECT  23.796 4.311 23.916 488.169 ;
        RECT  19.476 4.311 19.596 488.169 ;
        RECT  15.156 4.311 15.276 488.169 ;
        RECT  10.836 4.311 10.956 488.169 ;
        RECT  6.516 4.311 6.636 488.169 ;
    END
  END VDD
  OBS
    LAYER RVTN ;
     RECT  0 0 773.28 488.183 ;
    LAYER RVTP ;
     RECT  0 0 773.28 488.183 ;
    LAYER M1 ;
     RECT  0 0 773.28 488.183 ;
    LAYER M2 ;
     RECT  0 0 773.28 488.183 ;
    LAYER M3 ;
     RECT  0 0 773.28 488.183 ;
    LAYER M4 ;
     RECT  0 0 773.28 488.183 ;
    LAYER M5 ;
     RECT  0 0 773.28 488.183 ;
    LAYER M6 ;
     RECT  0 0 773.28 488.183 ;
    LAYER M7 ;
     RECT  0 0 773.28 488.183 ;
  END
END ot_s81hd_lep_pair
END LIBRARY
